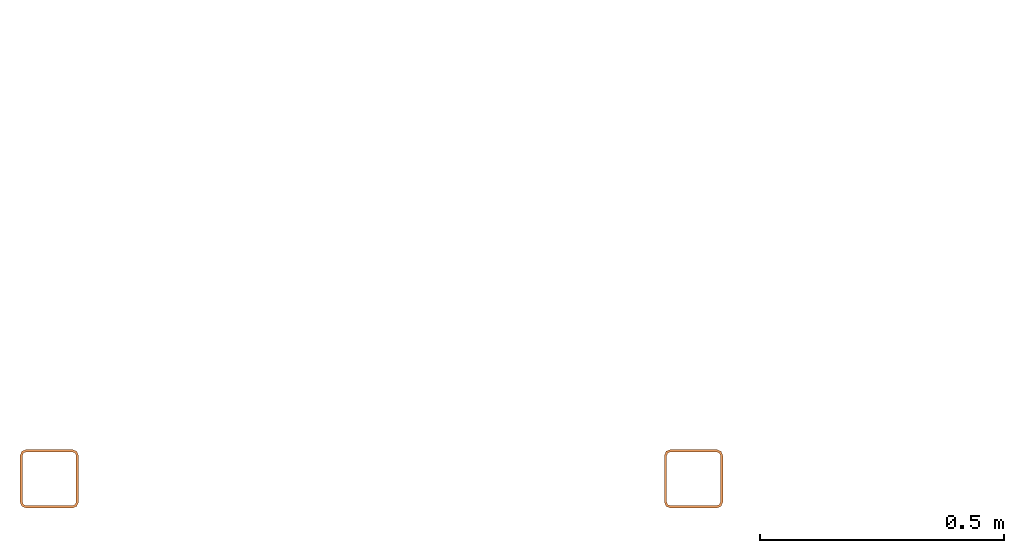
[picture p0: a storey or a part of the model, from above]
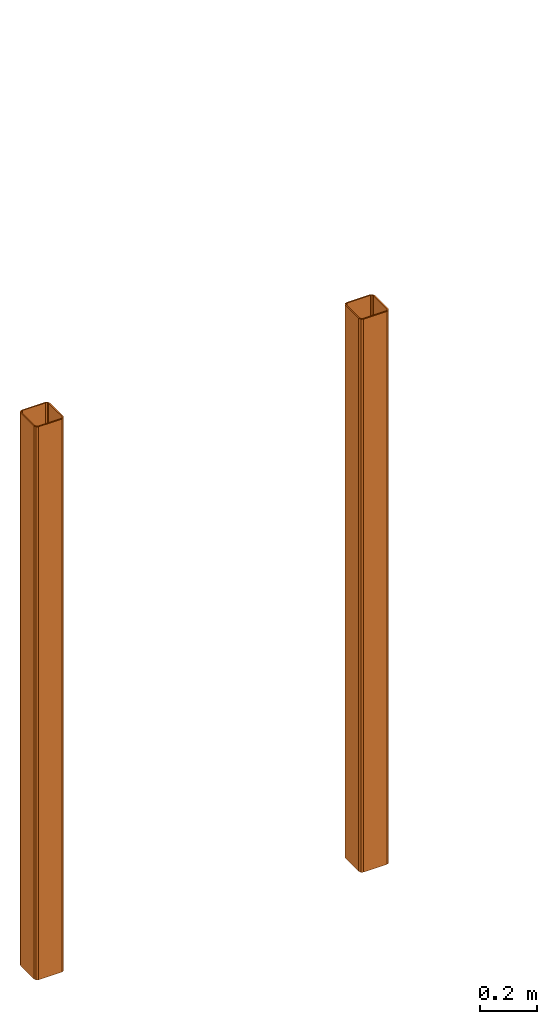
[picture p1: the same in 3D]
Properties of the parts of a building model (IFC2X3), part 1 of 7

# File
Description: ViewDefinition [CoordinationView_V2.0, SurfaceGeometryAddOnView, QuantityTakeOffAddOnView, SpaceBoundary2ndLevelAddOnView], Option [Elements to export: Visible elements (on all stories)], Option [Partial Structure Display: Entire Model], Option [IFC Domain: Custom], Option [Structural Function: All Elements], Option [Convert Grid elements: On], Option [Convert IFC Annotations and Archicad 2D elements: Off], Option [Convert 2D symbols of Doors and Windows: Off], Option [Export geometries that Participates in Collision Detection only: Off], Option [Split complex elements: Off], Option [Material Preservation: Explode all], Option [IFC Model position: Survey Point and Project Origin], Option [Curtain Wall export mode: Container Element], Option [Railing export mode: Single Element], Option [Stair export mode: Single Element], Option [Properties To Export: All properties], Option [Space containment: Off], Option [Geometry to type objects: Off], Option [Element Properties: Off], Option [Building Material Properties: Off], Option [Element Parameters: Off], Option [Component Parameters: Off], Option [IFC Base Quantities: On], Option [Door Window Parameters: Off], Option [IFC Space boundaries: On], Option [Archicad Zone Categories as IFC Space classification data: Off], Option [Element Classifications: On]
File name: C:\Users\Tarmo\Innopolis Insenerid OÜ\IPI-2406_Kuressaare Ametikooli õppekorpus - General\CDE\03. JAGATUD\03.6. Coordination model\Submodels\TUUL_PP_AR_9-01_v02_2025-01-06.ifc
Time: 2025-01-10T17:22:18
Author: Architect
Organization: Building Designer Office
Written by: DDS_IFC v3.0
Made in: IFC file generated by Graphisoft Archicad 27.0.0 INT FULL Windows version (IFC add-on version: 5060 INT FULL).
Authorization: The authorising person

# IfcSite, 43301:001:0844
RefLatitude: 58, 16, 38, 603000; RefLongitude: 22, 32, 58, 47000; RefElevation: 8650 mm
BaseQuantities - GrossPerimeter: 0 mm; GrossArea: 47243 m2
AR_Kinnistu - 015_Ehitatav-pindala: 0 m2; 010_Katastritunnus: 43301:001:0844; 020_Pindala: 47243 m2

# IfcBuilding, Kuressaare Ametikooli tuulikute mehaanikute õppekorpus
BaseQuantities - GrossFloorArea: 4647.95 m2
AR_Hoone - 035_Sprinkler: no; 706_Eripõlemiskoormus: 0; 703_Kasutajate-arv: 0; 055_Neto-ruumala: 0 m3; 050_Neto-pindala: 0 m2; 041_Sügavus: 0 mm; 707_Tuleohutusklass: TP1, TP2, TP3; 001_Nimetus: Kuressaare Ametikooli tuulikute mehaanikute õppekorpus; 030_Hoone-aadress: Kooli tee 7, Upa küla, Saaremaa vald, Saare maakond; 704_Kasutusotstarve: Kutseõppeasutuse õppehoone; 705_Kasutusotstarbe-kood: 12633; 700_EHR-kood: 106001153; 045_Hoonealune-pindala: 4167 m2; 702_ADS-OID: ME01729794; 701_ETAK-id: 188703; 040_Kõrgus: 9000 mm

# IfcBuildingStorey (5)
In: Kuressaare Ametikooli tuulikute mehaanikute õppekorpus
Name | Elevation (mm) | NetHeight (mm) = GrossHeight (mm) = Height (mm) | GrossFloorArea (m2) | 070_Maapealne | 065_Korruse-number | 060_Korruse-nimi | 710_Määrusejärgne-korrus
1.korrus | 0 | 4100 | 3425.05 | yes | 1 | 1.korrus | yes
Merepind | -8650 | 8650 | 0
2.korrus | 4100 | 3700 | 1071.13 | yes | 2 | 2.korrus | yes
Pööningukorrus | 7800 | 3500 | 151.772 | yes | 3 | Katus | no
Katuseplaan | 11300 | 3500 | 0

# IfcSpace: Kab. (6)
In: 2.korrus
InteriorOrExteriorSpace: INTERNAL; Classification: 1.21 IfcSpaceType (ruum) (IPI ÜBN)
AR_Ruum - 115_Kategooria: Kab.; 110_Tüüp: ootel; 125_Turvatsoon: -; 720_Köetav-pind: no; 721_Toatemperatuuriga-pind: no; 722_Eluruumi-number: ootel; 723_Mitteeluruumi-number: ootel
BaseQuantities - FinishFloorHeight: 0 mm
AC_Pset_RenovationAndPhasing - Renovation Status: New
Name | LongName = 100_Nimi | 105_Number | 120_Pindala (m2) = GrossFloorArea (m2) = GrossCeilingArea (m2) | Height (mm) = FinishCeilingHeight (mm) = ClearHeight (mm) | NetFloorArea (m2) = SpaceNetFloorAreaBOMA (m2) = SpaceUsableFloorAreaBOMA (m2) = NetCeilingArea (m2) | GrossWallArea (m2) | NetWallArea (m2) | GrossPerimeter (mm) = NetPerimeter (mm) | GrossVolume (m3) | NetVolume (m3)
214 | Juhtõp. | 214 | 15.5472 | 4832.72 | 15.5472 | 67.4028 | 53.6942 | 15787.1 | 75.1353 | 64.8385
213 | Õpet.töör. | 213 | 65.2246 | 5620.76 | 65.0646 | 126.323 | 91.2781 | 35727.6 | 366.612 | 196.593
212 | Proj.juht | 212 | 18.7481 | 4709.86 | 18.7481 | 55.9863 | 52.1281 | 17414.3 | 88.301 | 78.5045
203 | Rühmajuh.I | 203 | 11.839 | 5316.65 | 11.839 | 61.2238 | 51.4993 | 14292 | 62.9436 | 51.8169
204 | Rühmajuh. II | 204 | 11.839 | 5316.65 | 11.7326 | 59.816 | 51.0555 | 14292 | 62.9436 | 51.8169
205 | Sots.ped. | 205 | 11.839 | 5316.65 | 11.839 | 60.6815 | 50.957 | 14292 | 62.9436 | 51.8169

# IfcSpace: Klassid (12)
InteriorOrExteriorSpace: INTERNAL; Classification: 1.21 IfcSpaceType (ruum) (IPI ÜBN)
AR_Ruum - 115_Kategooria: Klassid; 110_Tüüp: ootel; 125_Turvatsoon: -; 720_Köetav-pind: no; 721_Toatemperatuuriga-pind: no; 722_Eluruumi-number: ootel; 723_Mitteeluruumi-number: ootel
AC_Pset_RenovationAndPhasing - Renovation Status: New
Name | In | LongName = 100_Nimi | 105_Number | 120_Pindala (m2) = GrossFloorArea (m2) = GrossCeilingArea (m2) | Height (mm) = FinishCeilingHeight (mm) = ClearHeight (mm) | FinishFloorHeight (mm) | NetFloorArea (m2) = SpaceNetFloorAreaBOMA (m2) = SpaceUsableFloorAreaBOMA (m2) = NetCeilingArea (m2) | GrossWallArea (m2) | NetWallArea (m2) | GrossPerimeter (mm) = NetPerimeter (mm) | GrossVolume (m3) | NetVolume (m3)
124 | 1.korrus | Ehituse õppet. | 124 | 128.364 | 3530 | 0 | 128.364 | 175.484 | 148.077 | 46438.7 | 453.124 | 453.124
136 | 1.korrus | Materj.õppet. | 136 | 209.933 | 3530 | 0 | 209.933 | 213.037 | 168.591 | 60294.5 | 741.062 | 741.062
133 | 1.korrus | Meh. ja hüdraulika õppet. | 133 | 169.978 | 3530 | 0 | 169.978 | 149.826 | 122.568 | 60117.8 | 600.021 | 600.021
227 | 2.korrus | Elektri õppet. | 227 | 174.42 | 3080 | 0 | 174.068 | 162.623 | 118.572 | 54042.9 | 537.214 | 537.214
221 | 2.korrus | Arvutiklass I | 221 | 48.4192 | 3160 | 100 | 48.4192 | 95.3215 | 74.7578 | 27850.1 | 153.005 | 153.005
219 | 2.korrus | Arvutiklass II | 219 | 48.887 | 5507.49 | 100 | 48.887 | 106.767 | 95.2312 | 27986.1 | 269.245 | 221.758
218 | 2.korrus | Õppeklass I | 218 | 48.9607 | 5607.49 | 0 | 48.9607 | 115.023 | 103.487 | 28006.4 | 274.546 | 226.989
216 | 2.korrus | MF projektiõppeklass | 216 | 69.0252 | 5607.49 | 0 | 69.0252 | 134.472 | 113.37 | 33588.2 | 387.058 | 319.853
217 | 2.korrus | Õppeklass II | 217 | 47.8731 | 5607.49 | 0 | 47.8731 | 113.927 | 104.08 | 27706.4 | 268.448 | 221.947
202 | 2.korrus | Rühmatöö r.1 | 202 | 17.0366 | 5316.65 | 0 | 17.0366 | 45.8756 | 34.177 | 16623.6 | 90.5779 | 74.184
222 | 2.korrus | CNC ruum | 222 | 24.6906 | 3160 | 100 | 24.5306 | 65.9562 | 57.5719 | 20273 | 78.0223 | 78.0223
215 | 2.korrus | Rühmatöö r.2 | 215 | 31.0674 | 3260 | 0 | 31.0672 | 53.4095 | 40.4372 | 23806.7 | 101.28 | 101.28

# IfcSpace: generic (2)
In: 1.korrus
LongName: Ruum?; InteriorOrExteriorSpace: INTERNAL; Classification: 1.21 IfcSpaceType (ruum) (IPI ÜBN)
AR_Ruum - 100_Nimi: Ruum?; 105_Number: XXX; 115_Kategooria: generic; 110_Tüüp: Üüritav pind; 125_Turvatsoon: -; 720_Köetav-pind: yes; 721_Toatemperatuuriga-pind: yes; 722_Eluruumi-number: -; 723_Mitteeluruumi-number: ootel
AC_Pset_RenovationAndPhasing - Renovation Status: Existing
BaseQuantities - FinishFloorHeight: 0 mm
Name | 120_Pindala (m2) = GrossFloorArea (m2) = NetFloorArea (m2) = SpaceNetFloorAreaBOMA (m2) = SpaceUsableFloorAreaBOMA (m2) = GrossCeilingArea (m2) = NetCeilingArea (m2) | Height (mm) = FinishCeilingHeight (mm) = ClearHeight (mm) | GrossWallArea (m2) | NetWallArea (m2) | GrossPerimeter (mm) = NetPerimeter (mm) | GrossVolume (m3) = NetVolume (m3)
XXX | 2.66552 | 2220 | 13.4844 | 11.9864 | 6590.37 | 5.91745
XXX | 1.59067 | 2300 | 13.2955 | 9.93989 | 5143.43 | 3.65853

# IfcSpace: klass, 145
In: 1.korrus
LongName: Õppeklass; InteriorOrExteriorSpace: INTERNAL; Classification: 1.21 IfcSpaceType (ruum) (IPI ÜBN)
AR_Ruum - 100_Nimi: Õppeklass; 105_Number: 145; 115_Kategooria: klass; 110_Tüüp: Üüritav pind; 120_Pindala: 75.8065 m2; 125_Turvatsoon: -; 720_Köetav-pind: yes; 721_Toatemperatuuriga-pind: yes; 722_Eluruumi-number: -; 723_Mitteeluruumi-number: ootel
AC_Pset_RenovationAndPhasing - Renovation Status: Existing
BaseQuantities - Height: 2760 mm; FinishCeilingHeight: 2760 mm; FinishFloorHeight: 0 mm; ClearHeight: 2760 mm; GrossFloorArea: 75.8065 m2; NetFloorArea: 75.8065 m2; SpaceNetFloorAreaBOMA: 75.8065 m2; SpaceUsableFloorAreaBOMA: 75.8065 m2; GrossCeilingArea: 75.8065 m2; NetCeilingArea: 75.8065 m2; GrossWallArea: 101.496 m2; NetWallArea: 79.8456 m2; GrossPerimeter: 39606.3 mm; NetPerimeter: 39606.3 mm; GrossVolume: 209.226 m3; NetVolume: 209.226 m3

# IfcSpace: ladu (5)
In: 1.korrus
InteriorOrExteriorSpace: INTERNAL; Classification: 1.21 IfcSpaceType (ruum) (IPI ÜBN)
AR_Ruum - 115_Kategooria: ladu; 110_Tüüp: Üüritav pind; 125_Turvatsoon: -; 720_Köetav-pind: yes; 721_Toatemperatuuriga-pind: yes; 722_Eluruumi-number: -; 723_Mitteeluruumi-number: ootel
AC_Pset_RenovationAndPhasing - Renovation Status: Existing
BaseQuantities - FinishFloorHeight: 0 mm
Name | LongName = 100_Nimi | 105_Number | 120_Pindala (m2) = GrossFloorArea (m2) = NetFloorArea (m2) = SpaceNetFloorAreaBOMA (m2) = SpaceUsableFloorAreaBOMA (m2) = GrossCeilingArea (m2) = NetCeilingArea (m2) | Height (mm) = FinishCeilingHeight (mm) = ClearHeight (mm) | GrossWallArea (m2) | NetWallArea (m2) | GrossPerimeter (mm) = NetPerimeter (mm) | GrossVolume (m3) | NetVolume (m3)
XXX | Ladu? | XXX | 15.1071 | 4030 | 54.9288 | 47.1488 | 16928.5 | 60.8818 | 44.7367
XXX | Vormide ladu? | XXX | 50.5027 | 4030 | 95.6878 | 82.443 | 28913.5 | 203.526 | 149.241
147 | Ladu | 147 | 41.6107 | 3410 | 84.8329 | 72.6079 | 26062.7 | 141.892 | 141.892
XXX | Kemikaalide ladu? | XXX | 9.49683 | 4030 | 35.4408 | 33.4038 | 12633.1 | 38.2722 | 27.1318
1 163 | Saal | 1 163 | 121.686 | 2580 | 40.6575 | 35.7675 | 51884 | 313.95 | 313.95

# IfcSpace: liftiruum (2)
LongName: Lift; InteriorOrExteriorSpace: INTERNAL; Classification: 1.21 IfcSpaceType (ruum) (IPI ÜBN)
AC_Pset_RenovationAndPhasing - Renovation Status: New
BaseQuantities - FinishFloorHeight: 0 mm
AR_Ruum - 100_Nimi: Lift; 115_Kategooria: liftiruum; 110_Tüüp: ootel; 125_Turvatsoon: -; 720_Köetav-pind: no; 721_Toatemperatuuriga-pind: no; 722_Eluruumi-number: ootel; 723_Mitteeluruumi-number: ootel
Name | In | Height (mm) = FinishCeilingHeight (mm) = ClearHeight (mm) | GrossFloorArea (m2) = NetFloorArea (m2) = SpaceNetFloorAreaBOMA (m2) = SpaceUsableFloorAreaBOMA (m2) = GrossCeilingArea (m2) = NetCeilingArea (m2) = 120_Pindala (m2) | GrossWallArea (m2) | NetWallArea (m2) | GrossPerimeter (mm) = NetPerimeter (mm) | GrossVolume (m3) = NetVolume (m3) | 105_Number
134 | 1.korrus | 3530 | 2.1987 | 5.60755 | 5.60755 | 5946.03 | 7.76142 | 134
229 | 2.korrus | 3260 | 2.1942 | 15.3783 | 9.92735 | 5940 | 7.15309 | 229

# IfcSpace: muud abiruumid (17)
InteriorOrExteriorSpace: INTERNAL; Classification: 1.21 IfcSpaceType (ruum) (IPI ÜBN)
AR_Ruum - 115_Kategooria: muud abiruumid; 110_Tüüp: ootel; 125_Turvatsoon: -; 720_Köetav-pind: no; 721_Toatemperatuuriga-pind: no; 722_Eluruumi-number: ootel; 723_Mitteeluruumi-number: ootel
AC_Pset_RenovationAndPhasing - Renovation Status: New
Name | In | LongName = 100_Nimi | 105_Number | 120_Pindala (m2) = GrossFloorArea (m2) = NetFloorArea (m2) = SpaceNetFloorAreaBOMA (m2) = SpaceUsableFloorAreaBOMA (m2) = GrossCeilingArea (m2) = NetCeilingArea (m2) | Height (mm) = FinishCeilingHeight (mm) = ClearHeight (mm) | FinishFloorHeight (mm) | GrossWallArea (m2) | NetWallArea (m2) | GrossPerimeter (mm) = NetPerimeter (mm) | GrossVolume (m3) | NetVolume (m3)
128 | 1.korrus | Riietusr. | 128 | 12.7353 | 3530 | 0 | 36.8075 | 34.8874 | 14879.5 | 44.9558 | 44.9558
141 | 1.korrus | Riietusr. | 141 | 10.806 | 3410 | 100 | 42.1717 | 38.5425 | 13241.5 | 36.8483 | 36.8483
142 | 1.korrus | Ladu | 142 | 3.26359 | 3530 | 0 | 26.255 | 24.1239 | 7437.67 | 11.5205 | 11.5205
126 | 1.korrus | Dush | 126 | 1.85755 | 3530 | 0 | 25.5378 | 22.1196 | 5457.77 | 6.55714 | 6.55714
132 | 1.korrus | Inva WC-dush | 132 | 5.7189 | 3530 | 0 | 56.8181 | 52.5559 | 9575.12 | 20.1877 | 20.1877
138 | 1.korrus | Riietusr. | 138 | 10.8131 | 3410 | 0 | 52.5033 | 38.1641 | 13281.5 | 36.8728 | 36.8728
131 | 1.korrus | Riietusr. | 131 | 12.7361 | 3530 | 0 | 35.6885 | 30.3502 | 14880.1 | 44.9584 | 44.9584
125 | 1.korrus | Riietusr. | 125 | 12.7359 | 3530 | 0 | 26.7574 | 21.4191 | 14880 | 44.9577 | 44.9577
211 | 2.korrus | Riietusr. | 211 | 22.0602 | 5699.93 | 0 | 77.5498 | 72.0005 | 18925.9 | 125.742 | 97.4836
207 | 2.korrus | Riietusr. | 207 | 11.0927 | 5316.65 | 0 | 55.0914 | 49.5421 | 14025.8 | 58.9758 | 43.5537
206 | 2.korrus | Pesur. | 206 | 4.07837 | 4545.32 | 0 | 50.5629 | 47.1447 | 8235.76 | 18.5375 | 16.4192
225 | 2.korrus | WC | 225 | 1.30192 | 3260 | 0 | 25.7928 | 22.3746 | 4611.35 | 4.24425 | 4.24425
224 | 2.korrus | WC | 224 | 1.1583 | 3260 | 0 | 24.1716 | 20.7534 | 4306 | 3.77606 | 3.77606
223 | 2.korrus | WC | 223 | 1.15382 | 3160 | 100 | 23.598 | 20.1798 | 4330.07 | 3.64608 | 3.64608
210 | 2.korrus | Pesur. | 210 | 4.94948 | 3290 | 0 | 51.9261 | 48.5079 | 9079.96 | 16.2838 | 16.2838
208 | 2.korrus | WC | 208 | 1.42991 | 3290 | 0 | 28.4622 | 25.044 | 4977.57 | 4.7044 | 4.7044
209 | 2.korrus | WC | 209 | 1.96683 | 3290 | 0 | 32.4987 | 29.0805 | 5678.04 | 6.47086 | 6.47086

# IfcSpace: muud üldruumid (13)
In: 1.korrus
InteriorOrExteriorSpace: INTERNAL; Classification: 1.21 IfcSpaceType (ruum) (IPI ÜBN)
AR_Ruum - 115_Kategooria: muud üldruumid; 110_Tüüp: ootel; 125_Turvatsoon: -; 720_Köetav-pind: no; 721_Toatemperatuuriga-pind: no; 722_Eluruumi-number: ootel; 723_Mitteeluruumi-number: ootel
AC_Pset_RenovationAndPhasing - Renovation Status: New
BaseQuantities - FinishFloorHeight: 0 mm
Name | LongName = 100_Nimi | 105_Number | 120_Pindala (m2) = GrossFloorArea (m2) = GrossCeilingArea (m2) | Height (mm) = FinishCeilingHeight (mm) = ClearHeight (mm) | NetFloorArea (m2) = SpaceNetFloorAreaBOMA (m2) = SpaceUsableFloorAreaBOMA (m2) = NetCeilingArea (m2) | GrossWallArea (m2) | NetWallArea (m2) | GrossPerimeter (mm) = NetPerimeter (mm) | GrossVolume (m3) = NetVolume (m3)
120 | WC | 120 | 1.25064 | 3530 | 1.25064 | 26.3842 | 22.9682 | 4579.2 | 4.41476
123 | WC | 123 | 1.1978 | 3530 | 1.1978 | 26.0476 | 22.6294 | 4380 | 4.22824
118 | Riietusr. | 118 | 10.3238 | 3530 | 10.3238 | 21.6171 | 17.7769 | 12899.2 | 36.4431
139 | WC | 139 | 1.37287 | 3410 | 1.37287 | 20.6493 | 18.9402 | 4850.83 | 4.68149
127 | WC | 127 | 1.20236 | 3530 | 1.20236 | 15.8877 | 12.4695 | 4460.28 | 4.24433
119 | Dush | 119 | 1.6929 | 3530 | 1.6929 | 16.9231 | 13.5049 | 5481.91 | 5.97593
121 | WC | 121 | 1.243 | 3530 | 1.24284 | 21.4745 | 18.0563 | 4460 | 4.38779
117 | Kor.v | 117 | 8.43403 | 3530 | 8.43403 | 43.1265 | 40.9954 | 11819.2 | 29.7721
140 | WC | 140 | 1.41962 | 3410 | 1.41962 | 20.1099 | 18.4008 | 5031.79 | 4.84091
135 | WC | 135 | 1.29282 | 3530 | 1.29282 | 8.12124 | 8.12124 | 4780.43 | 4.56366
122 | WC | 122 | 1.1978 | 3530 | 1.1978 | 25.9956 | 22.5774 | 4380 | 4.22823
129 | Dush | 129 | 1.859 | 3530 | 1.859 | 33.5527 | 30.1345 | 5460.01 | 6.56228
130 | WC | 130 | 1.25134 | 3530 | 1.25134 | 27.017 | 23.5988 | 5536.07 | 4.41722

# IfcSpace: pesuruum (2)
In: 1.korrus
LongName: Pesuruum; InteriorOrExteriorSpace: INTERNAL; Classification: 1.21 IfcSpaceType (ruum) (IPI ÜBN)
AR_Ruum - 100_Nimi: Pesuruum; 105_Number: XXX; 115_Kategooria: pesuruum; 110_Tüüp: Üüritav pind; 125_Turvatsoon: -; 720_Köetav-pind: yes; 721_Toatemperatuuriga-pind: yes; 722_Eluruumi-number: -; 723_Mitteeluruumi-number: ootel
BaseQuantities - Height: 4030 mm; FinishCeilingHeight: 4030 mm; FinishFloorHeight: 0 mm; ClearHeight: 4030 mm
AC_Pset_RenovationAndPhasing - Renovation Status: Existing
Name | 120_Pindala (m2) = GrossFloorArea (m2) = NetFloorArea (m2) = SpaceNetFloorAreaBOMA (m2) = SpaceUsableFloorAreaBOMA (m2) = GrossCeilingArea (m2) = NetCeilingArea (m2) | GrossWallArea (m2) | NetWallArea (m2) | GrossPerimeter (mm) = NetPerimeter (mm) | GrossVolume (m3) | NetVolume (m3)
XXX | 5.21012 | 36.7853 | 35.3034 | 9137.94 | 20.9968 | 15.9319
XXX | 4.76055 | 25.8182 | 24.3482 | 8759.84 | 19.185 | 13.5748

# IfcSpace: riietusruum (2)
In: 1.korrus
LongName: Riietusruum; InteriorOrExteriorSpace: INTERNAL; Classification: 1.21 IfcSpaceType (ruum) (IPI ÜBN)
AR_Ruum - 100_Nimi: Riietusruum; 105_Number: XXX; 115_Kategooria: riietusruum; 110_Tüüp: Üüritav pind; 125_Turvatsoon: -; 720_Köetav-pind: yes; 721_Toatemperatuuriga-pind: yes; 722_Eluruumi-number: -; 723_Mitteeluruumi-number: ootel
BaseQuantities - Height: 4030 mm; FinishCeilingHeight: 4030 mm; FinishFloorHeight: 0 mm; ClearHeight: 4030 mm
AC_Pset_RenovationAndPhasing - Renovation Status: Existing
Name | 120_Pindala (m2) = GrossFloorArea (m2) = NetFloorArea (m2) = SpaceNetFloorAreaBOMA (m2) = SpaceUsableFloorAreaBOMA (m2) = GrossCeilingArea (m2) = NetCeilingArea (m2) | GrossWallArea (m2) | NetWallArea (m2) | GrossPerimeter (mm) = NetPerimeter (mm) | GrossVolume (m3) | NetVolume (m3)
XXX | 16.6922 | 62.8548 | 51.759 | 17465.3 | 67.2697 | 49.375
XXX | 15.8652 | 60.781 | 50.8333 | 17185.3 | 63.9366 | 46.9065

# IfcSpace: tehnopind (12)
InteriorOrExteriorSpace: INTERNAL; Classification: 1.21 IfcSpaceType (ruum) (IPI ÜBN)
AR_Ruum - 115_Kategooria: tehnopind; 125_Turvatsoon: -
Name | In | LongName = 100_Nimi | Renovation Status | Height (mm) = FinishCeilingHeight (mm) = ClearHeight (mm) | FinishFloorHeight (mm) | GrossFloorArea (m2) = GrossCeilingArea (m2) = 120_Pindala (m2) | NetFloorArea (m2) = SpaceNetFloorAreaBOMA (m2) = SpaceUsableFloorAreaBOMA (m2) = NetCeilingArea (m2) | GrossWallArea (m2) | NetWallArea (m2) | GrossPerimeter (mm) = NetPerimeter (mm) | GrossVolume (m3) | NetVolume (m3) | 105_Number | 110_Tüüp | 720_Köetav-pind | 721_Toatemperatuuriga-pind | 722_Eluruumi-number | 723_Mitteeluruumi-number
144 | 1.korrus | Kilbir. | New | 3530 | 0 | 0.784378 | 0.784378 | 13.914 | 10.9389 | 3943.49 | 2.76886 | 2.76886 | 144 | ootel | no | no | ootel | ootel
XXX | 1.korrus | Tehnoruum? | Existing | 5090 | 0 | 175.284 | 175.284 | 197.24 | 174.358 | 53375.1 | 892.198 | 891.385 | XXX | Üüritav pind | yes | yes | - | ootel
146 | 1.korrus | Tehnoruum | Existing | 3410 | 0 | 6.83481 | 6.83481 | 34.1427 | 31.8767 | 10457.5 | 23.3067 | 23.3067 | 146 | Tehnopind | yes | no | - | -
XXX | 1.korrus | Peakilbiruum? | Existing | 4715 | 0 | 6.74684 | 6.74684 | 46.4984 | 41.2838 | 11053.2 | 31.8114 | 31.8114 | XXX | Üüritav pind | yes | yes | - | ootel
1 167 | 1.korrus | Müüritöö labor | Existing | 3410 | 0 | 211.744 | 211.744 | 132.951 | 117.054 | 59568 | 722.047 | 722.047 | 1 167 | Tehnopind | yes | no | - | -
1 164 | 1.korrus | Tehnoruum | Existing | 3410 | 0 | 8.68525 | 8.68525 | 39.0038 | 36.573 | 13430.4 | 29.6167 | 29.6167 | 1 164 | Tehnopind | yes | no | - | -
1 165 | 1.korrus | Ladu | Existing | 3410 | 0 | 5.07743 | 5.07743 | 25.1345 | 20.8229 | 9303.1 | 17.3141 | 17.3141 | 1 165 | Tehnopind | yes | no | - | -
1 166 | 1.korrus | Köök | Existing | 3410 | 0 | 38.9431 | 38.9431 | 43.8037 | 41.8993 | 26649.4 | 132.796 | 132.796 | 1 166 | Tehnopind | yes | no | - | -
226 | 2.korrus | Server | New | 3260 | 0 | 4.26585 | 4.26585 | 26.9308 | 24.7997 | 8499.67 | 13.9067 | 13.9067 | 226 | ootel | no | no | ootel | ootel
231 | 2.korrus | Kilbir. | New | 3160 | 100 | 1.24849 | 1.24849 | 14.6831 | 11.7291 | 4602.26 | 3.94523 | 3.94523 | 231 | ootel | no | no | ootel | ootel
230 | 2.korrus | Kilbir. | New | 3160 | 100 | 0.60466 | 0.60466 | 11.0929 | 8.34936 | 3469.26 | 1.91073 | 1.91073 | 230 | ootel | no | no | ootel | ootel
301 | Pööningukorrus | Vent.kamber | New | 4178.69 | 0 | 149.934 | 146.324 | 96.6577 | 93.9685 | 60096.6 | 626.529 | 23.3877 | 301 | ootel | no | no | ootel | ootel

# IfcSpace: töökoda (12)
In: 1.korrus
InteriorOrExteriorSpace: INTERNAL; Classification: 1.21 IfcSpaceType (ruum) (IPI ÜBN)
AR_Ruum - 115_Kategooria: töökoda; 110_Tüüp: Üüritav pind; 125_Turvatsoon: -; 720_Köetav-pind: yes; 721_Toatemperatuuriga-pind: yes; 722_Eluruumi-number: -; 723_Mitteeluruumi-number: ootel
AC_Pset_RenovationAndPhasing - Renovation Status: Existing
BaseQuantities - FinishFloorHeight: 0 mm
Name | LongName = 100_Nimi | 105_Number | 120_Pindala (m2) = GrossFloorArea (m2) = GrossCeilingArea (m2) | Height (mm) = FinishCeilingHeight (mm) = ClearHeight (mm) | NetFloorArea (m2) = SpaceNetFloorAreaBOMA (m2) = SpaceUsableFloorAreaBOMA (m2) = NetCeilingArea (m2) | GrossWallArea (m2) | NetWallArea (m2) | GrossPerimeter (mm) = NetPerimeter (mm) | GrossVolume (m3) | NetVolume (m3)
153 | Väikemasinad | 153 | 239.484 | 5090 | 239.484 | 241.372 | 187.262 | 62514.9 | 1218.97 | 1217.82
137 | Masinasaal 3 | 137 | 170.343 | 6800 | 170.183 | 286.734 | 247.518 | 58894.7 | 1158.34 | 1157.35
XXX | Kütteladu? | XXX | 60.1347 | 4330 | 55.5488 | 99.0741 | 97.6981 | 33939.8 | 260.383 | 137.303
143 | Plastpaadiehitus | 143 | 91.8267 | 4030 | 91.8267 | 157.937 | 124.337 | 46338 | 370.062 | 271.988
XXX | Plaatmaterjalide ladu | XXX | 73.6586 | 3700 | 73.6586 | 69.5313 | 63.5904 | 36753.7 | 272.537 | 192.568
139 | Puitpaadiehitus | 139 | 83.8663 | 3700 | 83.8663 | 75.9015 | 59.7954 | 40210 | 310.305 | 219.541
148 | Masinasaal 1 | 148 | 53.7029 | 3700 | 53.7029 | 59.3089 | 55.1905 | 29996.9 | 198.701 | 140.248
149 | Masinasaal 2 | 149 | 172.612 | 6800 | 172.392 | 229.897 | 197.833 | 55076.3 | 1173.76 | 1172.4
141 | Paadiehhitus | 141 | 85.5175 | 4715 | 85.4573 | 168.101 | 144.414 | 39139.3 | 403.215 | 402.978
XXX | Tööpinkide ruum? | XXX | 60.1021 | 4030 | 60.1021 | 107.219 | 92.2897 | 32164 | 242.211 | 177.881
XXX | Viimistlusruum? | XXX | 69.237 | 4715 | 68.9426 | 153.983 | 130.612 | 33870.4 | 326.453 | 325.345
147 | Autoremont | 147 | 289.231 | 5090 | 289.023 | 316.431 | 255.66 | 74427.2 | 1472.19 | 1471.31

# IfcSpace: tööruum (2)
In: 1.korrus
InteriorOrExteriorSpace: INTERNAL; Classification: 1.21 IfcSpaceType (ruum) (IPI ÜBN)
AR_Ruum - 105_Number: XXX; 115_Kategooria: tööruum; 110_Tüüp: Üüritav pind; 125_Turvatsoon: -; 720_Köetav-pind: yes; 721_Toatemperatuuriga-pind: yes; 722_Eluruumi-number: -; 723_Mitteeluruumi-number: ootel
AC_Pset_RenovationAndPhasing - Renovation Status: Existing
BaseQuantities - FinishFloorHeight: 0 mm
Name | LongName = 100_Nimi | 120_Pindala (m2) = GrossFloorArea (m2) = GrossCeilingArea (m2) | Height (mm) = FinishCeilingHeight (mm) = ClearHeight (mm) | NetFloorArea (m2) = SpaceNetFloorAreaBOMA (m2) = SpaceUsableFloorAreaBOMA (m2) = NetCeilingArea (m2) | GrossWallArea (m2) | NetWallArea (m2) | GrossPerimeter (mm) = NetPerimeter (mm) | GrossVolume (m3) | NetVolume (m3)
XXX | Ruum? | 6.45873 | 2430 | 6.45873 | 24.6269 | 16.3229 | 11384.5 | 15.6947 | 15.6947
XXX | Õpetajaruum? | 10.6211 | 4715 | 10.6121 | 63.6281 | 57.8863 | 13808.7 | 50.0784 | 50.0448

# IfcSpace: wc (2)
In: 1.korrus
LongName: WC; InteriorOrExteriorSpace: INTERNAL; Classification: 1.21 IfcSpaceType (ruum) (IPI ÜBN)
AR_Ruum - 100_Nimi: WC; 105_Number: XXX; 115_Kategooria: wc; 110_Tüüp: Üüritav pind; 125_Turvatsoon: -; 720_Köetav-pind: yes; 721_Toatemperatuuriga-pind: yes; 722_Eluruumi-number: -; 723_Mitteeluruumi-number: ootel
AC_Pset_RenovationAndPhasing - Renovation Status: Existing
BaseQuantities - Height: 4030 mm; FinishCeilingHeight: 4030 mm; FinishFloorHeight: 0 mm; ClearHeight: 4030 mm
Name | 120_Pindala (m2) = GrossFloorArea (m2) = NetFloorArea (m2) = SpaceNetFloorAreaBOMA (m2) = SpaceUsableFloorAreaBOMA (m2) = GrossCeilingArea (m2) = NetCeilingArea (m2) | GrossWallArea (m2) | NetWallArea (m2) | GrossPerimeter (mm) = NetPerimeter (mm) | GrossVolume (m3) | NetVolume (m3)
XXX | 1.58356 | 14.9616 | 13.4286 | 5067.78 | 6.38173 | 4.67513
XXX | 1.56665 | 14.8894 | 13.3564 | 5043.87 | 6.31361 | 4.62473

# IfcSpace: ühendusteed (5)
InteriorOrExteriorSpace: INTERNAL; Classification: 1.21 IfcSpaceType (ruum) (IPI ÜBN)
AR_Ruum - 115_Kategooria: ühendusteed; 110_Tüüp: ootel; 125_Turvatsoon: -; 720_Köetav-pind: no; 721_Toatemperatuuriga-pind: no; 722_Eluruumi-number: ootel; 723_Mitteeluruumi-number: ootel
AC_Pset_RenovationAndPhasing - Renovation Status: New
BaseQuantities - FinishFloorHeight: 0 mm
Name | In | LongName = 100_Nimi | 105_Number | 120_Pindala (m2) = GrossFloorArea (m2) = GrossCeilingArea (m2) | Height (mm) = FinishCeilingHeight (mm) = ClearHeight (mm) | NetFloorArea (m2) = SpaceNetFloorAreaBOMA (m2) = SpaceUsableFloorAreaBOMA (m2) = NetCeilingArea (m2) | GrossWallArea (m2) | NetWallArea (m2) | GrossPerimeter (mm) = NetPerimeter (mm) | GrossVolume (m3) | NetVolume (m3)
137 | 1.korrus | Koridor | 137 | 14.5592 | 3410 | 14.5592 | 69.2574 | 53.2185 | 18559.2 | 49.6469 | 49.6469
116 | 1.korrus | Fuajee | 116 | 231.348 | 3530 | 230.509 | 100.487 | 83.8356 | 89004.3 | 816.657 | 816.657
143 | 1.korrus | Trepik. | 143 | 14.0028 | 3530 | 14.0028 | 0.609591 | 0.609591 | 18689.7 | 49.4299 | 49.4299
228 | 2.korrus | Trepik. | 228 | 27.0725 | 4291.63 | 27.0725 | 27.9893 | 23.1579 | 32967.5 | 116.185 | 107.704
220 | 2.korrus | Fuajee | 220 | 215.913 | 5135.77 | 215.556 | 278.205 | 175.312 | 102105 | 1108.88 | 738.096

# IfcBeam: GENEERILINE - KONSTRUKTRIOON 180 x 460
In: 1.korrus
Classification: 1.01 IfcBeamType (tala) (IPI ÜBN); Material: GENEERILINE - KONSTRUKTRIOON
AR_ÜLD - 001_Nimetus: Olemasolev tala
AC_Pset_RenovationAndPhasing - Renovation Status: Existing
BaseQuantities - NetSurfaceAreaExtrudedSides: 25.7153 m2; Length: 20090.1 mm; Width: 180 mm; Depth: 460 mm; CrossSectionArea: 0.0828 m2; OuterSurfaceArea: 25.7153 m2; TotalSurfaceArea: 25.8809 m2; GrossSurfaceArea: 25.8809 m2; GrossVolume: 1.66346 m3; NetSurfaceArea: 25.8809 m2; NetVolume: 1.66346 m3

# IfcBeam: GENEERILINE - KONSTRUKTRIOON 200 x 500 (18)
In: Pööningukorrus
Classification: 1.01 IfcBeamType (tala) (IPI ÜBN); Material: GENEERILINE - KONSTRUKTRIOON
AR_ÜLD - 001_Nimetus: Liimpuit tala
AC_Pset_RenovationAndPhasing - Renovation Status: New
BaseQuantities - Width: 200 mm; Depth: 500 mm; CrossSectionArea: 0.1 m2
Name | NetSurfaceAreaExtrudedSides (m2) = OuterSurfaceArea (m2) | Length (mm) | TotalSurfaceArea (m2) = GrossSurfaceArea (m2) = NetSurfaceArea (m2) | GrossVolume (m3) = NetVolume (m3)
2 x Katuslae LP tala | 6.37731 | 4689.19 | 6.57731 | 0.455522
3 x Katuslae LP tala | 6.3918 | 4699.54 | 6.5918 | 0.456557
3 x Katuslae LP tala | 6.39181 | 4699.55 | 6.59181 | 0.456558
6 x Katuslae LP tala | 10.6895 | 7769.35 | 10.8895 | 0.763538
3 x Katuslae LP tala | 10.7982 | 7847 | 10.9982 | 0.771302
Katuslae LP tala | 10.5084 | 7639.94 | 10.7084 | 0.750597

# IfcBeam: GENEERILINE - KONSTRUKTRIOON 200 x 550
In: 1.korrus
Classification: 1.01 IfcBeamType (tala) (IPI ÜBN); Material: GENEERILINE - KONSTRUKTRIOON
AC_Pset_RenovationAndPhasing - Renovation Status: Existing
AR_ÜLD - 001_Nimetus: Olemasolev tala
BaseQuantities - NetSurfaceAreaExtrudedSides: 27.088 m2; Length: 18058.7 mm; Width: 200 mm; Depth: 550 mm; CrossSectionArea: 0.11 m2; OuterSurfaceArea: 27.088 m2; TotalSurfaceArea: 27.308 m2; GrossSurfaceArea: 27.308 m2; GrossVolume: 1.98645 m3; NetSurfaceArea: 27.308 m2; NetVolume: 1.98645 m3

# IfcBeam: GENEERILINE - KONSTRUKTRIOON 45 x 120, Katuslae LP tala
In: 1.korrus
Classification: 1.01 IfcBeamType (tala) (IPI ÜBN); Material: GENEERILINE - KONSTRUKTRIOON
AR_ÜLD - 001_Nimetus: ootel
AC_Pset_RenovationAndPhasing - Renovation Status: Existing
BaseQuantities - NetSurfaceAreaExtrudedSides: 0.825503 m2; Length: 2501.52 mm; Width: 45 mm; Depth: 120 mm; CrossSectionArea: 0.0054 m2; OuterSurfaceArea: 0.825503 m2; TotalSurfaceArea: 0.836303 m2; GrossSurfaceArea: 0.836303 m2; GrossVolume: 0.0135082 m3; NetSurfaceArea: 0.836303 m2; NetVolume: 0.0135082 m3

# IfcBeam: GENEERILINE - KONSTRUKTRIOON 500 x 310
In: 1.korrus
Classification: 1.01 IfcBeamType (tala) (IPI ÜBN); Material: GENEERILINE - KONSTRUKTRIOON
AR_ÜLD - 001_Nimetus: Olemasolev tala
AC_Pset_RenovationAndPhasing - Renovation Status: Existing
BaseQuantities - NetSurfaceAreaExtrudedSides: 11.1468 m2; Length: 6880.93 mm; Width: 500 mm; Depth: 310 mm; CrossSectionArea: 0.155 m2; OuterSurfaceArea: 11.1468 m2; TotalSurfaceArea: 11.4568 m2; GrossSurfaceArea: 11.4568 m2; GrossVolume: 1.06654 m3; NetSurfaceArea: 11.4568 m2; NetVolume: 1.0665 m3

# IfcBeam: GENEERILINE - KONSTRUKTRIOON 500 x 650
In: 1.korrus
Classification: 1.01 IfcBeamType (tala) (IPI ÜBN); Material: GENEERILINE - KONSTRUKTRIOON
AR_ÜLD - 001_Nimetus: Olemasolev tala
BaseQuantities - NetSurfaceAreaExtrudedSides: 15.4142 m2; Length: 7057.83 mm; Width: 500 mm; Depth: 650 mm; CrossSectionArea: 0.325 m2; OuterSurfaceArea: 15.4142 m2; TotalSurfaceArea: 16.0642 m2; GrossSurfaceArea: 16.0642 m2; GrossVolume: 2.2938 m3; NetSurfaceArea: 16.0642 m2; NetVolume: 2.21272 m3
AC_Pset_RenovationAndPhasing - Renovation Status: Existing

# IfcBeam: IFC Footing Extruded (16)
Classification: 1.01 IfcBeamType (tala) (IPI ÜBN); Material: STEEL/S355
Tekla Common - Phase: 1; Class: 16
EK_Vundament - 135_Ruumala: 0 m3; 105_Tugevusklass: S355; 001_Nimetus: RAAM
AR_ÜLD - 001_Nimetus: Tala
AC_Pset_RenovationAndPhasing - Renovation Status: New
Name | In | Description = 003_Ristlõige | BaseQuantities, Length (mm) | OuterSurfaceArea (m2) = GrossSurfaceArea (m2) | CrossSectionArea (m2) | NetVolume (m3) | GrossVolume (m3) | NetWeight (kg) | GrossWeight (kg) | BaseQuantities, Width (mm) = Tekla Quantity, Width (mm) | BaseQuantities, Height (mm) = Tekla Quantity, Height (mm) | Bottom elevation = 195_Alumine-kõrgusmärk | Top elevation = 190_Ülemine-kõrgusmärk | Weight (kg) | Volume (m3) | Gross footprint area (m2) | Area per tons (m2) | Net surface area (m2) | Tekla Quantity, Length (mm) | 145_Pindala (m2) | 140_Mass (kg) | 125_Positsioon
2 x RAAM | 1.korrus | RHS150*6 | 1215 | 0.7326 | 0.00335464 | 0.00419904 | 0.00419904 | 32.9625 | 32.9625 | 150 | 150 | +9.666 | +9.816 | 32.96 | 0.004 | 0.182 | 22.225 | 0.733 | 1215 | 0.2 | 33 | TRM-112(?)
RAAM | 1.korrus | RHS150*6 | 3226 | 1.9392 | 0.00335464 | 0.0111491 | 0.0111491 | 87.5201 | 87.5201 | 150 | 150 | +9.666 | +9.816 | 87.52 | 0.011 | 0.484 | 22.157 | 1.939 | 3226 | 0.4 | 87.5 | TRM-111(?)
RAAM | 1.korrus | RHS120*5 | 1215 | 0.569835 | 0.00229 | 0.0027945 | 0.00278235 | 21.9368 | 21.8414 | 120 | 120 | +9.696 | +9.816 | 21.84 | 0.003 | 0.146 | 26.09 | 0.586 | 1215 | 0.1 | 21.9 | TRM-113(?)
RAAM | 1.korrus | RHS150*6 | 3226 | 1.9392 | 0.00335464 | 0.0111491 | 0.0111491 | 87.5201 | 87.5201 | 150 | 150 | +9.666 | +9.816 | 87.52 | 0.011 | 0.484 | 22.157 | 1.939 | 3226 | 0.4 | 87.5 | TRM-110(?)
RAAM | 2.korrus | RHS250*150*6 | 2335 | 1.86129 | 0.00455464 | 0.0108718 | 0.0108718 | 85.3433 | 85.3433 | 150 | 250 | +12.442 | +12.692 | 85.34 | 0.011 | 0.35 | 21.809 | 1.861 | 2335 | 0.4 | 85.3 | TRM-102(?)
RAAM | 2.korrus | RHS200*150*6 | 2335 | 1.63146 | 0.00395464 | 0.00947076 | 0.00947076 | 74.3455 | 74.3455 | 150 | 200 | +12.492 | +12.692 | 74.35 | 0.009 | 0.35 | 21.944 | 1.631 | 2335 | 0.4 | 74.3 | TRM-101(?)
RAAM | 2.korrus | RHS200*150*6 | 2335 | 1.63146 | 0.00395464 | 0.00947076 | 0.00947076 | 74.3455 | 74.3455 | 150 | 200 | +12.492 | +12.692 | 74.35 | 0.009 | 0.35 | 21.944 | 1.631 | 2335 | 0.4 | 74.3 | TRM-102(?)
2 x RAAM | 2.korrus | RHS120*5 | 1615 | 0.757435 | 0.00229 | 0.0037145 | 0.00369835 | 29.1588 | 29.032 | 120 | 120 | +12.572 | +12.692 | 29.03 | 0.004 | 0.194 | 26.09 | 0.778 | 1615 | 0.2 | 29.2 | TRM-108(?)
RAAM | 2.korrus | RHS250*150*6 | 2335 | 1.86129 | 0.00455464 | 0.0108718 | 0.0108718 | 85.3433 | 85.3433 | 150 | 250 | +12.442 | +12.692 | 85.34 | 0.011 | 0.35 | 21.809 | 1.861 | 2335 | 0.4 | 85.3 | TRM-101(?)
RAAM | 2.korrus | RHS150*6 | 5740 | 3.4476 | 0.00335464 | 0.0198374 | 0.0198374 | 155.724 | 155.724 | 150 | 150 | +12.542 | +12.692 | 155.72 | 0.02 | 0.861 | 22.139 | 3.448 | 5740 | 0.9 | 155.7 | TRM-106(?)
RAAM | 2.korrus | RHS200*150*6 | 10040 | 7.00113 | 0.00395464 | 0.0407222 | 0.0407222 | 319.67 | 319.67 | 150 | 200 | +12.492 | +12.692 | 319.67 | 0.041 | 1.506 | 21.901 | 7.001 | 10040 | 1.5 | 319.7 | TRM-107(?)
RAAM | 2.korrus | RHS120*5 | 2104.24 | 0.986889 | 0.00229 | 0.00483975 | 0.00481871 | 37.9921 | 37.8269 | 120 | 120 | +12.572 | +12.692 | 37.83 | 0.005 | 0.253 | 26.09 | 1.012 | 2104.2 | 0.4 | 38 | TRM-105(?)
RAAM | 2.korrus | RHS120*5 | 2119.24 | 0.993924 | 0.00229 | 0.00487425 | 0.00485306 | 38.2629 | 38.0965 | 120 | 120 | +12.572 | +12.692 | 38.1 | 0.005 | 0.254 | 26.09 | 1.02 | 2119.2 | 0.4 | 38.3 | TRM-104(?)
RAAM | 2.korrus | RHS120*5 | 5740 | 2.69206 | 0.00229 | 0.013202 | 0.0131446 | 103.636 | 103.185 | 120 | 120 | +12.572 | +12.692 | 103.19 | 0.013 | 0.689 | 26.09 | 2.758 | 5740 | 0.6 | 103.6 | TRM-109(?)

# IfcBeam: IPI-I-tala-200x225 200 x 225 (2)
In: 1.korrus
Classification: 1.01 IfcBeamType (tala) (IPI ÜBN); Material: GENEERILINE - EHITUSTOODE
BaseQuantities - NetSurfaceAreaExtrudedSides: 14.4262 m2; Length: 11973.9 mm; CrossSectionArea: 0.00561062 m2; OuterSurfaceArea: 14.4262 m2; TotalSurfaceArea: 14.4375 m2; GrossSurfaceArea: 14.4375 m2; GrossVolume: 0.0677302 m3; NetSurfaceArea: 14.4375 m2; NetVolume: 0.0677302 m3
AC_Pset_RenovationAndPhasing - Renovation Status: Existing
AR_ÜLD - 001_Nimetus: Olemasolev tala

# IfcBeam: IPI-I-tala-90x120 90 x 120 (11)
In: 1.korrus
Classification: 1.01 IfcBeamType (tala) (IPI ÜBN); Material: GENEERILINE - KONSTRUKTRIOON
AR_ÜLD - 001_Nimetus: Olemasolev tala
AC_Pset_RenovationAndPhasing - Renovation Status: Existing
BaseQuantities - CrossSectionArea: 0.00207552 m2
Name | NetSurfaceAreaExtrudedSides (m2) = OuterSurfaceArea (m2) | Length (mm) | TotalSurfaceArea (m2) = GrossSurfaceArea (m2) = NetSurfaceArea (m2) | GrossVolume (m3) | NetVolume (m3)
 | 2.62935 | 4778.81 | 2.6335 | 0.0100938 | 0.0100603
 | 2.62885 | 4778.06 | 2.63301 | 0.0100914 | 0.0100584
 | 2.62834 | 4777.04 | 2.63249 | 0.010089 | 0.0100562
 | 2.62724 | 4774.94 | 2.63139 | 0.0100843 | 0.0100516
 | 2.62782 | 4776.03 | 2.63197 | 0.0100866 | 0.010054
 | 2.62662 | 4773.83 | 2.63077 | 0.0100819 | 0.0100492
 | 2.61163 | 4746.8 | 2.61578 | 0.0100246 | 0.0099919
 | 2.60977 | 4743.44 | 2.61392 | 0.0100174 | 0.00998478
 | 2.61039 | 4744.56 | 2.61454 | 0.0100198 | 0.00998716
 | 2.61101 | 4745.68 | 2.61516 | 0.0100222 | 0.00998953
 | 2.62978 | 4779.55 | 2.63393 | 0.0100961 | 0.010062

# IfcBeam: Precast Double Tee 2 1480 x 440 (4)
Classification: 1.01 IfcBeamType (tala) (IPI ÜBN); Material: GENEERILINE - KONSTRUKTRIOON
AR_ÜLD - 001_Nimetus: Olemasolev tala
AC_Pset_RenovationAndPhasing - Renovation Status: Existing
BaseQuantities - CrossSectionArea: 0.303 m2
Name | In | NetSurfaceAreaExtrudedSides (m2) = OuterSurfaceArea (m2) | Length (mm) | TotalSurfaceArea (m2) = GrossSurfaceArea (m2) = NetSurfaceArea (m2) | GrossVolume (m3) | NetVolume (m3)
 | 1.korrus | 25.1043 | 6004.37 | 25.7103 | 1.81985 | 1.80767
 | 1.korrus | 25.3119 | 6006.11 | 25.9179 | 1.82038 | 1.80675
 | 1.korrus | 25.4271 | 6006.11 | 26.0331 | 1.82038 | 1.81167
 | 2.korrus | 24.7263 | 5851.27 | 25.3323 | 1.77345 | 1.75948

# IfcBeam: Precast Double Tee 2 1500 x 440 (19)
Classification: 1.01 IfcBeamType (tala) (IPI ÜBN); Material: GENEERILINE - KONSTRUKTRIOON
AR_ÜLD - 001_Nimetus: Olemasolev tala
AC_Pset_RenovationAndPhasing - Renovation Status: Existing
BaseQuantities - CrossSectionArea: 0.307094 m2
Name | In | NetSurfaceAreaExtrudedSides (m2) = OuterSurfaceArea (m2) | Length (mm) | TotalSurfaceArea (m2) = GrossSurfaceArea (m2) = NetSurfaceArea (m2) | GrossVolume (m3) | NetVolume (m3)
 | 1.korrus | 25.2607 | 6001.5 | 25.8749 | 1.84603 | 1.82671
 | 1.korrus | 25.2516 | 6002.45 | 25.8657 | 1.8455 | 1.8267
 | 1.korrus | 25.27 | 6001.5 | 25.8842 | 1.84603 | 1.82672
 | 1.korrus | 25.2803 | 6000.05 | 25.8945 | 1.84806 | 1.82684
 | 1.korrus | 25.3814 | 6000.19 | 25.9955 | 1.85837 | 1.82804
 | 1.korrus | 25.4702 | 6006.11 | 26.0844 | 1.84826 | 1.82837
 | 1.korrus | 25.4627 | 6006.11 | 26.0769 | 1.84717 | 1.82807
 | 1.korrus | 25.4778 | 6006.11 | 26.0919 | 1.84935 | 1.82868
 | 1.korrus | 25.4853 | 6006.11 | 26.0995 | 1.85107 | 1.82898
 | 1.korrus | 25.6228 | 6016.79 | 26.237 | 1.84826 | 1.83606
 | 1.korrus | 25.6157 | 6013.25 | 26.2299 | 1.84717 | 1.8353
 | 1.korrus | 25.5889 | 6006.11 | 26.2031 | 1.8612 | 1.83166
 | 1.korrus | 25.6298 | 6020.34 | 26.244 | 1.84935 | 1.83682
 | 1.korrus | 25.6463 | 6025.94 | 26.2605 | 1.85107 | 1.83822
 | 1.korrus | 25.833 | 6058.93 | 26.4471 | 1.8612 | 1.84888
 | 2.korrus | 25.0149 | 5855.58 | 25.6291 | 1.79874 | 1.79028
 | 2.korrus | 24.5876 | 5807.3 | 25.2018 | 1.78391 | 1.75602
 | 2.korrus | 24.6039 | 5851.27 | 25.218 | 1.79741 | 1.75785
 | 2.korrus | 24.9494 | 5855.58 | 25.5636 | 1.79874 | 1.78713

# IfcBeam: Precast Double Tee 2 1510 x 440 (9)
In: 1.korrus
Classification: 1.01 IfcBeamType (tala) (IPI ÜBN); Material: GENEERILINE - KONSTRUKTRIOON
AR_ÜLD - 001_Nimetus: Olemasolev tala
AC_Pset_RenovationAndPhasing - Renovation Status: Existing
BaseQuantities - CrossSectionArea: 0.309144 m2
Name | NetSurfaceAreaExtrudedSides (m2) = OuterSurfaceArea (m2) | Length (mm) | TotalSurfaceArea (m2) = GrossSurfaceArea (m2) = NetSurfaceArea (m2) | GrossVolume (m3) | NetVolume (m3)
 | 25.4094 | 6000.08 | 26.0277 | 1.86295 | 1.83927
 | 25.4339 | 6000.15 | 26.0522 | 1.86815 | 1.83979
 | 25.4216 | 6000.12 | 26.0399 | 1.86555 | 1.83953
 | 25.6115 | 6006.11 | 26.2298 | 1.86594 | 1.84147
 | 25.6191 | 6006.11 | 26.2374 | 1.86849 | 1.84178
 | 25.6267 | 6006.11 | 26.245 | 1.87104 | 1.84209
 | 25.7937 | 6034.17 | 26.412 | 1.86594 | 1.85272
 | 25.8225 | 6042.43 | 26.4407 | 1.86849 | 1.85499
 | 25.8512 | 6050.69 | 26.4695 | 1.87104 | 1.85726

# IfcBeam: Precast Double Tee 2 1527 x 440 (4)
Classification: 1.01 IfcBeamType (tala) (IPI ÜBN); Material: GENEERILINE - KONSTRUKTRIOON
AR_ÜLD - 001_Nimetus: Olemasolev tala
AC_Pset_RenovationAndPhasing - Renovation Status: Existing
BaseQuantities - CrossSectionArea: 0.312647 m2
Name | In | NetSurfaceAreaExtrudedSides (m2) = OuterSurfaceArea (m2) | Length (mm) | TotalSurfaceArea (m2) = GrossSurfaceArea (m2) = NetSurfaceArea (m2) | GrossVolume (m3) | NetVolume (m3)
 | 1.korrus | 25.5562 | 6003.41 | 26.1815 | 1.87821 | 1.85961
 | 1.korrus | 25.7733 | 6006.11 | 26.3986 | 1.87933 | 1.8607
 | 1.korrus | 25.927 | 6009.66 | 26.5523 | 1.87933 | 1.86759
 | 2.korrus | 25.2393 | 5851.27 | 25.8646 | 1.82979 | 1.81782

# IfcBeam: Precast Double Tee 3 1500 x 415
In: 2.korrus
Classification: 1.01 IfcBeamType (tala) (IPI ÜBN); Material: GENEERILINE - KONSTRUKTRIOON
AR_ÜLD - 001_Nimetus: Olemasolev tala
AC_Pset_RenovationAndPhasing - Renovation Status: Existing
BaseQuantities - NetSurfaceAreaExtrudedSides: 24.5918 m2; Length: 5811.44 mm; CrossSectionArea: 0.278109 m2; OuterSurfaceArea: 24.5918 m2; TotalSurfaceArea: 25.148 m2; GrossSurfaceArea: 25.148 m2; GrossVolume: 1.61669 m3; NetSurfaceArea: 25.148 m2; NetVolume: 1.61193 m3

# IfcBeam: Precast Double Tee 3 1505 x 415
In: 2.korrus
Classification: 1.01 IfcBeamType (tala) (IPI ÜBN); Material: GENEERILINE - KONSTRUKTRIOON
AR_ÜLD - 001_Nimetus: Olemasolev tala
AC_Pset_RenovationAndPhasing - Renovation Status: Existing
BaseQuantities - NetSurfaceAreaExtrudedSides: 24.6586 m2; Length: 5811.44 mm; CrossSectionArea: 0.279036 m2; OuterSurfaceArea: 24.6586 m2; TotalSurfaceArea: 25.2167 m2; GrossSurfaceArea: 25.2167 m2; GrossVolume: 1.62207 m3; NetSurfaceArea: 25.2167 m2; NetVolume: 1.61729 m3

# IfcBeam: Precast Double Tee 3 1525 x 415 (4)
In: 2.korrus
Classification: 1.01 IfcBeamType (tala) (IPI ÜBN); Material: GENEERILINE - KONSTRUKTRIOON
AR_ÜLD - 001_Nimetus: Olemasolev tala
AC_Pset_RenovationAndPhasing - Renovation Status: Existing
BaseQuantities - CrossSectionArea: 0.282745 m2
Name | NetSurfaceAreaExtrudedSides (m2) = OuterSurfaceArea (m2) | Length (mm) | TotalSurfaceArea (m2) = GrossSurfaceArea (m2) = NetSurfaceArea (m2) | GrossVolume (m3) | NetVolume (m3)
 | 24.8846 | 5811.44 | 25.4501 | 1.64361 | 1.63877
 | 25.0808 | 5851.27 | 25.6463 | 1.65488 | 1.65165
 | 25.0591 | 5851.27 | 25.6246 | 1.65488 | 1.65034
 | 25.0459 | 5851.27 | 25.6113 | 1.65488 | 1.65004

# IfcBeam: Precast Double Tee 4 2960 x 440
In: 2.korrus
Classification: 1.01 IfcBeamType (tala) (IPI ÜBN); Material: GENEERILINE - KONSTRUKTRIOON
AR_ÜLD - 001_Nimetus: Olemasolev tala
AC_Pset_RenovationAndPhasing - Renovation Status: Existing
BaseQuantities - NetSurfaceAreaExtrudedSides: 40.767 m2; Length: 6021.6 mm; CrossSectionArea: 0.556519 m2; OuterSurfaceArea: 40.767 m2; TotalSurfaceArea: 41.88 m2; GrossSurfaceArea: 41.88 m2; GrossVolume: 3.35168 m3; NetSurfaceArea: 41.88 m2; NetVolume: 3.31497 m3

# IfcBeam: Precast Double Tee 4 3000 x 440 (6)
Classification: 1.01 IfcBeamType (tala) (IPI ÜBN); Material: GENEERILINE - KONSTRUKTRIOON
AR_ÜLD - 001_Nimetus: Olemasolev tala
BaseQuantities - CrossSectionArea: 0.563334 m2
AC_Pset_RenovationAndPhasing - Renovation Status: Existing
Name | In | NetSurfaceAreaExtrudedSides (m2) = OuterSurfaceArea (m2) | Length (mm) | TotalSurfaceArea (m2) = GrossSurfaceArea (m2) = NetSurfaceArea (m2) | GrossVolume (m3) | NetVolume (m3)
 | 1.korrus | 41.1721 | 6017.9 | 42.2988 | 3.39063 | 3.36802
 | 1.korrus | 41.1299 | 6017.9 | 42.2565 | 3.39063 | 3.36774
 | 1.korrus | 41.0984 | 6017.9 | 42.225 | 3.39063 | 3.36729
 | 1.korrus | 41.1141 | 6017.9 | 42.2408 | 3.39063 | 3.36751
 | 1.korrus | 41.1946 | 6017.9 | 42.3213 | 3.39063 | 3.37027
 | 2.korrus | 40.6347 | 5851.27 | 41.7613 | 3.29675 | 3.2802

# IfcBeam: Precast Double Tee 4 3012 x 440 (4)
In: 2.korrus
Classification: 1.01 IfcBeamType (tala) (IPI ÜBN); Material: GENEERILINE - KONSTRUKTRIOON
AR_ÜLD - 001_Nimetus: Olemasolev tala
AC_Pset_RenovationAndPhasing - Renovation Status: Existing
BaseQuantities - CrossSectionArea: 0.565316 m2
Name | NetSurfaceAreaExtrudedSides (m2) = OuterSurfaceArea (m2) | Length (mm) | TotalSurfaceArea (m2) = GrossSurfaceArea (m2) = NetSurfaceArea (m2) | GrossVolume (m3) | NetVolume (m3)
 | 39.2151 | 6276.48 | 40.3457 | 3.5487 | 3.40918
 | 41.3897 | 6030.79 | 42.5203 | 3.40985 | 3.37313
 | 40.7816 | 5851.27 | 41.9122 | 3.30834 | 3.29375
 | 41.4807 | 6026.75 | 42.6113 | 3.40757 | 3.37718

# IfcBeam: Precast Double Tee 5 3052 x 440
In: 2.korrus
Classification: 1.01 IfcBeamType (tala) (IPI ÜBN); Material: GENEERILINE - KONSTRUKTRIOON
AR_ÜLD - 001_Nimetus: Olemasolev tala
AC_Pset_RenovationAndPhasing - Renovation Status: Existing
BaseQuantities - NetSurfaceAreaExtrudedSides: 43.8698 m2; Length: 6037.6 mm; CrossSectionArea: 0.589564 m2; OuterSurfaceArea: 43.8698 m2; TotalSurfaceArea: 45.0489 m2; GrossSurfaceArea: 45.0489 m2; GrossVolume: 3.5601 m3; NetSurfaceArea: 45.0489 m2; NetVolume: 3.52048 m3

# IfcBeam: Precast Double Tee 6 1500 x 575 (5)
In: 1.korrus
Classification: 1.01 IfcBeamType (tala) (IPI ÜBN); Material: GENEERILINE - KONSTRUKTRIOON
AR_ÜLD - 001_Nimetus: Olemasolev tala
AC_Pset_RenovationAndPhasing - Renovation Status: Existing
BaseQuantities - NetSurfaceAreaExtrudedSides: 58.4172 m2; Length: 12088.9 mm; CrossSectionArea: 0.347392 m2; OuterSurfaceArea: 58.4172 m2; TotalSurfaceArea: 59.112 m2; GrossSurfaceArea: 59.112 m2; GrossVolume: 4.20105 m3; NetSurfaceArea: 59.112 m2; NetVolume: 4.20105 m3

# IfcBeam: Precast Girder 01 230 x 600 (2)
Classification: 1.01 IfcBeamType (tala) (IPI ÜBN); Material: Betoon - Monteeritav
AR_ÜLD - 001_Nimetus: Olemasolev tala
AC_Pset_RenovationAndPhasing - Renovation Status: Existing
BaseQuantities - CrossSectionArea: 0.0918168 m2
Name | In | NetSurfaceAreaExtrudedSides (m2) = OuterSurfaceArea (m2) | Length (mm) | TotalSurfaceArea (m2) = GrossSurfaceArea (m2) = NetSurfaceArea (m2) | GrossVolume (m3) = NetVolume (m3)
 | 1.korrus | 26.2443 | 14968.8 | 26.4279 | 1.37439
 | 2.korrus | 12.7798 | 7289.17 | 12.9635 | 0.669268

# IfcBeam: Precast Single Tee 2 107 x 102 (36)
Classification: 1.01 IfcBeamType (tala) (IPI ÜBN); Material: GENEERILINE - KONSTRUKTRIOON
AC_Pset_RenovationAndPhasing - Renovation Status: Existing
AR_ÜLD - 001_Nimetus: Olemasolev tala
BaseQuantities - CrossSectionArea: 0.006611 m2
Name | In | NetSurfaceAreaExtrudedSides (m2) = OuterSurfaceArea (m2) | Length (mm) | TotalSurfaceArea (m2) = GrossSurfaceArea (m2) = NetSurfaceArea (m2) | GrossVolume (m3) = NetVolume (m3)
 | 1.korrus | 5.48883 | 14968.8 | 5.50205 | 0.0992031
13 x  | 1.korrus | 5.48882 | 14968.8 | 5.50204 | 0.0992028
5 x  | 2.korrus | 5.48883 | 14968.8 | 5.50205 | 0.0992031
2 x  | 2.korrus | 2.20263 | 6006.89 | 2.21586 | 0.0398096
5 x  | 2.korrus | 2.20438 | 6011.66 | 2.2176 | 0.0398412
3 x  | 2.korrus | 1.08172 | 2950.01 | 1.09495 | 0.0195507
 | 2.korrus | 2.20273 | 6007.14 | 2.21595 | 0.0398112
4 x  | 2.korrus | 1.66109 | 4530.02 | 1.67431 | 0.0300219
2 x  | 2.korrus | 1.18552 | 3233.09 | 1.19875 | 0.0214267

# IfcBeam: Various Structures - 5 Segments - 250 x 700 x 3042 (262+767+2013+0+0)
In: 1.korrus
Classification: 1.01 IfcBeamType (tala) (IPI ÜBN)
BaseQuantities - NetVolume: 0.00472087 m3; GrossVolume: 0.805159 m3; Length: 3041.96 mm
AR_ÜLD - 001_Nimetus: Olemasolev tala
AC_Pset_RenovationAndPhasing - Renovation Status: Existing

# IfcBeam: Various Structures - 5 Segments - 250 x 700 x 7330 (121+758+5410+621+420)
In: 1.korrus
Classification: 1.01 IfcBeamType (tala) (IPI ÜBN)
AC_Pset_RenovationAndPhasing - Renovation Status: Existing
BaseQuantities - NetVolume: 0.149691 m3; GrossVolume: 0.805098 m3; Length: 7330.34 mm
AR_ÜLD - 001_Nimetus: Olemasolev tala

# IfcBeam: Various Structures - 5 Segments - 250 x 700 x 7349 (338+766+5264+640+341)
In: 1.korrus
Classification: 1.01 IfcBeamType (tala) (IPI ÜBN)
BaseQuantities - NetVolume: 0.443029 m3; GrossVolume: 0.806504 m3; Length: 7348.81 mm
AC_Pset_RenovationAndPhasing - Renovation Status: Existing
AR_ÜLD - 001_Nimetus: Olemasolev tala

# IfcBeam: Various Structures - 5 Segments - 250 x 700 x 7406 (338+766+5361+631+310)
In: 1.korrus
Classification: 1.01 IfcBeamType (tala) (IPI ÜBN)
AR_ÜLD - 001_Nimetus: Olemasolev tala
BaseQuantities - NetVolume: 0.783207 m3; GrossVolume: 0.797371 m3; Length: 7405.91 mm
AC_Pset_RenovationAndPhasing - Renovation Status: Existing

# IfcBeam: Various Structures - 5 Segments - 250 x 700 x 7435 (338+766+5341+640+350)
In: 1.korrus
Classification: 1.01 IfcBeamType (tala) (IPI ÜBN)
BaseQuantities - NetVolume: 0.791256 m3; GrossVolume: 0.799649 m3; Length: 7434.78 mm
AC_Pset_RenovationAndPhasing - Renovation Status: Existing
AR_ÜLD - 001_Nimetus: Olemasolev tala

# IfcBeam: Various Structures - 5 Segments - 250 x 700 x 7456 (338+766+5361+631+361)
In: 1.korrus
Classification: 1.01 IfcBeamType (tala) (IPI ÜBN)
BaseQuantities - NetVolume: 0.788906 m3; GrossVolume: 0.797322 m3; Length: 7455.66 mm
AR_ÜLD - 001_Nimetus: Olemasolev tala
AC_Pset_RenovationAndPhasing - Renovation Status: Existing

# IfcBeam: Various Structures - 5 Segments - 250 x 700 x 7459 (337+766+5365+640+352)
In: 1.korrus
Classification: 1.01 IfcBeamType (tala) (IPI ÜBN)
AR_ÜLD - 001_Nimetus: Olemasolev tala
BaseQuantities - NetVolume: 0.667243 m3; GrossVolume: 0.802214 m3; Length: 7459.42 mm
AC_Pset_RenovationAndPhasing - Renovation Status: Existing

# IfcBeam: Various Structures - 5 Segments - 250 x 700 x 7470 (262+767+5400+621+420)
In: 1.korrus
Classification: 1.01 IfcBeamType (tala) (IPI ÜBN)
BaseQuantities - NetVolume: 0.792772 m3; GrossVolume: 0.79923 m3; Length: 7470.09 mm
AC_Pset_RenovationAndPhasing - Renovation Status: Existing
AR_ÜLD - 001_Nimetus: Olemasolev tala

# IfcBeam: Various Structures - 5 Segments - 250 x 700 x 7472 (262+767+5416+621+406) (2)
In: 1.korrus
Classification: 1.01 IfcBeamType (tala) (IPI ÜBN)
BaseQuantities - NetVolume: 0.804309 m3; GrossVolume: 0.805723 m3; Length: 7472.07 mm
AC_Pset_RenovationAndPhasing - Renovation Status: Existing
AR_ÜLD - 001_Nimetus: Olemasolev tala

# IfcBeam: Various Structures - 5 Segments - 250 x 700 x 7473 (262+767+5416+621+406)
In: 1.korrus
Classification: 1.01 IfcBeamType (tala) (IPI ÜBN)
BaseQuantities - NetVolume: 0.735502 m3; GrossVolume: 0.805723 m3; Length: 7472.65 mm
AC_Pset_RenovationAndPhasing - Renovation Status: Existing
AR_ÜLD - 001_Nimetus: Olemasolev tala

# IfcBeam: Various Structures - 5 Segments - 250 x 700 x 7473 (262+767+5416+621+407)
In: 1.korrus
Classification: 1.01 IfcBeamType (tala) (IPI ÜBN)
AR_ÜLD - 001_Nimetus: Olemasolev tala
BaseQuantities - NetVolume: 0.727463 m3; GrossVolume: 0.805724 m3; Length: 7472.89 mm
AC_Pset_RenovationAndPhasing - Renovation Status: Existing

# IfcBeam: Various Structures - 5 Segments - 250 x 700 x 7480 (322+828+5345+505+480)
In: 2.korrus
Classification: 1.01 IfcBeamType (tala) (IPI ÜBN)
AR_ÜLD - 001_Nimetus: Olemasolev tala
BaseQuantities - NetVolume: 0.800749 m3; GrossVolume: 0.806368 m3; Length: 7479.62 mm
AC_Pset_RenovationAndPhasing - Renovation Status: Existing

# IfcBeam: Various Structures - 5 Segments - 250 x 700 x 7488 (338+766+5404+640+341)
In: 1.korrus
Classification: 1.01 IfcBeamType (tala) (IPI ÜBN)
BaseQuantities - NetVolume: 0.0338643 m3; GrossVolume: 0.80651 m3; Length: 7488.15 mm
AC_Pset_RenovationAndPhasing - Renovation Status: Existing
AR_ÜLD - 001_Nimetus: Olemasolev tala

# IfcBeam: Various Structures - 5 Segments - 250 x 700 x 7489 (338+766+5394+640+352)
In: 1.korrus
Classification: 1.01 IfcBeamType (tala) (IPI ÜBN)
AR_ÜLD - 001_Nimetus: Olemasolev tala
AC_Pset_RenovationAndPhasing - Renovation Status: Existing
BaseQuantities - NetVolume: 0.805272 m3; GrossVolume: 0.805428 m3; Length: 7489.13 mm

# IfcBeam: Various Structures - 5 Segments - 250 x 700 x 7496 (338+766+5404+640+349)
In: 1.korrus
Classification: 1.01 IfcBeamType (tala) (IPI ÜBN)
AC_Pset_RenovationAndPhasing - Renovation Status: Existing
AR_ÜLD - 001_Nimetus: Olemasolev tala
BaseQuantities - NetVolume: 0.734393 m3; GrossVolume: 0.80651 m3; Length: 7496.35 mm

# IfcBeam: Various Structures - 5 Segments - 250 x 700 x 7497 (338+766+5404+640+350) (3)
In: 1.korrus
Classification: 1.01 IfcBeamType (tala) (IPI ÜBN)
AR_ÜLD - 001_Nimetus: Olemasolev tala
AC_Pset_RenovationAndPhasing - Renovation Status: Existing
Name | NetVolume (m3) | GrossVolume (m3) | Length (mm)
 | 0.737055 | 0.8065 | 7496.62
 | 0.806199 | 0.8065 | 7497.33
 | 0.806192 | 0.806504 | 7496.84

# IfcBeam: Various Structures - 5 Segments - 250 x 700 x 7499 (338+766+5404+631+361)
In: 1.korrus
Classification: 1.01 IfcBeamType (tala) (IPI ÜBN)
AC_Pset_RenovationAndPhasing - Renovation Status: Existing
AR_ÜLD - 001_Nimetus: Olemasolev tala
BaseQuantities - NetVolume: 0.795178 m3; GrossVolume: 0.802054 m3; Length: 7498.79 mm

# IfcBeam: Various Structures - 5 Segments - 250 x 700 x 7513 (262+767+5443+621+419)
In: 1.korrus
Classification: 1.01 IfcBeamType (tala) (IPI ÜBN)
BaseQuantities - NetVolume: 0.79571 m3; GrossVolume: 0.804007 m3; Length: 7513.18 mm
AC_Pset_RenovationAndPhasing - Renovation Status: Existing
AR_ÜLD - 001_Nimetus: Olemasolev tala

# IfcBeam: Various Structures - 5 Segments - 250 x 700 x 7519 (262+767+5449+621+420)
In: 1.korrus
Classification: 1.01 IfcBeamType (tala) (IPI ÜBN)
BaseQuantities - NetVolume: 0.809006 m3; GrossVolume: 0.809375 m3; Length: 7519.22 mm
AC_Pset_RenovationAndPhasing - Renovation Status: Existing
AR_ÜLD - 001_Nimetus: Olemasolev tala

# IfcBeam: Various Structures - 5 Segments - 250 x 700 x 7535 (262+767+5466+621+419)
In: 1.korrus
Classification: 1.01 IfcBeamType (tala) (IPI ÜBN)
AR_ÜLD - 001_Nimetus: Olemasolev tala
BaseQuantities - NetVolume: 0.802825 m3; GrossVolume: 0.8112 m3; Length: 7535.01 mm
AC_Pset_RenovationAndPhasing - Renovation Status: Existing

# IfcBeam: Various Structures - 5 Segments - 250 x 700 x 7549 (262+767+5479+621+420)
In: 1.korrus
Classification: 1.01 IfcBeamType (tala) (IPI ÜBN)
AC_Pset_RenovationAndPhasing - Renovation Status: Existing
BaseQuantities - NetVolume: 0.707356 m3; GrossVolume: 0.812695 m3; Length: 7549.44 mm
AR_ÜLD - 001_Nimetus: Olemasolev tala

# IfcBeam: Various Structures - 5 Segments - 250 x 700 x 7563 (338+766+5468+631+361)
In: 1.korrus
Classification: 1.01 IfcBeamType (tala) (IPI ÜBN)
AC_Pset_RenovationAndPhasing - Renovation Status: Existing
BaseQuantities - NetVolume: 0.800092 m3; GrossVolume: 0.80916 m3; Length: 7563.46 mm
AR_ÜLD - 001_Nimetus: Olemasolev tala

# IfcBuildingElementPart (1072)
Name | In | Material
6 x Puit - CLT | 1.korrus | Puit - CLT
5 x Soojustus - Mineraalvill pehme | 1.korrus | Soojustus - Mineraalvill pehme
18 x Betoon - C30/37 | 1.korrus | Betoon - C30/37
12 x Soojustus - Vahtpolüstüreen | 1.korrus | Soojustus - Vahtpolüstüreen
2 x Kruus | 1.korrus | Kruus
41 x Air Space - Frame | 1.korrus | Air Space - Frame
31 x Plaster - Gypsum | 1.korrus | Plaster - Gypsum
31 x Plywood | 1.korrus | Plywood
16 x Kipsplaat | 1.korrus | Kipsplaat
7 x Aluminium | 1.korrus | Aluminium
11 x Klaas | 1.korrus | Klaas
30 x Metall - Teras - Roostevaba | 1.korrus | Metall - Teras - Roostevaba
5 x Soojustus - Mineraalvill jäik | 1.korrus | Soojustus - Mineraalvill jäik
5 x Puit - voodrilaud | 1.korrus | Puit - voodrilaud
3 x Betoon - C25/30 | 1.korrus | Betoon - C25/30
51 x GENEERILINE - SISEMINE VIIMISTLUS | 1.korrus | GENEERILINE - SISEMINE VIIMISTLUS
4 x Metall - Teras - Konstruktsioon | 1.korrus | Metall - Teras - Konstruktsioon
25 x Steel | 1.korrus | Steel
6 x Teras - roostevaba | 1.korrus | Teras - roostevaba
2 x Steel - Structural | 1.korrus | Steel - Structural
58 x GENEERILINE - KONSTRUKTRIOON | 1.korrus | GENEERILINE - KONSTRUKTRIOON
118 x Raudbetoon | 1.korrus | Raudbetoon
 | 1.korrus
15 x Klaas | 2.korrus | Klaas
10 x Aluminium | 2.korrus | Aluminium
11 x Metall - Teras - Roostevaba | 2.korrus | Metall - Teras - Roostevaba
212 x Kipsplaat | 2.korrus | Kipsplaat
23 x Steel | 2.korrus | Steel
2 x Metall - Teras - Konstruktsioon | 2.korrus | Metall - Teras - Konstruktsioon
54 x Soojustus - Mineraalvill pehme | 2.korrus | Soojustus - Mineraalvill pehme
12 x Plaster - Gypsum | 2.korrus | Plaster - Gypsum
12 x Plywood | 2.korrus | Plywood
27 x Air Space - Frame | 2.korrus | Air Space - Frame
17 x Soojustus - Mineraalvill jäik | 2.korrus | Soojustus - Mineraalvill jäik
9 x Puit - CLT | 2.korrus | Puit - CLT
6 x Puit - voodrilaud | 2.korrus | Puit - voodrilaud
2 x Air Space | 2.korrus | Air Space
4 x Õhkvahe - Raam | 2.korrus | Õhkvahe - Raam
GENEERILINE - SISEMINE VOODER | 2.korrus | GENEERILINE - SISEMINE VOODER
GENEERILINE - VÄLINE VOODER | 2.korrus | GENEERILINE - VÄLINE VOODER
3 x Steel - Structural | 2.korrus | Steel - Structural
3 x Teras - roostevaba | 2.korrus | Teras - roostevaba
5 x Raudbetoon | 2.korrus | Raudbetoon
3 x GENEERILINE - KONSTRUKTRIOON | 2.korrus | GENEERILINE - KONSTRUKTRIOON
21 x Air Space - Frame | Pööningukorrus | Air Space - Frame
17 x Soojustus - Mineraalvill pehme | Pööningukorrus | Soojustus - Mineraalvill pehme
7 x Soojustus - Mineraalvill jäik | Pööningukorrus | Soojustus - Mineraalvill jäik
3 x Puit - voodrilaud | Pööningukorrus | Puit - voodrilaud
18 x Puit - CLT | Pööningukorrus | Puit - CLT
3 x Soojustus - Mineraalvill jäik2 | Pööningukorrus | Soojustus - Mineraalvill jäik2
3 x Plywood | Pööningukorrus | Plywood
18 x Kipsplaat | Pööningukorrus | Kipsplaat
2 x Soojustus - Puistevill | Pööningukorrus | Soojustus - Puistevill
9 x Teras - roostevaba | Pööningukorrus | Teras - roostevaba
9 x Klaas | Pööningukorrus | Klaas
3 x Steel | Pööningukorrus | Steel
6 x Steel - Structural | Pööningukorrus | Steel - Structural
4 x Kipsplaat | Katuseplaan | Kipsplaat
6 x Soojustus - Mineraalvill pehme | Katuseplaan | Soojustus - Mineraalvill pehme
2 x GENEERILINE - SISEMINE VIIMISTLUS | Katuseplaan | GENEERILINE - SISEMINE VIIMISTLUS
15 x Air Space - Frame | Katuseplaan | Air Space - Frame
6 x Õhkvahe | Katuseplaan | Õhkvahe

# IfcBuildingElementProxy: Air Space 1842, SLA - 001
In: 1.korrus
Material: Air Space
AC_Pset_RenovationAndPhasing - Renovation Status: New

# IfcBuildingElementProxy: Cube 27 (2)
In: 1.korrus
Type - ElementType: REEPER; PredefinedType: USERDEFINED
Classification: 1.02.1 IfcBuildingElementProxyType (reeper) (IPI ÜBN)
AR_Reeper - 01_X-(L-EST): 6460550000 mm; 02_Y-(L-EST): 414900000 mm; 03_Z-(EH2000): 0 mm
AC_Pset_RenovationAndPhasing - Renovation Status: New
Name | 04_Nurk(◦)
Projekti reeper | 49.492
Projekti reeper | 315

# IfcBuildingElementProxy: GENEERILINE - KONSTRUKTRIOON (2)
In: 1.korrus
Material: GENEERILINE - KONSTRUKTRIOON
AC_Pset_RenovationAndPhasing - Renovation Status: Existing

# IfcBuildingElementProxy: GENEERILINE - KONSTRUKTRIOON 10
In: 1.korrus
Classification: 1.02 IfcBuildingElementProxyType (objekt) (IPI ÜBN); Material: GENEERILINE - KONSTRUKTRIOON
AR_ÜLD - 001_Nimetus: Parkimisjooned
AC_Pset_RenovationAndPhasing - Renovation Status: Existing

# IfcBuildingElementProxy: GENEERILINE - KONSTRUKTRIOON 1030
In: 1.korrus
Classification: 1.02 IfcBuildingElementProxyType (objekt) (IPI ÜBN); Material: GENEERILINE - KONSTRUKTRIOON
AR_ÜLD - 001_Nimetus: Olemasolev kiviaed
AC_Pset_RenovationAndPhasing - Renovation Status: Existing

# IfcBuildingElementProxy: GENEERILINE - KONSTRUKTRIOON 160 x 130 (3)
In: 1.korrus
Material: GENEERILINE - KONSTRUKTRIOON
AC_Pset_RenovationAndPhasing - Renovation Status: Existing

# IfcBuildingElementProxy: GENEERILINE - KONSTRUKTRIOON 160 x 600 (2)
In: 1.korrus
Material: GENEERILINE - KONSTRUKTRIOON
AC_Pset_RenovationAndPhasing - Renovation Status: Existing

# IfcBuildingElementProxy: GENEERILINE - KONSTRUKTRIOON 20 (3)
In: 1.korrus
Classification: 1.02 IfcBuildingElementProxyType (objekt) (IPI ÜBN); Material: GENEERILINE - KONSTRUKTRIOON
AR_ÜLD - 001_Nimetus: Parkimist keelavad jooned
Name | Renovation Status
 | New
2 x  | Existing

# IfcBuildingElementProxy: GENEERILINE - KONSTRUKTRIOON 800 (3)
In: 1.korrus
Classification: 1.02 IfcBuildingElementProxyType (objekt) (IPI ÜBN); Material: GENEERILINE - KONSTRUKTRIOON
AR_ÜLD - 001_Nimetus: Olemasolev kiviaed
AC_Pset_RenovationAndPhasing - Renovation Status: Existing

# IfcBuildingElementProxy: GENEERILINE - KONSTRUKTRIOON 850
In: 1.korrus
Classification: 1.02 IfcBuildingElementProxyType (objekt) (IPI ÜBN); Material: GENEERILINE - KONSTRUKTRIOON
AR_ÜLD - 001_Nimetus: Olemasolev kiviaed
AC_Pset_RenovationAndPhasing - Renovation Status: Existing

# IfcBuildingElementProxy: Hedge Model 27 (4)
In: 1.korrus
Classification: 1.02 IfcBuildingElementProxyType (objekt) (IPI ÜBN)
AC_Pset_RenovationAndPhasing - Renovation Status: New
AR_ÜLD - 001_Nimetus: Haljastus

# IfcBuildingElementProxy: IfcBuildingElementProxy (26)
In: 1.korrus
AC_Pset_RenovationAndPhasing - Renovation Status: Existing
Name
23 x 
2 x DUCT - 001
DUCT TRANSITION - 001

# IfcBuildingElementProxy: MasterType, BIM Motala Hissar:MasterType:7834
In: 1.korrus
Type - Constraints - Default Elevation: 0 mm
Type - Dimensions - pitDepth: 60 mm; shaftDepth: 1560 mm; shaftHeight: 8853 mm; shaftWidth: 1250 mm
Type - Identity Data - Type Name: MasterType
Type - Other - Category: Generic Models; Family Name: BIM Motala Hissar
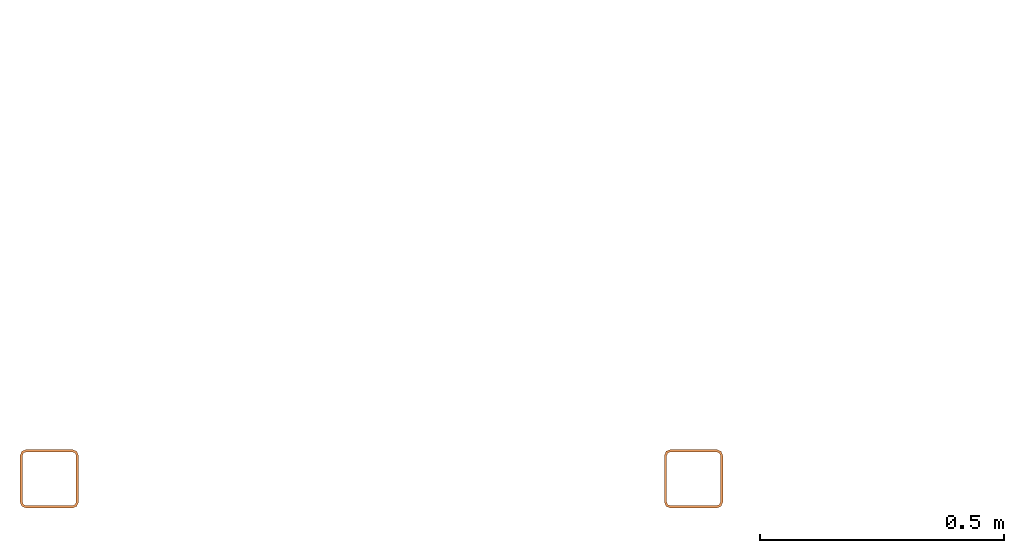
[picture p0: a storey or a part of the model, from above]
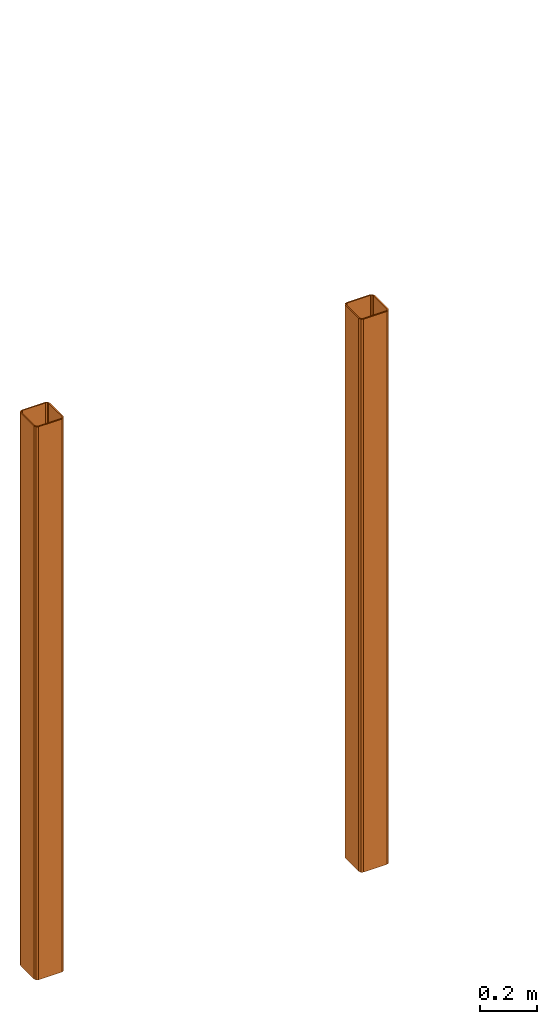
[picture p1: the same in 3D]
Properties of the parts of a building model (IFC2X3), part 2 of 7

# IfcBuildingElementProxy: MasterType, BIM Motala Hissar:MasterType:7834
Type - Text - DoorAutoTypes: 0&34603&34603&0&0&0&0&0&0&0&0&0&0&¤34603&0&0&0&0&0&0&0&0&0&0&0&0&¤0&0&0&0&0&0&0&0&0&0&0&0&0&¤0&0&0&0&0&0&0&0&0&0&0&0&0&¤; doorHeights: 0&2260&2160&0&0&0&0&0&0&0&0&0&0&¤2260&0&2160&0&0&0&0&0&0&0&0&0&0&¤0&0&2160&0&0&0&0&0&0&0&0&0&0&¤0&0&2160&0&0&0&0&0&0&0&0&0&0&¤; doorWidths: 900&900&900&0&0&0&0&0&0&0&0&0&0&¤1000&900&1000&0&0&0&0&0&0&0&0&0&0&¤900&900&900&0&0&0&0&0&0&0&0&0&0&¤900&900&1000&0&0&0&0&0&0&0&0&0&0&¤; driveSide: D; glassLists: False&False&False&False&False&False&False&False&False&False&False&False&False&False&False&False&False&False&False&False&False&False&False&False&False&False&False&False&False&False&False&False&False&False&False&False&False&False&False&False&False&False&False&False&False&False&False&False&False&False&False&¤False&False&False&False&True&True&True&True&True&True&True&True&True&True&True&False&False&False&False&False&False&False&False&False&False&False&False&False&False&False&False&False&False&False&False&False&False&False&False&False&False&False&False&False&False&False&False&False&False&False&False&¤False&False&False&False&False&False&False&False&False&False&False&False&False&False&False&False&False&False&False&False&False&False&False&False&False&False&False&False&False&False&False&False&False&False&False&False&False&False&False&False&False&False&False&False&False&False&False&False&False&False&False&¤False&False&False&False&False&False&False&False&False&False&False&False&False&False&False&False&False&False&False&False&False&False&False&False&False&False&False&False&False&False&False&False&False&False&False&False&False&False&False&False&False&False&False&False&False&False&False&False&False&False&False&¤; glazingOffsets: 0&0&0&0&0&0&0&0&0&0&0&0&0&0&0&0&0&0&0&0&0&0&0&0&0&0&0&0&0&0&0&0&0&0&0&0&0&0&0&0&0&0&0&0&0&0&0&0&0&0&; intHeights: 2000&2000&2000&0&0&0&0&0&0&0&0&0&0&¤2000&2000&2000&0&0&0&0&0&0&0&0&0&0&¤2000&2000&2000&0&0&0&0&0&0&0&0&0&0&¤2000&2000&2000&0&0&0&0&0&0&0&0&0&0&¤; Justerings: 0&0&0&0&0&0&0&0&0&0&0&0&0&¤34401&0&0&0&0&0&0&0&0&0&0&0&0&¤0&0&0&0&0&0&0&0&0&0&0&0&0&¤0&0&0&0&0&0&0&0&0&0&0&0&0&¤; LeftHangTypes: 0&34101&34101&0&0&0&0&0&0&0&0&0&0&¤34101&0&0&0&0&0&0&0&0&0&0&0&0&¤0&0&0&0&0&0&0&0&0&0&0&0&0&¤0&0&0&0&0&0&0&0&0&0&0&0&0&¤; noOfStops: 3; types: 0&34004&34006&0&0&0&0&0&0&0&0&0&0&¤34006&0&0&0&0&0&0&0&0&0&0&0&0&¤0&0&0&0&0&0&0&0&0&0&0&0&0&¤0&0&0&0&0&0&0&0&0&0&0&0&0&¤; zStartPositions: 0&3268&6587&0&0&0&0&0&0&0&0&0&0&
Type - Pset_BuildingElementProxyCommon - Reference: MasterType
Type - Pset_ProductRequirements - Category: Generic Models
Type - Pset_QuantityTakeOff - Reference: MasterType
Material: IFC Building Material
Phasing - Phase Created: New Construction
Other - Family: BIM Motala Hissar: MasterType; Family and Type: BIM Motala Hissar: MasterType; Type: BIM Motala Hissar: MasterType; Type Id: BIM Motala Hissar: MasterType
Dimensions - Area: 47.2873 m2; Volume: 1.2995 m3
Constraints - Elevation from Level: 0 mm; Moves With Nearby Elements: no; Offset from Host: 0 mm
Pset_QuantityTakeOff - sets with these values: 2
AC_Pset_RenovationAndPhasing - Renovation Status: New

# IfcBuildingElementProxy: Pine Tree Model 27 (9)
In: 1.korrus
Classification: 1.02 IfcBuildingElementProxyType (objekt) (IPI ÜBN)
AC_Pset_RenovationAndPhasing - Renovation Status: New
AR_ÜLD - 001_Nimetus: Haljastus

# IfcBuildingElementProxy: Pressurized Extinguisher 27 (15)
Description: Kandilinekanal; Classification: 1.02 IfcBuildingElementProxyType (objekt) (IPI ÜBN)
AC_Pset_RenovationAndPhasing - Renovation Status: New
AR_ÜLD - 001_Nimetus: Pulbertulekustuti
KVJ_Õhukanal - 100_Rõhukadu(Pa): 0; 105_Rõhk(Pa): 0; 110_Vooluhulk(l/s): 1600; 115_Voolukiirus(m/s): 1.111; 150_Kanali_suurus: 1200 mm; 185_Materjal: Kuumtsingitud lehtteras
Name | In
7 x Kandilinekanal Lindab | 1.korrus
6 x Kandilinekanal Lindab | 2.korrus
2 x Kandilinekanal Lindab | Pööningukorrus

# IfcBuildingElementProxy: RHS100*6 100 x 100 (2)
In: Merepind
Description: RHS100*6; Material: STEEL/S355
AC_Pset_RenovationAndPhasing - Renovation Status: New
EK_Tala-Post - 135_Ruumala: 0 m3; 105_Tugevusklass: S355; 002_Tüüp: RHS100*6
Tekla Common - Phase: 1
Tekla Quantity - Height: 100 mm; Width: 100 mm
Name | 145_Pindala (m2) | 195_Alumine_kõrgusmärk = Bottom elevation | 190_Ülemine_kõrgusmärk = Top elevation | 140_Mass (kg) | 130_Pikkus (mm) = Tekla Quantity, Length (mm) = BaseQuantities, Length (mm) | 125_Positsioon | 001_Nimetus | Class | Weight (kg) | Volume (m3) | Gross footprint area (m2) | Area per tons (m2) | Net surface area (m2) | Reference | OuterSurfaceArea (m2) | NetVolume (m3) | NetWeight (kg)
TERASTALA | 0.2 | +10.373 | +10.473 | 36 | 2030 | TT-0(?) | TERASTALA | 23 | 35.95 | 0.005 | 0.203 | 22.653 | 0.814 | TTd-0(?) | 0.8144 | 0.00457968 | 35.9505
TERAS_POST | 0 | +8.650 | +10.450 | 31.9 | 1800 | TEP-0(?) | TERAS_POST | 1 | 31.88 | 0.004 | 0.002 | 22.662 | 0.722 | TEPd-0(?) | 0.7224 | 0.0040608 | 31.8773

# IfcBuildingElementProxy: RHS120*5 120 x 120 (16)
Description: RHS120*5; Material: STEEL/S355
AC_Pset_RenovationAndPhasing - Renovation Status: New
EK_Tala-Post - 135_Ruumala: 0 m3; 105_Tugevusklass: S355; 003_Ristlõige: RHS120*5
Tekla Common - Phase: 1
Tekla Quantity - Area per tons: 26.09 m2; Height: 120 mm; Width: 120 mm
Name | In | 146_Täispindala (m2) | 145_Pindala (m2) | 195_Alumine-kõrgusmärk = Bottom elevation | 190_Ülemine-kõrgusmärk = Top elevation | 140_Mass (kg) | 130_Pikkus (mm) = Tekla Quantity, Length (mm) | 125_Positsioon | 001_Nimetus | Class | Weight (kg) | Volume (m3) | Gross footprint area (m2) | Net surface area (m2) | Pset_ColumnCommon, Reference | BaseQuantities, Length (mm) | OuterSurfaceArea (m2) | NetVolume (m3) | NetWeight (kg)
2 x TERAS_POST | Merepind | 1.1 | 0 | +16.710 | +19.126 | 43.6 | 2415.8 | TEP-301(?) | TERAS_POST | 1 | 43.43 | 0.006 | 0.002 | 1.162 | TEPd-1(?) | 2415.8 | 1.13301 | 0.00555634 | 43.6173
2 x TERAS_POST | 2.korrus | 2 | 0 | +12.692 | +17.028 | 78.3 | 4335.4 | TEP-202(?) | TERAS_POST | 1 | 77.93 | 0.009 | 0.002 | 2.083 | TEPd-1008(?) | 4335.36 | 2.03328 | 0.00997133 | 78.2749
4 x TERAS_POST | 2.korrus | 1.8 | 0 | +12.692 | +16.590 | 70.4 | 3897.6 | TEP-201(?) | TERAS_POST | 1 | 70.06 | 0.009 | 0.002 | 1.873 | TEPd-1006(?) | 3897.58 | 1.82797 | 0.00896443 | 70.3708
2 x TERAS_POST | 2.korrus | 1.8 | 0 | +12.692 | +16.508 | 68.9 | 3815.4 | TEP-203(?) | TERAS_POST | 1 | 68.59 | 0.009 | 0.002 | 1.834 | TEPd-1009(?) | 3815.36 | 1.7894 | 0.00877533 | 68.8863
RAAM | Pööningukorrus | 0.8 | 0.23 | +16.590 | +16.710 | 34.3 | 1900 | TRM-201(?) | RAAM | 16 | 34.16 | 0.004 | 0.228 | 0.914 |  | 1900 | 0.891099 | 0.00436999 | 34.3045 | Pset_BeamCommon - Reference: TRMd-4(?)
2 x TERAS_POST | Pööningukorrus | 0.8 | 0 | +16.710 | +18.564 | 33.5 | 1854.3 | TEP-302(?) | TERAS_POST | 1 | 33.33 | 0.004 | 0.002 | 0.892 | TEPd-2(?) | 1854.32 | 0.869676 | 0.00426494 | 33.4797
2 x RAAM | Pööningukorrus | 1 | 0.25 | +16.590 | +16.710 | 38.3 | 2119.2 | TRM-203(?) | RAAM | 16 | 38.1 | 0.005 | 0.254 | 1.02 |  | 2119.24 | 0.993924 | 0.00487425 | 38.2629 | Pset_BeamCommon - Reference: TRMd-11(?)
RAAM | Pööningukorrus | 0.8 | 0.23 | +16.590 | +16.710 | 34.3 | 1900 | TRM-202(?) | RAAM | 16 | 34.16 | 0.004 | 0.228 | 0.914 |  | 1900 | 0.891099 | 0.00436999 | 34.3045 | Pset_BeamCommon - Reference: TRMd-4(?)

# IfcBuildingElementProxy: Tehnoloogiamajakas-logo
In: 1.korrus
Classification: 1.02 IfcBuildingElementProxyType (objekt) (IPI ÜBN)
AR_ÜLD - 001_Nimetus: Tehnoloogiamajaks logo
AC_Pset_RenovationAndPhasing - Renovation Status: Existing

# IfcColumn: GENEERILINE - KONSTRUKTRIOON 1030 x 500 (2)
In: 1.korrus
Classification: 1.03 IfcColumnType (post) (IPI ÜBN); Material: GENEERILINE - KONSTRUKTRIOON
AR_ÜLD - 001_Nimetus: Post
AC_Pset_RenovationAndPhasing - Renovation Status: Existing
BaseQuantities - Width: 1030 mm; Depth: 500 mm; CrossSectionArea: 0.515 m2
Name | Length (mm) | OuterSurfaceArea (m2) | TotalSurfaceArea (m2) = GrossSurfaceArea (m2) | GrossVolume (m3) = NetVolume (m3)
 | 4500 | 13.77 | 14.8 | 2.3175
 | 4410 | 13.4946 | 14.5246 | 2.27115

# IfcColumn: GENEERILINE - KONSTRUKTRIOON 150 x 150
In: 1.korrus
Classification: 1.03 IfcColumnType (post) (IPI ÜBN); Material: GENEERILINE - KONSTRUKTRIOON
BaseQuantities - Length: 5800 mm; Width: 150 mm; Depth: 150 mm; CrossSectionArea: 0.0225 m2; OuterSurfaceArea: 3.48 m2; TotalSurfaceArea: 3.525 m2; GrossSurfaceArea: 3.525 m2; GrossVolume: 0.1305 m3; NetVolume: 0.1305 m3
AC_Pset_RenovationAndPhasing - Renovation Status: Existing
AR_ÜLD - 001_Nimetus: Olemasolev post

# IfcColumn: GENEERILINE - KONSTRUKTRIOON 155 x 155 (6)
In: 1.korrus
Classification: 1.03 IfcColumnType (post) (IPI ÜBN); Material: GENEERILINE - KONSTRUKTRIOON
AR_ÜLD - 001_Nimetus: Post
AC_Pset_RenovationAndPhasing - Renovation Status: Existing
BaseQuantities - Width: 155 mm; Depth: 155 mm; CrossSectionArea: 0.024025 m2
Name | Length (mm) | OuterSurfaceArea (m2) | TotalSurfaceArea (m2) = GrossSurfaceArea (m2) | GrossVolume (m3) = NetVolume (m3)
 | 2910 | 1.8042 | 1.85225 | 0.0699128
 | 3700 | 2.294 | 2.34205 | 0.0888925
 | 4009.68 | 2.486 | 2.53405 | 0.0963326
3 x  | 2460 | 1.5252 | 1.57325 | 0.0591015

# IfcColumn: GENEERILINE - KONSTRUKTRIOON 175 x 450
In: 1.korrus
Classification: 1.03 IfcColumnType (post) (IPI ÜBN); Material: GENEERILINE - KONSTRUKTRIOON
AC_Pset_RenovationAndPhasing - Renovation Status: Existing
BaseQuantities - Length: 5090 mm; Width: 175 mm; Depth: 450 mm; CrossSectionArea: 0.07875 m2; OuterSurfaceArea: 6.3625 m2; TotalSurfaceArea: 6.52 m2; GrossSurfaceArea: 6.52 m2; GrossVolume: 0.400838 m3; NetVolume: 0.400838 m3
AR_ÜLD - 001_Nimetus: Post

# IfcColumn: GENEERILINE - KONSTRUKTRIOON 200 x 75 (107)
In: 1.korrus
Classification: 1.03 IfcColumnType (post) (IPI ÜBN); Material: GENEERILINE - KONSTRUKTRIOON
BaseQuantities - Width: 200 mm; Depth: 75 mm; CrossSectionArea: 0.015 m2
AC_Pset_RenovationAndPhasing - Renovation Status: New
Name | Length (mm) | OuterSurfaceArea (m2) | TotalSurfaceArea (m2) = GrossSurfaceArea (m2) | GrossVolume (m3) = NetVolume (m3)
51 x Varjestus_viltu | 7670.75 | 4.21711 | 4.24716 | 0.115012
Varjestus_viltu | 8376.79 | 4.60543 | 4.63549 | 0.125603
10 x Varjestus_viltu | 8370.61 | 4.60203 | 4.63209 | 0.12551
Varjestus_viltu | 7887.66 | 4.33641 | 4.36647 | 0.118266
8 x Varjestus_viltu | 7810.35 | 4.28096 | 4.29596 | 0.116753
3 x Varjestus_viltu | 8373.62 | 4.59996 | 4.61496 | 0.125454
4 x Varjestus_viltu | 8373.61 | 4.59996 | 4.61496 | 0.125453
Varjestus_viltu | 8373.6 | 4.59996 | 4.61496 | 0.125453
4 x Varjestus_viltu | 8373.6 | 4.59995 | 4.61495 | 0.125453
Varjestus_viltu | 7909.14 | 4.3357 | 4.3507 | 0.118246
5 x Varjestus_viltu | 8434.23 | 4.6333 | 4.66383 | 0.126363
Varjestus_viltu | 8434.22 | 4.6333 | 4.66383 | 0.126363
Varjestus_viltu | 8434.22 | 4.6333 | 4.66382 | 0.126363
Varjestus_viltu | 8434.22 | 4.63329 | 4.66382 | 0.126363
Varjestus_viltu | 8432.97 | 4.63261 | 4.66314 | 0.126344
2 x Varjestus_viltu | 8434.21 | 4.63329 | 4.66382 | 0.126362
3 x Varjestus_viltu | 8373.65 | 4.59998 | 4.61498 | 0.125454
Varjestus_viltu | 8389.57 | 4.60874 | 4.62374 | 0.125693
Varjestus_viltu | 8273.17 | 4.54472 | 4.55972 | 0.123947
Varjestus_viltu | 8353.56 | 4.58893 | 4.60393 | 0.125153
Varjestus_viltu | 8112.41 | 4.4563 | 4.4713 | 0.121535
Varjestus_viltu | 8192.79 | 4.50051 | 4.51551 | 0.122741
Varjestus_viltu | 7951.64 | 4.36787 | 4.38287 | 0.119124
Varjestus_viltu | 8032.02 | 4.41208 | 4.42708 | 0.12033
Varjestus_viltu | 8463.61 | 4.65318 | 4.68324 | 0.126905
Varjestus_viltu | 7815.36 | 4.29664 | 4.3267 | 0.117181

# IfcColumn: GENEERILINE - KONSTRUKTRIOON 220 x 450 (3)
In: 1.korrus
Classification: 1.03 IfcColumnType (post) (IPI ÜBN); Material: GENEERILINE - KONSTRUKTRIOON
AC_Pset_RenovationAndPhasing - Renovation Status: Existing
AR_ÜLD - 001_Nimetus: Post
BaseQuantities - Length: 5090 mm; Width: 220 mm; Depth: 450 mm; CrossSectionArea: 0.099 m2; OuterSurfaceArea: 6.8206 m2; TotalSurfaceArea: 7.0186 m2; GrossSurfaceArea: 7.0186 m2; GrossVolume: 0.50391 m3; NetVolume: 0.50391 m3

# IfcColumn: GENEERILINE - KONSTRUKTRIOON 225 x 75 (53)
In: 1.korrus
Classification: 1.03 IfcColumnType (post) (IPI ÜBN); Material: GENEERILINE - KONSTRUKTRIOON
AC_Pset_RenovationAndPhasing - Renovation Status: New
BaseQuantities - Length: 600 mm; Width: 225 mm; Depth: 75 mm; CrossSectionArea: 0.016875 m2; OuterSurfaceArea: 0.358032 m2; TotalSurfaceArea: 0.391846 m2; GrossSurfaceArea: 0.391846 m2; GrossVolume: 0.0100696 m3; NetVolume: 0.0100696 m3

# IfcColumn: GENEERILINE - KONSTRUKTRIOON 250 x 275
In: 1.korrus
Classification: 1.03 IfcColumnType (post) (IPI ÜBN); Material: GENEERILINE - KONSTRUKTRIOON
AC_Pset_RenovationAndPhasing - Renovation Status: Existing
AR_ÜLD - 001_Nimetus: Post
BaseQuantities - Length: 4858.9 mm; Width: 250 mm; Depth: 275 mm; CrossSectionArea: 0.0687501 m2; OuterSurfaceArea: 5.06968 m2; TotalSurfaceArea: 5.13844 m2; GrossSurfaceArea: 5.13844 m2; GrossVolume: 0.331944 m3; NetVolume: 0.331944 m3

# IfcColumn: GENEERILINE - KONSTRUKTRIOON 270 x 275
In: 1.korrus
Classification: 1.03 IfcColumnType (post) (IPI ÜBN); Material: GENEERILINE - KONSTRUKTRIOON
BaseQuantities - Length: 4872.1 mm; Width: 270.002 mm; Depth: 275 mm; CrossSectionArea: 0.0742507 m2; OuterSurfaceArea: 5.27478 m2; TotalSurfaceArea: 5.34903 m2; GrossSurfaceArea: 5.34903 m2; GrossVolume: 0.359316 m3; NetVolume: 0.359316 m3
AR_ÜLD - 001_Nimetus: Post
AC_Pset_RenovationAndPhasing - Renovation Status: Existing

# IfcColumn: GENEERILINE - KONSTRUKTRIOON 275 x 270
In: 1.korrus
Classification: 1.03 IfcColumnType (post) (IPI ÜBN); Material: GENEERILINE - KONSTRUKTRIOON
AC_Pset_RenovationAndPhasing - Renovation Status: Existing
AR_ÜLD - 001_Nimetus: Post
BaseQuantities - Length: 5710.39 mm; Width: 275.004 mm; Depth: 270 mm; CrossSectionArea: 0.0742511 m2; OuterSurfaceArea: 6.18756 m2; TotalSurfaceArea: 6.26182 m2; GrossSurfaceArea: 6.26182 m2; GrossVolume: 0.421496 m3; NetVolume: 0.421496 m3

# IfcColumn: GENEERILINE - KONSTRUKTRIOON 275 x 275
In: 1.korrus
Classification: 1.03 IfcColumnType (post) (IPI ÜBN); Material: GENEERILINE - KONSTRUKTRIOON
AC_Pset_RenovationAndPhasing - Renovation Status: Existing
BaseQuantities - Length: 5816.07 mm; Width: 275.004 mm; Depth: 275 mm; CrossSectionArea: 0.0756263 m2; OuterSurfaceArea: 6.36083 m2; TotalSurfaceArea: 6.43645 m2; GrossSurfaceArea: 6.43645 m2; GrossVolume: 0.43731 m3; NetVolume: 0.43731 m3
AR_ÜLD - 001_Nimetus: Post

# IfcColumn: GENEERILINE - KONSTRUKTRIOON 300 x 100 (40)
Classification: 1.03 IfcColumnType (post) (IPI ÜBN); Material: GENEERILINE - KONSTRUKTRIOON
BaseQuantities - Width: 300 mm; Depth: 100 mm; CrossSectionArea: 0.03 m2
AC_Pset_RenovationAndPhasing - Renovation Status: New
Name | In | Length (mm) | OuterSurfaceArea (m2) | TotalSurfaceArea (m2) = GrossSurfaceArea (m2) | GrossVolume (m3) = NetVolume (m3) | 001_Nimetus
Varjestus_viltu | 1.korrus | 7706.83 | 6.16546 | 6.22546 | 0.231205
7 x Esif_varjestus_vertik | 1.korrus | 7706.83 | 6.16546 | 6.22546 | 0.231205 | Puiribi
32 x Esif_varjestus_vertik | 2.korrus | 4221.83 | 3.37746 | 3.43746 | 0.126655 | Puiribi

# IfcColumn: GENEERILINE - KONSTRUKTRIOON 350 x 390
In: 1.korrus
Classification: 1.03 IfcColumnType (post) (IPI ÜBN); Material: GENEERILINE - KONSTRUKTRIOON
AR_ÜLD - 001_Nimetus: Post
AC_Pset_RenovationAndPhasing - Renovation Status: Existing
BaseQuantities - Length: 5900 mm; Width: 350 mm; Depth: 390 mm; CrossSectionArea: 0.1365 m2; OuterSurfaceArea: 8.732 m2; TotalSurfaceArea: 9.005 m2; GrossSurfaceArea: 9.005 m2; GrossVolume: 0.80535 m3; NetVolume: 0.80535 m3

# IfcColumn: GENEERILINE - KONSTRUKTRIOON 360 x 400
In: 1.korrus
Classification: 1.03 IfcColumnType (post) (IPI ÜBN); Material: GENEERILINE - KONSTRUKTRIOON
AC_Pset_RenovationAndPhasing - Renovation Status: Existing
AR_ÜLD - 001_Nimetus: Post
BaseQuantities - Length: 5950 mm; Width: 360.001 mm; Depth: 400 mm; CrossSectionArea: 0.144001 m2; OuterSurfaceArea: 9.04402 m2; TotalSurfaceArea: 9.33202 m2; GrossSurfaceArea: 9.33202 m2; GrossVolume: 0.856803 m3; NetVolume: 0.856803 m3

# IfcColumn: GENEERILINE - KONSTRUKTRIOON 390 x 400
In: 2.korrus
Classification: 1.03 IfcColumnType (post) (IPI ÜBN); Material: GENEERILINE - KONSTRUKTRIOON
AR_ÜLD - 001_Nimetus: Post
AC_Pset_RenovationAndPhasing - Renovation Status: Existing
BaseQuantities - Length: 2480 mm; Width: 390 mm; Depth: 400 mm; CrossSectionArea: 0.156 m2; OuterSurfaceArea: 3.9184 m2; TotalSurfaceArea: 4.2304 m2; GrossSurfaceArea: 4.2304 m2; GrossVolume: 0.38688 m3; NetVolume: 0.38688 m3

# IfcColumn: GENEERILINE - KONSTRUKTRIOON 390 x 675
In: 1.korrus
Classification: 1.03 IfcColumnType (post) (IPI ÜBN); Material: GENEERILINE - KONSTRUKTRIOON
AR_ÜLD - 001_Nimetus: Post
AC_Pset_RenovationAndPhasing - Renovation Status: Existing
BaseQuantities - Length: 4000 mm; Width: 390 mm; Depth: 675 mm; CrossSectionArea: 0.26325 m2; OuterSurfaceArea: 8.52 m2; TotalSurfaceArea: 9.0465 m2; GrossSurfaceArea: 9.0465 m2; GrossVolume: 1.053 m3; NetVolume: 1.053 m3

# IfcColumn: GENEERILINE - KONSTRUKTRIOON 391 x 250 (3)
In: 1.korrus
Classification: 1.03 IfcColumnType (post) (IPI ÜBN); Material: GENEERILINE - KONSTRUKTRIOON
AR_ÜLD - 001_Nimetus: Post
AC_Pset_RenovationAndPhasing - Renovation Status: Existing
BaseQuantities - Length: 2350 mm; Width: 390.662 mm; Depth: 250.002 mm; CrossSectionArea: 0.097666 m2; OuterSurfaceArea: 3.01112 m2; TotalSurfaceArea: 3.20645 m2; GrossSurfaceArea: 3.20645 m2; GrossVolume: 0.229515 m3; NetVolume: 0.229515 m3

# IfcColumn: GENEERILINE - KONSTRUKTRIOON 400 x 175 (2)
In: 1.korrus
Classification: 1.03 IfcColumnType (post) (IPI ÜBN); Material: GENEERILINE - KONSTRUKTRIOON
AR_ÜLD - 001_Nimetus: Post
AC_Pset_RenovationAndPhasing - Renovation Status: Existing
BaseQuantities - Length: 5450 mm; Width: 400.001 mm; Depth: 175 mm; CrossSectionArea: 0.0700002 m2; OuterSurfaceArea: 6.26751 m2; TotalSurfaceArea: 6.40751 m2; GrossSurfaceArea: 6.40751 m2; GrossVolume: 0.381501 m3; NetVolume: 0.381501 m3

# IfcColumn: GENEERILINE - KONSTRUKTRIOON 400 x 286 (3)
In: 1.korrus
Classification: 1.03 IfcColumnType (post) (IPI ÜBN); Material: GENEERILINE - KONSTRUKTRIOON
AR_ÜLD - 001_Nimetus: Post
BaseQuantities - Length: 6470 mm; Width: 400 mm; Depth: 285.609 mm; CrossSectionArea: 0.114244 m2; OuterSurfaceArea: 8.87178 m2; TotalSurfaceArea: 9.10027 m2; GrossSurfaceArea: 9.10027 m2; GrossVolume: 0.739156 m3; NetVolume: 0.739156 m3
AC_Pset_RenovationAndPhasing - Renovation Status: Existing

# IfcColumn: GENEERILINE - KONSTRUKTRIOON 400 x 400 (25)
In: 1.korrus
Classification: 1.03 IfcColumnType (post) (IPI ÜBN); Material: GENEERILINE - KONSTRUKTRIOON
AR_ÜLD - 001_Nimetus: Post
AC_Pset_RenovationAndPhasing - Renovation Status: Existing
BaseQuantities - Width: 400 mm; Depth: 400 mm; CrossSectionArea: 0.16 m2
Name | Length (mm) | OuterSurfaceArea (m2) | TotalSurfaceArea (m2) = GrossSurfaceArea (m2) | GrossVolume (m3) = NetVolume (m3)
3 x  | 5450 | 8.72 | 9.04 | 0.872
5 x  | 4240 | 6.784 | 7.104 | 0.6784
12 x  | 4450 | 7.12 | 7.44 | 0.712
5 x  | 4270 | 6.832 | 7.152 | 0.6832

# IfcColumn: GENEERILINE - KONSTRUKTRIOON 400 x 640 (2)
In: 1.korrus
Classification: 1.03 IfcColumnType (post) (IPI ÜBN); Material: GENEERILINE - KONSTRUKTRIOON
AR_ÜLD - 001_Nimetus: Post
AC_Pset_RenovationAndPhasing - Renovation Status: Existing
BaseQuantities - Length: 4150 mm; Width: 400 mm; Depth: 640 mm; CrossSectionArea: 0.256 m2; OuterSurfaceArea: 8.632 m2; TotalSurfaceArea: 9.144 m2; GrossSurfaceArea: 9.144 m2; GrossVolume: 1.0624 m3; NetVolume: 1.0624 m3

# IfcColumn: GENEERILINE - KONSTRUKTRIOON 400 x 660
In: 1.korrus
Classification: 1.03 IfcColumnType (post) (IPI ÜBN); Material: GENEERILINE - KONSTRUKTRIOON
AR_ÜLD - 001_Nimetus: Post
BaseQuantities - Length: 4000 mm; Width: 400 mm; Depth: 660 mm; CrossSectionArea: 0.264 m2; OuterSurfaceArea: 8.48 m2; TotalSurfaceArea: 9.008 m2; GrossSurfaceArea: 9.008 m2; GrossVolume: 1.056 m3; NetVolume: 1.056 m3
AC_Pset_RenovationAndPhasing - Renovation Status: Existing

# IfcColumn: GENEERILINE - KONSTRUKTRIOON 420 x 130
In: 1.korrus
Classification: 1.03 IfcColumnType (post) (IPI ÜBN); Material: GENEERILINE - KONSTRUKTRIOON
AC_Pset_RenovationAndPhasing - Renovation Status: Existing
AR_ÜLD - 001_Nimetus: Post
BaseQuantities - Length: 4300 mm; Width: 420 mm; Depth: 130.001 mm; CrossSectionArea: 0.0546006 m2; OuterSurfaceArea: 4.73001 m2; TotalSurfaceArea: 4.83921 m2; GrossSurfaceArea: 4.83921 m2; GrossVolume: 0.234783 m3; NetVolume: 0.234783 m3

# IfcColumn: GENEERILINE - KONSTRUKTRIOON 420 x 140 (2)
In: 1.korrus
Classification: 1.03 IfcColumnType (post) (IPI ÜBN); Material: GENEERILINE - KONSTRUKTRIOON
AR_ÜLD - 001_Nimetus: Post
AC_Pset_RenovationAndPhasing - Renovation Status: Existing
BaseQuantities - Length: 4300 mm; Width: 420 mm; Depth: 140 mm; CrossSectionArea: 0.0588001 m2; OuterSurfaceArea: 4.816 m2; TotalSurfaceArea: 4.9336 m2; GrossSurfaceArea: 4.9336 m2; GrossVolume: 0.25284 m3; NetVolume: 0.25284 m3

# IfcColumn: GENEERILINE - KONSTRUKTRIOON 420 x 410
In: 1.korrus
Classification: 1.03 IfcColumnType (post) (IPI ÜBN); Material: GENEERILINE - KONSTRUKTRIOON
AR_ÜLD - 001_Nimetus: Post
AC_Pset_RenovationAndPhasing - Renovation Status: Existing
BaseQuantities - Length: 5950 mm; Width: 420 mm; Depth: 410 mm; CrossSectionArea: 0.1722 m2; OuterSurfaceArea: 9.877 m2; TotalSurfaceArea: 10.2214 m2; GrossSurfaceArea: 10.2214 m2; GrossVolume: 1.02459 m3; NetVolume: 1.02459 m3

# IfcColumn: GENEERILINE - KONSTRUKTRIOON 420 x 420
In: 1.korrus
Classification: 1.03 IfcColumnType (post) (IPI ÜBN); Material: GENEERILINE - KONSTRUKTRIOON
AR_ÜLD - 001_Nimetus: Post
AC_Pset_RenovationAndPhasing - Renovation Status: Existing
BaseQuantities - Length: 4250 mm; Width: 420 mm; Depth: 420 mm; CrossSectionArea: 0.1764 m2; OuterSurfaceArea: 7.14 m2; TotalSurfaceArea: 7.4928 m2; GrossSurfaceArea: 7.4928 m2; GrossVolume: 0.7497 m3; NetVolume: 0.7497 m3

# IfcColumn: GENEERILINE - KONSTRUKTRIOON 420 x 430 (2)
In: 1.korrus
Classification: 1.03 IfcColumnType (post) (IPI ÜBN); Material: GENEERILINE - KONSTRUKTRIOON
AR_ÜLD - 001_Nimetus: Post
AC_Pset_RenovationAndPhasing - Renovation Status: Existing
BaseQuantities - Length: 4250 mm; Width: 420 mm; Depth: 430 mm; CrossSectionArea: 0.1806 m2; OuterSurfaceArea: 7.225 m2; TotalSurfaceArea: 7.5862 m2; GrossSurfaceArea: 7.5862 m2; GrossVolume: 0.76755 m3; NetVolume: 0.76755 m3

# IfcColumn: GENEERILINE - KONSTRUKTRIOON 420 x 475
In: 1.korrus
Classification: 1.03 IfcColumnType (post) (IPI ÜBN); Material: GENEERILINE - KONSTRUKTRIOON
AR_ÜLD - 001_Nimetus: Post
BaseQuantities - Length: 5950 mm; Width: 420 mm; Depth: 475 mm; CrossSectionArea: 0.1995 m2; OuterSurfaceArea: 10.6505 m2; TotalSurfaceArea: 11.0495 m2; GrossSurfaceArea: 11.0495 m2; GrossVolume: 1.18703 m3; NetVolume: 1.18703 m3
AC_Pset_RenovationAndPhasing - Renovation Status: Existing

# IfcColumn: GENEERILINE - KONSTRUKTRIOON 420 x 500 (2)
In: 1.korrus
Classification: 1.03 IfcColumnType (post) (IPI ÜBN); Material: GENEERILINE - KONSTRUKTRIOON
BaseQuantities - Width: 420 mm; Depth: 500 mm; CrossSectionArea: 0.21 m2
AC_Pset_RenovationAndPhasing - Renovation Status: Existing
AR_ÜLD - 001_Nimetus: Post
Name | Length (mm) | OuterSurfaceArea (m2) | TotalSurfaceArea (m2) = GrossSurfaceArea (m2) | GrossVolume (m3) = NetVolume (m3)
 | 5900 | 10.856 | 11.276 | 1.239
 | 4000 | 7.36 | 7.78 | 0.84

# IfcColumn: GENEERILINE - KONSTRUKTRIOON 420 x 670
In: 1.korrus
Classification: 1.03 IfcColumnType (post) (IPI ÜBN); Material: GENEERILINE - KONSTRUKTRIOON
AC_Pset_RenovationAndPhasing - Renovation Status: Existing
BaseQuantities - Length: 3660 mm; Width: 420 mm; Depth: 670 mm; CrossSectionArea: 0.2814 m2; OuterSurfaceArea: 7.9788 m2; TotalSurfaceArea: 8.5416 m2; GrossSurfaceArea: 8.5416 m2; GrossVolume: 1.02992 m3; NetVolume: 1.02992 m3
AR_ÜLD - 001_Nimetus: Post

# IfcColumn: GENEERILINE - KONSTRUKTRIOON 420 x 809
In: 1.korrus
Classification: 1.03 IfcColumnType (post) (IPI ÜBN); Material: GENEERILINE - KONSTRUKTRIOON
AR_ÜLD - 001_Nimetus: Post
AC_Pset_RenovationAndPhasing - Renovation Status: Existing
BaseQuantities - Length: 3660 mm; Width: 420 mm; Depth: 808.606 mm; CrossSectionArea: 0.339614 m2; OuterSurfaceArea: 8.99339 m2; TotalSurfaceArea: 9.67262 m2; GrossSurfaceArea: 9.67262 m2; GrossVolume: 1.24299 m3; NetVolume: 1.24299 m3

# IfcColumn: GENEERILINE - KONSTRUKTRIOON 450 x 210
In: 1.korrus
Classification: 1.03 IfcColumnType (post) (IPI ÜBN); Material: GENEERILINE - KONSTRUKTRIOON
AR_ÜLD - 001_Nimetus: Post
AC_Pset_RenovationAndPhasing - Renovation Status: Existing
BaseQuantities - Length: 5450 mm; Width: 450 mm; Depth: 210 mm; CrossSectionArea: 0.0945001 m2; OuterSurfaceArea: 7.194 m2; TotalSurfaceArea: 7.383 m2; GrossSurfaceArea: 7.383 m2; GrossVolume: 0.515025 m3; NetVolume: 0.515025 m3

# IfcColumn: GENEERILINE - KONSTRUKTRIOON 450 x 400 (3)
In: 1.korrus
Classification: 1.03 IfcColumnType (post) (IPI ÜBN); Material: GENEERILINE - KONSTRUKTRIOON
AR_ÜLD - 001_Nimetus: Post
AC_Pset_RenovationAndPhasing - Renovation Status: Existing
BaseQuantities - Length: 4650 mm; Width: 450 mm; Depth: 400 mm; CrossSectionArea: 0.18 m2; OuterSurfaceArea: 7.905 m2; TotalSurfaceArea: 8.265 m2; GrossSurfaceArea: 8.265 m2; GrossVolume: 0.837 m3; NetVolume: 0.837 m3

# IfcColumn: GENEERILINE - KONSTRUKTRIOON 450 x 675
In: 1.korrus
Classification: 1.03 IfcColumnType (post) (IPI ÜBN); Material: GENEERILINE - KONSTRUKTRIOON
AR_ÜLD - 001_Nimetus: Post
BaseQuantities - Length: 4000 mm; Width: 450 mm; Depth: 675 mm; CrossSectionArea: 0.30375 m2; OuterSurfaceArea: 9 m2; TotalSurfaceArea: 9.6075 m2; GrossSurfaceArea: 9.6075 m2; GrossVolume: 1.215 m3; NetVolume: 1.215 m3
AC_Pset_RenovationAndPhasing - Renovation Status: Existing

# IfcColumn: GENEERILINE - KONSTRUKTRIOON 460 x 390 (5)
In: 1.korrus
Classification: 1.03 IfcColumnType (post) (IPI ÜBN); Material: GENEERILINE - KONSTRUKTRIOON
AC_Pset_RenovationAndPhasing - Renovation Status: Existing
BaseQuantities - Width: 460 mm; Depth: 390 mm; CrossSectionArea: 0.1794 m2
AR_ÜLD - 001_Nimetus: Post
Name | Length (mm) | OuterSurfaceArea (m2) | TotalSurfaceArea (m2) = GrossSurfaceArea (m2) | GrossVolume (m3) = NetVolume (m3)
2 x  | 4000 | 6.8 | 7.1588 | 0.7176
2 x  | 4630 | 7.871 | 8.2298 | 0.830622
 | 3988.13 | 6.77982 | 7.13862 | 0.715471

# IfcColumn: GENEERILINE - KONSTRUKTRIOON 460 x 460
In: 1.korrus
Classification: 1.03 IfcColumnType (post) (IPI ÜBN); Material: GENEERILINE - KONSTRUKTRIOON
AR_ÜLD - 001_Nimetus: Post
AC_Pset_RenovationAndPhasing - Renovation Status: Existing
BaseQuantities - Length: 5090 mm; Width: 460 mm; Depth: 460 mm; CrossSectionArea: 0.2116 m2; OuterSurfaceArea: 9.3656 m2; TotalSurfaceArea: 9.7888 m2; GrossSurfaceArea: 9.7888 m2; GrossVolume: 1.07704 m3; NetVolume: 1.07704 m3

# IfcColumn: GENEERILINE - KONSTRUKTRIOON 480 x 400
In: 2.korrus
Classification: 1.03 IfcColumnType (post) (IPI ÜBN); Material: GENEERILINE - KONSTRUKTRIOON
AR_ÜLD - 001_Nimetus: Post
AC_Pset_RenovationAndPhasing - Renovation Status: Existing
BaseQuantities - Length: 2460 mm; Width: 480 mm; Depth: 400 mm; CrossSectionArea: 0.192 m2; OuterSurfaceArea: 4.3296 m2; TotalSurfaceArea: 4.7136 m2; GrossSurfaceArea: 4.7136 m2; GrossVolume: 0.47232 m3; NetVolume: 0.47232 m3

# IfcColumn: GENEERILINE - KONSTRUKTRIOON 500 x 400
In: 1.korrus
Classification: 1.03 IfcColumnType (post) (IPI ÜBN); Material: GENEERILINE - KONSTRUKTRIOON
AR_ÜLD - 001_Nimetus: Post
BaseQuantities - Length: 5950 mm; Width: 500 mm; Depth: 400 mm; CrossSectionArea: 0.2 m2; OuterSurfaceArea: 10.71 m2; TotalSurfaceArea: 11.11 m2; GrossSurfaceArea: 11.11 m2; GrossVolume: 1.19 m3; NetVolume: 1.19 m3
AC_Pset_RenovationAndPhasing - Renovation Status: Existing

# IfcColumn: GENEERILINE - KONSTRUKTRIOON 530 x 270 (2)
In: 1.korrus
Classification: 1.03 IfcColumnType (post) (IPI ÜBN); Material: GENEERILINE - KONSTRUKTRIOON
AR_ÜLD - 001_Nimetus: Post
AC_Pset_RenovationAndPhasing - Renovation Status: Existing
BaseQuantities - Width: 530 mm
Name | Length (mm) | Depth (mm) | CrossSectionArea (m2) | OuterSurfaceArea (m2) | TotalSurfaceArea (m2) = GrossSurfaceArea (m2) | GrossVolume (m3) = NetVolume (m3)
 | 6145.32 | 270.002 | 0.143101 | 9.71779 | 9.8609 | 0.869139
 | 6686.55 | 270 | 0.1431 | 10.5837 | 10.7268 | 0.946585

# IfcColumn: GENEERILINE - KONSTRUKTRIOON 539 x 240
In: 1.korrus
Classification: 1.03 IfcColumnType (post) (IPI ÜBN); Material: GENEERILINE - KONSTRUKTRIOON
AR_ÜLD - 001_Nimetus: Post
AC_Pset_RenovationAndPhasing - Renovation Status: Existing
BaseQuantities - Length: 4866.51 mm; Width: 538.758 mm; Depth: 240.003 mm; CrossSectionArea: 0.129303 m2; OuterSurfaceArea: 7.47686 m2; TotalSurfaceArea: 7.60616 m2; GrossSurfaceArea: 7.60616 m2; GrossVolume: 0.620718 m3; NetVolume: 0.620718 m3

# IfcColumn: GENEERILINE - KONSTRUKTRIOON 539 x 271
In: 1.korrus
Classification: 1.03 IfcColumnType (post) (IPI ÜBN); Material: GENEERILINE - KONSTRUKTRIOON
AR_ÜLD - 001_Nimetus: Post
AC_Pset_RenovationAndPhasing - Renovation Status: Existing
BaseQuantities - Length: 5673.5 mm; Width: 539.432 mm; Depth: 271.235 mm; CrossSectionArea: 0.146313 m2; OuterSurfaceArea: 9.0803 m2; TotalSurfaceArea: 9.22661 m2; GrossSurfaceArea: 9.22661 m2; GrossVolume: 0.819427 m3; NetVolume: 0.819427 m3

# IfcColumn: GENEERILINE - KONSTRUKTRIOON 540 x 240
In: 1.korrus
Classification: 1.03 IfcColumnType (post) (IPI ÜBN); Material: GENEERILINE - KONSTRUKTRIOON
AR_ÜLD - 001_Nimetus: Post
AC_Pset_RenovationAndPhasing - Renovation Status: Existing
BaseQuantities - Length: 5296.78 mm; Width: 540 mm; Depth: 240.003 mm; CrossSectionArea: 0.129601 m2; OuterSurfaceArea: 8.15977 m2; TotalSurfaceArea: 8.28937 m2; GrossSurfaceArea: 8.28937 m2; GrossVolume: 0.677893 m3; NetVolume: 0.677893 m3

# IfcColumn: GENEERILINE - KONSTRUKTRIOON 540 x 250
In: 1.korrus
Classification: 1.03 IfcColumnType (post) (IPI ÜBN); Material: GENEERILINE - KONSTRUKTRIOON
AR_ÜLD - 001_Nimetus: Post
BaseQuantities - Length: 5786.97 mm; Width: 540 mm; Depth: 250 mm; CrossSectionArea: 0.135 m2; OuterSurfaceArea: 9.03885 m2; TotalSurfaceArea: 9.17385 m2; GrossSurfaceArea: 9.17385 m2; GrossVolume: 0.772307 m3; NetVolume: 0.772307 m3
AC_Pset_RenovationAndPhasing - Renovation Status: Existing

# IfcColumn: GENEERILINE - KONSTRUKTRIOON 540 x 260
In: 1.korrus
Classification: 1.03 IfcColumnType (post) (IPI ÜBN); Material: GENEERILINE - KONSTRUKTRIOON
AR_ÜLD - 001_Nimetus: Post
AC_Pset_RenovationAndPhasing - Renovation Status: Existing
BaseQuantities - Length: 6206.11 mm; Width: 540 mm; Depth: 260 mm; CrossSectionArea: 0.1404 m2; OuterSurfaceArea: 9.85986 m2; TotalSurfaceArea: 10.0003 m2; GrossSurfaceArea: 10.0003 m2; GrossVolume: 0.866708 m3; NetVolume: 0.866708 m3

# IfcColumn: GENEERILINE - KONSTRUKTRIOON 540 x 270 (3)
In: 1.korrus
Classification: 1.03 IfcColumnType (post) (IPI ÜBN); Material: GENEERILINE - KONSTRUKTRIOON
AR_ÜLD - 001_Nimetus: Post
AC_Pset_RenovationAndPhasing - Renovation Status: Existing
BaseQuantities - Width: 540 mm; Depth: 270 mm; CrossSectionArea: 0.1458 m2
Name | Length (mm) | OuterSurfaceArea (m2) | TotalSurfaceArea (m2) = GrossSurfaceArea (m2) | GrossVolume (m3) = NetVolume (m3)
 | 7155.15 | 11.5126 | 11.6584 | 1.0379
 | 6150.09 | 9.84555 | 9.99135 | 0.886099
 | 6690.48 | 10.721 | 10.8668 | 0.964889

# IfcColumn: GENEERILINE - KONSTRUKTRIOON 550 x 260
In: 1.korrus
Classification: 1.03 IfcColumnType (post) (IPI ÜBN); Material: GENEERILINE - KONSTRUKTRIOON
AR_ÜLD - 001_Nimetus: Post
AC_Pset_RenovationAndPhasing - Renovation Status: Existing
BaseQuantities - Length: 5784.9 mm; Width: 550 mm; Depth: 260 mm; CrossSectionArea: 0.143 m2; OuterSurfaceArea: 9.26307 m2; TotalSurfaceArea: 9.40607 m2; GrossSurfaceArea: 9.40607 m2; GrossVolume: 0.817666 m3; NetVolume: 0.817666 m3

# IfcColumn: GENEERILINE - KONSTRUKTRIOON 550 x 265
In: 1.korrus
Classification: 1.03 IfcColumnType (post) (IPI ÜBN); Material: GENEERILINE - KONSTRUKTRIOON
AC_Pset_RenovationAndPhasing - Renovation Status: Existing
AR_ÜLD - 001_Nimetus: Post
BaseQuantities - Length: 5297.92 mm; Width: 550 mm; Depth: 265 mm; CrossSectionArea: 0.14575 m2; OuterSurfaceArea: 8.52646 m2; TotalSurfaceArea: 8.67221 m2; GrossSurfaceArea: 8.67221 m2; GrossVolume: 0.762412 m3; NetVolume: 0.762412 m3

# IfcColumn: GENEERILINE - KONSTRUKTRIOON 550 x 270
In: 1.korrus
Classification: 1.03 IfcColumnType (post) (IPI ÜBN); Material: GENEERILINE - KONSTRUKTRIOON
AR_ÜLD - 001_Nimetus: Post
BaseQuantities - Length: 5679.65 mm; Width: 550 mm; Depth: 270.179 mm; CrossSectionArea: 0.148598 m2; OuterSurfaceArea: 9.19538 m2; TotalSurfaceArea: 9.34398 m2; GrossSurfaceArea: 9.34398 m2; GrossVolume: 0.833001 m3; NetVolume: 0.833001 m3
AC_Pset_RenovationAndPhasing - Renovation Status: Existing

# IfcColumn: GENEERILINE - KONSTRUKTRIOON 550 x 275 (3)
In: 1.korrus
Classification: 1.03 IfcColumnType (post) (IPI ÜBN); Material: GENEERILINE - KONSTRUKTRIOON
AR_ÜLD - 001_Nimetus: Post
AC_Pset_RenovationAndPhasing - Renovation Status: Existing
BaseQuantities - Width: 550.001 mm; Depth: 275 mm; CrossSectionArea: 0.151251 m2
Name | Length (mm) | OuterSurfaceArea (m2) | TotalSurfaceArea (m2) = GrossSurfaceArea (m2) | GrossVolume (m3) = NetVolume (m3)
 | 6206.11 | 10.1661 | 10.3174 | 0.933585
 | 5786.7 | 9.43759 | 9.58884 | 0.865114
 | 5297.25 | 8.63 | 8.78125 | 0.791085

# IfcColumn: GENEERILINE - KONSTRUKTRIOON 570 x 250
In: 1.korrus
Classification: 1.03 IfcColumnType (post) (IPI ÜBN); Material: GENEERILINE - KONSTRUKTRIOON
AR_ÜLD - 001_Nimetus: Post
AC_Pset_RenovationAndPhasing - Renovation Status: Existing
BaseQuantities - Length: 4872.1 mm; Width: 570 mm; Depth: 250 mm; CrossSectionArea: 0.1425 m2; OuterSurfaceArea: 7.87644 m2; TotalSurfaceArea: 8.01894 m2; GrossSurfaceArea: 8.01894 m2; GrossVolume: 0.684386 m3; NetVolume: 0.684386 m3

# IfcColumn: GENEERILINE - KONSTRUKTRIOON 600 x 275 (2)
In: 1.korrus
Classification: 1.03 IfcColumnType (post) (IPI ÜBN); Material: GENEERILINE - KONSTRUKTRIOON
AR_ÜLD - 001_Nimetus: Post
AC_Pset_RenovationAndPhasing - Renovation Status: Existing
BaseQuantities - Width: 600 mm; Depth: 275 mm; CrossSectionArea: 0.165 m2
Name | Length (mm) | OuterSurfaceArea (m2) | TotalSurfaceArea (m2) = GrossSurfaceArea (m2) | GrossVolume (m3) = NetVolume (m3)
 | 5780.26 | 9.98678 | 10.1518 | 0.941612
 | 5302.32 | 9.1504 | 9.3154 | 0.862753

# IfcColumn: GENEERILINE - KONSTRUKTRIOON 620 x 497
In: 1.korrus
Classification: 1.03 IfcColumnType (post) (IPI ÜBN); Material: GENEERILINE - KONSTRUKTRIOON
AR_ÜLD - 001_Nimetus: Post
AC_Pset_RenovationAndPhasing - Renovation Status: Existing
BaseQuantities - Length: 2760 mm; Width: 620 mm; Depth: 497.407 mm; CrossSectionArea: 0.308393 m2; OuterSurfaceArea: 6.16809 m2; TotalSurfaceArea: 6.78487 m2; GrossSurfaceArea: 6.78487 m2; GrossVolume: 0.851163 m3; NetVolume: 0.851163 m3

# IfcColumn: GENEERILINE - KONSTRUKTRIOON 700 x 380
In: 1.korrus
Classification: 1.03 IfcColumnType (post) (IPI ÜBN); Material: GENEERILINE - KONSTRUKTRIOON
AR_ÜLD - 001_Nimetus: Post
AC_Pset_RenovationAndPhasing - Renovation Status: Existing
BaseQuantities - Length: 4000 mm; Width: 700 mm; Depth: 380 mm; CrossSectionArea: 0.266 m2; OuterSurfaceArea: 8.64 m2; TotalSurfaceArea: 9.172 m2; GrossSurfaceArea: 9.172 m2; GrossVolume: 1.064 m3; NetVolume: 1.064 m3

# IfcColumn: GENEERILINE - KONSTRUKTRIOON 95 x 430
In: 1.korrus
Classification: 1.03 IfcColumnType (post) (IPI ÜBN); Material: GENEERILINE - KONSTRUKTRIOON
AR_ÜLD - 001_Nimetus: Post
AC_Pset_RenovationAndPhasing - Renovation Status: Existing
BaseQuantities - Length: 4200 mm; Width: 95 mm; Depth: 430 mm; CrossSectionArea: 0.04085 m2; OuterSurfaceArea: 4.41 m2; TotalSurfaceArea: 4.4917 m2; GrossSurfaceArea: 4.4917 m2; GrossVolume: 0.17157 m3; NetVolume: 0.17157 m3

# IfcColumn: IFC Footing Extruded (14)
In: 1.korrus
Description: RHS120*5; Classification: 1.03 IfcColumnType (post) (IPI ÜBN); Material: STEEL/S355
BaseQuantities - CrossSectionArea: 0.00229 m2; Width: 120 mm; Height: 120 mm
Tekla Quantity - Area per tons: 26.09 m2; Height: 120 mm; Width: 120 mm
Tekla Common - Phase: 1; Class: 1
EK_Vundament - 003_Ristlõige: RHS120*5; 135_Ruumala: 0 m3; 105_Tugevusklass: S355; 001_Nimetus: TERAS_POST
AR_ÜLD - 001_Nimetus: Post
AC_Pset_RenovationAndPhasing - Renovation Status: New
Name | BaseQuantities, Length (mm) | OuterSurfaceArea (m2) = GrossSurfaceArea (m2) | NetVolume (m3) | GrossVolume (m3) | NetWeight (kg) | GrossWeight (kg) | Weight (kg) | Volume (m3) | Gross footprint area (m2) | Net surface area (m2) | Tekla Quantity, Length (mm) | Bottom elevation = 195_Alumine-kõrgusmärk | Top elevation = 190_Ülemine-kõrgusmärk | 145_Pindala (m2) | 140_Mass (kg) | 125_Positsioon
TERAS_POST | 2628.82 | 1.23292 | 0.00604629 | 0.00602 | 47.4633 | 47.257 | 47.26 | 0.006 | 0.002 | 1.264 | 2628.8 | +9.814 | +12.442 | 0 | 47.5 | TEP-103(?)
6 x TERAS_POST | 1146.02 | 0.537483 | 0.00263585 | 0.00262439 | 20.6914 | 20.6014 | 20.6 | 0.003 | 0.002 | 0.552 | 1146 | +8.520 | +9.666 | 0 | 20.7 | TEP-104(?)
2 x TERAS_POST | 3922.42 | 1.83962 | 0.00902157 | 0.00898234 | 70.8193 | 70.5114 | 70.51 | 0.009 | 0.002 | 1.885 | 3922.4 | +8.520 | +12.442 | 0 | 70.8 | TEP-103(?)
3 x TERAS_POST | 3972.42 | 1.86307 | 0.00913657 | 0.00909684 | 71.722 | 71.4102 | 71.41 | 0.009 | 0.002 | 1.909 | 3972.4 | +8.520 | +12.492 | 0 | 71.7 | TEP-103(?)
TERAS_POST | 4505.15 | 2.11292 | 0.0103618 | 0.0103168 | 81.3405 | 80.9869 | 80.99 | 0.009 | 0 | 2.165 | 4505.2 | +8.597 | +12.553 | 0.4 | 81.3 | TEP-105(?)
TERAS_POST | 2626.4 | 1.23178 | 0.00604072 | 0.00601446 | 47.4197 | 47.2135 | 47.21 | 0.006 | 0.002 | 1.264 | 2626.4 | +9.816 | +12.442 | 0 | 47.5 | TEP-103(?)

# IfcColumn: Metall - Teras - Konstruktsioon D100 (3)
In: Katuseplaan
Classification: 1.03 IfcColumnType (post) (IPI ÜBN); Material: Metall - Teras - Konstruktsioon
AR_ÜLD - 001_Nimetus: Post
AC_Pset_RenovationAndPhasing - Renovation Status: Existing
BaseQuantities - Length: 400 mm; Width: 100 mm; Depth: 100 mm; CrossSectionArea: 0.00785398 m2; OuterSurfaceArea: 0.124858 m2; TotalSurfaceArea: 0.140165 m2; GrossSurfaceArea: 0.140165 m2; GrossVolume: 0.00306147 m3; NetVolume: 0.00306147 m3

# IfcColumn: Metall - Teras 200 x 200 (4)
In: 1.korrus
Classification: 1.03 IfcColumnType (post) (IPI ÜBN); Material: Metall - Teras
BaseQuantities - Length: 2580 mm; Width: 200 mm; Depth: 200 mm; CrossSectionArea: 0.04 m2; OuterSurfaceArea: 2.064 m2; TotalSurfaceArea: 2.144 m2; GrossSurfaceArea: 2.144 m2; GrossVolume: 0.1032 m3; NetVolume: 0.1032 m3
AR_ÜLD - 001_Nimetus: Post
AC_Pset_RenovationAndPhasing - Renovation Status: New

# IfcColumn: Puit - Liimpuit 400 x 400 (22)
Classification: 1.03 IfcColumnType (post) (IPI ÜBN); Material: Puit - Liimpuit
BaseQuantities - Width: 400 mm; Depth: 400 mm; CrossSectionArea: 0.16 m2
AC_Pset_RenovationAndPhasing - Renovation Status: New
AR_ÜLD - 001_Nimetus: Post
Name | In | Length (mm) | OuterSurfaceArea (m2) | TotalSurfaceArea (m2) = GrossSurfaceArea (m2) | GrossVolume (m3) = NetVolume (m3)
10 x  | 1.korrus | 4100 | 6.56 | 6.88 | 0.656
2 x  | 1.korrus | 2800 | 4.48 | 4.8 | 0.448
10 x  | 2.korrus | 3280 | 5.248 | 5.568 | 0.5248

# IfcColumn: RHS150*8 150 x 150 (7)
In: 1.korrus
Description: RHS150*8; Classification: 1.03 IfcColumnType (post) (IPI ÜBN); Material: STEEL/S355
BaseQuantities - CrossSectionArea: 0.00432425 m2
AC_Pset_RenovationAndPhasing - Renovation Status: New
AR_ÜLD - 001_Nimetus: Post
EK_Tala-Post - 145_Pindala: 0 m2; 195_Alumine-kõrgusmärk: +8.650; 135_Ruumala: 0 m3; 125_Positsioon: TP-0(?); 105_Tugevusklass: S355; 003_Ristlõige: RHS150*8; 001_Nimetus: POST
Tekla Common - Bottom elevation: +8.650; Phase: 1; Class: 503
Tekla Quantity - Gross footprint area: 0.005 m2; Area per tons: 16.467 m2; Height: 150 mm; Width: 150 mm
Pset_ColumnCommon - Reference: TD-0(?)
Name | BaseQuantities, Length (mm) = 130_Pikkus (mm) = Tekla Quantity, Length (mm) | OuterSurfaceArea (m2) | TotalSurfaceArea (m2) = GrossSurfaceArea (m2) | GrossVolume (m3) | NetVolume (m3) | 146_Täispindala (m2) | 190_Ülemine-kõrgusmärk = Top elevation | 140_Mass (kg) | Weight (kg) | Volume (m3) | Net surface area (m2) | NetWeight (kg)
3 x POST | 7450 | 8.02893 | 8.03755 | 0.0321297 | 0.0321297 | 4.3 | +16.100 | 265.7 | 263.76 | 0.034 | 4.475 | 265.744
POST | 7450 | 8.02662 | 8.03477 | 0.0321204 | 0.0321204 | 4.3 | +16.100 | 265.7 | 263.76 | 0.034 | 4.475 | 265.744
POST | 7830 | 4.56489 | 8.12377 | 0.0324747 | 0.0355795 | 4.7 | +16.480 | 279.3 | 277.21 | 0.035 | 4.703 | 279.299
2 x POST | 7450 | 4.34335 | 8.03755 | 0.0321297 | 0.0338528 | 4.3 | +16.100 | 265.7 | 263.76 | 0.034 | 4.475 | 265.744

# IfcColumn: Various Structures - 3 Segments - 600 x 350 x 3660 (3088+106+466)
In: 1.korrus
Classification: 1.03 IfcColumnType (post) (IPI ÜBN)
BaseQuantities - NetVolume: 0.658672 m3; GrossVolume: 0.658672 m3; Length: 3660 mm
AC_Pset_RenovationAndPhasing - Renovation Status: Existing
AR_ÜLD - 001_Nimetus: Olemasolev post

# IfcColumn: Various Structures - 3 Segments - 600 x 400 x 2500 (1983+102+415)
In: 2.korrus
Classification: 1.03 IfcColumnType (post) (IPI ÜBN)
AC_Pset_RenovationAndPhasing - Renovation Status: Existing
BaseQuantities - NetVolume: 0.436941 m3; GrossVolume: 0.436941 m3; Length: 2500 mm
AR_ÜLD - 001_Nimetus: Olemasolev post

# IfcColumn: Various Structures - 3 Segments - 600 x 400 x 3710 (3193+102+415)
In: 1.korrus
Classification: 1.03 IfcColumnType (post) (IPI ÜBN)
BaseQuantities - NetVolume: 0.754642 m3; GrossVolume: 0.754642 m3; Length: 3710.02 mm
AC_Pset_RenovationAndPhasing - Renovation Status: Existing
AR_ÜLD - 001_Nimetus: Olemasolev post

# IfcColumn: Various Structures - 3 Segments - 600 x 400 x 3982 (3527+63+391)
In: 1.korrus
Classification: 1.03 IfcColumnType (post) (IPI ÜBN)
BaseQuantities - NetVolume: 0.81328 m3; GrossVolume: 0.81328 m3; Length: 3981.83 mm
AC_Pset_RenovationAndPhasing - Renovation Status: Existing
AR_ÜLD - 001_Nimetus: Olemasolev post

# IfcColumn: Various Structures - 3 Segments - 600 x 400 x 4000 (3483+102+415)
In: 1.korrus
Classification: 1.03 IfcColumnType (post) (IPI ÜBN)
AC_Pset_RenovationAndPhasing - Renovation Status: Existing
BaseQuantities - NetVolume: 0.81864 m3; GrossVolume: 0.81864 m3; Length: 4000 mm
AR_ÜLD - 001_Nimetus: Olemasolev post

# IfcColumn: Various Structures - 3 Segments - 600 x 400 x 4050 (3533+102+415) (4)
In: 1.korrus
Classification: 1.03 IfcColumnType (post) (IPI ÜBN)
BaseQuantities - NetVolume: 0.82864 m3; GrossVolume: 0.82864 m3; Length: 4050 mm
AC_Pset_RenovationAndPhasing - Renovation Status: Existing
AR_ÜLD - 001_Nimetus: Olemasolev post

# IfcColumn: Various Structures - 3 Segments - 600 x 400 x 5950 (5433+102+415) (4)
In: 1.korrus
Classification: 1.03 IfcColumnType (post) (IPI ÜBN)
BaseQuantities - NetVolume: 0.989281 m3; GrossVolume: 0.989281 m3; Length: 5950 mm
AC_Pset_RenovationAndPhasing - Renovation Status: Existing
AR_ÜLD - 001_Nimetus: Olemasolev post

# IfcCovering: Air Space 50 (7)
Type - PredefinedType: CEILING
Classification: 1.04 IfcCoveringType.CEILING (ripplagi) (IPI ÜBN); Material: Air Space
AC_Pset_RenovationAndPhasing - Renovation Status: New
AR_ÜLD - 001_Nimetus: Ripplae otsapind
AR_Viimistlus - 001_Nimetus: Ripplae otsapind; 200_Materjal: Air Space; 210_Paksus: 50 mm; 215_Tuletundlikkus: ootel; 220_Viimistlus: ootel; 230_Niiskuskindel: no; 235_Karkass: ootel; 900_Tootja: ootel; 905_Mudel: ootel; 910_Tooteinfo: -; 915_Kasutus-ja-hooldusjuhend: -; 240_Märghõõrdekindlus: ootel; 245_Aluspind: ootel
Name | In | GrossArea (m2) | NetArea (m2) | 225_Pindala (m2)
RL2 | 1.korrus | 0.176047 | 0.176047 | 2.38016
RL1 | 1.korrus | 0.217412 | 0.217412 | 0.826164
RL1 | 1.korrus | 0.377924 | 0.379174 | 1.44086
RL1 | 1.korrus | 0.216151 | 0.214901 | 0.826125
RL1 | 1.korrus | 0.1213 | 0.12255 | 2.05884
RL1 | 1.korrus | 0.731832 | 0.730582 | 12.3158
RL4 | 2.korrus | 0.729053 | 0.729053 | 13.1169

# IfcCovering: GENEERILINE - EHITUSTOODE (31)
Classification: 1.07 IfcCoveringType (pinnadetailid) (IPI ÜBN); Material: GENEERILINE - EHITUSTOODE
AC_Pset_RenovationAndPhasing - Renovation Status: New
Name | In | AR_Viimistlus, 001_Nimetus | AR_Viimistlus, sets with these values
4 x aknakopsik | 1.korrus | AR_ÜLD - 001_Nimetus: Päiksevarjestus; sets with these values: 2
6 x aknakopsik | 1.korrus | Päiksevarjestus | 2
17 x aknakopsik | 2.korrus | Päiksevarjestus | 2
4 x aknakopsik | 2.korrus | AR_ÜLD - 001_Nimetus: Päiksevarjestus; sets with these values: 2

# IfcCovering: GENEERILINE - KONSTRUKTRIOON 10 (34)
Type - PredefinedType: FLOORING
Classification: 1.06 IfcCoveringType.FLOORING (põrandakatted) (IPI ÜBN); Material: GENEERILINE - KONSTRUKTRIOON
AR_Viimistlus - 001_Nimetus: Põrandaplaadistus; 200_Materjal: GENEERILINE - KONSTRUKTRIOON; 210_Paksus: 10 mm; 215_Tuletundlikkus: ootel; 220_Viimistlus: ootel; 230_Niiskuskindel: no; 900_Tootja: ootel; 905_Mudel: ootel; 910_Tooteinfo: -; 915_Kasutus-ja-hooldusjuhend: -; 240_Märghõõrdekindlus: ootel; 245_Aluspind: ootel
AR_ÜLD - 001_Nimetus: Põrandaplaadistus
Name | In | 225_Pindala (m2) = GrossArea (m2) = NetArea (m2) | Renovation Status
P3b | 1.korrus | 0.868767 | New
P3b | 1.korrus | 0.879033 | New
P3a | 1.korrus | 1.2814 | New
P3b | 1.korrus | 0.8673 | New
P3b | 1.korrus | 0.952501 | New
P3a | 1.korrus | 1.278 | New
2 x P3a | 1.korrus | 1.2744 | New
P3a | 1.korrus | 1.31835 | New
P3a | 1.korrus | 1.32525 | New
P3b | 1.korrus | 0.859162 | New
P3a | 1.korrus | 4.95678 | New
P3b | 1.korrus | 0.728804 | New
P3a | 1.korrus | 0.816765 | New
P3a | 1.korrus | 1.43922 | New
P3a | 1.korrus | 1.49199 | New
P3a | 1.korrus | 1.48735 | New
P3a | 1.korrus | 11.0853 | New
P3a | 1.korrus | 11.0997 | New
P3a | 1.korrus | 13.0364 | Existing
P3a | 1.korrus | 12.8633 | Existing
P3a | 1.korrus | 9.74215 | Existing
P3a | 1.korrus | 12.7299 | Existing
P3b | 2.korrus | 1.4656 | New
P3b | 2.korrus | 2.70483 | New
P3b | 2.korrus | 1.23875 | New
P3a | 2.korrus | 2.03604 | New
P3b | 2.korrus | 3.18086 | New
P3a | 2.korrus | 1.2381 | New
P3a | 2.korrus | 1.38024 | New
P3a | 2.korrus | 1.23967 | New
P3a | 2.korrus | 1.5077 | New
P3a | 2.korrus | 22.0602 | New
P3a | 2.korrus | 11.0927 | New

# IfcCovering: GENEERILINE - KONSTRUKTRIOON 100 (31)
Classification: 1.07 IfcCoveringType (pinnadetailid) (IPI ÜBN); Material: GENEERILINE - KONSTRUKTRIOON
BaseQuantities - GrossArea: 0.272237 m2; NetArea: 0.272237 m2
AC_Pset_RenovationAndPhasing - Renovation Status: New
Name | In | AR_Viimistlus, 001_Nimetus | AR_Viimistlus, sets with these values
2 x Akna varjestus | 1.korrus | AR_ÜLD - 001_Nimetus: Akna varjestus; sets with these values: 2
8 x Akna varjestus | 1.korrus | Akna varjestus | 2
19 x Akna varjestus | 2.korrus | Akna varjestus | 2
2 x Akna varjestus | 2.korrus | AR_ÜLD - 001_Nimetus: Akna varjestus; sets with these values: 2

# IfcCovering: GENEERILINE - KONSTRUKTRIOON 15, P2
In: 2.korrus
Type - PredefinedType: FLOORING
Classification: 1.06 IfcCoveringType.FLOORING (põrandakatted) (IPI ÜBN); Material: GENEERILINE - KONSTRUKTRIOON
AR_Viimistlus - 001_Nimetus: Põrandaplaadistus; 200_Materjal: GENEERILINE - KONSTRUKTRIOON; 210_Paksus: 15 mm; 215_Tuletundlikkus: ootel; 220_Viimistlus: ootel; 230_Niiskuskindel: no; 900_Tootja: ootel; 905_Mudel: ootel; 910_Tooteinfo: -; 915_Kasutus-ja-hooldusjuhend: -; 240_Märghõõrdekindlus: ootel; 245_Aluspind: ootel; 225_Pindala: 24.6906 m2
AR_ÜLD - 001_Nimetus: Põrandaplaadistus
AC_Pset_RenovationAndPhasing - Renovation Status: Existing
BaseQuantities - GrossArea: 24.6906 m2; NetArea: 24.6906 m2

# IfcCovering: GENEERILINE - KONSTRUKTRIOON 3 (25)
Type - PredefinedType: FLOORING
Classification: 1.06 IfcCoveringType.FLOORING (põrandakatted) (IPI ÜBN); Material: GENEERILINE - KONSTRUKTRIOON
AR_Viimistlus - 001_Nimetus: Põrandaplaadistus; 200_Materjal: GENEERILINE - KONSTRUKTRIOON; 210_Paksus: 3 mm; 215_Tuletundlikkus: ootel; 220_Viimistlus: ootel; 230_Niiskuskindel: no; 900_Tootja: ootel; 905_Mudel: ootel; 910_Tooteinfo: -; 915_Kasutus-ja-hooldusjuhend: -; 240_Märghõõrdekindlus: ootel; 245_Aluspind: ootel
AR_ÜLD - 001_Nimetus: Põrandaplaadistus
Name | In | 225_Pindala (m2) = GrossArea (m2) | Renovation Status | NetArea (m2)
P9 | 1.korrus | 3.26346 | Existing | 3.26346
P9 | 1.korrus | 237.235 | New | 237.235
P8 | 1.korrus | 1.054 | Existing | 1.054
P9 | 1.korrus | 21.3225 | New | 21.3225
P9 | 2.korrus | 222.967 | New | 222.61
P4 | 2.korrus | 47.8731 | New | 47.8731
P4 | 2.korrus | 48.9607 | New | 48.9607
P8 | 2.korrus | 48.887 | New | 48.887
P4 | 2.korrus | 69.0252 | New | 69.0252
P5 | 2.korrus | 11.9538 | New | 11.8298
2 x P5 | 2.korrus | 11.9538 | New | 11.9538
P4 | 2.korrus | 17.2611 | New | 17.1558
P8 | 2.korrus | 48.4192 | New | 48.4192
P4 | 2.korrus | 175.815 | New | 175.815
P5 | 2.korrus | 21.1005 | New | 21.1005
P5 | 2.korrus | 18.7871 | New | 18.7871
P5 | 2.korrus | 15.5472 | New | 15.5472
P4 | 2.korrus | 31.5445 | New | 31.4925
P4 | 2.korrus | 44.0083 | New | 43.8483
2 x P9 | 2.korrus | 0.556107 | New | 0.556107
P9 | 2.korrus | 2.69914 | New | 2.69914
P8 | 2.korrus | 1.45539 | Existing | 1.45539
P8 | 2.korrus | 0.667542 | Existing | 0.667542

# IfcCovering: GENEERILINE - KONSTRUKTRIOON 40 (274)
Type - PredefinedType: CEILING
Classification: 1.04 IfcCoveringType.CEILING (ripplagi) (IPI ÜBN); Material: GENEERILINE - KONSTRUKTRIOON
BaseQuantities - GrossArea: 0.72 m2; NetArea: 0.72 m2
AC_Pset_RenovationAndPhasing - Renovation Status: New
AR_ÜLD - 001_Nimetus: Mineraalvillast akustiline ripplagi
AR_Viimistlus - 001_Nimetus: Mineraalvillast akustiline ripplagi; 200_Materjal: GENEERILINE - KONSTRUKTRIOON; 210_Paksus: 40 mm; 215_Tuletundlikkus: ootel; 220_Viimistlus: ootel; 230_Niiskuskindel: no; 235_Karkass: ootel; 900_Tootja: ootel; 905_Mudel: ootel; 910_Tooteinfo: -; 915_Kasutus-ja-hooldusjuhend: -; 240_Märghõõrdekindlus: ootel; 245_Aluspind: ootel; 225_Pindala: 0.72 m2
Name | In
242 x RL3 | 1.korrus
32 x RL3 | 2.korrus

# IfcCovering: GENEERILINE - KONSTRUKTRIOON 50 (47)
Type - PredefinedType: CEILING
Classification: 1.04 IfcCoveringType.CEILING (ripplagi) (IPI ÜBN); Material: GENEERILINE - KONSTRUKTRIOON
AC_Pset_RenovationAndPhasing - Renovation Status: New
AR_Viimistlus - 200_Materjal: GENEERILINE - KONSTRUKTRIOON; 210_Paksus: 50 mm; 215_Tuletundlikkus: ootel; 230_Niiskuskindel: no; 235_Karkass: ootel; 900_Tootja: ootel; 905_Mudel: ootel; 910_Tooteinfo: -; 915_Kasutus-ja-hooldusjuhend: -; 240_Märghõõrdekindlus: ootel; 245_Aluspind: ootel
Name | In | GrossArea (m2) = 225_Pindala (m2) | NetArea (m2) | AR_ÜLD, 001_Nimetus = AR_Viimistlus, 001_Nimetus | 220_Viimistlus
RL1 | 1.korrus | 151.222 | 150.798 | Terasvõrk ripplagi | ootel
RL2 | 1.korrus | 9.48732 | 9.48732 | Lauskips ripplagi | värvitud
2 x RL2 | 1.korrus | 1.2022 | 1.2022 | Lauskips ripplagi | värvitud
2 x RL2 | 1.korrus | 1.859 | 1.859 | Lauskips ripplagi | värvitud
RL2 | 1.korrus | 12.7361 | 12.7361 | Lauskips ripplagi | värvitud
RL2 | 1.korrus | 12.6024 | 12.6024 | Lauskips ripplagi | värvitud
RL2 | 1.korrus | 9.76278 | 9.76278 | Lauskips ripplagi | värvitud
RL2 | 1.korrus | 1.62 | 1.62 | Lauskips ripplagi | värvitud
RL2 | 1.korrus | 1.25064 | 1.25064 | Lauskips ripplagi | värvitud
2 x RL2 | 1.korrus | 1.1978 | 1.1978 | Lauskips ripplagi | värvitud
RL2 | 1.korrus | 12.7353 | 12.7353 | Lauskips ripplagi | värvitud
RL2 | 1.korrus | 1.243 | 1.24284 | Lauskips ripplagi | värvitud
RL2 | 1.korrus | 5.7189 | 5.7189 | Lauskips ripplagi | värvitud
RL2 | 1.korrus | 1.42037 | 1.42037 | Lauskips ripplagi | värvitud
RL2 | 1.korrus | 10.958 | 10.958 | Lauskips ripplagi | värvitud
RL2 | 1.korrus | 1.28803 | 1.28803 | Lauskips ripplagi | värvitud
RL2 | 1.korrus | 1.41787 | 1.41787 | Lauskips ripplagi | värvitud
RL1 | 1.korrus | 8.29642 | 8.29642 | Terasvõrk ripplagi | ootel
RL2 | 1.korrus | 3.58321 | 3.58321 | Lauskips ripplagi | värvitud
RL2 | 1.korrus | 8.89992 | 8.89992 | Lauskips ripplagi | värvitud
RL2 | 1.korrus | 5.37594 | 5.37594 | Lauskips ripplagi | värvitud
RL1 | 1.korrus | 14.5592 | 14.5592 | Terasvõrk ripplagi | ootel
RL1 | 1.korrus | 0.000514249 | 0.000514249 | Terasvõrk ripplagi | ootel
RL1 | 1.korrus | 5.04759 | 5.04759 | Terasvõrk ripplagi | ootel
RL1 | 1.korrus | 32.9755 | 32.7355 | Terasvõrk ripplagi | ootel
RL2 | 2.korrus | 1.1583 | 1.1583 | Lauskips ripplagi | värvitud
RL2 | 2.korrus | 1.30192 | 1.30192 | Lauskips ripplagi | värvitud
RL1 | 2.korrus | 14.623 | 14.623 | Terasvõrk ripplagi | ootel
RL1 | 2.korrus | 10.2339 | 10.2339 | Terasvõrk ripplagi | ootel
RL1 | 2.korrus | 10.4672 | 10.4672 | Terasvõrk ripplagi | ootel
RL1 | 2.korrus | 10.4514 | 10.4514 | Terasvõrk ripplagi | ootel
RL4 | 2.korrus | 85.2402 | 85.2402 | Mineraalvillast moodulripplagi | ootel
RL4 | 2.korrus | 85.9775 | 85.9775 | Mineraalvillast moodulripplagi | ootel
RL2 | 2.korrus | 1.15382 | 1.15382 | Lauskips ripplagi | värvitud
RL2 | 2.korrus | 1.96683 | 1.96683 | Lauskips ripplagi | värvitud
RL2 | 2.korrus | 1.42991 | 1.42991 | Lauskips ripplagi | värvitud
RL2 | 2.korrus | 4.07837 | 4.07837 | Lauskips ripplagi | värvitud
RL2 | 2.korrus | 11.0927 | 11.0927 | Lauskips ripplagi | värvitud
RL1 | 2.korrus | 180.393 | 180.036 | Terasvõrk ripplagi | ootel
RL4 | 2.korrus | 31.0595 | 31.0595 | Mineraalvillast moodulripplagi | ootel
RL4 | 2.korrus | 25.4909 | 25.331 | Mineraalvillast moodulripplagi | ootel
RL2 | 2.korrus | 22.0602 | 22.0602 | Lauskips ripplagi | värvitud
RL2 | 2.korrus | 4.94948 | 4.94948 | Lauskips ripplagi | värvitud
RL4 | 2.korrus | 24.6906 | 24.5306 | Mineraalvillast moodulripplagi | ootel

# IfcCovering: GENEERILINE - SISEMINE VOODER 40 (4)
In: 2.korrus
Type - PredefinedType: CEILING
Classification: 1.04 IfcCoveringType.CEILING (ripplagi) (IPI ÜBN); Material: GENEERILINE - SISEMINE VOODER
AR_ÜLD - 001_Nimetus: Ripplae otsapind
AR_Viimistlus - 001_Nimetus: Ripplae otsapind; 200_Materjal: GENEERILINE - SISEMINE VOODER; 210_Paksus: 40 mm; 215_Tuletundlikkus: ootel; 220_Viimistlus: ootel; 230_Niiskuskindel: no; 235_Karkass: ootel; 900_Tootja: ootel; 905_Mudel: ootel; 910_Tooteinfo: -; 915_Kasutus-ja-hooldusjuhend: -; 240_Märghõõrdekindlus: ootel; 245_Aluspind: ootel
AC_Pset_RenovationAndPhasing - Renovation Status: New
Name | 225_Pindala (m2) | GrossArea (m2) | NetArea (m2)
RL1 | 19.7286 | 0.381755 | 0.381755
RL1 | 13.0194 | 0.26412 | 0.26412
RL1 | 13.7477 | 0.27012 | 0.269714
RL1 | 14.0469 | 0.27012 | 0.27012

# IfcCovering: GENEERILINE - SISEMINE VOODER 50, RL4
In: 2.korrus
Type - PredefinedType: CEILING
Classification: 1.04 IfcCoveringType.CEILING (ripplagi) (IPI ÜBN); Material: GENEERILINE - SISEMINE VOODER
AR_Viimistlus - 001_Nimetus: Ripplae otsapind; 200_Materjal: GENEERILINE - SISEMINE VOODER; 210_Paksus: 50 mm; 215_Tuletundlikkus: ootel; 220_Viimistlus: ootel; 230_Niiskuskindel: no; 235_Karkass: ootel; 900_Tootja: ootel; 905_Mudel: ootel; 910_Tooteinfo: -; 915_Kasutus-ja-hooldusjuhend: -; 240_Märghõõrdekindlus: ootel; 245_Aluspind: ootel; 225_Pindala: 3.06943 m2
AR_ÜLD - 001_Nimetus: Ripplae otsapind
AC_Pset_RenovationAndPhasing - Renovation Status: New
BaseQuantities - GrossArea: 0.293153 m2; NetArea: 0.273153 m2

# IfcCovering: P-2 365 (3)
In: Pööningukorrus
Type - PredefinedType: FLOORING
Classification: 1.06 IfcCoveringType.FLOORING (põrandakatted) (IPI ÜBN)
AC_Pset_RenovationAndPhasing - Renovation Status: New
AR_Viimistlus - 001_Nimetus: Õhuvõtukambri põrand; 200_Materjal: SA_seinad_F499; 210_Paksus: 365 mm; 215_Tuletundlikkus: ootel; 220_Viimistlus: ootel; 230_Niiskuskindel: no; 900_Tootja: ootel; 905_Mudel: ootel; 910_Tooteinfo: -; 915_Kasutus-ja-hooldusjuhend: -; 240_Märghõõrdekindlus: ootel; 245_Aluspind: ootel
AR_ÜLD - 001_Nimetus: Õhuvõtukambri põrand
Name | GrossArea (m2) = 225_Pindala (m2) | NetArea (m2)
P-2 | 3.89424 | 3.64006
P-2 | 1.61869 | 1.61869
P-2 | 2.88413 | 2.88005

# IfcCovering: SA_viimistluskiht 10 (89)
Type - PredefinedType: CLADDING
Classification: 1.05 IfcCoveringType.CLADDING (viimistlus) (IPI ÜBN); Material: SA_viimistluskiht
AC_Pset_RenovationAndPhasing - Renovation Status: New
AR_Viimistlus - 200_Materjal: SA_viimistluskiht; 210_Paksus: 10 mm; 230_Niiskuskindel: no; 900_Tootja: ootel; 905_Mudel: ootel; 910_Tooteinfo: -; 915_Kasutus-ja-hooldusjuhend: -; 240_Märghõõrdekindlus: ootel; 245_Aluspind: ootel
Name | In | AR_ÜLD, 001_Nimetus = AR_Viimistlus, 001_Nimetus | 215_Tuletundlikkus | 220_Viimistlus | 225_Pindala (m2) | GrossArea (m2) | NetArea (m2)
S3 | 1.korrus | Keraamiline plaat 100x200 | A | beezh | 4.082 | 0.01425 | 0.0141022
S3 | 1.korrus | Keraamiline plaat 100x200 | A | beezh | 4.108 | 0.013 | 0.0129009
S3 | 1.korrus | Keraamiline plaat 100x200 | A | beezh | 4.10801 | 0.013 | 0.0129001
S3 | 1.korrus | Keraamiline plaat 100x200 | A | beezh | 3.224 | 0.011 | 0.00279993
2 x S3 | 1.korrus | Keraamiline plaat 100x200 | A | beezh | 4.082 | 0.01425 | 0.00620001
S3 | 1.korrus | Keraamiline plaat 100x200 | A | beezh | 2.5792 | 0.00759999 | 0.00739999
S3 | 1.korrus | Keraamiline plaat 100x200 | A | beezh | 3.2292 | 0.01056 | 0.0101
S3 | 1.korrus | Keraamiline plaat 100x200 | A | beezh | 3.5412 | 0.0112 | 0.0113
S3 | 1.korrus | Keraamiline plaat 100x200 | A | beezh | 4.082 | 0.01425 | 0.0140977
S3 | 1.korrus | Keraamiline plaat 100x200 | A | beezh | 4.108 | 0.013 | 0.0129013
S3 | 1.korrus | Keraamiline plaat 100x200 | A | beezh | 4.10799 | 0.013 | 0.0129
S3 | 1.korrus | Keraamiline plaat 100x200 | A | beezh | 3.224 | 0.0117 | 0.00289998
S3 | 1.korrus | Keraamiline plaat 100x200 | A | beezh | 3.5412 | 0.0112 | 0.0112999
S3 | 1.korrus | Keraamiline plaat 100x200 | A | beezh | 2.5792 | 0.00759998 | 0.00739998
S3 | 1.korrus | Keraamiline plaat 100x200 | A | beezh | 3.2292 | 0.01051 | 0.00999987
S3 | 1.korrus | Keraamiline plaat 100x200 | A | beezh | 5.94765 | 0.0228756 | 0.0127755
S3 | 1.korrus | Keraamiline plaat 100x200 | A | beezh | 7.1032 | 0.025 | 0.0249002
S3 | 1.korrus | Keraamiline plaat 100x200 | A | beezh | 7.1032 | 0.025 | 0.0249
S3 | 1.korrus | Keraamiline plaat 100x200 | A | beezh | 5.94765 | 0.0228756 | 0.0226756
S3 | 1.korrus | Keraamiline plaat 100x200 | A | beezh | 2.44468 | 0.00843262 | 0.00848262
S3 | 1.korrus | Keraamiline plaat 100x200 | A | beezh | 4.48778 | 0.0154207 | 0.0152205
S3 | 1.korrus | Keraamiline plaat 100x200 | A | beezh | 4.05336 | 0.0146199 | 0.00646997
S3 | 1.korrus | Keraamiline plaat 100x200 | A | beezh | 1.92228 | 0.00647338 | 0.00647338
S3 | 1.korrus | Keraamiline plaat 100x200 | A | beezh | 0.547968 | 0.00200756 | 0.00200756
S3 | 1.korrus | Keraamiline plaat 100x200 | A | beezh | 0.460385 | 0.000700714 | 0.000650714
S3 | 1.korrus | Keraamiline plaat 100x200 | A | beezh | 2.69923 | 0.00893164 | 0.00888164
S3 | 1.korrus | Keraamiline plaat 100x200 | A | beezh | 4.20527 | 0.0152541 | 0.00695513
S3 | 1.korrus | Keraamiline plaat 100x200 | A | beezh | 4.20527 | 0.0152041 | 0.0151541
S3 | 1.korrus | Keraamiline plaat 100x200 | A | beezh | 4.4396 | 0.0161053 | 0.00795532
S3 | 1.korrus | Keraamiline plaat 100x200 | A | beezh | 4.0769 | 0.0147104 | 0.0147604
S3 | 1.korrus | Keraamiline plaat 100x200 | A | beezh | 2.33474 | 0.00897978 | 0.00897978
S3 | 1.korrus | Keraamiline plaat 100x200 | A | beezh | 1.93372 | 0.00646752 | 0.00651745
S3 | 1.korrus | Keraamiline plaat 100x200 | A | beezh | 2.33525 | 0.00888169 | 0.00878169
S3 | 1.korrus | Keraamiline plaat 100x200 | A | beezh | 3.25 | 0.01055 | 0.0104001
S3 | 1.korrus | Keraamiline plaat 100x200 | A | beezh | 3.5412 | 0.0113 | 0.0113009
4 x S3 | 1.korrus | Keraamiline plaat 100x200 | A | beezh | 3.5412 | 0.0113 | 0.0113
S3 | 1.korrus | Keraamiline plaat 100x200 | A | beezh | 3.12 | 0.0106 | 0.00239996
S3 | 1.korrus | Keraamiline plaat 100x200 | A | beezh | 3.12 | 0.01055 | 0.0103999
S3 | 1.korrus | Keraamiline plaat 100x200 | A | beezh | 3.224 | 0.01095 | 0.00284199
S3 | 1.korrus | Keraamiline plaat 100x200 | A | beezh | 3.224 | 0.011 | 0.0108964
S3 | 1.korrus | Keraamiline plaat 100x200 | A | beezh | 3.1772 | 0.01115 | 0.0109396
S3 | 1.korrus | Keraamiline plaat 100x200 | A | beezh | 3.85216 | 0.013896 | 0.00569599
S3 | 1.korrus | Keraamiline plaat 100x200 | A | beezh | 3.85216 | 0.013846 | 0.013796
S3 | 1.korrus | Keraamiline plaat 100x200 | A | beezh | 5.408 | 0.0187 | 0.0097999
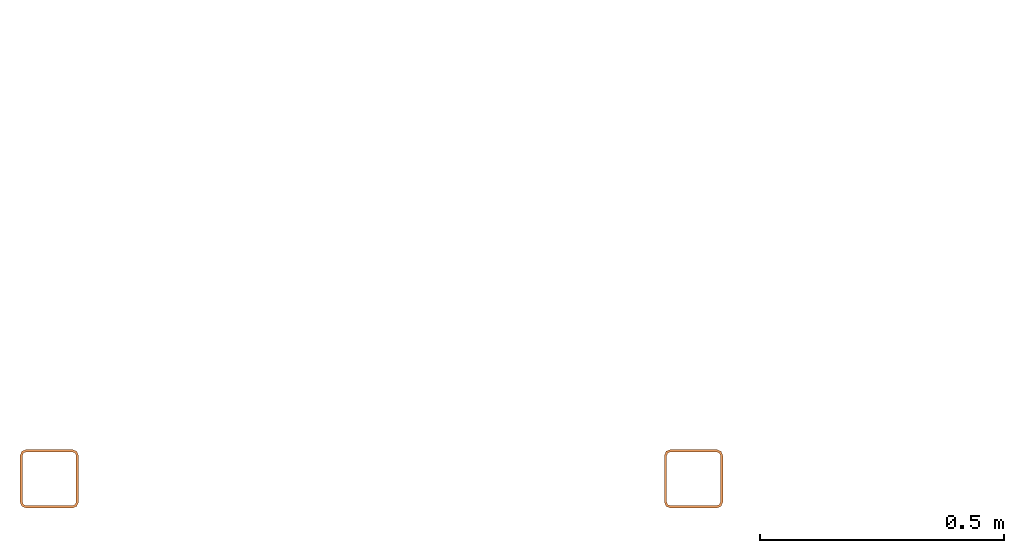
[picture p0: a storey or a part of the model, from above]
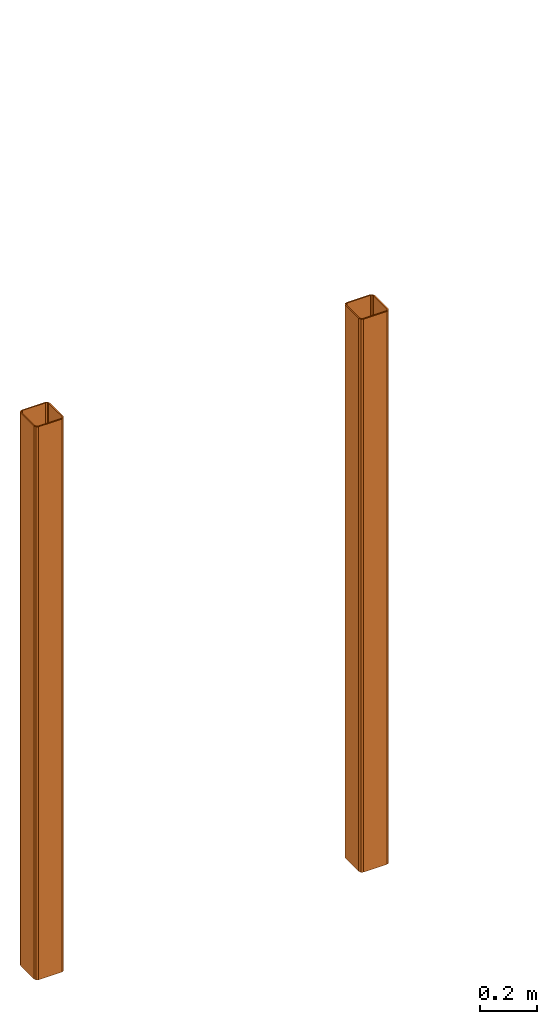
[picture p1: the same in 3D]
Properties of the parts of a building model (IFC2X3), part 3 of 7

# IfcCovering: SA_viimistluskiht 10 (89)
Name | In | AR_ÜLD, 001_Nimetus = AR_Viimistlus, 001_Nimetus | 215_Tuletundlikkus | 220_Viimistlus | 225_Pindala (m2) | GrossArea (m2) | NetArea (m2)
S3 | 1.korrus | Keraamiline plaat 100x200 | A | beezh | 2.704 | 0.00895 | 0.0089
S3 | 1.korrus | Keraamiline plaat 100x200 | A | beezh | 5.408 | 0.018 | 0.0178
S3 | 1.korrus | Keraamiline plaat 100x200 | A | beezh | 2.704 | 0.009 | 0.009
2 x S3 | 1.korrus | Keraamiline plaat 100x200 | A | beezh | 2.704 | 0.00895 | 0.009
Plaat | 1.korrus | Sisesein | ootel | ootel | 0.889541 | 0.0148257 | 0.0148257
S3 | 1.korrus | Keraamiline plaat 100x200 | A | beezh | 3.25 | 0.01055 | 0.00239997
S3 | 1.korrus | Keraamiline plaat 100x200 | A | beezh | 0.910003 | 0.00330001 | 0.00330001
S3 | 1.korrus | Keraamiline plaat 100x200 | A | beezh | 0.811203 | 0.00110001 | 0.00220001
S3 | 1.korrus | Keraamiline plaat 100x200 | A | beezh | 0.910005 | 0.00330002 | 0.00329998
S3 | 1.korrus | Keraamiline plaat 100x200 | A | beezh | 0.8112 | 0.00115 | 0.00220001
S3 | 2.korrus | Keraamiline plaat 100x200 | A | beezh | 3.12 | 0.012 | 0.0119
S3 | 2.korrus | Keraamiline plaat 100x200 | A | beezh | 4.49159 | 0.0162553 | 0.0162569
S3 | 2.korrus | Keraamiline plaat 100x200 | A | beezh | 3.12 | 0.012 | 0.012
S3 | 2.korrus | Keraamiline plaat 100x200 | A | beezh | 4.63514 | 0.0163574 | 0.0163574
S3 | 2.korrus | Keraamiline plaat 100x200 | A | beezh | 2.7222 | 0.009 | 0.009
S3 | 2.korrus | Keraamiline plaat 100x200 | A | beezh | 4.35578 | 0.015833 | 0.0158329
S3 | 2.korrus | Keraamiline plaat 100x200 | A | beezh | 4.11346 | 0.015821 | 0.015821
S3 | 2.korrus | Keraamiline plaat 100x200 | A | beezh | 3.2422 | 0.01095 | 0.0109001
2 x S3 | 2.korrus | Keraamiline plaat 100x200 | A | beezh | 2.977 | 0.01048 | 0.01043
S3 | 2.korrus | Keraamiline plaat 100x200 | A | beezh | 2.32502 | 0.00894237 | 0.00894237
S3 | 2.korrus | Keraamiline plaat 100x200 | A | beezh | 3.2422 | 0.01095 | 0.0108
2 x S3 | 2.korrus | Keraamiline plaat 100x200 | A | beezh | 2.977 | 0.01053 | 0.01053
2 x S3 | 2.korrus | Keraamiline plaat 100x200 | A | beezh | 3.06909 | 0.0108042 | 0.0107526
S3 | 2.korrus | Keraamiline plaat 100x200 | A | beezh | 2.89455 | 0.00959882 | 0.00944707
S3 | 2.korrus | Keraamiline plaat 100x200 | A | beezh | 3.56773 | 0.012213 | 0.0121646
S3 | 2.korrus | Keraamiline plaat 100x200 | A | beezh | 2.87802 | 0.0109552 | 0.0110568
S3 | 2.korrus | Keraamiline plaat 100x200 | A | beezh | 3.5512 | 0.0136835 | 0.0134686
S3 | 2.korrus | Keraamiline plaat 100x200 | A | beezh | 6.26568 | 0.0233388 | 0.0233388
S3 | 2.korrus | Keraamiline plaat 100x200 | A | beezh | 0.772689 | 0.00292188 | 0.00297188
S3 | 2.korrus | Keraamiline plaat 100x200 | A | beezh | 5.30106 | 0.0203887 | 0.0203887
S3 | 2.korrus | Keraamiline plaat 100x200 | A | beezh | 4.82424 | 0.0177948 | 0.0177948
S3 | 2.korrus | Keraamiline plaat 100x200 | A | beezh | 3.86851 | 0.0148289 | 0.0147789
S3 | 2.korrus | Keraamiline plaat 100x200 | A | beezh | 0.7852 | 0.00292 | 0.00292
S3 | 2.korrus | Keraamiline plaat 100x200 | A | beezh | 7.31368 | 0.0272095 | 0.0270095
S3 | 2.korrus | Keraamiline plaat 100x200 | A | beezh | 5.11166 | 0.0181402 | 0.0180921
S3 | 2.korrus | Keraamiline plaat 100x200 | A | beezh | 7.04481 | 0.0270454 | 0.0270954
S3 | 2.korrus | Keraamiline plaat 100x200 | A | beezh | 5.11166 | 0.0181902 | 0.0181902

# IfcCurtainWall: Curtain Wall Type (20)
Classification: 1.08 IfcCurtainWallType (rippfassaad) (IPI ÜBN)
AR_Rippfassaad - 900_Tootja: ootel; 905_Mudel: ootel; 910_Tooteinfo: -; 915_Kasutus-ja-hooldusjuhend: -
Name | In | Width (mm) | Length (mm) | Height (mm) | GrossSideArea (m2) = NetSideArea (m2) | Renovation Status | 001_Nimetus
SKF-1.2,EI60 | 1.korrus | 22 | 3905.46 | 1900 | 7.42037 | New | Klaasfassaad
KF-2 | 1.korrus | 22 | 3004.39 | 2610 | 7.84146 | New | Klaasfassaad
KF-1.2 | 1.korrus | 22 | 3659.12 | 2610 | 9.5503 | New | Klaasfassaad
SKF-1.1,EI60 | 1.korrus | 22 | 7415.85 | 3460 | 25.6588 | New | Klaasfassaad
KF-1.1 | 1.korrus | 22 | 14474.4 | 7360 | 106.532 | New | Klaasfassaad
KF-XX | 1.korrus | 300 | 8029.13 | 2550 | 20.4743 | Existing | Olemasolev klaasfassaad
 | 1.korrus | 300 | 2619.95 | 4050 | 10.6108 | Existing | Olemasolev klaasfassaad
KF-XX | 1.korrus | 300 | 7530.12 | 4050 | 27.0016 | Existing | Olemasolev klaasfassaad
PKF-3 | 2.korrus | 0 | 3774.1 | 2600 | 9.81265 | New | Klaasfassaad
PKF-4 | 2.korrus | 0 | 3900.21 | 2600 | 10.1405 | New | Klaasfassaad
SKF-2.1,EI60 | 2.korrus | 22 | 7390.85 | 3260 | 24.0942 | New | Klaasfassaad
SKF-2.2,EI60 | 2.korrus | 22 | 6893.33 | 3260 | 22.4722 | New | Klaasfassaad
PKF-2.1 | 2.korrus | 0 | 3106.87 | 2400 | 7.45649 | New | Klaasfassaad
PKF-2.2 | 2.korrus | 0 | 4550.6 | 2400 | 10.9215 | New | Klaasfassaad
PKF-2.3 | 2.korrus | 0 | 1986.23 | 2400 | 4.76694 | New | Klaasfassaad
PKF-1.1 | 2.korrus | 0 | 3429.12 | 2400 | 8.22989 | New | Klaasfassaad
PKF-1.2 | 2.korrus | 0 | 2610 | 2400 | 6.264 | New | Klaasfassaad
PKF-1.3 | 2.korrus | 0 | 617 | 2400 | 1.4808 | New | Klaasfassaad
PKF-1.4 | 2.korrus | 0 | 1593 | 2400 | 3.8232 | New | Klaasfassaad
PKF1.5 | 2.korrus | 0 | 2610 | 2400 | 6.264 | New | Klaasfassaad

# IfcDiscreteAccessory: Cube 27 (41)
Classification: 1.09 IfcDiscreteAccessoryType (tarvik) (IPI ÜBN)
AC_Pset_RenovationAndPhasing - Renovation Status: New
Name | In | 001_Nimetus | 002_Tähis
13 x EK | 1.korrus | El.kätekuivataja | EK
10 x SD | 1.korrus | Seebidosaator | SD
4 x SR | 1.korrus | Seehoidja | SR
LK | 2.korrus | Laptop laadimiskäru | LK
3 x EK | 2.korrus | El.kätekuivataja | EK
KK1 | 2.korrus | Külmik, integreeritud, õp.toa köögis KM-1 | KK1
5 x SD | 2.korrus | Seebidosaator | SD
3 x SR | 2.korrus | Seehoidja | SR
PV kaabelduse läbiviik katusest | Katuseplaan |  | PV kaabelduse läbiviik katusest

# IfcDiscreteAccessory: Cylinder 27 (28)
Classification: 1.09 IfcDiscreteAccessoryType (tarvik) (IPI ÜBN)
AC_Pset_RenovationAndPhasing - Renovation Status: New
Name | In | 001_Nimetus | 002_Tähis
P2 | 1.korrus | Peegel | P2
9 x WCP | 1.korrus | WC paberi hoidja | WCP | KVJ_Õhukanal - 100_Rõhukadu(Pa): 0; 105_Rõhk(Pa): 0; 110_Vooluhulk(l/s): 1600; 115_Voolukiirus(m/s): 1.111; 150_Kanali_suurus: 1200 mm
10 x PR3 | 1.korrus | Prügikast pedaaliga | PR3
5 x WCP | 2.korrus | WC paberi hoidja | WCP | KVJ_Õhukanal - 100_Rõhukadu(Pa): 0; 105_Rõhk(Pa): 0; 110_Vooluhulk(l/s): 1600; 115_Voolukiirus(m/s): 1.111; 150_Kanali_suurus: 1200 mm
3 x PR3 | 2.korrus | Prügikast pedaaliga | PR3

# IfcDiscreteAccessory: Downspout Complex 27 (10)
In: 2.korrus
Classification: 1.09 IfcDiscreteAccessoryType (tarvik) (IPI ÜBN)
AR_ÜLD - 001_Nimetus: Sadeveetoru; 002_Tähis: SV püstik
AC_Pset_RenovationAndPhasing - Renovation Status: New

# IfcDiscreteAccessory: Flat Panel TV 27, Info-TV
In: 1.korrus
Classification: 1.09 IfcDiscreteAccessoryType (tarvik) (IPI ÜBN)
AR_ÜLD - 001_Nimetus: Info-TV; 002_Tähis: Info-TV
AC_Pset_RenovationAndPhasing - Renovation Status: New

# IfcDiscreteAccessory: GENEERILINE - EHITUSTOODE, Majajuht
In: 1.korrus
Classification: 1.09 IfcDiscreteAccessoryType (tarvik) (IPI ÜBN); Material: GENEERILINE - EHITUSTOODE
AC_Pset_RenovationAndPhasing - Renovation Status: Existing
AR_ÜLD - 001_Nimetus: ootel; 002_Tähis: Majajuht

# IfcDiscreteAccessory: GENEERILINE - EHITUSTOODE 20 (2)
In: 1.korrus
Classification: 1.09 IfcDiscreteAccessoryType (tarvik) (IPI ÜBN); Material: GENEERILINE - EHITUSTOODE
AC_Pset_RenovationAndPhasing - Renovation Status: New
Name | 001_Nimetus | 002_Tähis
P1 | Porimatt | P1
Jalapuhastusrest | Kuumtsingutud jalapuhastusrest | Jalapuhastusrest

# IfcDiscreteAccessory: GENEERILINE - KONSTRUKTRIOON 330 (2)
In: 2.korrus
Classification: 1.09 IfcDiscreteAccessoryType (tarvik) (IPI ÜBN); Material: GENEERILINE - KONSTRUKTRIOON
AR_ÜLD - 001_Nimetus: Paberidosaator; 002_Tähis: PD
AC_Pset_RenovationAndPhasing - Renovation Status: New

# IfcDiscreteAccessory: GENEERILINE - KONSTRUKTRIOON 400 (15)
Classification: 1.09 IfcDiscreteAccessoryType (tarvik) (IPI ÜBN); Material: GENEERILINE - KONSTRUKTRIOON
AC_Pset_RenovationAndPhasing - Renovation Status: New
AR_ÜLD - 001_Nimetus: WC hari, seinapealne; 002_Tähis: WCH
Name | In
10 x WCH | 1.korrus
5 x WCH | 2.korrus

# IfcDiscreteAccessory: GENEERILINE - KONSTRUKTRIOON 460 (3)
Classification: 1.09 IfcDiscreteAccessoryType (tarvik) (IPI ÜBN); Material: GENEERILINE - KONSTRUKTRIOON
AR_ÜLD - 001_Nimetus: Prügikast seinal; 002_Tähis: PR1
AC_Pset_RenovationAndPhasing - Renovation Status: New
Name | In
PR1 | 1.korrus
2 x PR1 | 2.korrus

# IfcDiscreteAccessory: GENEERILINE - KONSTRUKTRIOON 50 (49)
Classification: 1.09 IfcDiscreteAccessoryType (tarvik) (IPI ÜBN); Material: GENEERILINE - KONSTRUKTRIOON
AC_Pset_RenovationAndPhasing - Renovation Status: New
Name | In | 001_Nimetus | 002_Tähis
8 x N1 | 1.korrus | Topeltnagi | N1
8 x N1 | 2.korrus | Topeltnagi | N1
28 x RK | 2.korrus | Rulookardin | RK
2 x RK1 | 2.korrus | Rulookardin | RK1
3 x RK2 | 2.korrus | Rulookardin | RK2

# IfcDiscreteAccessory: GENEERILINE - KONSTRUKTRIOON 750 (13)
Classification: 1.09 IfcDiscreteAccessoryType (tarvik) (IPI ÜBN); Material: GENEERILINE - KONSTRUKTRIOON
AR_ÜLD - 001_Nimetus: Prügimoodul; 002_Tähis: PR2
AC_Pset_RenovationAndPhasing - Renovation Status: New
Name | In
5 x PR2 | 1.korrus
8 x PR2 | 2.korrus

# IfcDiscreteAccessory: GENEERILINE - SISEMINE VOODER 10 (22)
Classification: 1.09 IfcDiscreteAccessoryType (tarvik) (IPI ÜBN); Material: GENEERILINE - SISEMINE VOODER
AR_ÜLD - 001_Nimetus: Peegel
AC_Pset_RenovationAndPhasing - Renovation Status: New
Name | In | 002_Tähis
5 x P3 | 1.korrus | P3
10 x P1 | 1.korrus | P1
5 x P1 | 2.korrus | P1
2 x P3 | 2.korrus | P3

# IfcDiscreteAccessory: Prism 27 (6)
In: 2.korrus
Classification: 1.09 IfcDiscreteAccessoryType (tarvik) (IPI ÜBN)
AR_ÜLD - 001_Nimetus: Teadetetahvel; 002_Tähis: Teadetetahvel
AC_Pset_RenovationAndPhasing - Renovation Status: New

# IfcDiscreteAccessory: Sanitary_Accessories_HEWI_shower-tube-rail-A1-1100_801-35-310, KT2
In: 1.korrus
Classification: 1.09 IfcDiscreteAccessoryType (tarvik) (IPI ÜBN)
AR_ÜLD - 001_Nimetus: Käetugi; 002_Tähis: KT2
AC_Pset_RenovationAndPhasing - Renovation Status: New

# IfcDiscreteAccessory: Text 3D 27, Hoone nimesilt
In: Katuseplaan
Classification: 1.09 IfcDiscreteAccessoryType (tarvik) (IPI ÜBN)
AR_ÜLD - 001_Nimetus: Hoone nimesilt; 002_Tähis: Hoone nimesilt
AC_Pset_RenovationAndPhasing - Renovation Status: New

# IfcDiscreteAccessory: Vertical Ladder 27, SV püstik
In: 1.korrus
Classification: 1.09 IfcDiscreteAccessoryType (tarvik) (IPI ÜBN)
AC_Pset_RenovationAndPhasing - Renovation Status: New
AR_ÜLD - 001_Nimetus: Sadeveetoru; 002_Tähis: SV püstik

# IfcDistributionPort (52)
FlowDirection: SOURCEANDSINK
MEPPortDuct - ProfileShape: Round
Name | PortNumber | ConnectionType | NominalWidth (mm) = NominalHeight (mm)
12 x Main 2 | 2 | Simple Body | 800
11 x Main 1 | 1 | Simple Body | 800
Main 1 | 1 | Flanged | 800 | MEPPortDuct - Length: 1 mm
Main 2 | 2 | Flanged | 800 | MEPPortDuct - Length: 1 mm
3 x Main 1 | 1 | Simple Body | 650
3 x Main 2 | 2 | Simple Body | 650
7 x Main 1 | 1 | Simple Body | 600
7 x Main 2 | 2 | Simple Body | 600
Main 1 | 1 | Flanged | 600 | MEPPortDuct - Length: 1 mm
Main 2 | 2 | Flanged | 600 | MEPPortDuct - Length: 1 mm
Main 1 | 1 | Simple Body | 650 | MEPPortDuct - Length: 1 mm
Main 2 | 2 | Simple Body | 600 | MEPPortDuct - Length: 1 mm
2 x Main 1 | 1 | Simple Body | 500
Main 2 | 2 | Simple Body | 500

# IfcDoor: 1064 x 2070 x 40, AVU10
In: 1.korrus
Type - OperationType: SINGLE_SWING_RIGHT; ParameterTakesPrecedence: no; Sizeable: no
OverallHeight: 2050 mm; OverallWidth: 1024.3 mm; Classification: 1.10 IfcDoorStyle (uks) (IPI ÜBN); Door (ARCHICAD Classification+TK)
AC_Pset_RenovationAndPhasing - Renovation Status: Undefined
BaseQuantities - NetVolume: 0.0839928 m3
Pset_ManufacturerOccurrence - SerialNumber: Off
AR_Uks - 001_Nimetus: Välisuks; 300_Tähis: CW Door 27: 1 024x2 050; 310_Materjal: ootel; 320_Klaas: ootel; 340_Soojusläbivus: 0; 350_Klaaspakett: ootel; 355_Pindala: 2.09982 m2; 360_Ratastooliga: no; 365_Isesulguv: no; 370_Evakuatsiooniväljapääs: no; 375_Viimistlus-seest: RAL9017 must; 376_Viimistlus-väljast: RAL9017 must; 380_Lukustus: ootel; 900_Tootja: ootel; 905_Mudel: ootel; 910_Tooteinfo: -; 915_Kasutus-ja-hooldusjuhend: -; 306_Ava-laius: 1000 mm; 307_Ava-kõrgus: 2000 mm; 345_Päikesekiirgus-tegur: 0; 377_Leng: ootel; 378_Lävepakk: ootel; 379_Käepide: ootel; 381_Lukuraam: ootel; 382_Südamik: ootel; 383_Vasturaud: ootel; 384_Sulgur: meh.sulgur; 336_Sissepääs-hoonesse: no

# IfcDoor: 1115 x 2090 x -120, AVU10x23,EI30
In: 1.korrus
Type - OperationType: SINGLE_SWING_LEFT; ParameterTakesPrecedence: no; Sizeable: no
OverallHeight: 2050 mm; OverallWidth: 1075 mm; Classification: 1.10 IfcDoorStyle (uks) (IPI ÜBN); Door (ARCHICAD Classification+TK)
AC_Pset_RenovationAndPhasing - Renovation Status: Undefined
BaseQuantities - NetVolume: -0.26445 m3
Pset_ManufacturerOccurrence - SerialNumber: Off
AR_Uks - 001_Nimetus: Välisuks; 300_Tähis: CW Door 27: 1 075x2 050; 310_Materjal: ootel; 320_Klaas: ootel; 340_Soojusläbivus: 0; 350_Klaaspakett: ootel; 355_Pindala: 2.20375 m2; 360_Ratastooliga: no; 365_Isesulguv: no; 370_Evakuatsiooniväljapääs: no; 375_Viimistlus-seest: RAL9017 must; 376_Viimistlus-väljast: RAL9017 must; 380_Lukustus: ootel; 900_Tootja: ootel; 905_Mudel: ootel; 910_Tooteinfo: -; 915_Kasutus-ja-hooldusjuhend: -; 306_Ava-laius: 1000 mm; 307_Ava-kõrgus: 2000 mm; 345_Päikesekiirgus-tegur: 0; 377_Leng: ootel; 378_Lävepakk: ootel; 379_Käepide: ootel; 381_Lukuraam: ootel; 382_Südamik: ootel; 383_Vasturaud: ootel; 384_Sulgur: ootel; 336_Sissepääs-hoonesse: no

# IfcDoor: 1120 x 2090 x 20, AVU10+10x23
In: 1.korrus
Type - OperationType: DOUBLE_DOOR_SINGLE_SWING; ParameterTakesPrecedence: no; Sizeable: no
OverallHeight: 2050 mm; OverallWidth: 2200 mm; Classification: 1.10 IfcDoorStyle (uks) (IPI ÜBN); Door (ARCHICAD Classification+TK)
Pset_ManufacturerOccurrence - SerialNumber: Off
AR_Uks - 001_Nimetus: välisuks; 300_Tähis: CW Double Door 27: 2 200x2 050; 310_Materjal: ootel; 320_Klaas: ootel; 340_Soojusläbivus: 0; 350_Klaaspakett: ootel; 355_Pindala: 4.51 m2; 360_Ratastooliga: no; 365_Isesulguv: no; 370_Evakuatsiooniväljapääs: no; 375_Viimistlus-seest: RAL9017 must; 376_Viimistlus-väljast: RAL9017 must; 380_Lukustus: ootel; 900_Tootja: ootel; 905_Mudel: ootel; 910_Tooteinfo: -; 915_Kasutus-ja-hooldusjuhend: -; 306_Ava-laius: 2000 mm; 307_Ava-kõrgus: 2000 mm; 345_Päikesekiirgus-tegur: 0; 377_Leng: ootel; 378_Lävepakk: ootel; 379_Käepide: ootel; 381_Lukuraam: ootel; 382_Südamik: ootel; 383_Vasturaud: ootel; 384_Sulgur: ootel; 336_Sissepääs-hoonesse: no
AC_Pset_RenovationAndPhasing - Renovation Status: Undefined
BaseQuantities - NetVolume: 0.0902 m3

# IfcDoor: 133 x 2095 x 30 (2)
In: 2.korrus
Type - OperationType: SINGLE_SWING_LEFT; ParameterTakesPrecedence: no; Sizeable: no
OverallHeight: 2070 mm; OverallWidth: 960 mm; Classification: 1.10 IfcDoorStyle (uks) (IPI ÜBN); Door (ARCHICAD Classification+TK)
BaseQuantities - NetVolume: 0.059616 m3
AR_Uks - 001_Nimetus: Klaasitud puitsiseuks; 300_Tähis: CW Door 27: 960x2 070; 310_Materjal: ootel; 320_Klaas: ootel; 340_Soojusläbivus: 0; 350_Klaaspakett: ootel; 355_Pindala: 1.9872 m2; 360_Ratastooliga: no; 365_Isesulguv: no; 370_Evakuatsiooniväljapääs: no; 375_Viimistlus-seest: sinine RAL5003; 376_Viimistlus-väljast: sinine RAL5003; 380_Lukustus: ootel; 900_Tootja: ootel; 905_Mudel: ootel; 910_Tooteinfo: -; 915_Kasutus-ja-hooldusjuhend: -; 306_Ava-laius: 960000 mm; 307_Ava-kõrgus: 2000 mm; 345_Päikesekiirgus-tegur: 0; 377_Leng: ootel; 378_Lävepakk: ootel; 379_Käepide: ootel; 381_Lukuraam: ootel; 382_Südamik: ootel; 383_Vasturaud: ootel; 384_Sulgur: ootel; 336_Sissepääs-hoonesse: no
AC_Pset_RenovationAndPhasing - Renovation Status: Undefined
Pset_ManufacturerOccurrence - SerialNumber: Off

# IfcDoor: 20 x 5 x 40, AKU10+4,EI30
In: 2.korrus
Type - OperationType: DOUBLE_DOOR_SINGLE_SWING; ParameterTakesPrecedence: no; Sizeable: no
OverallHeight: 2275 mm; OverallWidth: 1410 mm; Classification: 1.10 IfcDoorStyle (uks) (IPI ÜBN); Door (ARCHICAD Classification+TK)
BaseQuantities - NetVolume: 0.128307 m3
AC_Pset_RenovationAndPhasing - Renovation Status: Undefined
Pset_ManufacturerOccurrence - SerialNumber: Off
AR_Uks - 001_Nimetus: Siseuks; 300_Tähis: CW Double Door Asymmetric 27: 1 410x2 275; 310_Materjal: ootel; 320_Klaas: ootel; 340_Soojusläbivus: 0; 350_Klaaspakett: ootel; 355_Pindala: 3.20768 m2; 360_Ratastooliga: no; 365_Isesulguv: no; 370_Evakuatsiooniväljapääs: no; 375_Viimistlus-seest: RAL9017 must; 376_Viimistlus-väljast: RAL9017 must; 380_Lukustus: ootel; 900_Tootja: ootel; 905_Mudel: ootel; 910_Tooteinfo: -; 915_Kasutus-ja-hooldusjuhend: -; 306_Ava-laius: 1000 mm; 307_Ava-kõrgus: 2000 mm; 345_Päikesekiirgus-tegur: 0; 377_Leng: ootel; 378_Lävepakk: ootel; 379_Käepide: ootel; 381_Lukuraam: ootel; 382_Südamik: ootel; 383_Vasturaud: ootel; 384_Sulgur: ootel; 336_Sissepääs-hoonesse: no

# IfcDoor: 330 x 2095 x 40, AU10+3,EI30
In: 1.korrus
Type - OperationType: DOUBLE_DOOR_SINGLE_SWING; ParameterTakesPrecedence: no; Sizeable: no
OverallHeight: 2075.38 mm; OverallWidth: 1410 mm; Classification: 1.10 IfcDoorStyle (uks) (IPI ÜBN); Door (ARCHICAD Classification+TK)
BaseQuantities - NetVolume: 0.117051 m3
AC_Pset_RenovationAndPhasing - Renovation Status: Undefined
Pset_ManufacturerOccurrence - SerialNumber: Off
AR_Uks - 001_Nimetus: siseuks; 300_Tähis: CW Double Door Asymmetric 27: 1 410x2 075; 310_Materjal: ootel; 320_Klaas: ootel; 340_Soojusläbivus: 0; 350_Klaaspakett: ootel; 355_Pindala: 2.92628 m2; 360_Ratastooliga: no; 365_Isesulguv: no; 370_Evakuatsiooniväljapääs: no; 375_Viimistlus-seest: RAL9017 must; 376_Viimistlus-väljast: RAL9017 must; 380_Lukustus: ootel; 900_Tootja: ootel; 905_Mudel: ootel; 910_Tooteinfo: -; 915_Kasutus-ja-hooldusjuhend: -; 306_Ava-laius: 1000 mm; 307_Ava-kõrgus: 2000 mm; 345_Päikesekiirgus-tegur: 0; 377_Leng: ootel; 378_Lävepakk: ootel; 379_Käepide: ootel; 381_Lukuraam: ootel; 382_Südamik: ootel; 383_Vasturaud: ootel; 384_Sulgur: ootel; 336_Sissepääs-hoonesse: no

# IfcDoor: 438 x 2070 x 30, PKU10,dB
In: 2.korrus
Type - OperationType: SINGLE_SWING_LEFT; ParameterTakesPrecedence: no; Sizeable: no
OverallHeight: 2070 mm; OverallWidth: 959.698 mm; Classification: 1.10 IfcDoorStyle (uks) (IPI ÜBN); Door (ARCHICAD Classification+TK)
AC_Pset_RenovationAndPhasing - Renovation Status: Undefined
Pset_ManufacturerOccurrence - SerialNumber: Off
BaseQuantities - NetVolume: 0.0595864 m3
AR_Uks - 001_Nimetus: Klaasitud puitsiseuks; 300_Tähis: CW Door 27: 960x2 070; 310_Materjal: ootel; 320_Klaas: ootel; 340_Soojusläbivus: 0; 350_Klaaspakett: ootel; 355_Pindala: 1.98621 m2; 360_Ratastooliga: no; 365_Isesulguv: no; 370_Evakuatsiooniväljapääs: no; 375_Viimistlus-seest: sinine RAL5003; 376_Viimistlus-väljast: sinine RAL5003; 380_Lukustus: ootel; 900_Tootja: ootel; 905_Mudel: ootel; 910_Tooteinfo: -; 915_Kasutus-ja-hooldusjuhend: -; 306_Ava-laius: 960000 mm; 307_Ava-kõrgus: 2000 mm; 345_Päikesekiirgus-tegur: 0; 377_Leng: ootel; 378_Lävepakk: ootel; 379_Käepide: ootel; 381_Lukuraam: ootel; 382_Südamik: ootel; 383_Vasturaud: ootel; 384_Sulgur: ootel; 336_Sissepääs-hoonesse: no

# IfcDoor: 613 x 2075 x 40, PKU10,dB
In: 2.korrus
Type - OperationType: SINGLE_SWING_LEFT; ParameterTakesPrecedence: no; Sizeable: no
OverallHeight: 2050 mm; OverallWidth: 940 mm; Classification: 1.10 IfcDoorStyle (uks) (IPI ÜBN); Door (ARCHICAD Classification+TK)
BaseQuantities - NetVolume: 0.07708 m3
AC_Pset_RenovationAndPhasing - Renovation Status: Undefined
Pset_ManufacturerOccurrence - SerialNumber: Off
AR_Uks - 001_Nimetus: Klaasitud puitsiseuks; 300_Tähis: CW Door 27: 940x2 050; 310_Materjal: ootel; 320_Klaas: ootel; 340_Soojusläbivus: 0; 350_Klaaspakett: ootel; 355_Pindala: 1.927 m2; 360_Ratastooliga: no; 365_Isesulguv: no; 370_Evakuatsiooniväljapääs: no; 375_Viimistlus-seest: sinine RAL5003; 376_Viimistlus-väljast: sinine RAL5003; 380_Lukustus: ootel; 900_Tootja: ootel; 905_Mudel: ootel; 910_Tooteinfo: -; 915_Kasutus-ja-hooldusjuhend: -; 306_Ava-laius: 940000 mm; 307_Ava-kõrgus: 2000 mm; 345_Päikesekiirgus-tegur: 0; 377_Leng: ootel; 378_Lävepakk: ootel; 379_Käepide: ootel; 381_Lukuraam: ootel; 382_Südamik: ootel; 383_Vasturaud: ootel; 384_Sulgur: ootel; 336_Sissepääs-hoonesse: no

# IfcDoor: 613 x 2095 x 30, PKU10,dB
In: 2.korrus
Type - OperationType: SINGLE_SWING_LEFT; ParameterTakesPrecedence: no; Sizeable: no
OverallHeight: 2070 mm; OverallWidth: 940 mm; Classification: 1.10 IfcDoorStyle (uks) (IPI ÜBN); Door (ARCHICAD Classification+TK)
BaseQuantities - NetVolume: 0.058374 m3
AC_Pset_RenovationAndPhasing - Renovation Status: Undefined
Pset_ManufacturerOccurrence - SerialNumber: Off
AR_Uks - 001_Nimetus: Klaasitud puitsiseuks; 300_Tähis: CW Door 27: 940x2 070; 310_Materjal: ootel; 320_Klaas: ootel; 340_Soojusläbivus: 0; 350_Klaaspakett: ootel; 355_Pindala: 1.9458 m2; 360_Ratastooliga: no; 365_Isesulguv: no; 370_Evakuatsiooniväljapääs: no; 375_Viimistlus-seest: sinine RAL5003; 376_Viimistlus-väljast: sinine RAL5003; 380_Lukustus: ootel; 900_Tootja: ootel; 905_Mudel: ootel; 910_Tooteinfo: -; 915_Kasutus-ja-hooldusjuhend: -; 306_Ava-laius: 940000 mm; 307_Ava-kõrgus: 2000 mm; 345_Päikesekiirgus-tegur: 0; 377_Leng: ootel; 378_Lävepakk: ootel; 379_Käepide: ootel; 381_Lukuraam: ootel; 382_Südamik: ootel; 383_Vasturaud: ootel; 384_Sulgur: ootel; 336_Sissepääs-hoonesse: no

# IfcDoor: 728 x 2095 x 30, PKU10,dB
In: 2.korrus
Type - OperationType: SINGLE_SWING_LEFT; ParameterTakesPrecedence: no; Sizeable: no
OverallHeight: 2070 mm; OverallWidth: 940 mm; Classification: 1.10 IfcDoorStyle (uks) (IPI ÜBN); Door (ARCHICAD Classification+TK)
BaseQuantities - NetVolume: 0.058374 m3
AC_Pset_RenovationAndPhasing - Renovation Status: Undefined
Pset_ManufacturerOccurrence - SerialNumber: Off
AR_Uks - 001_Nimetus: Klaasitud puitsiseuks; 300_Tähis: CW Door 27: 940x2 070; 310_Materjal: ootel; 320_Klaas: ootel; 340_Soojusläbivus: 0; 350_Klaaspakett: ootel; 355_Pindala: 1.9458 m2; 360_Ratastooliga: no; 365_Isesulguv: no; 370_Evakuatsiooniväljapääs: no; 375_Viimistlus-seest: sinine RAL5003; 376_Viimistlus-väljast: sinine RAL5003; 380_Lukustus: ootel; 900_Tootja: ootel; 905_Mudel: ootel; 910_Tooteinfo: -; 915_Kasutus-ja-hooldusjuhend: -; 306_Ava-laius: 940000 mm; 307_Ava-kõrgus: 2000 mm; 345_Päikesekiirgus-tegur: 0; 377_Leng: ootel; 378_Lävepakk: ootel; 379_Käepide: ootel; 381_Lukuraam: ootel; 382_Südamik: ootel; 383_Vasturaud: ootel; 384_Sulgur: ootel; 336_Sissepääs-hoonesse: no

# IfcDoor: 831 x 2290 x 40, AKU10+4,EI30
In: 2.korrus
Type - OperationType: DOUBLE_DOOR_SINGLE_SWING; ParameterTakesPrecedence: no; Sizeable: no
OverallHeight: 2250 mm; OverallWidth: 1410 mm; Classification: 1.10 IfcDoorStyle (uks) (IPI ÜBN); Door (ARCHICAD Classification+TK)
AR_Uks - 001_Nimetus: Siseuks; 300_Tähis: CW Double Door Asymmetric 27: 1 410x2 250; 310_Materjal: ootel; 320_Klaas: ootel; 340_Soojusläbivus: 0; 350_Klaaspakett: ootel; 355_Pindala: 3.1725 m2; 360_Ratastooliga: no; 365_Isesulguv: no; 370_Evakuatsiooniväljapääs: no; 375_Viimistlus-seest: RAL9017 must; 376_Viimistlus-väljast: RAL9017 must; 380_Lukustus: ootel; 900_Tootja: ootel; 905_Mudel: ootel; 910_Tooteinfo: -; 915_Kasutus-ja-hooldusjuhend: -; 306_Ava-laius: 1000 mm; 307_Ava-kõrgus: 2000 mm; 345_Päikesekiirgus-tegur: 0; 377_Leng: ootel; 378_Lävepakk: ootel; 379_Käepide: ootel; 381_Lukuraam: ootel; 382_Südamik: ootel; 383_Vasturaud: ootel; 384_Sulgur: ootel; 336_Sissepääs-hoonesse: no
Pset_ManufacturerOccurrence - SerialNumber: Off
BaseQuantities - NetVolume: 0.1269 m3
AC_Pset_RenovationAndPhasing - Renovation Status: Undefined

# IfcDoor: 990 x 2095 x 30, PKU10,dB
In: 2.korrus
Type - OperationType: SINGLE_SWING_RIGHT; ParameterTakesPrecedence: no; Sizeable: no
OverallHeight: 2080 mm; OverallWidth: 960.002 mm; Classification: 1.10 IfcDoorStyle (uks) (IPI ÜBN); Door (ARCHICAD Classification+TK)
BaseQuantities - NetVolume: 0.0599041 m3
Pset_ManufacturerOccurrence - SerialNumber: Off
AC_Pset_RenovationAndPhasing - Renovation Status: Undefined
AR_Uks - 001_Nimetus: Klaasitud puitsiseuks; 300_Tähis: CW Door 27: 960x2 080; 310_Materjal: ootel; 320_Klaas: ootel; 340_Soojusläbivus: 0; 350_Klaaspakett: ootel; 355_Pindala: 1.9968 m2; 360_Ratastooliga: no; 365_Isesulguv: no; 370_Evakuatsiooniväljapääs: no; 375_Viimistlus-seest: sinine RAL5003; 376_Viimistlus-väljast: sinine RAL5003; 380_Lukustus: ootel; 900_Tootja: ootel; 905_Mudel: ootel; 910_Tooteinfo: -; 915_Kasutus-ja-hooldusjuhend: -; 306_Ava-laius: 960000 mm; 307_Ava-kõrgus: 2000 mm; 345_Päikesekiirgus-tegur: 0; 377_Leng: ootel; 378_Lävepakk: ootel; 379_Käepide: ootel; 381_Lukuraam: ootel; 382_Südamik: ootel; 383_Vasturaud: ootel; 384_Sulgur: ootel; 336_Sissepääs-hoonesse: no

# IfcDoor: 992 x 2070 x 30, PKU10,dB
In: 2.korrus
Type - OperationType: SINGLE_SWING_LEFT; ParameterTakesPrecedence: no; Sizeable: no
OverallHeight: 2070 mm; OverallWidth: 961.811 mm; Classification: 1.10 IfcDoorStyle (uks) (IPI ÜBN); Door (ARCHICAD Classification+TK)
BaseQuantities - NetVolume: 0.0588638 m3
AC_Pset_RenovationAndPhasing - Renovation Status: Undefined
Pset_ManufacturerOccurrence - SerialNumber: Off
AR_Uks - 001_Nimetus: Klaasitud puitsiseuks; 300_Tähis: CW Door 27: 962x2 070; 310_Materjal: ootel; 320_Klaas: ootel; 340_Soojusläbivus: 0; 350_Klaaspakett: ootel; 355_Pindala: 1.96213 m2; 360_Ratastooliga: no; 365_Isesulguv: no; 370_Evakuatsiooniväljapääs: no; 375_Viimistlus-seest: sinine RAL5003; 376_Viimistlus-väljast: sinine RAL5003; 380_Lukustus: ootel; 900_Tootja: ootel; 905_Mudel: ootel; 910_Tooteinfo: -; 915_Kasutus-ja-hooldusjuhend: -; 306_Ava-laius: 962000 mm; 307_Ava-kõrgus: 2000 mm; 345_Päikesekiirgus-tegur: 0; 377_Leng: ootel; 378_Lävepakk: ootel; 379_Käepide: ootel; 381_Lukuraam: ootel; 382_Südamik: ootel; 383_Vasturaud: ootel; 384_Sulgur: ootel; 336_Sissepääs-hoonesse: no

# IfcDoor: APU F67 Thermo - Industrial Sectional Door (3)
In: 1.korrus
Type - ParameterTakesPrecedence: no; Sizeable: no
OverallHeight: 2600 mm; OverallWidth: 2500 mm; Classification: 1.10 IfcDoorStyle (uks) (IPI ÜBN); Door (ARCHICAD Classification+TK)
BaseQuantities - Height: 2600 mm; Width: 2500 mm; Perimeter: 10200 mm; Area: 6.5 m2; Volume: 0.312401 m3; Depth: 437 mm; NetVolume: 0.312401 m3
AC_Pset_RenovationAndPhasing - Renovation Status: New
AR_Uks - 001_Nimetus: Niiskuskindel siseuks; 300_Tähis: TÕU25x26; 310_Materjal: puit; 315_Avanemine: Vasak; 320_Klaas: -; 325_Helipidavus: -; 335_Välispiire: no; 340_Soojusläbivus: 0; 350_Klaaspakett: -; 355_Pindala: 6.5 m2; 360_Ratastooliga: no; 365_Isesulguv: no; 370_Evakuatsiooniväljapääs: no; 376_Viimistlus-väljast: Metal - Zinc; 380_Lukustus: ootel; 900_Tootja: ootel; 905_Mudel: ootel; 910_Tooteinfo: -; 915_Kasutus-ja-hooldusjuhend: -; 306_Ava-laius: 2000 mm; 307_Ava-kõrgus: 2000 mm; 345_Päikesekiirgus-tegur: 0; 377_Leng: ootel; 378_Lävepakk: r/v terasest; 379_Käepide: ootel; 381_Lukuraam: ootel; 382_Südamik: ootel; 383_Vasturaud: ootel; 384_Sulgur: -; 336_Sissepääs-hoonesse: no
Pset_ManufacturerTypeInformation - Manufacturer: HÖRMANN

# IfcDoor: Door 27 (34)
Type - OperationType: SINGLE_SWING_LEFT; ParameterTakesPrecedence: no; Sizeable: no
AR_Uks - 315_Avanemine: Parem; 340_Soojusläbivus: 0; 360_Ratastooliga: no; 365_Isesulguv: no; 370_Evakuatsiooniväljapääs: no; 910_Tooteinfo: -; 915_Kasutus-ja-hooldusjuhend: -; 345_Päikesekiirgus-tegur: 0; 377_Leng: ootel; 379_Käepide: ootel; 381_Lukuraam: ootel; 382_Südamik: ootel; 383_Vasturaud: ootel; 336_Sissepääs-hoonesse: no
Name | In | OverallHeight (mm) = Height (mm) | OverallWidth (mm) | Classification | FireResistanceRating | 001_Nimetus | 300_Tähis | 310_Materjal | 320_Klaas = 350_Klaaspakett = 384_Sulgur | 325_Helipidavus | 335_Välispiire | 355_Pindala (m2) | 375_Viimistlus-seest = 376_Viimistlus-väljast | 380_Lukustus | 900_Tootja = 905_Mudel | 306_Ava-laius (mm) | 307_Ava-kõrgus (mm) | 378_Lävepakk | Width (mm) | Perimeter (mm) | Area (m2) | Volume (m3) = NetVolume (m3) | Depth (mm) | Renovation Status
TU8,5,EI30 | 1.korrus | 2110 | 870 | 1.10 IfcDoorStyle (uks) (IPI ÜBN); Door (ARCHICAD Classification+TK) | EI30 | Niiskuskindel siseuks | TU8,5,EI30 | puit | - | - | no | 1.8357 | sinine RAL5003 | ootel | ootel | 870000 | 2000 | r/v terasest | 870 | 5960 | 1.8357 | 0.126826 | 190 | New
3 x PU10 | 1.korrus | 2110 | 1010 | 1.10 IfcDoorStyle (uks) (IPI ÜBN); Door (ARCHICAD Classification+TK) | - | Niiskuskindel siseuks | PU10 | puit | - | - | no | 2.1311 | sinine RAL5003 | ootel | ootel | 1000 | 2000 | - | 1010 | 6240 | 2.1311 | 0.146237 | 140 | New
2 x TU9,EI30,dB | 1.korrus | 2110 | 910 | 1.10 IfcDoorStyle (uks) (IPI ÜBN); Door (ARCHICAD Classification+TK) | EI30 | Niiskuskindel siseuks | TU9,EI30,dB | puit | - | - | no | 1.9201 | sinine RAL5003 | ootel | ootel | 910000 | 2000 | allalaskuv | 910 | 6040 | 1.9201 | 0.132372 | 190 | New
2 x NU8 | 1.korrus | 2110 | 810 | 1.10 IfcDoorStyle (uks) (IPI ÜBN); Door (ARCHICAD Classification+TK) | - | Niiskuskindel siseuks | NU8 | puit | - | - | no | 1.7091 | sinine RAL5003 | ootel | ootel | 810000 | 2000 | - | 810 | 5840 | 1.7091 | 0.118714 | 140 | New
PU8 | 1.korrus | 2110 | 810 | 1.10 IfcDoorStyle (uks) (IPI ÜBN); Door (ARCHICAD Classification+TK) | - | Niiskuskindel siseuks | PU8 | puit | - | - | no | 1.7091 | sinine RAL5003 | ootel | ootel | 810000 | 2000 | - | 810 | 5840 | 1.7091 | 0.118507 | 140 | New
PU8 | 1.korrus | 2110 | 810 | 1.10 IfcDoorStyle (uks) (IPI ÜBN); Door (ARCHICAD Classification+TK) | - | Niiskuskindel siseuks | PU8 | puit | - | - | no | 1.7091 | sinine RAL5003 | ootel | ootel | 810000 | 2000 | - | 808.973 | 5837.95 | 1.70693 | 0.118507 | 140 | New
 | 1.korrus | 2100 | 1200 | 1.10 IfcDoorStyle (uks) (IPI ÜBN) |  | Olemasolev siseuks ühepoolne |  | ootel | ootel |  | no | 2.52 | RAL 7022 | ootel | - | 1000 | 2000 | ootel | 1200 | 6600 | 2.52 | 0.130691 | 660 | Existing
SU-XX | 1.korrus | 2100 | 900 | 1.10 IfcDoorStyle (uks) (IPI ÜBN) |  | Olemasolev siseuks ühepoolne | SU-XX | ootel | ootel |  | no | 1.89 | RAL 9010 | ootel | ootel | 900000 | 2000 | ootel | 900 | 6000 | 1.89 | 0.112549 | 360 | Existing
 | 1.korrus | 2050 | 850 | 1.10 IfcDoorStyle (uks) (IPI ÜBN) |  | Olemasolev välisuks ühepoolne |  | ootel | ootel |  | yes | 1.7425 | RAL 9007 | ootel | ootel | 850000 | 2000 | ootel | 850 | 5800 | 1.7425 | 0.0814539 | 100 | Existing
SU-XX | 1.korrus | 2100 | 730 | 1.10 IfcDoorStyle (uks) (IPI ÜBN) |  | Olemasolev siseuks ühepoolne | SU-XX | ootel | ootel |  | no | 1.533 | RAL 9010 | ootel | ootel | 730000 | 2000 | ootel | 730 | 5660 | 1.533 | 0.087033 | 150 | Existing
SU-XX | 1.korrus | 2100 | 700 | 1.10 IfcDoorStyle (uks) (IPI ÜBN) |  | Olemasolev siseuks ühepoolne | SU-XX | ootel | ootel |  | no | 1.47 | RAL 9010 | ootel | ootel | 700000 | 2000 | ootel | 700 | 5600 | 1.47 | 0.0838191 | 150 | Existing
SU-XX | 1.korrus | 2030 | 910 | 1.10 IfcDoorStyle (uks) (IPI ÜBN) |  | Olemasolev siseuks ühepoolne | SU-XX | ootel | ootel |  | no | 1.8473 | RAL 9010 | ootel | ootel | 910000 | 2000 | ootel | 910 | 5880 | 1.8473 | 0.118209 | 270 | Existing
SU-XX | 1.korrus | 2100 | 1000 | 1.10 IfcDoorStyle (uks) (IPI ÜBN) |  | Olemasolev siseuks ühepoolne | SU-XX | ootel | ootel |  | no | 2.1 | RAL 5014 | ootel | ootel | 1000 | 2000 | ootel | 1000 | 6200 | 2.1 | 0.137428 | 360 | Existing
SU-XX | 1.korrus | 2100 | 950 | 1.10 IfcDoorStyle (uks) (IPI ÜBN) |  | Siseuks ühepoolne | SU-XX | ootel | ootel |  | no | 1.995 | RAL 9010 | ootel | ootel | 950000 | 2000 | ootel | 950 | 6100 | 1.995 | 0.089631 | 100 | Existing
SU-XX | 1.korrus | 1755.26 | 835 | 1.10 IfcDoorStyle (uks) (IPI ÜBN) |  | Olemasolev siseuks ühepoolne | SU-XX | ootel | ootel |  | no | 1.46564 | RAL 9010 | ootel | ootel | 835000 | 1000 | ootel | 835 | 5180.51 | 1.46564 | 0.0943725 | 120 | Existing
SU-XX | 1.korrus | 2030 | 810.119 | 1.10 IfcDoorStyle (uks) (IPI ÜBN) |  | Olemasolev siseuks ühepoolne | SU-XX | ootel | ootel |  | no | 1.64454 | RAL 9010 | ootel | ootel | 810000 | 2000 | ootel | 810.119 | 5680.24 | 1.64454 | 0.105894 | 140 | Existing
SU-XX | 1.korrus | 2100 | 970 | 1.10 IfcDoorStyle (uks) (IPI ÜBN) |  | Olemasolev siseuks ühepoolne | SU-XX | ootel | ootel |  | no | 2.037 | RAL 9010 | ootel | ootel | 970000 | 2000 | ootel | 970 | 6140 | 2.037 | 0.13539 | 100 | Existing
SU-XX | 1.korrus | 2140 | 810 | 1.10 IfcDoorStyle (uks) (IPI ÜBN) |  | Olemasolev siseuks ühepoolne | SU-XX | ootel | ootel |  | no | 1.7334 | RAL 9010 | ootel | ootel | 810000 | 2000 | ootel | 810 | 5900 | 1.7334 | 0.111144 | 100 | Existing
4 x PU8 | 2.korrus | 2110 | 810 | 1.10 IfcDoorStyle (uks) (IPI ÜBN); Door (ARCHICAD Classification+TK) | - | Niiskuskindel siseuks | PU8 | puit | - | - | no | 1.7091 | sinine RAL5003 | ootel | ootel | 810000 | 2000 | - | 810 | 5840 | 1.7091 | 0.118507 | 147 | New
PU10,EI30 | 2.korrus | 2110 | 1010 | 1.10 IfcDoorStyle (uks) (IPI ÜBN); Door (ARCHICAD Classification+TK) | EI30 | Tulekindel siseuks | PU10,EI30 | puit | - | - | no | 2.1311 | sinine RAL5003 | solenoid | ootel | 1000 | 2000 | - | 1010 | 6240 | 2.1311 | 0.146504 | 147 | New
PU10,EI30,dB | 2.korrus | 2110 | 1010 | 1.10 IfcDoorStyle (uks) (IPI ÜBN); Door (ARCHICAD Classification+TK) | EI30 | Niiskuskindel siseuks | PU10,EI30,dB | puit | - | - | no | 2.1311 | sinine RAL5003 | ootel | ootel | 1000 | 2000 | allalaskuv | 1010 | 6240 | 2.1311 | 0.146237 | 147 | New
PU10,dB | 2.korrus | 2110 | 1010 | 1.10 IfcDoorStyle (uks) (IPI ÜBN); Door (ARCHICAD Classification+TK) | - | Niiskuskindel siseuks | PU10,dB | puit | - | - | no | 2.1311 | sinine RAL5003 | ootel | ootel | 1000 | 2000 | - | 1010 | 6240 | 2.1311 | 0.146237 | 147 | New
NU8 | 2.korrus | 2110 | 810 | 1.10 IfcDoorStyle (uks) (IPI ÜBN); Door (ARCHICAD Classification+TK) | - | Niiskuskindel siseuks | NU8 | puit | - | - | no | 1.7091 | sinine RAL5003 | ootel | ootel | 810000 | 2000 | - | 810 | 5840 | 1.7091 | 0.118714 | 147 | New
PU10,dB | 2.korrus | 2110 | 1010 | 1.10 IfcDoorStyle (uks) (IPI ÜBN); Door (ARCHICAD Classification+TK) | - | Niiskuskindel siseuks | PU10,dB | puit | - | - | no | 2.1311 | sinine RAL5003 | ootel | ootel | 1000 | 2000 | allalaskuv | 1010 | 6240 | 2.1311 | 0.146237 | 147 | New
TVU7x7,EI30 | Pööningukorrus | 710 | 710 | 1.10 IfcDoorStyle (uks) (IPI ÜBN); Door (ARCHICAD Classification+TK) | EI30 | Tulekindel luuk | TVU7x7,EI30 | teras | - | - | yes | 0.5041 | valge | ootel | ootel | 710000 | 710000 | r/v terasest | 710 | 2840 | 0.5041 | 0.0381935 | 236 | New
TVU8 | Pööningukorrus | 2110 | 810 | 1.10 IfcDoorStyle (uks) (IPI ÜBN); Door (ARCHICAD Classification+TK); Elements (Archicad Classification) | EI30 | Tuletõkkeuks | TVU8 | teras | - | - | yes | 1.7091 | valge | ootel | ootel | 810000 | 2000 | r/v terasest | 810 | 5840 | 1.7091 | 0.124399 | 200 | New
TVU7x7,EI30 | Pööningukorrus | 710 | 710 | 1.10 IfcDoorStyle (uks) (IPI ÜBN); Door (ARCHICAD Classification+TK) | EI30 | Niiskuskindel siseuks | TVU7x7,EI30 | puit | - | - | yes | 0.5041 | valge | ootel | ootel | 710000 | 710000 | r/v terasest | 710 | 2840 | 0.5041 | 0.0381935 | 200 | New

# IfcDoor: Door 27 (39)
Type - OperationType: SINGLE_SWING_RIGHT; ParameterTakesPrecedence: no; Sizeable: no
AR_Uks - 315_Avanemine: Vasak; 340_Soojusläbivus: 0; 360_Ratastooliga: no; 910_Tooteinfo: -; 915_Kasutus-ja-hooldusjuhend: -; 345_Päikesekiirgus-tegur: 0; 377_Leng: ootel; 379_Käepide: ootel; 381_Lukuraam: ootel; 382_Südamik: ootel; 383_Vasturaud: ootel; 336_Sissepääs-hoonesse: no
Name | In | OverallHeight (mm) | OverallWidth (mm) = Width (mm) | Classification | Height (mm) | Perimeter (mm) | Area (m2) | Volume (m3) = NetVolume (m3) | Depth (mm) | Renovation Status | FireResistanceRating | 001_Nimetus | 300_Tähis | 310_Materjal | 320_Klaas = 350_Klaaspakett | 325_Helipidavus | 335_Välispiire | 355_Pindala (m2) | 365_Isesulguv = 370_Evakuatsiooniväljapääs | 375_Viimistlus-seest = 376_Viimistlus-väljast | 380_Lukustus | 900_Tootja = 905_Mudel | 306_Ava-laius (mm) | 307_Ava-kõrgus (mm) | 378_Lävepakk | 384_Sulgur
TU10,EI30 | 1.korrus | 2110 | 1010 | 1.10 IfcDoorStyle (uks) (IPI ÜBN); Door (ARCHICAD Classification+TK) | 2110 | 6240 | 2.1311 | 0.146237 | 190 | New | EI30 | Niiskuskindel siseuks | TU10,EI30 | puit | - | - | no | 2.1311 | no | sinine RAL5003 | ootel | ootel | 1000 | 2000 | r/v terasest | -
4 x PU9,dB | 1.korrus | 2110 | 910 | 1.10 IfcDoorStyle (uks) (IPI ÜBN); Door (ARCHICAD Classification+TK) | 2110 | 6040 | 1.9201 | 0.132372 | 140 | New | - | Niiskuskindel siseuks | PU9,dB | puit | - | - | no | 1.9201 | no | sinine RAL5003 | ootel | ootel | 910000 | 2000 | allalaskuv | -
NU8 | 1.korrus | 2110 | 810 | 1.10 IfcDoorStyle (uks) (IPI ÜBN); Door (ARCHICAD Classification+TK) | 2110 | 5840 | 1.7091 | 0.118507 | 140 | New | - | Niiskuskindel siseuks | NU8 | puit | - | - | no | 1.7091 | no | sinine RAL5003 | ootel | ootel | 810000 | 2000 | - | -
5 x PU8 | 1.korrus | 2110 | 810 | 1.10 IfcDoorStyle (uks) (IPI ÜBN); Door (ARCHICAD Classification+TK) | 2110 | 5840 | 1.7091 | 0.118507 | 140 | New | - | Niiskuskindel siseuks | PU8 | puit | - | - | no | 1.7091 | no | sinine RAL5003 | ootel | ootel | 810000 | 2000 | - | -
2 x TU9,EI60 | 1.korrus | 2110 | 910 | 1.10 IfcDoorStyle (uks) (IPI ÜBN); Door (ARCHICAD Classification+TK) | 2110 | 6040 | 1.9201 | 0.132372 | 190 | New | EI60 | Niiskuskindel siseuks | TU9,EI60 | puit | - | - | no | 1.9201 | no | sinine RAL5003 | ootel | ootel | 910000 | 2000 | - | meh.sulgur
TU8 | 1.korrus | 2110 | 810 | 1.10 IfcDoorStyle (uks) (IPI ÜBN); Door (ARCHICAD Classification+TK) | 2110 | 5840 | 1.7091 | 0.118507 | 190 | New | - | Niiskuskindel siseuks | TU8 | puit | - | - | no | 1.7091 | no | sinine RAL5003 | ootel | ootel | 810000 | 2000 | r/v terasest | -
NU8 | 1.korrus | 2110 | 810 | 1.10 IfcDoorStyle (uks) (IPI ÜBN); Door (ARCHICAD Classification+TK) | 2110 | 5840 | 1.7091 | 0.118714 | 140 | New | - | Niiskuskindel siseuks | NU8 | puit | - | - | no | 1.7091 | no | sinine RAL5003 | ootel | ootel | 810000 | 2000 | - | -
SU-XX | 1.korrus | 2070 | 900 | 1.10 IfcDoorStyle (uks) (IPI ÜBN) | 2070 | 5940 | 1.863 | 0.129399 | 360 | Existing |  | Olemasolev siseuks ühepoolne | SU-XX | ootel | ootel |  | no | 1.863 | no | RAL 9010 | ootel | ootel | 900000 | 2000 | ootel | ootel
SU-XX | 1.korrus | 2060 | 880 | 1.10 IfcDoorStyle (uks) (IPI ÜBN) | 2060 | 5880 | 1.8128 | 0.121496 | 360 | Existing |  | Olemasolev siseuks ühepoolne | SU-XX | ootel | ootel |  | no | 1.8128 | no | RAL 9010 | ootel | ootel | 880000 | 2000 | ootel | ootel
SU-XX | 1.korrus | 2060 | 1100 | 1.10 IfcDoorStyle (uks) (IPI ÜBN) | 2060 | 6320 | 2.266 | 0.10308 | 300 | Existing |  | Siseuks ühepoolne | SU-XX | ootel | ootel |  | no | 2.266 | no | RAL 7022 | ootel | ootel | 1000 | 2000 | ootel | ootel
SU-XX | 1.korrus | 2100 | 925 | 1.10 IfcDoorStyle (uks) (IPI ÜBN) | 2100 | 6050 | 1.9425 | 0.123789 | 200 | Existing |  | Olemasolev siseuks ühepoolne | SU-XX | ootel | ootel |  | no | 1.9425 | no | RAL 5014 | ootel | ootel | 925000 | 2000 | ootel | ootel
2 x  | 1.korrus | 2050 | 850 | 1.10 IfcDoorStyle (uks) (IPI ÜBN) | 2050 | 5800 | 1.7425 | 0.0814539 | 100 | Existing |  | Olemasolev välisuks ühepoolne |  | ootel | ootel |  | yes | 1.7425 | no | RAL 9007 | ootel | ootel | 850000 | 2000 | ootel | ootel
SU-XX | 1.korrus | 2100 | 730 | 1.10 IfcDoorStyle (uks) (IPI ÜBN) | 2100 | 5660 | 1.533 | 0.087033 | 150 | Existing |  | Olemasolev siseuks ühepoolne | SU-XX | ootel | ootel |  | no | 1.533 | no | RAL 9010 | ootel | ootel | 730000 | 2000 | ootel | ootel
SU-XX | 1.korrus | 2100 | 700 | 1.10 IfcDoorStyle (uks) (IPI ÜBN) | 2100 | 5600 | 1.47 | 0.0838191 | 150 | Existing |  | Olemasolev siseuks ühepoolne | SU-XX | ootel | ootel |  | no | 1.47 | no | RAL 9010 | ootel | ootel | 700000 | 2000 | ootel | ootel
 | 1.korrus | 2070 | 920 | 1.10 IfcDoorStyle (uks) (IPI ÜBN) | 2070 | 5980 | 1.9044 | 0.0994039 | 150 | Existing |  | Olemasolev siseuks ühepoolne |  | ootel | ootel |  | no | 1.9044 | no | RAL 7004 | ootel | - | 920000 | 2000 | ootel | ootel
 | 1.korrus | 2070 | 900 | 1.10 IfcDoorStyle (uks) (IPI ÜBN) | 2070 | 5940 | 1.863 | 0.0809125 | 150 | Existing |  | Olemasolev siseuks ühepoolne |  | ootel | ootel |  | no | 1.863 | no | RAL 7004 | ootel | - | 900000 | 2000 | ootel | ootel
SU-XX | 1.korrus | 2050 | 615.223 | 1.10 IfcDoorStyle (uks) (IPI ÜBN) | 2050 | 5330.45 | 1.26121 | 0.0491116 | 25 | Existing |  | Siseuks ühepoolne | SU-XX | ootel | ootel |  | no | 1.26121 | no | RAL 7022 | ootel | ootel | 615000 | 2000 | ootel | ootel
SU-XX | 1.korrus | 2100 | 900 | 1.10 IfcDoorStyle (uks) (IPI ÜBN) | 2100 | 6000 | 1.89 | 0.120966 | 120 | Existing |  | Olemasolev siseuks ühepoolne | SU-XX | ootel | ootel |  | no | 1.89 | no | RAL 9010 | ootel | ootel | 900000 | 2000 | ootel | ootel
SU-XX | 1.korrus | 2140 | 700 | 1.10 IfcDoorStyle (uks) (IPI ÜBN) | 2140 | 5680 | 1.498 | 0.0968219 | 100 | Existing |  | Olemasolev siseuks ühepoolne | SU-XX | ootel | ootel |  | no | 1.498 | no | RAL 9010 | ootel | ootel | 700000 | 2000 | ootel | ootel
SU-XX | 1.korrus | 2140 | 850 | 1.10 IfcDoorStyle (uks) (IPI ÜBN) | 2140 | 5980 | 1.819 | 0.116352 | 100 | Existing |  | Olemasolev siseuks ühepoolne | SU-XX | ootel | ootel |  | no | 1.819 | no | RAL 9010 | ootel | ootel | 850000 | 2000 | ootel | ootel
 | 1.korrus | 1720 | 800 | 1.10 IfcDoorStyle (uks) (IPI ÜBN) | 1720 | 5040 | 1.376 | 0.0584339 | 60 | Existing |  | Olemasolev välisuks ühepoolne |  | ootel | ootel |  | yes | 1.376 | no | RAL 7045 | ootel | ootel | 800000 | 1000 | ootel | ootel
NU8 | 2.korrus | 2110 | 810 | 1.10 IfcDoorStyle (uks) (IPI ÜBN); Door (ARCHICAD Classification+TK) | 2110 | 5840 | 1.7091 | 0.118714 | 147 | New | - | Niiskuskindel siseuks | NU8 | puit | - | - | no | 1.7091 | no | sinine RAL5003 | ootel | ootel | 810000 | 2000 | - | -
PKU10,dB | 2.korrus | 2110 | 1010 | 1.10 IfcDoorStyle (uks) (IPI ÜBN); Door (ARCHICAD Classification+TK) | 2110 | 6240 | 2.1311 | 0.0644624 | 236 | New | - | Niiskuskindel siseuks | PKU10,dB | puit | - | - | no | 2.1311 | no | sinine RAL5003 | ootel | ootel | 1000 | 2000 | allalaskuv | -
PU9x13v,EI30 | 2.korrus | 1310 | 910 | 1.10 IfcDoorStyle (uks) (IPI ÜBN); Door (ARCHICAD Classification+TK) | 1310 | 4440 | 1.1921 | 0.0828385 | 147 | New | EI30 | Niiskuskindel siseuks | PU9x13v,EI30 | puit | - | - | no | 1.1921 | no | valge | ootel | ootel | 910000 | 1000 | allalaskuv | -
PU10,dB | 2.korrus | 2110 | 1010 | 1.10 IfcDoorStyle (uks) (IPI ÜBN); Door (ARCHICAD Classification+TK) | 2110 | 6240 | 2.1311 | 0.146237 | 147 | New | - | Niiskuskindel siseuks | PU10,dB | puit | - | - | no | 2.1311 | no | sinine RAL5003 | ootel | ootel | 1000 | 2000 | - | -
TU9,dB, EI30 | 2.korrus | 2110 | 910 | 1.10 IfcDoorStyle (uks) (IPI ÜBN); Door (ARCHICAD Classification+TK) | 2100 | 6020 | 1.911 | 0.0956665 | 190 | New | EI30 | Tulekindel terasuks | TU9,dB, EI30 | teras | - | 35dB | no | 1.9201 | yes | sinine RAL5003 | solenoid | ootel | 910000 | 2000 | r/v terasest | meh.sulgur | AR_Uks - 330_Tulepüsivus: EI30
PU9v,EI30 | 2.korrus | 2110 | 910 | 1.10 IfcDoorStyle (uks) (IPI ÜBN); Door (ARCHICAD Classification+TK) | 2110 | 6040 | 1.9201 | 0.132558 | 147 | New | EI30 | Niiskuskindel siseuks | PU9v,EI30 | puit | - | - | no | 1.9201 | no | valge | ootel | ootel | 910000 | 2000 | allalaskuv | -
PU8 | 2.korrus | 2110 | 810 | 1.10 IfcDoorStyle (uks) (IPI ÜBN); Door (ARCHICAD Classification+TK) | 2110 | 5840 | 1.7091 | 0.118507 | 147 | New | - | Niiskuskindel siseuks | PU8 | puit | - | - | no | 1.7091 | no | sinine RAL5003 | ootel | ootel | 810000 | 2000 | - | -
TVU8x12,EI30 | Pööningukorrus | 1210 | 810 | 1.10 IfcDoorStyle (uks) (IPI ÜBN); Door (ARCHICAD Classification+TK); Elements (Archicad Classification) | 1210 | 4040 | 0.9801 | 0.0721035 | 345 | New | EI30 | Niiskuskindel siseuks | TVU8x12,EI30 | puit | - | - | yes | 0.9801 | no | valge | ootel | ootel | 810000 | 1000 | r/v terasest | -
PU7x7 | Pööningukorrus | 710 | 710 | 1.10 IfcDoorStyle (uks) (IPI ÜBN); Door (ARCHICAD Classification+TK) | 710 | 2840 | 0.5041 | 0.0381935 | 163 | New | - | Niiskuskindel siseuks | PU7x7 | puit | - | - | yes | 0.5041 | no | valge | ootel | ootel | 710000 | 710000 | r/v terasest | -

# IfcDoor: Double Door 27 (27)
Type - OperationType: DOUBLE_DOOR_SINGLE_SWING; ParameterTakesPrecedence: no; Sizeable: no
AR_Uks - 340_Soojusläbivus: 0; 360_Ratastooliga: no; 900_Tootja: ootel; 905_Mudel: ootel; 910_Tooteinfo: -; 915_Kasutus-ja-hooldusjuhend: -; 307_Ava-kõrgus: 2000 mm; 345_Päikesekiirgus-tegur: 0; 377_Leng: ootel; 379_Käepide: ootel; 381_Lukuraam: ootel; 382_Südamik: ootel; 383_Vasturaud: ootel; 336_Sissepääs-hoonesse: no
Name | In | OverallHeight (mm) = Height (mm) | OverallWidth (mm) = Width (mm) | Classification | Perimeter (mm) | Area (m2) = 355_Pindala (m2) | Volume (m3) = NetVolume (m3) | Depth (mm) | Renovation Status | FireResistanceRating | 001_Nimetus | 300_Tähis | 310_Materjal | 315_Avanemine | 320_Klaas = 350_Klaaspakett | 325_Helipidavus | 335_Välispiire | 365_Isesulguv = 370_Evakuatsiooniväljapääs | 375_Viimistlus-seest = 376_Viimistlus-väljast | 380_Lukustus | 306_Ava-laius (mm) | 378_Lävepakk | 384_Sulgur
TKU9+9,EI30,dB | 1.korrus | 2110 | 1810 | 1.10 IfcDoorStyle (uks) (IPI ÜBN); Door (ARCHICAD Classification+TK) | 7840 | 3.8191 | 0.0730854 | 140 | New | EI30 | Niiskuskindel siseuks | TKU9+9,EI30,dB | puit | Vasak | - | - | no | no | sinine RAL5003 | ootel | 1000 | allalaskuv | -
TKU9+9,EI30,dB | 1.korrus | 2110 | 1810 | 1.10 IfcDoorStyle (uks) (IPI ÜBN); Door (ARCHICAD Classification+TK) | 7840 | 3.8191 | 0.0730854 | 190 | New | EI30 | Niiskuskindel siseuks | TKU9+9,EI30,dB | puit | Parem | - | - | no | no | sinine RAL5003 | ootel | 1000 | allalaskuv | -
TU7+7,EI30 | 1.korrus | 2110 | 1410 | 1.10 IfcDoorStyle (uks) (IPI ÜBN); Door (ARCHICAD Classification+TK) | 7040 | 2.9751 | 0.132879 | 190 | New | EI30 | Tulekindel terasuks | TU7+7,EI30 | puit | Vasak | - | - | no | no | sinine RAL5003 | ootel | 1000 | r/v terasest | -
SU-XX | 1.korrus | 2060 | 1980 | 1.10 IfcDoorStyle (uks) (IPI ÜBN) | 8080 | 4.0788 | 0.266137 | 360 | Existing |  | Olemasolev siseuks kahepoolne | SU-XX | ootel | Vasak | ootel |  | no | no | RAL 9010 | ootel | 1000 | ootel | ootel
 | 1.korrus | 2100 | 1790 | 1.10 IfcDoorStyle (uks) (IPI ÜBN) | 7780 | 3.759 | 0.111635 | 360 | Existing |  | Olemasolev välisuks kahepoolne |  | ootel | Parem | ootel |  | yes | no | RAL 7022 | ootel | 1000 | ootel | ootel
TU10+5,EI60 | 1.korrus | 2070 | 1490 | 1.10 IfcDoorStyle (uks) (IPI ÜBN); Door (ARCHICAD Classification+TK) | 7120 | 3.0843 | 0.15226 | 400 | New |  | Tulekindel siseuks | TU10+5,EI60 | teras | Vasak | ootel | - | no | yes | sinine RAL5003 | solenoid | 1000 | r/v terasest | meh.sulgur | AR_Uks - 330_Tulepüsivus: EI60
TU10+5,EI120 | 1.korrus | 2070 | 1490 | 1.10 IfcDoorStyle (uks) (IPI ÜBN); Door (ARCHICAD Classification+TK) | 7120 | 3.0843 | 0.15226 | 420 | New | EI120 | Tulekindel siseuks | TU10+5,EI120 | teras | Parem | ootel | - | no | yes | sinine RAL5003 | solenoid | 1000 | r/v terasest | ootel | AR_Uks - 330_Tulepüsivus: EI120
TU10+5,EI120,dB | 1.korrus | 2070 | 1500 | 1.10 IfcDoorStyle (uks) (IPI ÜBN); Door (ARCHICAD Classification+TK) | 7140 | 3.105 | 0.153141 | 400 | New | EI120 | Tulekindel siseuks | TU10+5,EI120,dB | teras | Parem | ootel | 35dB | no | yes | sinine RAL5003 | solenoid | 1000 | r/v terasest | ootel | AR_Uks - 330_Tulepüsivus: EI120
 | 1.korrus | 2080 | 1980 | 1.10 IfcDoorStyle (uks) (IPI ÜBN) | 8120 | 4.1184 | 0.196302 | 360 | Existing |  | Olemasolev siseuks kahepoolne |  | ootel | Parem | ootel |  | no | no | RAL 7022 | ootel | 1000 | ootel | ootel
SU-XX | 1.korrus | 2090 | 1980 | 1.10 IfcDoorStyle (uks) (IPI ÜBN) | 8140 | 4.1382 | 0.286687 | 360 | Existing |  | Olemasolev siseuks kahepoolne | SU-XX | ootel | Parem | ootel |  | no | no | RAL 9010 | ootel | 1000 | ootel | ootel
 | 1.korrus | 2480 | 1500 | 1.10 IfcDoorStyle (uks) (IPI ÜBN) | 7960 | 3.72 | 0.169469 | 250 | Existing |  | Olemasolev siseuks kahepoolne |  | ootel | Parem | ootel |  | no | no | RAL 9010 | ootel | 1000 | ootel | ootel
SU-XX | 1.korrus | 2070 | 2870 | 1.10 IfcDoorStyle (uks) (IPI ÜBN) | 9880 | 5.9409 | 0.401876 | 90 | Existing |  | Olemasolev siseuks kahepoolne | SU-XX | ootel | Vasak | ootel |  | no | no | RAL 9010 | ootel | 2000 | ootel | ootel
SU-XX | 1.korrus | 2100 | 2870 | 1.10 IfcDoorStyle (uks) (IPI ÜBN) | 9940 | 6.027 | 0.407609 | 110 | Existing |  | Olemasolev siseuks kahepoolne | SU-XX | ootel | Vasak | ootel |  | no | no | RAL 9010 | ootel | 2000 | ootel | ootel
SU-XX | 1.korrus | 2100 | 2870 | 1.10 IfcDoorStyle (uks) (IPI ÜBN) | 9940 | 6.027 | 0.407609 | 110 | Existing |  | Olemasolev siseuks kahepoolne | SU-XX | ootel | Parem | ootel |  | no | no | RAL 9010 | ootel | 2000 | ootel | ootel
 | 1.korrus | 2130 | 1510 | 1.10 IfcDoorStyle (uks) (IPI ÜBN) | 7280 | 3.2163 | 0.221277 | 540 | Existing |  | Olemasolev siseuks kahepoolne |  | ootel | Parem | ootel |  | no | no | RAL 9010 | ootel | 1000 | ootel | ootel
 | 1.korrus | 2090 | 1500 | 1.10 IfcDoorStyle (uks) (IPI ÜBN) | 7180 | 3.135 | 0.154551 | 380 | Existing |  | Olemasolev siseuks kahepoolne |  | ootel | Parem | ootel |  | no | no | RAL 9010 | ootel | 1000 | ootel | ootel
SU-XX | 1.korrus | 2300 | 2420 | 1.10 IfcDoorStyle (uks) (IPI ÜBN) | 9440 | 5.566 | 0.367884 | 380 | Existing |  | Olemasolev siseuks kahepoolne | SU-XX | ootel | Vasak | ootel |  | no | no | RAL 9010 | ootel | 2000 | ootel | ootel
PU10+4 | 2.korrus | 2110 | 1410 | 1.10 IfcDoorStyle (uks) (IPI ÜBN); Door (ARCHICAD Classification+TK) | 7040 | 2.9751 | 0.153015 | 147 | New | EI60 | Tulekindel siseuks | PU10+4 | teras | Vasak | - | - | no | yes | sinine RAL5003 | ootel | 1000 | - | ootel
PU6,5+6,5 | 2.korrus | 2110 | 1310 | 1.10 IfcDoorStyle (uks) (IPI ÜBN); Door (ARCHICAD Classification+TK) | 6840 | 2.7641 | 0.124915 | 147 | New | - | Niiskuskindel siseuks | PU6,5+6,5 | puit | Parem | - | - | no | no | sinine RAL5003 | ootel | 1000 | - | -
PU10+5,EI30 | 2.korrus | 2110 | 1510 | 1.10 IfcDoorStyle (uks) (IPI ÜBN); Door (ARCHICAD Classification+TK) | 7240 | 3.1861 | 0.141569 | 147 | New | EI30 | Niiskuskindel siseuks | PU10+5,EI30 | puit | Parem | - | - | no | no | sinine RAL5003 | ootel | 1000 | allalaskuv | -
PKU9+9,dB | 2.korrus | 2110 | 1810 | 1.10 IfcDoorStyle (uks) (IPI ÜBN); Door (ARCHICAD Classification+TK) | 7840 | 3.8191 | 0.0730854 | 147 | New | - | Niiskuskindel siseuks | PKU9+9,dB | puit | Parem | - | - | no | no | sinine RAL5003 | ootel | 1000 | allalaskuv | -
5 x PKU9+9,dB | 2.korrus | 2110 | 1810 | 1.10 IfcDoorStyle (uks) (IPI ÜBN); Door (ARCHICAD Classification+TK) | 7840 | 3.8191 | 0.0730854 | 236 | New | - | Niiskuskindel siseuks | PKU9+9,dB | puit | Vasak | - | - | no | no | sinine RAL5003 | ootel | 1000 | allalaskuv | -
TU10+5,EI30,dB | 2.korrus | 2110 | 1490 | 1.10 IfcDoorStyle (uks) (IPI ÜBN); Door (ARCHICAD Classification+TK) | 7200 | 3.1439 | 0.155064 | 420 | New | EI30 | Tulekindel siseuks | TU10+5,EI30,dB | teras | Vasak | - | 35dB | no | yes | sinine RAL5003 | solenoid | 1000 | allalaskuv | meh.sulgur | AR_Uks - 330_Tulepüsivus: EI30

# IfcDoor: Double Door Asymmetric 27 (6)
Type - OperationType: DOUBLE_DOOR_SINGLE_SWING; ParameterTakesPrecedence: no; Sizeable: no
AR_Uks - 340_Soojusläbivus: 0; 360_Ratastooliga: no; 370_Evakuatsiooniväljapääs: no; 900_Tootja: ootel; 905_Mudel: ootel; 910_Tooteinfo: -; 915_Kasutus-ja-hooldusjuhend: -; 306_Ava-laius: 1000 mm; 345_Päikesekiirgus-tegur: 0; 377_Leng: ootel; 379_Käepide: ootel; 381_Lukuraam: ootel; 382_Südamik: ootel; 383_Vasturaud: ootel; 336_Sissepääs-hoonesse: no
Name | In | OverallHeight (mm) = Height (mm) | OverallWidth (mm) = Width (mm) | Classification | FireResistanceRating | Perimeter (mm) | Area (m2) = 355_Pindala (m2) | Volume (m3) = NetVolume (m3) | Depth (mm) | Renovation Status | 001_Nimetus | 300_Tähis | 310_Materjal | 315_Avanemine | 320_Klaas | 325_Helipidavus | 335_Välispiire | 350_Klaaspakett | 365_Isesulguv | 375_Viimistlus-seest = 376_Viimistlus-väljast | 380_Lukustus | 307_Ava-kõrgus (mm) | 378_Lävepakk | 384_Sulgur
TKU10+5,EI30,dB | 1.korrus | 2110 | 1510 | 1.10 IfcDoorStyle (uks) (IPI ÜBN); Door (ARCHICAD Classification+TK) | EI30 | 7240 | 3.1861 | 0.0682794 | 140 | New | Niiskuskindel siseuks | TKU10+5,EI30,dB | puit | Parem | - | - | no | - | no | sinine RAL5003 | ootel | 2000 | allalaskuv | -
 | 1.korrus | 2300 | 1505 | 1.10 IfcDoorStyle (uks) (IPI ÜBN) |  | 7610 | 3.4615 | 0.24413 | 410 | Existing | Olemasolev välisuks kahepoolne |  | ootel | Parem | ootel |  | yes | ootel | no | RAL 9007 | ootel | 2000 | ootel | ootel
 | 1.korrus | 2040 | 1180 | 1.10 IfcDoorStyle (uks) (IPI ÜBN) |  | 6440 | 2.4072 | 0.172905 | 310 | Existing | Olemasolev välisuks kahepoolne |  | ootel | Vasak | ootel |  | yes | ootel | no | RAL 9007 | ootel | 2000 | ootel | ootel
TU9+3,EI30,dB | 1.korrus | 2060 | 1180 | 1.10 IfcDoorStyle (uks) (IPI ÜBN); Door (ARCHICAD Classification+TK) | EI30 | 6480 | 2.4308 | 0.174567 | 380 | New | Tulekindel siseuks | TU9+3,EI30,dB | teras | Vasak | - | 35dB | no | ootel | yes | sinine RAL5003 | solenoid | 2000 | r/v terasest | meh.sulgur | AR_Uks - 330_Tulepüsivus: EI30
TVU10+6x19,EI30 | Pööningukorrus | 1910 | 1610 | 1.10 IfcDoorStyle (uks) (IPI ÜBN); Door (ARCHICAD Classification+TK); Elements (Archicad Classification) | EI30 | 7040 | 3.0751 | 0.136379 | 345 | New | Niiskuskindel siseuks | TVU10+6x19,EI30 | puit | Vasak | - | - | yes | - | no | RAL9017 must | ootel | 1000 | r/v terasest | -
TVU10+6x18,EI30 | Pööningukorrus | 1810 | 1610 | 1.10 IfcDoorStyle (uks) (IPI ÜBN); Door (ARCHICAD Classification+TK) | EI30 | 6840 | 2.9141 | 0.129439 | 437 | New | Niiskuskindel siseuks | TVU10+6x18,EI30 | puit | Parem | - | - | yes | - | no | RAL9017 must | ootel | 1000 | r/v terasest | -

# IfcDoor: Double Door with Sidelight 27, AVU5+10+5,EI30
In: 2.korrus
Type - OperationType: USERDEFINED; ParameterTakesPrecedence: no; Sizeable: no
OverallHeight: 2310 mm; OverallWidth: 2140 mm; Classification: 1.10 IfcDoorStyle (uks) (IPI ÜBN); Door (ARCHICAD Classification+TK)
BaseQuantities - Height: 2310 mm; Width: 2140 mm; Perimeter: 8900 mm; Area: 4.9434 m2; Volume: 0.0870825 m3; Depth: 437 mm; NetVolume: 0.0870825 m3
AC_Pset_RenovationAndPhasing - Renovation Status: New
Pset_FireRatingProperties - FireResistanceRating: EI30
AR_Uks - 001_Nimetus: Al.profiil välisuks; 300_Tähis: AVU5+10+5,EI30; 310_Materjal: al.profiil; 315_Avanemine: Parem; 320_Klaas: -; 325_Helipidavus: -; 335_Välispiire: yes; 340_Soojusläbivus: 0; 350_Klaaspakett: -; 355_Pindala: 4.876 m2; 360_Ratastooliga: no; 365_Isesulguv: no; 370_Evakuatsiooniväljapääs: no; 375_Viimistlus-seest: RAL9017 must; 376_Viimistlus-väljast: RAL9017 must; 380_Lukustus: ootel; 900_Tootja: ootel; 905_Mudel: ootel; 910_Tooteinfo: -; 915_Kasutus-ja-hooldusjuhend: -; 306_Ava-laius: 2000 mm; 307_Ava-kõrgus: 2000 mm; 345_Päikesekiirgus-tegur: 0; 377_Leng: ootel; 378_Lävepakk: r/v terasest; 379_Käepide: ootel; 381_Lukuraam: ootel; 382_Südamik: ootel; 383_Vasturaud: ootel; 384_Sulgur: -; 336_Sissepääs-hoonesse: no

# IfcDoor: Double Door with Transom 27
In: 1.korrus
Type - OperationType: DOUBLE_DOOR_SINGLE_SWING; ParameterTakesPrecedence: no; Sizeable: no
OverallHeight: 2560 mm; OverallWidth: 2520 mm; Classification: 1.10 IfcDoorStyle (uks) (IPI ÜBN)
AR_Uks - 001_Nimetus: Olemasolev välisuks kahepoolne; 310_Materjal: ootel; 315_Avanemine: Parem; 320_Klaas: ootel; 335_Välispiire: yes; 340_Soojusläbivus: 0; 350_Klaaspakett: ootel; 355_Pindala: 6.4512 m2; 360_Ratastooliga: no; 365_Isesulguv: no; 370_Evakuatsiooniväljapääs: no; 375_Viimistlus-seest: RAL 9007; 376_Viimistlus-väljast: RAL 9007; 380_Lukustus: ootel; 900_Tootja: ootel; 905_Mudel: ootel; 910_Tooteinfo: -; 915_Kasutus-ja-hooldusjuhend: -; 306_Ava-laius: 2000 mm; 307_Ava-kõrgus: 2000 mm; 345_Päikesekiirgus-tegur: 0; 377_Leng: ootel; 378_Lävepakk: ootel; 379_Käepide: ootel; 381_Lukuraam: ootel; 382_Südamik: ootel; 383_Vasturaud: ootel; 384_Sulgur: ootel; 336_Sissepääs-hoonesse: no
AC_Pset_RenovationAndPhasing - Renovation Status: Existing
BaseQuantities - Height: 2560 mm; Width: 2520 mm; Perimeter: 10160 mm; Area: 6.4512 m2; Volume: 0.245546 m3; Depth: 100 mm; NetVolume: 0.245546 m3

# IfcDoor: Exterior Sliding Door 27, SU-XX
In: 1.korrus
Type - OperationType: SLIDING_TO_LEFT; ParameterTakesPrecedence: no; Sizeable: no
OverallHeight: 2390 mm; OverallWidth: 2400 mm; Classification: 1.10 IfcDoorStyle (uks) (IPI ÜBN)
AR_Uks - 001_Nimetus: Siseuks ühepoolne; 300_Tähis: SU-XX; 310_Materjal: ootel; 315_Avanemine: Parem; 320_Klaas: ootel; 335_Välispiire: no; 340_Soojusläbivus: 0; 350_Klaaspakett: ootel; 355_Pindala: 5.736 m2; 360_Ratastooliga: no; 365_Isesulguv: no; 370_Evakuatsiooniväljapääs: no; 375_Viimistlus-seest: RAL 9010; 376_Viimistlus-väljast: RAL 9010; 380_Lukustus: ootel; 900_Tootja: ootel; 905_Mudel: ootel; 910_Tooteinfo: -; 915_Kasutus-ja-hooldusjuhend: -; 306_Ava-laius: 2000 mm; 307_Ava-kõrgus: 2000 mm; 345_Päikesekiirgus-tegur: 0; 377_Leng: ootel; 378_Lävepakk: ootel; 379_Käepide: ootel; 381_Lukuraam: ootel; 382_Südamik: ootel; 383_Vasturaud: ootel; 384_Sulgur: ootel; 336_Sissepääs-hoonesse: no
AC_Pset_RenovationAndPhasing - Renovation Status: Existing
BaseQuantities - Height: 2390 mm; Width: 2400 mm; Perimeter: 9580 mm; Area: 5.736 m2; Volume: 0.213715 m3; Depth: 190 mm; NetVolume: 0.213715 m3

# IfcDoor: GENEERILINE - EHITUSTOODE 50 (17)
Type - ParameterTakesPrecedence: no; Sizeable: no
Classification: 1.10 IfcDoorStyle (uks) (IPI ÜBN); Material: GENEERILINE - EHITUSTOODE
BaseQuantities - Height: 50 mm
AC_Pset_RenovationAndPhasing - Renovation Status: New
AR_Uks - 001_Nimetus: Kipsiluuk; 310_Materjal: ootel; 320_Klaas: ootel; 335_Välispiire: no; 340_Soojusläbivus: 0; 350_Klaaspakett: ootel; 360_Ratastooliga: no; 365_Isesulguv: no; 370_Evakuatsiooniväljapääs: no; 380_Lukustus: ootel; 900_Tootja: ootel; 905_Mudel: ootel; 910_Tooteinfo: -; 915_Kasutus-ja-hooldusjuhend: -; 307_Ava-kõrgus: 50000 mm; 345_Päikesekiirgus-tegur: 0; 377_Leng: ootel; 378_Lävepakk: ootel; 379_Käepide: ootel; 381_Lukuraam: ootel; 382_Südamik: ootel; 383_Vasturaud: ootel; 384_Sulgur: ootel; 336_Sissepääs-hoonesse: no
Name | In | Perimeter (mm) | Area (m2) | NetVolume (m3) | 300_Tähis
10 x PL1 | 1.korrus | 1200 | 0.09 | 0.0045 | PL1
4 x PL2 | 1.korrus | 2400 | 0.36 | 0.018 | PL2
2 x PL1 | 2.korrus | 1200 | 0.09 | 0.0045 | PL1
PL1 | 2.korrus | 1200.8 | 0.09012 | 0.004506 | PL1

# IfcDoor: Overhead Garage Door 27 (13)
In: 1.korrus
Type - OperationType: ROLLINGUP; ParameterTakesPrecedence: no; Sizeable: no
Classification: 1.10 IfcDoorStyle (uks) (IPI ÜBN)
AR_Uks - 001_Nimetus: Olemasolev tõstuks; 310_Materjal: ootel; 320_Klaas: ootel; 335_Välispiire: yes; 340_Soojusläbivus: 0; 350_Klaaspakett: ootel; 360_Ratastooliga: no; 365_Isesulguv: no; 370_Evakuatsiooniväljapääs: no; 380_Lukustus: ootel; 900_Tootja: ootel; 905_Mudel: ootel; 910_Tooteinfo: -; 915_Kasutus-ja-hooldusjuhend: -; 345_Päikesekiirgus-tegur: 0; 377_Leng: ootel; 378_Lävepakk: ootel; 379_Käepide: ootel; 381_Lukuraam: ootel; 382_Südamik: ootel; 383_Vasturaud: ootel; 384_Sulgur: ootel; 336_Sissepääs-hoonesse: no
AC_Pset_RenovationAndPhasing - Renovation Status: Existing
Name | OverallHeight (mm) | OverallWidth (mm) = Width (mm) | 355_Pindala (m2) | 375_Viimistlus-seest = 376_Viimistlus-väljast | 306_Ava-laius (mm) | 307_Ava-kõrgus (mm) | Height (mm) | Perimeter (mm) | Area (m2) | Volume (m3) = NetVolume (m3) | Depth (mm)
 | 2400 | 2300 | 5.52 | Plastic - Laminate | 2000 | 2000 | 2400 | 9400 | 5.52 | 0.227225 | 420
2 x  | 2210 | 2960 | 6.5416 | RAL 7037 | 2000 | 2000 | 2080 | 10080 | 6.1568 | 0.272317 | 100
 | 4340 | 3810 | 16.5354 | RAL 7037 | 3000 | 4000 | 4080 | 15780 | 15.5448 | 0.670858 | 80
 | 4280 | 4600 | 19.688 | RAL 7037 | 4000 | 4000 | 4010 | 17220 | 18.446 | 0.793715 | 80
 | 3520 | 3480 | 12.2496 | RAL 7037 | 3000 | 3000 | 3520 | 14000 | 12.2496 | 0.476914 | 420
 | 3520 | 3500 | 12.32 | RAL 7037 | 3000 | 3000 | 3520 | 14040 | 12.32 | 0.47963 | 420
 | 3580 | 3480 | 12.4584 | RAL 7037 | 3000 | 3000 | 3580 | 14120 | 12.4584 | 0.478677 | 420
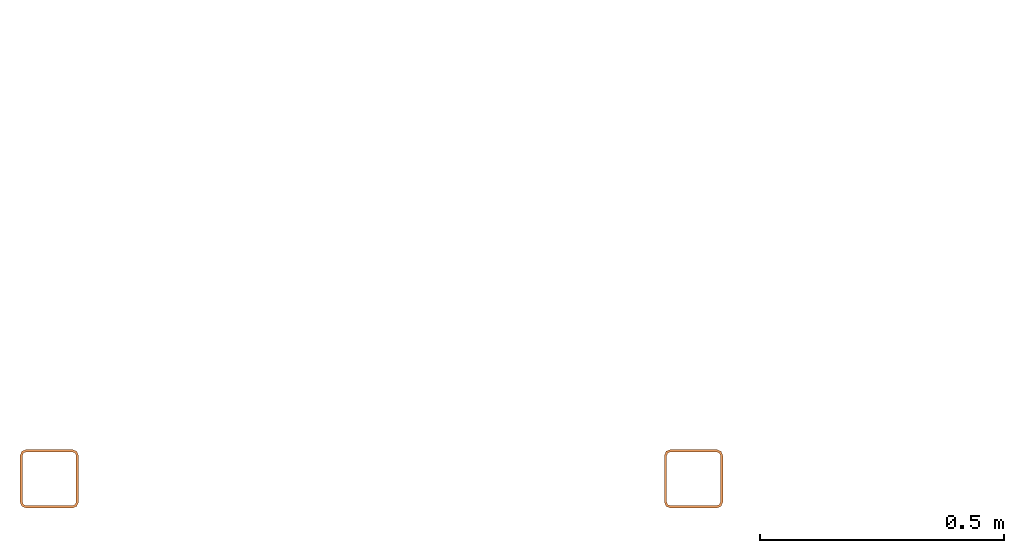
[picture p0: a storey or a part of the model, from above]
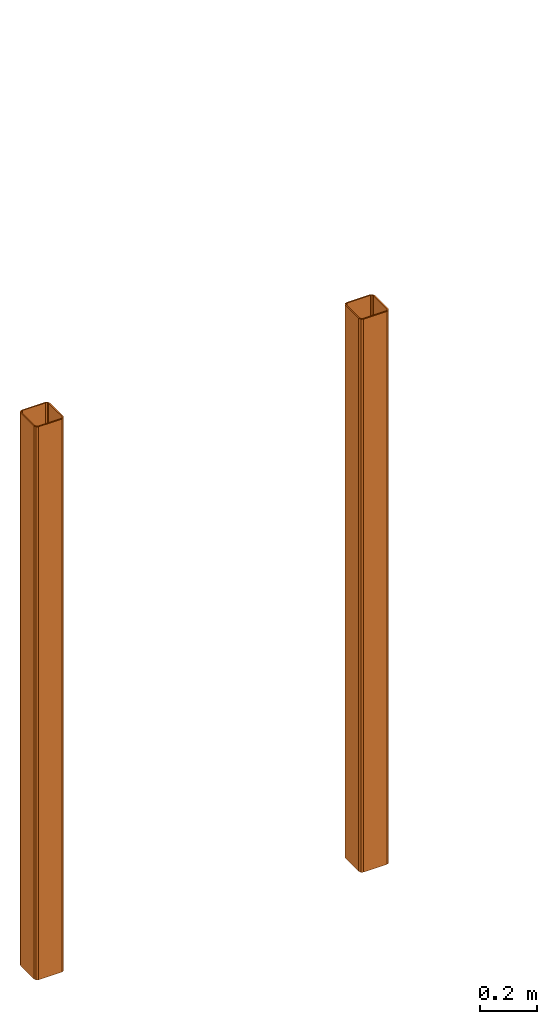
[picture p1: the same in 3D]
Properties of the parts of a building model (IFC2X3), part 4 of 7

# IfcDoor: Overhead Garage Door 27 (13)
Name | OverallHeight (mm) | OverallWidth (mm) = Width (mm) | 355_Pindala (m2) | 375_Viimistlus-seest = 376_Viimistlus-väljast | 306_Ava-laius (mm) | 307_Ava-kõrgus (mm) | Height (mm) | Perimeter (mm) | Area (m2) | Volume (m3) = NetVolume (m3) | Depth (mm)
 | 3580 | 3560 | 12.7448 | RAL 7037 | 3000 | 3000 | 3580 | 14280 | 12.7448 | 0.489685 | 420
 | 4000 | 3600 | 14.4 | Plastic - Laminate | 3000 | 4000 | 4000 | 15200 | 14.4 | 0.558948 | 420
 | 3100 | 3560 | 11.036 | RAL 7037 | 3000 | 3000 | 3490 | 14100 | 12.4244 | 0.422667 | 420
 | 3100 | 3625 | 11.2375 | RAL 7037 | 3000 | 3000 | 3490 | 14230 | 12.6513 | 0.430523 | 420
 | 3100 | 3610 | 11.191 | RAL 7037 | 3000 | 3000 | 3490 | 14200 | 12.5989 | 0.42871 | 420

# IfcDoor: Vertical Sliding Garage Door 27
In: 1.korrus
Type - OperationType: ROLLINGUP; ParameterTakesPrecedence: no; Sizeable: no
OverallHeight: 2480 mm; OverallWidth: 2500 mm; Classification: 1.10 IfcDoorStyle (uks) (IPI ÜBN)
AR_Uks - 001_Nimetus: Olemasolev tõstuks; 310_Materjal: ootel; 320_Klaas: ootel; 335_Välispiire: yes; 340_Soojusläbivus: 0; 350_Klaaspakett: ootel; 355_Pindala: 6.2 m2; 360_Ratastooliga: no; 365_Isesulguv: no; 370_Evakuatsiooniväljapääs: no; 375_Viimistlus-seest: RAL 7000; 376_Viimistlus-väljast: RAL 7000; 380_Lukustus: ootel; 900_Tootja: ootel; 905_Mudel: ootel; 910_Tooteinfo: -; 915_Kasutus-ja-hooldusjuhend: -; 306_Ava-laius: 2000 mm; 307_Ava-kõrgus: 2000 mm; 345_Päikesekiirgus-tegur: 0; 377_Leng: ootel; 378_Lävepakk: ootel; 379_Käepide: ootel; 381_Lukuraam: ootel; 382_Südamik: ootel; 383_Vasturaud: ootel; 384_Sulgur: ootel; 336_Sissepääs-hoonesse: no
AC_Pset_RenovationAndPhasing - Renovation Status: Existing
BaseQuantities - Height: 2480 mm; Width: 2500 mm; Perimeter: 9960 mm; Area: 6.2 m2; Volume: 0.3192 m3; Depth: 550 mm; NetVolume: 0.3192 m3

# IfcFlowTerminal: Basin 27 (14)
Type - AR_Santehnika - 001_Nimetus: Valamu; 002_Tähis: V2; 455_Eriomadused: ootel; 900_Tootja: ootel; 905_Mudel: ootel; 910_Tooteinfo: -; 915_Kasutus-ja_hooldusjuhend: -
Classification: 1.18 IfcSanitaryTerminalType (santehnika) (IPI ÜBN)
AC_Pset_RenovationAndPhasing - Renovation Status: New
Pset_DistributionFlowElementCommon - Reference: V2
AR_Santehnika - 915_Kasutus-ja-hooldusjuhend: -
KVJ_Õhukanal - 100_Rõhukadu(Pa): 0; 105_Rõhk(Pa): 0; 110_Vooluhulk(l/s): 1600; 115_Voolukiirus(m/s): 1.111; 150_Kanali_suurus: 1200 mm
Name | In
9 x V2 | 1.korrus
5 x V2 | 2.korrus

# IfcFlowTerminal: Basin 27, V1
In: 1.korrus
Type - AR_Santehnika - 001_Nimetus: Valamu, inva; 002_Tähis: V1; 455_Eriomadused: ootel; 900_Tootja: Idealstandard; 905_Mudel: Connect Freedom E5482; 910_Tooteinfo: 555x600mm, valge portselan; 915_Kasutus-ja_hooldusjuhend: -
Classification: 1.18 IfcSanitaryTerminalType (santehnika) (IPI ÜBN)
AC_Pset_RenovationAndPhasing - Renovation Status: New
AR_Santehnika - 915_Kasutus-ja-hooldusjuhend: -
KVJ_Õhukanal - 100_Rõhukadu(Pa): 0; 105_Rõhk(Pa): 0; 110_Vooluhulk(l/s): 1600; 115_Voolukiirus(m/s): 1.111; 150_Kanali_suurus: 1200 mm
Pset_DistributionFlowElementCommon - Reference: V1

# IfcFlowTerminal: Mop Sink 27, V3
In: Pööningukorrus
Type - AR_Santehnika - 001_Nimetus: Rv valamu; 002_Tähis: V3; 455_Eriomadused: ootel; 900_Tootja: ootel; 905_Mudel: ootel; 910_Tooteinfo: -; 915_Kasutus-ja_hooldusjuhend: -
Classification: 1.18 IfcSanitaryTerminalType (santehnika) (IPI ÜBN)
KVJ_Õhukanal - 100_Rõhukadu(Pa): 0; 105_Rõhk(Pa): 0; 110_Vooluhulk(l/s): 1600; 115_Voolukiirus(m/s): 1.111; 150_Kanali_suurus: 1200 mm
AR_Santehnika - 915_Kasutus-ja-hooldusjuhend: -
Pset_DistributionFlowElementCommon - Reference: V3
AC_Pset_RenovationAndPhasing - Renovation Status: New

# IfcFlowTerminal: Shower Kit 27 (9)
Type - AR_Santehnika - 001_Nimetus: Dush; 002_Tähis: D1; 455_Eriomadused: ootel; 900_Tootja: ootel; 905_Mudel: ootel; 910_Tooteinfo: -; 915_Kasutus-ja_hooldusjuhend: -
Classification: 1.18 IfcSanitaryTerminalType (santehnika) (IPI ÜBN)
AC_Pset_RenovationAndPhasing - Renovation Status: New
Pset_DistributionFlowElementCommon - Reference: D1
AR_Santehnika - 915_Kasutus-ja-hooldusjuhend: -
KVJ_Õhukanal - 100_Rõhukadu(Pa): 0; 105_Rõhk(Pa): 0; 110_Vooluhulk(l/s): 1600; 115_Voolukiirus(m/s): 1.111; 150_Kanali_suurus: 1200 mm
Name | In
4 x D1 | 1.korrus
5 x D1 | 2.korrus

# IfcFlowTerminal: Sink General 27 (7)
Type - AR_Santehnika - 001_Nimetus: RV valamu; 002_Tähis: V3; 455_Eriomadused: ootel; 900_Tootja: Franke; 905_Mudel: Kalla; 910_Tooteinfo: Rvt, 460x600mm; 915_Kasutus-ja_hooldusjuhend: -
Classification: 1.18 IfcSanitaryTerminalType (santehnika) (IPI ÜBN)
AC_Pset_RenovationAndPhasing - Renovation Status: New
Pset_DistributionFlowElementCommon - Reference: V3
AR_Santehnika - 915_Kasutus-ja-hooldusjuhend: -
KVJ_Õhukanal - 100_Rõhukadu(Pa): 0; 105_Rõhk(Pa): 0; 110_Vooluhulk(l/s): 1600; 115_Voolukiirus(m/s): 1.111; 150_Kanali_suurus: 1200 mm
Name | In
6 x V3 | 1.korrus
V3 | 2.korrus

# IfcFlowTerminal: Sink General 27, V4
In: 1.korrus
Type - AR_Santehnika - 001_Nimetus: Valamu; 002_Tähis: V4; 455_Eriomadused: ootel; 900_Tootja: ootel; 905_Mudel: ootel; 910_Tooteinfo: -; 915_Kasutus-ja_hooldusjuhend: -
Classification: 1.18 IfcSanitaryTerminalType (santehnika) (IPI ÜBN)
Pset_DistributionFlowElementCommon - Reference: V4
KVJ_Õhukanal - 100_Rõhukadu(Pa): 0; 105_Rõhk(Pa): 0; 110_Vooluhulk(l/s): 1600; 115_Voolukiirus(m/s): 1.111; 150_Kanali_suurus: 1200 mm
AC_Pset_RenovationAndPhasing - Renovation Status: New
AR_Santehnika - 915_Kasutus-ja-hooldusjuhend: -

# IfcFlowTerminal: Sink General 27 (2)
In: 1.korrus
Type - AR_Santehnika - 001_Nimetus: ol.olev valamu; 002_Tähis: rv valamu; 455_Eriomadused: ootel; 900_Tootja: ootel; 905_Mudel: ootel; 910_Tooteinfo: -; 915_Kasutus-ja_hooldusjuhend: -
Classification: 1.18 IfcSanitaryTerminalType (santehnika) (IPI ÜBN)
KVJ_Õhukanal - 100_Rõhukadu(Pa): 0; 105_Rõhk(Pa): 0; 110_Vooluhulk(l/s): 1600; 115_Voolukiirus(m/s): 1.111; 150_Kanali_suurus: 1200 mm
AR_Santehnika - 915_Kasutus-ja-hooldusjuhend: -
Pset_DistributionFlowElementCommon - Reference: rv valamu
AC_Pset_RenovationAndPhasing - Renovation Status: Existing

# IfcFlowTerminal: WC 27 (14)
Type - AR_Santehnika - 001_Nimetus: WC pott, seinakinnitus; 002_Tähis: WC1; 455_Eriomadused: ootel; 900_Tootja: ootel; 905_Mudel: ootel; 910_Tooteinfo: -; 915_Kasutus-ja_hooldusjuhend: -
Classification: 1.18 IfcSanitaryTerminalType (santehnika) (IPI ÜBN)
AC_Pset_RenovationAndPhasing - Renovation Status: New
Pset_DistributionFlowElementCommon - Reference: WC1
KVJ_Õhukanal - 100_Rõhukadu(Pa): 0; 105_Rõhk(Pa): 0; 110_Vooluhulk(l/s): 1600; 115_Voolukiirus(m/s): 1.111; 150_Kanali_suurus: 1200 mm
AR_Santehnika - 915_Kasutus-ja-hooldusjuhend: -
Name | In
9 x WC1 | 1.korrus
5 x WC1 | 2.korrus

# IfcFlowTerminal: WC 27, WC2
In: 1.korrus
Type - AR_Santehnika - 001_Nimetus: inva WC pott, seinakinnitus; 002_Tähis: WC2; 455_Eriomadused: ootel; 900_Tootja: ootel; 905_Mudel: ootel; 910_Tooteinfo: -; 915_Kasutus-ja_hooldusjuhend: -
Classification: 1.18 IfcSanitaryTerminalType (santehnika) (IPI ÜBN)
KVJ_Õhukanal - 100_Rõhukadu(Pa): 0; 105_Rõhk(Pa): 0; 110_Vooluhulk(l/s): 1600; 115_Voolukiirus(m/s): 1.111; 150_Kanali_suurus: 1200 mm
AR_Santehnika - 915_Kasutus-ja-hooldusjuhend: -
Pset_DistributionFlowElementCommon - Reference: WC2
AC_Pset_RenovationAndPhasing - Renovation Status: New

# IfcFlowTerminal: Wall Mounted Tap 27, Kastmiskraan
In: 1.korrus
Type - AR_Santehnika - 001_Nimetus: Kastmiskraan; 002_Tähis: Kastmiskraan; 455_Eriomadused: ootel; 900_Tootja: ootel; 905_Mudel: ootel; 910_Tooteinfo: -; 915_Kasutus-ja_hooldusjuhend: -
Classification: 1.18 IfcSanitaryTerminalType (santehnika) (IPI ÜBN)
KVJ_Õhukanal - 100_Rõhukadu(Pa): 0; 105_Rõhk(Pa): 0; 110_Vooluhulk(l/s): 1600; 115_Voolukiirus(m/s): 1.111; 150_Kanali_suurus: 1200 mm
AR_Santehnika - 915_Kasutus-ja-hooldusjuhend: -
Pset_DistributionFlowElementCommon - Reference: Kastmiskraan
AC_Pset_RenovationAndPhasing - Renovation Status: New

# IfcFlowTerminal: Wall Mounted Tap 27 (7)
In: 1.korrus
Type - AR_Santehnika - 001_Nimetus: Segisti, seinapealne; 002_Tähis: V; 455_Eriomadused: ootel; 900_Tootja: Franke; 905_Mudel: Kalla; 910_Tooteinfo: Rvt, 460x600mm; 915_Kasutus-ja_hooldusjuhend: -
Classification: 1.18 IfcSanitaryTerminalType (santehnika) (IPI ÜBN)
KVJ_Õhukanal - 100_Rõhukadu(Pa): 0; 105_Rõhk(Pa): 0; 110_Vooluhulk(l/s): 1600; 115_Voolukiirus(m/s): 1.111; 150_Kanali_suurus: 1200 mm
AR_Santehnika - 915_Kasutus-ja-hooldusjuhend: -
Pset_DistributionFlowElementCommon - Reference: V
AC_Pset_RenovationAndPhasing - Renovation Status: New

# IfcFurnishingElement: Air Space 2100 (3)
In: 1.korrus
Classification: 1.11 IfcFurnitureType (mööbel) (IPI ÜBN); Material: Air Space
AR_Mööbel - 001_Nimetus: Hoiukapid; 900_Tootja: eritellimus
AC_Pset_RenovationAndPhasing - Renovation Status: New
Name | Reference = 002_Tähis
LO3 | LO3
LO2 | LO2
LO1 | LO1

# IfcFurnishingElement: Bar Stool 27 (10)
In: 2.korrus
Classification: 1.11 IfcFurnitureType (mööbel) (IPI ÜBN)
AR_Mööbel - 001_Nimetus: Tool, õp.toa söögilaua ümber; 002_Tähis: T7; 900_Tootja: Intera; 905_Mudel: Hale
AC_Pset_RenovationAndPhasing - Renovation Status: New
Pset_QuantityTakeOff - Reference: T7

# IfcFurnishingElement: Base Cabinet Block 27 (10)
Classification: 1.11 IfcFurnitureType (mööbel) (IPI ÜBN)
AC_Pset_RenovationAndPhasing - Renovation Status: New
AR_Mööbel - 900_Tootja: eritellimus
Name | In | Reference = 002_Tähis | 001_Nimetus | 905_Mudel
KM-2 | 1.korrus | KM-2 | Köögimööbel, fuajees
3 x KM-2 | 1.korrus | KM-2 | Köögimööbel | ootel
6 x KM-1 | 2.korrus | KM-1 | Köögimööbel | ootel

# IfcFurnishingElement: Bench 27 (34)
Classification: 1.11 IfcFurnitureType (mööbel) (IPI ÜBN)
AC_Pset_RenovationAndPhasing - Renovation Status: New
Name | In | 001_Nimetus | 002_Tähis = Reference | 900_Tootja | 905_Mudel
22 x PI1 | 1.korrus | Pink nagidega | PI1 | DUOsport | Ühepoolne pink nagidega
2 x PI1.1 | 1.korrus | Pink nagidega | PI1.1 | DUOsport | Ühepoolne pink nagidega
GK3 | 1.korrus | Pink | GK3 | ootel | ootel
9 x GK3 | 2.korrus | Pink | GK3 | ootel | ootel

# IfcFurnishingElement: Bookshelf 01 27 (12)
In: 2.korrus
Classification: 1.11 IfcFurnitureType (mööbel) (IPI ÜBN)
AR_Mööbel - 001_Nimetus: Bürookapp; 002_Tähis: K1; 900_Tootja: Standard; 905_Mudel: Serie SE2532
Pset_QuantityTakeOff - Reference: K1
AC_Pset_RenovationAndPhasing - Renovation Status: New

# IfcFurnishingElement: Bookshelf 02 27 (10)
Classification: 1.11 IfcFurnitureType (mööbel) (IPI ÜBN)
KVJ_Õhukanal - 100_Rõhukadu(Pa): 0; 105_Rõhk(Pa): 0; 110_Vooluhulk(l/s): 1600; 115_Voolukiirus(m/s): 1.111; 150_Kanali_suurus: 1200 mm
AR_Mööbel - 001_Nimetus: Moodulriiul; 002_Tähis: R49; 900_Tootja: Storeit; 905_Mudel: Super 1-2-3
Pset_QuantityTakeOff - Reference: R49
AC_Pset_RenovationAndPhasing - Renovation Status: New
Name | In
5 x R49 | 1.korrus
5 x R49 | 2.korrus

# IfcFurnishingElement: Chest of Drawers 27 (2)
In: 1.korrus
Classification: 1.11 IfcFurnitureType (mööbel) (IPI ÜBN)
AR_Mööbel - 001_Nimetus: Hüdraulika stend; 002_Tähis: SEH; 900_Tootja: FESTO; 905_Mudel: Hüdraulika stend TP 511
AC_Pset_RenovationAndPhasing - Renovation Status: New
Pset_QuantityTakeOff - Reference: SEH

# IfcFurnishingElement: Coffee Table 04 27, DL1
In: 2.korrus
Classification: 1.11 IfcFurnitureType (mööbel) (IPI ÜBN)
AR_Mööbel - 001_Nimetus: Diivanilaud; 002_Tähis: DL1; 900_Tootja: Pedrali; 905_Mudel: Buddy
Pset_QuantityTakeOff - Reference: DL1
AC_Pset_RenovationAndPhasing - Renovation Status: New

# IfcFurnishingElement: Composite Chair 02 27 (10)
In: 2.korrus
Classification: 1.11 IfcFurnitureType (mööbel) (IPI ÜBN)
AR_Mööbel - 001_Nimetus: Tool, kabinettide klienditool; 002_Tähis: T8; 900_Tootja: Profim; 905_Mudel: Fan 10R
Pset_QuantityTakeOff - Reference: T8
AC_Pset_RenovationAndPhasing - Renovation Status: New

# IfcFurnishingElement: Copier 27, printer
In: 2.korrus
Classification: 1.11 IfcFurnitureType (mööbel) (IPI ÜBN)
AR_Mööbel - 001_Nimetus: printer; 002_Tähis: printer; 900_Tootja: ootel; 905_Mudel: ootel
Pset_QuantityTakeOff - Reference: printer
AC_Pset_RenovationAndPhasing - Renovation Status: New

# IfcFurnishingElement: Cube 27 (37)
Classification: 1.11 IfcFurnitureType (mööbel) (IPI ÜBN)
AC_Pset_RenovationAndPhasing - Renovation Status: New
Name | In | 001_Nimetus | 002_Tähis = Reference | 900_Tootja | 905_Mudel
6 x x | 1.korrus | abikeha | x | ootel | ootel
14 x TP1 | 1.korrus | tisleripink | TP1 | ?? | ??
2 x STL | 2.korrus | Tuulikulabade stend | STL | Festo | Hüdrauliline stend 46124-1
15 x x | 2.korrus | abikeha | x | ootel | ootel

# IfcFurnishingElement: Cupboard 27, KK
In: 1.korrus
Classification: 1.11 IfcFurnitureType (mööbel) (IPI ÜBN)
AR_Mööbel - 001_Nimetus: Kemikaalikapp; 002_Tähis: KK; 900_Tootja: AJ Tooted; 905_Mudel: Formula, art.nr. 755203
Pset_QuantityTakeOff - Reference: KK
AC_Pset_RenovationAndPhasing - Renovation Status: New

# IfcFurnishingElement: GENEERILINE - EHITUSTOODE (6)
In: 1.korrus
Classification: 1.11 IfcFurnitureType (mööbel) (IPI ÜBN); Material: GENEERILINE - EHITUSTOODE
AR_Mööbel - 001_Nimetus: Plastiktool; 002_Tähis: T6; 900_Tootja: Keha3; 905_Mudel: Peatakana
Pset_QuantityTakeOff - Reference: T6
AC_Pset_RenovationAndPhasing - Renovation Status: New

# IfcFurnishingElement: GENEERILINE - KONSTRUKTRIOON (6)
In: 2.korrus
Classification: 1.11 IfcFurnitureType (mööbel) (IPI ÜBN); Material: GENEERILINE - KONSTRUKTRIOON
AR_Mööbel - 001_Nimetus: Istemoodul; 002_Tähis: IM1; 900_Tootja: eritellimus; 905_Mudel: -
Pset_QuantityTakeOff - Reference: IM1
AC_Pset_RenovationAndPhasing - Renovation Status: New

# IfcFurnishingElement: GENEERILINE - KONSTRUKTRIOON 30 (26)
In: 2.korrus
Classification: 1.11 IfcFurnitureType (mööbel) (IPI ÜBN); Material: GENEERILINE - KONSTRUKTRIOON
AC_Pset_RenovationAndPhasing - Renovation Status: New
Name | 001_Nimetus | 002_Tähis = Reference | 900_Tootja | 905_Mudel
3 x TL3 | Trapetslaud | TL3 | KE Mööbel | 2-kohaline Mila trapetslaud B9008-05-08-SH31-Z-SR-PO
20 x TL4 | Moodullaud | TL4 | A&T Trading | Octa 1-kohaline
L2 | Õp.toa söögilaud | L2 | eritellimusmööbel
KM-1 köögiriiul | Köögiriiul | KM-1 köögiriiul | eritellimus | -
KM-3 | Töötasapind | KM-3 | ootel | ootel

# IfcFurnishingElement: GENEERILINE - KONSTRUKTRIOON 50, tasapind
In: 1.korrus
Classification: 1.11 IfcFurnitureType (mööbel) (IPI ÜBN); Material: GENEERILINE - KONSTRUKTRIOON
AR_Mööbel - 001_Nimetus: tasapind; 002_Tähis: tasapind; 900_Tootja: ootel; 905_Mudel: ootel
Pset_QuantityTakeOff - Reference: tasapind
AC_Pset_RenovationAndPhasing - Renovation Status: New

# IfcFurnishingElement: GENEERILINE - SISEMINE VOODER 30 (2)
In: 1.korrus
Classification: 1.11 IfcFurnitureType (mööbel) (IPI ÜBN); Material: GENEERILINE - SISEMINE VOODER
AR_Mööbel - 001_Nimetus: Inva-WC poti käetoed; 002_Tähis: KT1; 900_Tootja: Normbau; 905_Mudel: 7447030091
Pset_QuantityTakeOff - Reference: KT1
AC_Pset_RenovationAndPhasing - Renovation Status: New

# IfcFurnishingElement: Lockers 27 (10)
Classification: 1.11 IfcFurnitureType (mööbel) (IPI ÜBN)
AR_Mööbel - 001_Nimetus: Garderoobikapp, 3 moodulit, pingiga; 900_Tootja: Laoekspert; 905_Mudel: 50-GKPP3/400
AC_Pset_RenovationAndPhasing - Renovation Status: New
Name | In | 002_Tähis = Reference
GK1 | 1.korrus | GK1
9 x GK3 | 2.korrus | GK3

# IfcFurnishingElement: Office Cabinet 27 (9)
In: 2.korrus
Classification: 1.11 IfcFurnitureType (mööbel) (IPI ÜBN)
AC_Pset_RenovationAndPhasing - Renovation Status: New
Name | 001_Nimetus | 002_Tähis = Reference | 900_Tootja = 905_Mudel
6 x alumine kapp | Köögimööbel | alumine kapp | ootel
3 x KM-3 | Õp.toa kantseleimööbel | KM-3

# IfcFurnishingElement: Office Chair 01 27 (16)
In: 2.korrus
Classification: 1.11 IfcFurnitureType (mööbel) (IPI ÜBN)
AR_Mööbel - 001_Nimetus: Õpetaja tool, kabinettides; 002_Tähis: T2; 900_Tootja: Elke Mööbel; 905_Mudel: Actiu Stay
Pset_QuantityTakeOff - Reference: T2
AC_Pset_RenovationAndPhasing - Renovation Status: New

# IfcFurnishingElement: Office Desk Rect 27 (12)
In: 2.korrus
Classification: 1.11 IfcFurnitureType (mööbel) (IPI ÜBN)
AR_Mööbel - 001_Nimetus: Õpetaja lauakomplekt; 002_Tähis: TL2; 900_Tootja: Standard; 905_Mudel: - lauajalg PAPLK1608; - laupalaat PALK1608; sahtliboks PASBR33+PALSPLK; - el.karbik laual CONI LSE2B
Pset_QuantityTakeOff - Reference: TL2
AC_Pset_RenovationAndPhasing - Renovation Status: New

# IfcFurnishingElement: Office Table 27 (124)
Classification: 1.11 IfcFurnitureType (mööbel) (IPI ÜBN)
AC_Pset_RenovationAndPhasing - Renovation Status: New
Name | In | Reference = 002_Tähis | 001_Nimetus | 900_Tootja | 905_Mudel
2 x SET | 1.korrus | SET | Tuuliku simulaator | Festo | Nacelle_ Wind Turbine Learning System 610874
4 x SME | 1.korrus | SME | Mehaanika õppesimulaator | FESTO | 46100
100 x TL1 | 2.korrus | TL1 | Õpilase laud | Pixner | koolilaud 73, 1-kohaline
8 x SE | 2.korrus | SE | Elektritöö laud | Teklab | ConceptTower
4 x SEM | 2.korrus | SEM | Elektrimootorite stend | ?? | ??
3 x SEK | 2.korrus | SEK | Elektrikilpide stend | ?? | ??
2 x SET | 2.korrus | SET | Tuuliku simulaator | Festo | Nacelle_ Wind Turbine Learning System 610874
TL5 | 2.korrus | TL5 | Kirjutuslaud | AJ tooted | Flexus, art.nr. 153203

# IfcFurnishingElement: Piano Stool 27 (27)
Classification: 1.11 IfcFurnitureType (mööbel) (IPI ÜBN)
AR_Mööbel - 001_Nimetus: Taburet ratastel, töökodades; 002_Tähis: T4; 900_Tootja: Storit; 905_Mudel: Sigma 400RS
AC_Pset_RenovationAndPhasing - Renovation Status: New
Pset_QuantityTakeOff - Reference: T4
Name | In
10 x T4 | 1.korrus
17 x T4 | 2.korrus

# IfcFurnishingElement: Radiator Horizontal Bars 27, EKK
In: 1.korrus
Classification: 1.11 IfcFurnitureType (mööbel) (IPI ÜBN)
KVJ_Õhukanal - 100_Rõhukadu(Pa): 0; 105_Rõhk(Pa): 0; 110_Vooluhulk(l/s): 1600; 115_Voolukiirus(m/s): 1.111; 150_Kanali_suurus: 1200 mm
AR_Mööbel - 001_Nimetus: Käterätikuivati; 002_Tähis: EKK; 900_Tootja: Laris; 905_Mudel: Alfa P6
AC_Pset_RenovationAndPhasing - Renovation Status: New
Pset_QuantityTakeOff - Reference: EKK

# IfcFurnishingElement: Round Table 01 27 (5)
In: 2.korrus
Classification: 1.11 IfcFurnitureType (mööbel) (IPI ÜBN)
AR_Mööbel - 001_Nimetus: Diivanilaud; 002_Tähis: DL2; 900_Tootja: Pedrali; 905_Mudel: Icon
Pset_QuantityTakeOff - Reference: DL2
AC_Pset_RenovationAndPhasing - Renovation Status: New

# IfcFurnishingElement: Round Table 02 27 (6)
In: 1.korrus
Classification: 1.11 IfcFurnitureType (mööbel) (IPI ÜBN)
AR_Mööbel - 001_Nimetus: Söögilaud; 002_Tähis: L1; 900_Tootja: Pedrali; 905_Mudel: Lauajalg 4430, värvitud RAL.
Pset_QuantityTakeOff - Reference: L1
AC_Pset_RenovationAndPhasing - Renovation Status: New

# IfcFurnishingElement: School Chair 27 (164)
Classification: 1.11 IfcFurnitureType (mööbel) (IPI ÜBN)
AC_Pset_RenovationAndPhasing - Renovation Status: New
Name | In | 001_Nimetus | 002_Tähis = Reference | 900_Tootja | 905_Mudel
36 x T3 | 1.korrus | Üldtool, rühmaruum, klienditool | T3 | Enea | Ema Sledge Open Back Chair
66 x T1 | 2.korrus | Õpilase tool | T1 | Isku | Tutor 1035
36 x T5 | 2.korrus | Arvutitool | T5 | Arco Metal | Arvutitool POP
26 x T3 | 2.korrus | Üldtool, rühmaruum, klienditool | T3 | Enea | Ema Sledge Open Back Chair

# IfcFurnishingElement: Sofa 27 (2)
In: 2.korrus
Classification: 1.11 IfcFurnitureType (mööbel) (IPI ÜBN)
AR_Mööbel - 001_Nimetus: Diivan; 002_Tähis: D1; 900_Tootja: Oot-Oot; 905_Mudel: Floyd-260
Pset_QuantityTakeOff - Reference: D1
AC_Pset_RenovationAndPhasing - Renovation Status: New

# IfcFurnishingElement: Sofa Chair 02 27, TT1
In: 2.korrus
Classification: 1.11 IfcFurnitureType (mööbel) (IPI ÜBN)
AR_Mööbel - 001_Nimetus: Tugitool; 002_Tähis: TT1; 900_Tootja: Oot-Oot; 905_Mudel: Floyd
AC_Pset_RenovationAndPhasing - Renovation Status: New
Pset_QuantityTakeOff - Reference: TT1

# IfcFurnishingElement: Standing Cabinet Block 27, KM-1
In: 2.korrus
Classification: 1.11 IfcFurnitureType (mööbel) (IPI ÜBN)
AR_Mööbel - 001_Nimetus: Köögimööbel; 002_Tähis: KM-1; 900_Tootja: eritellimus
AC_Pset_RenovationAndPhasing - Renovation Status: New
Pset_QuantityTakeOff - Reference: KM-1

# IfcFurnishingElement: Wall Cabinet Block 27 (5)
In: 2.korrus
Classification: 1.11 IfcFurnitureType (mööbel) (IPI ÜBN)
AR_Mööbel - 001_Nimetus: Köögimööbel; 002_Tähis: KM-1; 900_Tootja: eritellimus; 905_Mudel: ootel
AC_Pset_RenovationAndPhasing - Renovation Status: New
Pset_QuantityTakeOff - Reference: KM-1

# IfcFurnishingElement: Washer 27, PM
In: 1.korrus
Classification: 1.11 IfcFurnitureType (mööbel) (IPI ÜBN)
AC_Pset_RenovationAndPhasing - Renovation Status: New
Pset_QuantityTakeOff - Reference: PM
KVJ_Õhukanal - 100_Rõhukadu(Pa): 0; 105_Rõhk(Pa): 0; 110_Vooluhulk(l/s): 1600; 115_Voolukiirus(m/s): 1.111; 150_Kanali_suurus: 1200 mm
AR_Mööbel - 001_Nimetus: Professionaalne pesumasin; 002_Tähis: PM; 900_Tootja: Miele; 905_Mudel: PWM508 DVLW 8kg Mopstar 80 + paigaldusalus APCL085

# IfcMember: 10 x 90 (14)
In: 2.korrus
Classification: 1.13 IfcMemberType (kandev element) (IPI ÜBN); Material: Aluminium
AC_Pset_RenovationAndPhasing - Renovation Status: Undefined
BaseQuantities - CrossSectionArea: 0.0009 m2
Name | Length (mm) | OuterSurfaceArea (m2) | TotalSurfaceArea (m2) = GrossSurfaceArea (m2) | GrossVolume (m3) = NetVolume (m3)
 | 1.05231 | 0.000210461 | 0.00201046 | 9.47076e-07
 | 548.579 | 0.109716 | 0.111516 | 0.000493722
 | 411.118 | 0.0822237 | 0.0840237 | 0.000370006
2 x  | 633.043 | 0.126609 | 0.128409 | 0.000569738
 | 361.957 | 0.0723914 | 0.0741914 | 0.000325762
 | 114.561 | 0.0229122 | 0.0247122 | 0.000103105
 | 747.604 | 0.149521 | 0.151321 | 0.000672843
 | 132.835 | 0.0265671 | 0.0283671 | 0.000119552
2 x  | 138.043 | 0.0276086 | 0.0294086 | 0.000124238
2 x  | 861.957 | 0.172391 | 0.174191 | 0.000775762
 | 361.957 | 0.0723915 | 0.0741915 | 0.000325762

# IfcMember: 50 x 110 (11)
In: 1.korrus
Classification: 1.13 IfcMemberType (kandev element) (IPI ÜBN); Material: Aluminium
AC_Pset_RenovationAndPhasing - Renovation Status: Undefined
BaseQuantities - CrossSectionArea: 0.0055 m2
Name | Length (mm) | OuterSurfaceArea (m2) | TotalSurfaceArea (m2) = GrossSurfaceArea (m2) | GrossVolume (m3) = NetVolume (m3)
 | 285 | 0.0912 | 0.1022 | 0.0015675
 | 1760.86 | 0.563474 | 0.574474 | 0.00968471
 | 1278.49 | 0.409117 | 0.420117 | 0.0070317
 | 570 | 0.1824 | 0.1934 | 0.003135
 | 297.733 | 0.0952747 | 0.106275 | 0.00163753
 | 175 | 0.056 | 0.067 | 0.0009625
 | 190.22 | 0.0608703 | 0.0718703 | 0.00104621
 | 421.781 | 0.13497 | 0.14597 | 0.0023198
 | 24.2537 | 0.00776118 | 0.0187612 | 0.000133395
 | 2035.96 | 0.651506 | 0.662506 | 0.0111978
 | 1715 | 0.5488 | 0.5598 | 0.0094325

# IfcMember: Boundary Frame 40 x 90 (134)
In: 2.korrus
Classification: 1.13 IfcMemberType (kandev element) (IPI ÜBN); Material: Aluminium
BaseQuantities - CrossSectionArea: 0.0036 m2
AC_Pset_RenovationAndPhasing - Renovation Status: Undefined
Name | Length (mm) | OuterSurfaceArea (m2) | TotalSurfaceArea (m2) = GrossSurfaceArea (m2) | GrossVolume (m3) = NetVolume (m3)
 | 340.898 | 0.0886335 | 0.0958335 | 0.00122723
4 x  | 287.049 | 0.0746326 | 0.0818326 | 0.00103338
 | 111.42 | 0.0289693 | 0.0361693 | 0.000401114
4 x  | 180 | 0.0468 | 0.054 | 0.000648
2 x  | 82.5779 | 0.0214702 | 0.0286702 | 0.00029728
4 x  | 2380 | 0.6188 | 0.626 | 0.008568
 | 131.42 | 0.0341693 | 0.0413693 | 0.000473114
2 x  | 82.5778 | 0.0214702 | 0.0286702 | 0.00029728
 | 1000 | 0.26 | 0.2672 | 0.00360001
 | 488.578 | 0.12703 | 0.13423 | 0.00175888
 | 468.578 | 0.12183 | 0.12903 | 0.00168688
 | 340.898 | 0.0886334 | 0.0958334 | 0.00122723
2 x  | 1136.52 | 0.295496 | 0.302696 | 0.00409149
4 x  | 350.104 | 0.0910271 | 0.0982271 | 0.00126037
 | 1020 | 0.2652 | 0.2724 | 0.003672
2 x  | 173.479 | 0.0451046 | 0.0523046 | 0.000624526
2 x  | 351.304 | 0.0913391 | 0.0985391 | 0.0012647
 | 101.871 | 0.0264864 | 0.0336864 | 0.000366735
 | 898.888 | 0.233711 | 0.240911 | 0.003236
 | 1001.81 | 0.260471 | 0.267671 | 0.00360652
 | 424.71 | 0.110425 | 0.117625 | 0.00152895
 | 424.71 | 0.110424 | 0.117624 | 0.00152895
2 x  | 1126.12 | 0.292791 | 0.299991 | 0.00405402
2 x  | 98.6887 | 0.0256591 | 0.0328591 | 0.000355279
2 x  | 78.6886 | 0.020459 | 0.027659 | 0.000283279
12 x  | 2360 | 0.6136 | 0.6208 | 0.008496
2 x  | 1434.75 | 0.373034 | 0.380234 | 0.00516509
2 x  | 1454.75 | 0.378234 | 0.385434 | 0.00523709
2 x  | 232.184 | 0.0603678 | 0.0675678 | 0.000835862
 | 556.579 | 0.144711 | 0.151911 | 0.00200369
 | 19.9988 | 0.00519969 | 0.0123997 | 0.0000719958
 | 576.579 | 0.149911 | 0.157111 | 0.00207569
2 x  | 1043.42 | 0.271289 | 0.278489 | 0.00375631
 | 8 | 0.00208 | 0.00928 | 0.0000288
 | 2080 | 0.5408 | 0.548 | 0.007488
2 x  | 37.5778 | 0.00977024 | 0.0169702 | 0.00013528
 | 280 | 0.0728 | 0.08 | 0.001008
2 x  | 675.302 | 0.175579 | 0.182779 | 0.00243109
2 x  | 1522.42 | 0.39583 | 0.40303 | 0.00548072
2 x  | 443.118 | 0.115211 | 0.122411 | 0.00159523
 | 32 | 0.00832 | 0.01552 | 0.0001152
2 x  | 966.225 | 0.251219 | 0.258419 | 0.00347841
 | 1640.1 | 0.426426 | 0.433626 | 0.00590436
2 x  | 618.043 | 0.160691 | 0.167891 | 0.00222495
 | 241.205 | 0.0627134 | 0.0699134 | 0.000868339
2 x  | 478.773 | 0.124481 | 0.131681 | 0.00172358
2 x  | 361.957 | 0.0941089 | 0.101309 | 0.00130305
2 x  | 381.957 | 0.0993089 | 0.106509 | 0.00137505
 | 732.604 | 0.190477 | 0.197677 | 0.00263737
2 x  | 252.604 | 0.0656769 | 0.0728769 | 0.000909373
2 x  | 827.396 | 0.215123 | 0.222323 | 0.00297863
4 x  | 114.561 | 0.0297858 | 0.0369858 | 0.000412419
2 x  | 1656.1 | 0.430585 | 0.437785 | 0.00596195
2 x  | 1214.56 | 0.315786 | 0.322986 | 0.00437242
 | 132.835 | 0.0345372 | 0.0417372 | 0.000478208
2 x  | 225.291 | 0.0585757 | 0.0657757 | 0.000811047
 | 570.367 | 0.148295 | 0.155495 | 0.00205332
 | 152.835 | 0.0397372 | 0.0469372 | 0.000550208
4 x  | 738.043 | 0.191891 | 0.199091 | 0.00265695
4 x  | 351.957 | 0.0915089 | 0.0987089 | 0.00126705
2 x  | 138.043 | 0.0358911 | 0.0430911 | 0.000496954
4 x  | 480 | 0.1248 | 0.132 | 0.001728
2 x  | 861.957 | 0.224109 | 0.231309 | 0.00310305
2 x  | 158.043 | 0.0410911 | 0.0482911 | 0.000568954
2 x  | 881.957 | 0.229309 | 0.236509 | 0.00317505
2 x  | 577 | 0.15002 | 0.15722 | 0.0020772
2 x  | 573 | 0.14898 | 0.15618 | 0.0020628

# IfcMember: Boundary Frame 50 x 150 (26)
In: 1.korrus
Classification: 1.13 IfcMemberType (kandev element) (IPI ÜBN); Material: Metall - Alumiinium
AC_Pset_RenovationAndPhasing - Renovation Status: Undefined
BaseQuantities - CrossSectionArea: 0.0075 m2
Name | Length (mm) | OuterSurfaceArea (m2) | TotalSurfaceArea (m2) = GrossSurfaceArea (m2) | GrossVolume (m3) = NetVolume (m3)
 | 150.676 | 0.0602702 | 0.0752702 | 0.00113007
 | 1252.55 | 0.501018 | 0.516018 | 0.0093941
 | 412.404 | 0.164961 | 0.179961 | 0.00309303
 | 409.305 | 0.163722 | 0.178722 | 0.00306978
 | 662.081 | 0.264833 | 0.279833 | 0.00496561
 | 911.416 | 0.364566 | 0.379566 | 0.00683562
 | 1168.04 | 0.467215 | 0.482215 | 0.00876028
 | 1240.07 | 0.49603 | 0.51103 | 0.00930056
2 x  | 2075 | 0.83 | 0.845 | 0.0155625
 | 88.1008 | 0.0352403 | 0.0502403 | 0.000660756
 | 334.476 | 0.13379 | 0.14879 | 0.00250857
 | 1176.88 | 0.470753 | 0.485753 | 0.00882661
 | 593.041 | 0.237216 | 0.252216 | 0.0044478
 | 667.094 | 0.266838 | 0.281838 | 0.00500321
 | 844.263 | 0.337705 | 0.352705 | 0.00633197
 | 999.509 | 0.399804 | 0.414804 | 0.00749632
 | 918.317 | 0.367327 | 0.382327 | 0.00688737
 | 152.602 | 0.0610409 | 0.0760409 | 0.00114452
 | 1098.95 | 0.439581 | 0.454581 | 0.00824215
 | 1090.7 | 0.436278 | 0.451278 | 0.00818022
 | 837.919 | 0.335167 | 0.350167 | 0.00628439
 | 588.584 | 0.235434 | 0.250434 | 0.00441438
 | 1921.73 | 0.768691 | 0.783691 | 0.014413
 | 87.4387 | 0.0349755 | 0.0499755 | 0.00065579
 | 331.962 | 0.132785 | 0.147785 | 0.00248972

# IfcMember: Boundary Frame 50 x 200 (136)
Classification: 1.13 IfcMemberType (kandev element) (IPI ÜBN)
BaseQuantities - CrossSectionArea: 0.01 m2
AC_Pset_RenovationAndPhasing - Renovation Status: Undefined
Name | In | Material | Length (mm) | OuterSurfaceArea (m2) | TotalSurfaceArea (m2) = GrossSurfaceArea (m2) | GrossVolume (m3) = NetVolume (m3)
 | 1.korrus | Aluminium | 815 | 0.4075 | 0.4275 | 0.00815
 | 1.korrus | Aluminium | 3210 | 1.605 | 1.625 | 0.0321
 | 1.korrus | Aluminium | 188.617 | 0.0943084 | 0.114308 | 0.00188617
4 x  | 1.korrus | Aluminium | 1150 | 0.575 | 0.595 | 0.0115
3 x  | 1.korrus | Aluminium | 1125 | 0.5625 | 0.5825 | 0.01125
 | 1.korrus | Aluminium | 590.847 | 0.295423 | 0.315423 | 0.00590847
3 x  | 1.korrus | Aluminium | 1280.57 | 0.640283 | 0.660283 | 0.0128057
 | 1.korrus | Aluminium | 1279.78 | 0.639888 | 0.659888 | 0.0127978
 | 1.korrus | Aluminium | 1065.87 | 0.532933 | 0.552933 | 0.0106587
 | 1.korrus | Aluminium | 2.94189 | 0.00147094 | 0.0214709 | 0.0000294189
 | 1.korrus | Aluminium | 559.489 | 0.279745 | 0.299745 | 0.00559489
 | 1.korrus | Aluminium | 363.849 | 0.181924 | 0.201924 | 0.00363849
 | 1.korrus | Aluminium | 33.9004 | 0.0169502 | 0.0369502 | 0.000339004
 | 1.korrus | Aluminium | 5 | 0.0025 | 0.0225 | 0.00005
 | 1.korrus | Aluminium | 518.046 | 0.259023 | 0.279023 | 0.00518046
 | 1.korrus | Aluminium | 360 | 0.18 | 0.2 | 0.0036
 | 1.korrus | Aluminium | 75 | 0.0375 | 0.0575 | 0.00075
 | 1.korrus | Aluminium | 1346.45 | 0.673226 | 0.693226 | 0.0134645
 | 1.korrus | Aluminium | 335 | 0.1675 | 0.1875 | 0.00335
 | 1.korrus | Aluminium | 790 | 0.395 | 0.415 | 0.0079
 | 1.korrus | Aluminium | 75.0001 | 0.0375001 | 0.0575001 | 0.000750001
 | 1.korrus | Aluminium | 1294.32 | 0.647162 | 0.667162 | 0.0129432
2 x  | 1.korrus | Aluminium | 1990 | 0.995 | 1.015 | 0.0199
3 x  | 1.korrus | Aluminium | 2610 | 1.305 | 1.325 | 0.0261
2 x  | 1.korrus | Aluminium | 1669.12 | 0.83456 | 0.85456 | 0.0166912
2 x  | 1.korrus | Aluminium | 1365.27 | 0.682637 | 0.702637 | 0.0136527
 | 1.korrus | Aluminium | 419.91 | 0.209955 | 0.229955 | 0.0041991
 | 1.korrus | Aluminium | 589.817 | 0.294908 | 0.314908 | 0.00589817
 | 1.korrus | Aluminium | 1074.3 | 0.537151 | 0.557151 | 0.010743
 | 1.korrus | Aluminium | 564.817 | 0.282408 | 0.302408 | 0.00564817
 | 1.korrus | Aluminium | 860.373 | 0.430186 | 0.450186 | 0.00860373
 | 1.korrus | Aluminium | 1650.52 | 0.825258 | 0.845258 | 0.0165052
4 x  | 1.korrus | Aluminium | 289.153 | 0.144577 | 0.164577 | 0.00289153
 | 1.korrus | Aluminium | 1068.78 | 0.534389 | 0.554389 | 0.0106878
 | 1.korrus | Aluminium | 107.794 | 0.0538969 | 0.0738969 | 0.00107794
3 x  | 1.korrus | Aluminium | 835.847 | 0.417923 | 0.437923 | 0.00835847
 | 1.korrus | Aluminium | 27.7101 | 0.013855 | 0.033855 | 0.000277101
 | 1.korrus | Aluminium | 13.6474 | 0.00682372 | 0.0268237 | 0.000136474
 | 1.korrus | Aluminium | 244.82 | 0.12241 | 0.14241 | 0.0024482
 | 1.korrus | Aluminium | 293.402 | 0.146701 | 0.166701 | 0.00293402
 | 1.korrus | Metall - Alumiinium | 1652.65 | 0.826324 | 0.846324 | 0.0165265
 | 1.korrus | Metall - Alumiinium | 12.4509 | 0.00622545 | 0.0262254 | 0.000124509
 | 1.korrus | Metall - Alumiinium | 1676.51 | 0.838257 | 0.858257 | 0.0167651
 | 1.korrus | Metall - Alumiinium | 1662.66 | 0.831329 | 0.851329 | 0.0166266
 | 1.korrus | Metall - Alumiinium | 24.9553 | 0.0124776 | 0.0324776 | 0.000249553
 | 1.korrus | Metall - Alumiinium | 2024.42 | 1.01221 | 1.03221 | 0.0202442
 | 1.korrus | Metall - Alumiinium | 1666.51 | 0.833257 | 0.853257 | 0.0166651
 | 1.korrus | Metall - Alumiinium | 337.343 | 0.168671 | 0.188671 | 0.00337343
 | 1.korrus | Metall - Alumiinium | 333.486 | 0.166743 | 0.186743 | 0.00333486
 | 1.korrus | Metall - Alumiinium | 44.9999 | 0.0224999 | 0.0424999 | 0.000449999
 | 1.korrus | Metall - Alumiinium | 323.486 | 0.161743 | 0.181743 | 0.00323486
 | 1.korrus | Metall - Alumiinium | 314.073 | 0.157037 | 0.177037 | 0.00314073
2 x  | 1.korrus | Metall - Alumiinium | 1272.5 | 0.63625 | 0.65625 | 0.012725
2 x  | 1.korrus | Metall - Alumiinium | 1895 | 0.9475 | 0.9675 | 0.01895
2 x  | 1.korrus | Metall - Alumiinium | 2000 | 1 | 1.02 | 0.02
3 x  | 1.korrus | Metall - Alumiinium | 105 | 0.0525 | 0.0725 | 0.00105
2 x  | 1.korrus | Metall - Alumiinium | 1272.45 | 0.636225 | 0.656225 | 0.0127245
 | 1.korrus | Metall - Alumiinium | 1580.51 | 0.790253 | 0.810253 | 0.0158051
 | 1.korrus | Metall - Alumiinium | 1516.56 | 0.75828 | 0.77828 | 0.0151656
 | 2.korrus | Aluminium | 34.2161 | 0.017108 | 0.037108 | 0.000342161
 | 2.korrus | Aluminium | 1100 | 0.55 | 0.57 | 0.011
 | 2.korrus | Aluminium | 40.3473 | 0.0201737 | 0.0401737 | 0.000403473
 | 2.korrus | Aluminium | 27.7916 | 0.0138958 | 0.0338958 | 0.000277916
2 x  | 2.korrus | Aluminium | 344.216 | 0.172108 | 0.192108 | 0.00344216
 | 2.korrus | Aluminium | 3226.67 | 1.61333 | 1.63333 | 0.0322667
 | 2.korrus | Aluminium | 790 | 0.395 | 0.415 | 0.0079
 | 2.korrus | Aluminium | 335 | 0.1675 | 0.1875 | 0.00335
2 x  | 2.korrus | Aluminium | 565.847 | 0.282923 | 0.302923 | 0.00565847
6 x  | 2.korrus | Aluminium | 1125 | 0.5625 | 0.5825 | 0.01125
 | 2.korrus | Aluminium | 1150 | 0.575 | 0.595 | 0.0115
 | 2.korrus | Aluminium | 886.242 | 0.443121 | 0.463121 | 0.00886242
 | 2.korrus | Aluminium | 100 | 0.05 | 0.07 | 0.001
 | 2.korrus | Aluminium | 41.5681 | 0.020784 | 0.040784 | 0.000415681
 | 2.korrus | Aluminium | 886.186 | 0.443093 | 0.463093 | 0.00886186
 | 2.korrus | Aluminium | 100 | 0.0500001 | 0.0700001 | 0.001
2 x  | 2.korrus | Aluminium | 780.784 | 0.390392 | 0.410392 | 0.00780784
3 x  | 2.korrus | Aluminium | 3260 | 1.63 | 1.65 | 0.0326
6 x  | 2.korrus | Aluminium | 835.847 | 0.417923 | 0.437923 | 0.00835847
6 x  | 2.korrus | Aluminium | 289.153 | 0.144577 | 0.164577 | 0.00289153
2 x  | 2.korrus | Aluminium | 890.909 | 0.445455 | 0.465455 | 0.00890909
2 x  | 2.korrus | Aluminium | 234.091 | 0.117045 | 0.137045 | 0.00234091
2 x  | 2.korrus | Aluminium | 624.153 | 0.312077 | 0.332077 | 0.00624153
2 x  | 2.korrus | Aluminium | 500.847 | 0.250423 | 0.270423 | 0.00500847
 | 2.korrus | Aluminium | 805.784 | 0.402892 | 0.422892 | 0.00805784
2 x  | 2.korrus | Aluminium | 143.326 | 0.0716632 | 0.0916632 | 0.00143326
 | 2.korrus | Aluminium | 319.216 | 0.159608 | 0.179608 | 0.00319216
 | 2.korrus | Aluminium | 649.153 | 0.324577 | 0.344577 | 0.00649153
 | 2.korrus | Aluminium | 860.847 | 0.430423 | 0.450423 | 0.00860847

# IfcMember: Boundary Frame 50 x 260 (68)
In: 1.korrus
Classification: 1.13 IfcMemberType (kandev element) (IPI ÜBN); Material: Aluminium
BaseQuantities - CrossSectionArea: 0.013 m2
AC_Pset_RenovationAndPhasing - Renovation Status: Undefined
Name | Length (mm) | OuterSurfaceArea (m2) | TotalSurfaceArea (m2) = GrossSurfaceArea (m2) | GrossVolume (m3) = NetVolume (m3)
3 x  | 1150 | 0.713 | 0.739 | 0.01495
2 x  | 1175 | 0.7285 | 0.7545 | 0.015275
43 x  | 1125 | 0.6975 | 0.7235 | 0.014625
 | 1688.33 | 1.04677 | 1.07277 | 0.0219483
3 x  | 771.355 | 0.47824 | 0.50424 | 0.0100276
2 x  | 603.333 | 0.374067 | 0.400067 | 0.00784333
 | 478.385 | 0.296599 | 0.322599 | 0.006219
 | 757.826 | 0.469852 | 0.495852 | 0.00985173
2 x  | 974.419 | 0.60414 | 0.63014 | 0.0126674
2 x  | 881.535 | 0.546552 | 0.572552 | 0.01146
 | 367.174 | 0.227648 | 0.253648 | 0.00477327
 | 646.615 | 0.400901 | 0.426901 | 0.008406
 | 2776.51 | 1.72143 | 1.74743 | 0.0360946
 | 861.827 | 0.534333 | 0.560333 | 0.0112038
 | 263.173 | 0.163167 | 0.189167 | 0.00342125
2 x  | 2606.52 | 1.61604 | 1.64204 | 0.0338847
 | 1403 | 0.86986 | 0.89586 | 0.018239

# IfcMember: Mullion Frame 40 x 90 (36)
In: 2.korrus
Classification: 1.13 IfcMemberType (kandev element) (IPI ÜBN); Material: Aluminium
AC_Pset_RenovationAndPhasing - Renovation Status: Undefined
BaseQuantities - CrossSectionArea: 0.0036 m2
Name | Length (mm) | OuterSurfaceArea (m2) | TotalSurfaceArea (m2) = GrossSurfaceArea (m2) | GrossVolume (m3) = NetVolume (m3)
6 x  | 160 | 0.0416 | 0.0488 | 0.000576
2 x  | 2060 | 0.5356 | 0.5428 | 0.007416
3 x  | 300 | 0.078 | 0.0852 | 0.00108
 | 2100 | 0.546 | 0.5532 | 0.00756
2 x  | 2360 | 0.6136 | 0.6208 | 0.008496
3 x  | 2040 | 0.5304 | 0.5376 | 0.007344
 | 280 | 0.0728 | 0.08 | 0.001008
2 x  | 2320 | 0.6032 | 0.6104 | 0.008352
8 x  | 240 | 0.0624 | 0.0696 | 0.000864
 | 260 | 0.0676 | 0.0748 | 0.000936
 | 2050 | 0.533 | 0.5402 | 0.00738
6 x  | 2070 | 0.5382 | 0.5454 | 0.007452

# IfcMember: Mullion Frame 50 x 150 (10)
In: 1.korrus
Classification: 1.13 IfcMemberType (kandev element) (IPI ÜBN); Material: Metall - Alumiinium
AC_Pset_RenovationAndPhasing - Renovation Status: Undefined
BaseQuantities - CrossSectionArea: 0.0075 m2
Name | Length (mm) | OuterSurfaceArea (m2) | TotalSurfaceArea (m2) = GrossSurfaceArea (m2) | GrossVolume (m3) = NetVolume (m3)
5 x  | 2050 | 0.82 | 0.835 | 0.015375
 | 1589.48 | 0.635794 | 0.650794 | 0.0119211
 | 1435.29 | 0.574116 | 0.589116 | 0.0107647
 | 1743.25 | 0.697301 | 0.712301 | 0.0130744
 | 1127.21 | 0.450883 | 0.465883 | 0.00845406
 | 1282 | 0.512798 | 0.527798 | 0.00961496

# IfcMember: Mullion Frame 50 x 200 (54)
Classification: 1.13 IfcMemberType (kandev element) (IPI ÜBN)
BaseQuantities - CrossSectionArea: 0.01 m2
AC_Pset_RenovationAndPhasing - Renovation Status: Undefined
Name | In | Material | Length (mm) | OuterSurfaceArea (m2) | TotalSurfaceArea (m2) = GrossSurfaceArea (m2) | GrossVolume (m3) = NetVolume (m3)
 | 1.korrus | Aluminium | 2103.77 | 1.05189 | 1.07189 | 0.0210377
 | 1.korrus | Aluminium | 200 | 0.1 | 0.12 | 0.002
 | 1.korrus | Aluminium | 154.756 | 0.0773779 | 0.0973779 | 0.00154756
 | 1.korrus | Aluminium | 316.958 | 0.158479 | 0.178479 | 0.00316958
 | 1.korrus | Aluminium | 2534.9 | 1.26745 | 1.28745 | 0.025349
 | 1.korrus | Aluminium | 1321.45 | 0.660724 | 0.680724 | 0.0132145
 | 1.korrus | Aluminium | 1296.45 | 0.648226 | 0.668226 | 0.0129645
2 x  | 1.korrus | Aluminium | 305.552 | 0.152776 | 0.172776 | 0.00305552
2 x  | 1.korrus | Aluminium | 1059.62 | 0.52981 | 0.54981 | 0.0105962
 | 1.korrus | Aluminium | 17.0512 | 0.00852559 | 0.0285256 | 0.000170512
 | 1.korrus | Aluminium | 601.718 | 0.300859 | 0.320859 | 0.00601718
2 x  | 1.korrus | Aluminium | 2050.38 | 1.02519 | 1.04519 | 0.0205038
 | 1.korrus | Aluminium | 2560 | 1.28 | 1.3 | 0.0256
 | 1.korrus | Aluminium | 480 | 0.24 | 0.26 | 0.0048
 | 1.korrus | Aluminium | 2025 | 1.0125 | 1.0325 | 0.02025
 | 1.korrus | Aluminium | 565.796 | 0.282898 | 0.302898 | 0.00565796
 | 1.korrus | Aluminium | 324.525 | 0.162263 | 0.182263 | 0.00324525
 | 1.korrus | Aluminium | 270.377 | 0.135188 | 0.155188 | 0.00270377
 | 1.korrus | Aluminium | 243.847 | 0.121924 | 0.141924 | 0.00243847
2 x  | 1.korrus | Aluminium | 756.321 | 0.37816 | 0.39816 | 0.00756321
 | 1.korrus | Aluminium | 255.337 | 0.127668 | 0.147668 | 0.00255337
 | 1.korrus | Aluminium | 951.516 | 0.475758 | 0.495758 | 0.00951516
 | 1.korrus | Aluminium | 63.1299 | 0.0315649 | 0.0515649 | 0.000631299
 | 1.korrus | Aluminium | 329.05 | 0.164525 | 0.184525 | 0.0032905
 | 1.korrus | Aluminium | 260.455 | 0.130227 | 0.150227 | 0.00260455
 | 1.korrus | Aluminium | 762.258 | 0.381129 | 0.401129 | 0.00762258
 | 1.korrus | Aluminium | 852.018 | 0.426009 | 0.446009 | 0.00852018
 | 1.korrus | Aluminium | 260.646 | 0.130323 | 0.150323 | 0.00260646
 | 1.korrus | Aluminium | 1297.54 | 0.648768 | 0.668768 | 0.0129754
 | 1.korrus | Aluminium | 100.149 | 0.0500744 | 0.0700744 | 0.00100149
4 x  | 1.korrus | Metall - Alumiinium | 2505 | 1.2525 | 1.2725 | 0.02505
 | 2.korrus | Aluminium | 955 | 0.4775 | 0.4975 | 0.00955
 | 2.korrus | Aluminium | 2275 | 1.1375 | 1.1575 | 0.02275
 | 2.korrus | Aluminium | 3230 | 1.615 | 1.635 | 0.0323
3 x  | 2.korrus | Aluminium | 910 | 0.455 | 0.475 | 0.0091
3 x  | 2.korrus | Aluminium | 2250 | 1.125 | 1.145 | 0.0225
7 x  | 2.korrus | Aluminium | 3210 | 1.605 | 1.625 | 0.0321

# IfcMember: Mullion Frame 50 x 260 (69)
In: 1.korrus
Classification: 1.13 IfcMemberType (kandev element) (IPI ÜBN); Material: Aluminium
AC_Pset_RenovationAndPhasing - Renovation Status: Undefined
BaseQuantities - CrossSectionArea: 0.013 m2
Name | Length (mm) | OuterSurfaceArea (m2) | TotalSurfaceArea (m2) = GrossSurfaceArea (m2) | GrossVolume (m3) = NetVolume (m3)
3 x  | 2050 | 1.271 | 1.297 | 0.02665
 | 1145 | 0.7099 | 0.7359 | 0.014885
 | 198.988 | 0.123373 | 0.149373 | 0.00258685
 | 1050.59 | 0.651366 | 0.677366 | 0.0136577
 | 1655 | 1.0261 | 1.0521 | 0.021515
4 x  | 1242.54 | 0.770374 | 0.796374 | 0.016153
 | 155.56 | 0.0964475 | 0.122447 | 0.00202229
 | 73.5592 | 0.0456067 | 0.0716067 | 0.000956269
 | 572.391 | 0.354882 | 0.380882 | 0.00744108
 | 1206.39 | 0.747964 | 0.773964 | 0.0156831
 | 55.0218 | 0.0341135 | 0.0601135 | 0.000715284
 | 12.6225 | 0.00782595 | 0.033826 | 0.000164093
 | 9.42253 | 0.00584197 | 0.031842 | 0.000122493
 | 1272.55 | 0.788978 | 0.814978 | 0.0165431
11 x  | 570 | 0.3534 | 0.3794 | 0.00741
 | 1091.67 | 0.676833 | 0.702833 | 0.0141917
 | 430.555 | 0.266944 | 0.292944 | 0.00559721
 | 856.633 | 0.531113 | 0.557113 | 0.0111362
 | 363.425 | 0.225323 | 0.251323 | 0.00472452
 | 53.1154 | 0.0329316 | 0.0589316 | 0.0006905
 | 427.673 | 0.265157 | 0.291157 | 0.00555975
5 x  | 1242.58 | 0.770402 | 0.796402 | 0.0161536
 | 421.781 | 0.261504 | 0.287504 | 0.00548316
 | 179.255 | 0.111138 | 0.137138 | 0.00233032
 | 627.595 | 0.389109 | 0.415109 | 0.00815873
 | 783.912 | 0.486025 | 0.512025 | 0.0101909
 | 374.606 | 0.232256 | 0.258256 | 0.00486987
10 x  | 3220 | 1.9964 | 2.0224 | 0.04186
2 x  | 1320 | 0.8184 | 0.8444 | 0.01716
 | 2525.7 | 1.56593 | 1.59193 | 0.032834
 | 1547.39 | 0.959382 | 0.985382 | 0.0201161
2 x  | 1056.44 | 0.654994 | 0.680994 | 0.0137337
 | 563.337 | 0.349269 | 0.375269 | 0.00732338
 | 88.5599 | 0.0549072 | 0.0809072 | 0.00115128
2 x  | 1450 | 0.899 | 0.925 | 0.01885
2 x  | 1720 | 1.0664 | 1.0924 | 0.02236
 | 1715 | 1.0633 | 1.0893 | 0.022295

# IfcMember: Transom Frame 40 x 90
In: 2.korrus
Classification: 1.13 IfcMemberType (kandev element) (IPI ÜBN); Material: Aluminium
AC_Pset_RenovationAndPhasing - Renovation Status: Undefined
BaseQuantities - Length: 960.002 mm; CrossSectionArea: 0.0036 m2; OuterSurfaceArea: 0.2496 m2; TotalSurfaceArea: 0.2568 m2; GrossSurfaceArea: 0.2568 m2; GrossVolume: 0.00345601 m3; NetVolume: 0.00345601 m3

# IfcMember: Transom Frame 50 x 150 (12)
Classification: 1.13 IfcMemberType (kandev element) (IPI ÜBN)
AC_Pset_RenovationAndPhasing - Renovation Status: Undefined
BaseQuantities - CrossSectionArea: 0.0075 m2
Name | In | Material | Length (mm) | OuterSurfaceArea (m2) | TotalSurfaceArea (m2) = GrossSurfaceArea (m2) | GrossVolume (m3) = NetVolume (m3)
 | 1.korrus | Metall - Alumiinium | 812.919 | 0.325167 | 0.340167 | 0.00609689
 | 1.korrus | Metall - Alumiinium | 384.305 | 0.153722 | 0.168722 | 0.00288228
 | 1.korrus | Metall - Alumiinium | 637.081 | 0.254833 | 0.269833 | 0.00477811
 | 1.korrus | Metall - Alumiinium | 886.416 | 0.354566 | 0.369566 | 0.00664812
 | 1.korrus | Metall - Alumiinium | 62.4387 | 0.0249755 | 0.0399755 | 0.00046829
 | 1.korrus | Metall - Alumiinium | 127.602 | 0.0510409 | 0.0660409 | 0.000957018
 | 1.korrus | Metall - Alumiinium | 1190.07 | 0.47603 | 0.49103 | 0.00892556
 | 1.korrus | Metall - Alumiinium | 563.584 | 0.225434 | 0.240434 | 0.00422688
 | 1.korrus | Metall - Alumiinium | 1143.04 | 0.457215 | 0.472215 | 0.00857278
 | 1.korrus | Metall - Alumiinium | 1065.7 | 0.426278 | 0.441278 | 0.00799272
 | 1.korrus | Metall - Alumiinium | 306.962 | 0.122785 | 0.137785 | 0.00230222
 | 2.korrus | Aluminium | 1075 | 0.43 | 0.445 | 0.0080625

# IfcMember: Transom Frame 50 x 200 (10)
In: 1.korrus
Classification: 1.13 IfcMemberType (kandev element) (IPI ÜBN); Material: Metall - Alumiinium
AC_Pset_RenovationAndPhasing - Renovation Status: Undefined
BaseQuantities - CrossSectionArea: 0.01 m2
Name | Length (mm) | OuterSurfaceArea (m2) | TotalSurfaceArea (m2) = GrossSurfaceArea (m2) | GrossVolume (m3) = NetVolume (m3)
 | 1651.51 | 0.825757 | 0.845757 | 0.0165151
 | 312.343 | 0.156171 | 0.176171 | 0.00312343
 | 301.573 | 0.150787 | 0.170787 | 0.00301573
 | 1641.51 | 0.820757 | 0.840757 | 0.0164151
 | 1627.65 | 0.813824 | 0.833824 | 0.0162765
 | 1637.66 | 0.818829 | 0.838829 | 0.0163766
 | 308.486 | 0.154243 | 0.174243 | 0.00308486
 | 298.486 | 0.149243 | 0.169243 | 0.00298486
 | 1235 | 0.6175 | 0.6375 | 0.01235
 | 1234.95 | 0.617475 | 0.637475 | 0.0123495

# IfcOpeningElement (390)
Name | In | Depth (mm) | Height (mm) | Width (mm) | Area (m2) | Volume (m3)
11 x ava | 1.korrus | 10 | 2110 | 810 | 1.7091 | 0
ava | 1.korrus | 10 | 2110 | 1010 | 2.1311 | 0
TU10,EI30 | 1.korrus | 190 | 2110 | 1010 | 2.1311 | 0.146237
TU8,5,EI30 | 1.korrus | 190 | 2110 | 870 | 1.8357 | 0.126826
4 x PU9,dB | 1.korrus | 140 | 2110 | 910 | 1.9201 | 0.132372
3 x PU10 | 1.korrus | 140 | 2110 | 1010 | 2.1311 | 0.146237
2 x TU9,EI30,dB | 1.korrus | 190 | 2110 | 910 | 1.9201 | 0.132372
ava | 1.korrus | 190 | 2110 | 1809.99 | 3.81909 | 0
TKU9+9,EI30,dB | 1.korrus | 140 | 2110 | 1810 | 3.8191 | 0.0730854
3 x NU8 | 1.korrus | 140 | 2110 | 810 | 1.7091 | 0.118714
TKU10+5,EI30,dB | 1.korrus | 140 | 2110 | 1510 | 3.1861 | 0.0682794
ava | 1.korrus | 140 | 2200 | 1150 | 2.53 | 0
ava | 1.korrus | 140 | 2300 | 1270 | 2.921 | 0
ava | 1.korrus | 140 | 2300 | 1380 | 3.174 | 0
3 x ava | 1.korrus | 440 | 0 | 0 | 0 | 0
3 x ava | 1.korrus | 440 | 300 | 2500 | 0.75 | 0
6 x PU8 | 1.korrus | 140 | 2110 | 810 | 1.7091 | 0.118507
NU8 | 1.korrus | 140 | 2110 | 810 | 1.7091 | 0.118507
9 x A-1g,SE | 1.korrus | 437 | 1910 | 1010 | 1.9291 | 0.053156
4 x AL-1,EI30 | 1.korrus | 437 | 1910 | 1010 | 1.9291 | 0.053156
7 x A-1g | 1.korrus | 437 | 1910 | 1010 | 1.9291 | 0.053156
3 x Ava seinas | 1.korrus | 437 | 2600 | 2500 | 6.5 | 0
3 x TÕU25x26 | 1.korrus | 437 | 2600 | 2500 | 6.5 | 0.312401
TKU9+9,EI30,dB | 1.korrus | 190 | 2110 | 1810 | 3.8191 | 0.0730854
2 x TU9,EI60 | 1.korrus | 190 | 2110 | 910 | 1.9201 | 0.132372
TU8 | 1.korrus | 190 | 2110 | 810 | 1.7091 | 0.118507
PU8 | 1.korrus | 140 | 2110 | 808.973 | 1.70693 | 0.118507
ava | 1.korrus | 10 | 2110 | 800.401 | 1.68885 | 0
2 x ava | 1.korrus | 92 | 2110 | 910 | 1.9201 | 0
ava | 1.korrus | 92 | 2110 | 5255.75 | 11.0896 | 0
ava | 1.korrus | 92 | 2110 | 3866 | 8.15726 | 0
ava | 1.korrus | 92 | 0 | 0 | 0 | 0
ava | 1.korrus | 92 | 2110 | 5206 | 10.9847 | 0
TU7+7,EI30 | 1.korrus | 190 | 2110 | 1410 | 2.9751 | 0.132879
ava | 1.korrus | 420 | 2380 | 1500 | 3.57 | 0
VA-XX | 1.korrus | 420 | 2380 | 1500 | 3.57 | 0.045656
AL-3,EI120 | 1.korrus | 420 | 2380 | 1500 | 3.57 | 0.045656
VA-XX | 1.korrus | 420 | 2380 | 1500 | 3.57 | 0
 | 1.korrus | 420 | 2400 | 2300 | 5.52 | 0.227225
ava | 1.korrus | 360 | 2040 | 1419.68 | 2.89614 | 1.04261 | Classification: 1.14 IfcOpeningElement (avaelement) (IPI ÜBN); AC_Pset_RenovationAndPhasing - Renovation Status: Existing
2 x VA-XX | 1.korrus | 100 | 1150 | 2480 | 2.852 | 0.031218
VA-XX | 1.korrus | 100 | 1150 | 2450 | 2.8175 | 0.0310117
2 x  | 1.korrus | 100 | 2080 | 2960 | 6.1568 | 0.272317
ava | 1.korrus | 250 |  |  | 7.34659 | 1.83665 | Classification: 1.14 IfcOpeningElement (avaelement) (IPI ÜBN); AC_Pset_RenovationAndPhasing - Renovation Status: Existing
8 x VA-XX | 1.korrus | 360 | 1100.26 | 2985 | 3.28427 | 0.0274282
SU-XX | 1.korrus | 360 | 2060 | 1980 | 4.0788 | 0.266137
SA-XX | 1.korrus | 360 | 1140 | 1670 | 1.9038 | 0.022596
SU-XX | 1.korrus | 360 | 2070 | 900 | 1.863 | 0.129399
SU-XX | 1.korrus | 360 | 2060 | 880 | 1.8128 | 0.121496
SU-XX | 1.korrus | 360 | 2100 | 900 | 1.89 | 0.112549
 | 1.korrus | 410 | 2300 | 1505 | 3.4615 | 0.24413
 | 1.korrus | 660 | 2100 | 1200 | 2.52 | 0.130691
 | 1.korrus | 80 | 4080 | 3810 | 15.5448 | 0.670858
 | 1.korrus | 80 | 4010 | 4600 | 18.446 | 0.793715
6 x VA-XX | 1.korrus | 420 | 2260 | 1480 | 3.3448 | 0.037076
 | 1.korrus | 420 | 3520 | 3480 | 12.2496 | 0.476914
 | 1.korrus | 420 | 3520 | 3500 | 12.32 | 0.47963
2 x VA-XX | 1.korrus | 290 | 1120 | 2420 | 2.7104 | 0.03791
VA-XX | 1.korrus | 290 | 1100 | 2420 | 2.662 | 0.0489284
VA-XX | 1.korrus | 290 | 1100 | 2420 | 2.662 | 0.0617884
VA-XX | 1.korrus | 560 | 1120 | 2920 | 3.2704 | 0.04216
VA-XX | 1.korrus | 560 | 1120 | 2920 | 3.2704 | 0.0569842
VA-XX | 1.korrus | 520 | 1120 | 2920 | 3.2704 | 0.0569842
VA-XX | 1.korrus | 520 | 1120 | 2920 | 3.2704 | 0.04216
 | 1.korrus | 420 | 3580 | 3480 | 12.4584 | 0.478677
 | 1.korrus | 420 | 3580 | 3560 | 12.7448 | 0.489685
ava | 1.korrus | 200 | 1000 | 4600 | 4.6 | 0.2484 | Classification: 1.14 IfcOpeningElement (avaelement) (IPI ÜBN); AC_Pset_RenovationAndPhasing - Renovation Status: Existing
ava | 1.korrus | 200 | 1000 | 3810 | 3.81 | 0.19812 | Classification: 1.14 IfcOpeningElement (avaelement) (IPI ÜBN); AC_Pset_RenovationAndPhasing - Renovation Status: Existing
 | 1.korrus | 190 | 2090 | 5800 | 12.122 | 2.3031 | Classification: 1.14 IfcOpeningElement (avaelement) (IPI ÜBN); AC_Pset_RenovationAndPhasing - Renovation Status: Existing
 | 1.korrus | 360 | 2100 | 1790 | 3.759 | 0.111635
TU10+5,EI60 | 1.korrus | 400 | 2070 | 1490 | 3.0843 | 0.15226
ava | 1.korrus | 400 | 2070 | 1490 | 3.0843 | 0
SU-XX | 1.korrus | 300 | 2060 | 1100 | 2.266 | 0.10308
5 x VA-XX | 1.korrus | 420 | 2380 | 1530 | 3.6414 | 0.0322465
VA-XX | 1.korrus | 420 | 2380 | 1530 | 3.6414 | 0.0552115
VA-XX | 1.korrus | 420 | 2380 | 1530 | 3.6414 | 0.046124
4 x VA-XX | 1.korrus | 420 | 2380 | 1500 | 3.57 | 0.0483437
VA-XX | 1.korrus | 420 | 2380 | 1500 | 3.57 | 0.0566219
11 x VA-XX | 1.korrus | 420 | 2350 | 1500 | 3.525 | 0.0480122
3 x VA-XX | 1.korrus | 420 | 2401.43 | 1520 | 3.65018 | 0.0739524
VA-XX | 1.korrus | 420 | 2350 | 1500 | 3.525 | 0.083325
 | 1.korrus | 420 | 3490 | 3610 | 12.5989 | 0.42871
 | 1.korrus | 420 | 3490 | 3625 | 12.6513 | 0.430523
 | 1.korrus | 420 | 3490 | 3560 | 12.4244 | 0.422667
 | 1.korrus | 420 | 4000 | 3600 | 14.4 | 0.558948
VA-XX | 1.korrus | 420 | 2380 | 3600 | 8.568 | 0.230701
ava | 1.korrus | 260 | 2070 | 1500 | 3.105 | 0.8073 | Classification: 1.14 IfcOpeningElement (avaelement) (IPI ÜBN); AC_Pset_RenovationAndPhasing - Renovation Status: Existing
TU10+5,EI120 | 1.korrus | 420 | 2070 | 1490 | 3.0843 | 0.15226
SU-XX | 1.korrus | 200 | 2100 | 925 | 1.9425 | 0.123789
ava | 1.korrus | 400 | 2070 | 1500 | 3.105 | 0
TU10+5,EI120,dB | 1.korrus | 400 | 2070 | 1500 | 3.105 | 0.153141
2 x ava | 1.korrus | 230 | 130 | 2960 | 0.3848 | 0.088504 | Classification: 1.14 IfcOpeningElement (avaelement) (IPI ÜBN); AC_Pset_RenovationAndPhasing - Renovation Status: Existing
ava | 1.korrus | 400 | 2060 | 1430 | 2.9458 | 0
VA-XX | 1.korrus | 100 | 1150 | 4960 | 5.704 | 0.0732203
2 x VA-XX | 1.korrus | 100 | 1150 | 1200 | 1.38 | 0.0241312
VA-XX | 1.korrus | 100 | 1150 | 2350 | 2.7025 | 0.0303242
VA-XX | 1.korrus | 100 | 1150 | 3650 | 4.1975 | 0.0370625
 | 1.korrus | 100 | 2560 | 2520 | 6.4512 | 0.245546
3 x  | 1.korrus | 100 | 2050 | 850 | 1.7425 | 0.0814539
 | 1.korrus | 360 | 2080 | 1980 | 4.1184 | 0.196302
SU-XX | 1.korrus | 360 | 2090 | 1980 | 4.1382 | 0.286687
 | 1.korrus | 250 | 2480 | 1500 | 3.72 | 0.169469
ava | 1.korrus | 250 |  |  | 4.90845 | 1.19645 | Classification: 1.14 IfcOpeningElement (avaelement) (IPI ÜBN); AC_Pset_RenovationAndPhasing - Renovation Status: Existing
ava | 1.korrus | 250 |  |  | 7.30213 | 0.365834 | Classification: 1.14 IfcOpeningElement (avaelement) (IPI ÜBN); AC_Pset_RenovationAndPhasing - Renovation Status: Existing
SU-XX | 1.korrus | 90 | 2070 | 2870 | 5.9409 | 0.401876
2 x SU-XX | 1.korrus | 110 | 2100 | 2870 | 6.027 | 0.407609
2 x SU-XX | 1.korrus | 150 | 2100 | 700 | 1.47 | 0.0838191
2 x SU-XX | 1.korrus | 150 | 2100 | 730 | 1.533 | 0.087033
2 x SA-XX | 1.korrus | 400 | 1155 | 1180 | 1.3629 | 0.0213037
 | 1.korrus | 540 | 2130 | 1510 | 3.2163 | 0.221277
 | 1.korrus | 380 | 2090 | 1500 | 3.135 | 0.154551
 | 1.korrus | 310 | 2040 | 1180 | 2.4072 | 0.172905
 | 1.korrus | 150 | 2070 | 920 | 1.9044 | 0.0994039
 | 1.korrus | 150 | 2070 | 900 | 1.863 | 0.0809125
 | 1.korrus | 380 | 2100 | 1950 | 4.095 | 0
 | 1.korrus | 380 | 580 | 1950 | 1.131 | 0.0246392
ava | 1.korrus | 380 | 2100 | 1950 | 4.095 | 0
TU9+3,EI30,dB | 1.korrus | 380 | 2060 | 1180 | 2.4308 | 0.174567
 | 1.korrus | 380 | 2060 | 1180 | 2.4308 | 0
2 x SA-XX | 1.korrus | 270 | 1250 | 900 | 1.125 | 0.016686
SU-XX | 1.korrus | 270 | 2030 | 910 | 1.8473 | 0.118209
SU-XX | 1.korrus | 360 | 2100 | 1000 | 2.1 | 0.137428
SU-XX | 1.korrus | 380 | 2300 | 2420 | 5.566 | 0.367884
ava | 1.korrus | 250 | 2305 | 1650 | 3.80325 | 0.950813 | Classification: 1.14 IfcOpeningElement (avaelement) (IPI ÜBN); AC_Pset_RenovationAndPhasing - Renovation Status: Existing
SU-XX | 1.korrus | 25 | 2050 | 615.223 | 1.26121 | 0.0491116
SU-XX | 1.korrus | 100 | 2100 | 950 | 1.995 | 0.089631
SA-XX | 1.korrus | 100 | 1340.05 | 2510 | 3.36352 | 0.0652064
SA-XX | 1.korrus | 100 | 1300 | 1615.92 | 2.1007 | 0.0382837
ava | 1.korrus | 390 |  |  | 5.03168 | 1.96235 | Classification: 1.14 IfcOpeningElement (avaelement) (IPI ÜBN); AC_Pset_RenovationAndPhasing - Renovation Status: Existing
SU-XX | 1.korrus | 190 | 2390 | 2400 | 5.736 | 0.213715
SU-XX | 1.korrus | 120 | 2100 | 900 | 1.89 | 0.120966
SU-XX | 1.korrus | 140 | 2030 | 810.119 | 1.64454 | 0.105894
SU-XX | 1.korrus | 120 | 1755.26 | 835 | 1.46564 | 0.0943725
SU-XX | 1.korrus | 100 | 2100 | 970 | 2.037 | 0.13539
SU-XX | 1.korrus | 100 | 2140 | 700 | 1.498 | 0.0968219
2 x SA-XX | 1.korrus | 100 | 1150 | 865.915 | 0.995803 | 0.0181927
SU-XX | 1.korrus | 100 | 2140 | 850 | 1.819 | 0.116352
2 x SA-XX | 1.korrus | 100 | 1150 | 1200 | 1.38 | 0.02145
SU-XX | 1.korrus | 100 | 2140 | 810 | 1.7334 | 0.111144
2 x VA-XX | 1.korrus | 110 | 920 | 1050 | 0.966 | 0.0153832
ava | 1.korrus | 120 | 2100 | 900 | 1.89 | 0.2268 | Classification: 1.14 IfcOpeningElement (avaelement) (IPI ÜBN); AC_Pset_RenovationAndPhasing - Renovation Status: Existing
ava | 1.korrus | 120 | 2070 | 900 | 1.863 | 0.22356 | Classification: 1.14 IfcOpeningElement (avaelement) (IPI ÜBN); AC_Pset_RenovationAndPhasing - Renovation Status: Existing
 | 1.korrus | 60 | 1720 | 800 | 1.376 | 0.0584339
4 x VA-XX | 1.korrus | 550 | 1160 | 1300 | 1.508 | 0.022848
11 x VA-XX | 1.korrus | 550 | 1160 | 1320 | 1.5312 | 0.02304
 | 1.korrus | 550 | 2480 | 2500 | 6.2 | 0.3192
7 x VA-XX | 1.korrus | 500 | 1150 | 1260 | 1.449 | 0.012116
7 x VA-XX | 1.korrus | 500 | 1090 | 1260 | 1.3734 | 0.011804
2 x VA-XX | 1.korrus | 500 | 1090 | 1260 | 1.3734 | 0.009652
VA-XX | 1.korrus | 500 | 1150 | 1260 | 1.449 | 0.009907
ava | 1.korrus | 500 | 2400 | 1350 | 3.24 | 1.62 | Classification: 1.14 IfcOpeningElement (avaelement) (IPI ÜBN); AC_Pset_RenovationAndPhasing - Renovation Status: Existing
ava | 1.korrus | 320 | 2100 | 850 | 1.785 | 0
ava | 1.korrus | 320 | 2110 | 1010 | 2.1311 | 0
ava | 2.korrus | 147 | 2410 | 3429.12 | 8.26418 | 0
2 x ava | 2.korrus | 147 | 2410 | 2610 | 6.2901 | 0
ava | 2.korrus | 147 | 2410 | 617 | 1.48697 | 0
ava | 2.korrus | 147 | 2410 | 1593 | 3.83913 | 0
2 x NU8 | 2.korrus | 147 | 2110 | 810 | 1.7091 | 0.118714
5 x PU8 | 2.korrus | 147 | 2110 | 810 | 1.7091 | 0.118507
ava | 2.korrus | 147 | 2410 | 6659.5 | 16.0494 | 0
4 x A-2 | 2.korrus | 437 | 2160 | 1590 | 3.4344 | 0.136223
PU10+4 | 2.korrus | 147 | 2110 | 1410 | 2.9751 | 0.153015
27 x A-1g | 2.korrus | 437 | 1910 | 1010 | 1.9291 | 0.053156
AVU5+10+5,EI30 | 2.korrus | 437 | 2310 | 2140 | 4.9434 | 0.0870825
AL-1g,EI30 | 2.korrus | 437 | 1910 | 1010 | 1.9291 | 0.053156
PU10+5,EI30 | 2.korrus | 147 | 2110 | 1510 | 3.1861 | 0.141569
PU6,5+6,5 | 2.korrus | 147 | 2110 | 1310 | 2.7641 | 0.124915
PKU9+9,dB | 2.korrus | 147 | 2110 | 1810 | 3.8191 | 0.0730854
PU10,EI30 | 2.korrus | 147 | 2110 | 1010 | 2.1311 | 0.146504
5 x PKU9+9,dB | 2.korrus | 236 | 2110 | 1810 | 3.8191 | 0.0730854
PKU10,dB | 2.korrus | 236 | 2110 | 1010 | 2.1311 | 0.0644624
SA-06,EI30 | 2.korrus | 147 | 1250 | 1500 | 1.875 | 0.02145
PU10,EI30,dB | 2.korrus | 147 | 2110 | 1010 | 2.1311 | 0.146237
3 x PU10,dB | 2.korrus | 147 | 2110 | 1010 | 2.1311 | 0.146237
PU9x13v,EI30 | 2.korrus | 147 | 1310 | 910 | 1.1921 | 0.0828385
ava | 2.korrus | 147 | 2610 | 3774.1 | 9.85039 | 0
ava | 2.korrus | 147 | 2610 | 3900.21 | 10.1795 | 0
TU9,dB, EI30 | 2.korrus | 190 | 2100 | 910 | 1.911 | 0.0956665
5 x ava | 2.korrus | 10 | 2110 | 810 | 1.7091 | 0
2 x ava | 2.korrus | 10 | 2110 | 800 | 1.688 | 0
ava | 2.korrus | 147 | 2410 | 3062.61 | 7.3809 | 0
PU9v,EI30 | 2.korrus | 147 | 2110 | 910 | 1.9201 | 0.132558
ava | 2.korrus | 400 | 2640 | 1175 | 3.102 | 0
ava | 2.korrus | 400 | 2300 | 1140 | 2.622 | 0
4 x VA-XX | 2.korrus | 300 | 1180 | 2900 | 3.422 | 0.0253
2 x ava | 2.korrus | 300 | 1230 | 2900 | 3.567 | 0
2 x AL-4 | 2.korrus | 300 | 1230 | 2900 | 3.567 | 0.067755
2 x SA-XX | 2.korrus | 400 | 1170 | 1200 | 1.404 | 0
SA-XX | 2.korrus | 400 | 1160 | 1220 | 1.4152 | 0
SA-05,EI60 | 2.korrus | 400 | 1170 | 1200 | 1.4002 | 0.018315
3 x SA-05,EI60 | 2.korrus | 400 | 1170 | 1200 | 1.404 | 0.018315
SA-XX | 2.korrus | 400 | 1170 | 1220 | 1.4274 | 0
ava | 2.korrus | 400 | 2100 | 900 | 1.89 | 0
ava | 2.korrus | 135 |  |  | 0.591894 | 0.0799056 | Classification: 1.14 IfcOpeningElement (avaelement) (IPI ÜBN); AC_Pset_RenovationAndPhasing - Renovation Status: Existing
ava | 2.korrus | 400 |  |  | 10.7103 | 0.511908 | Classification: 1.14 IfcOpeningElement (avaelement) (IPI ÜBN); AC_Pset_RenovationAndPhasing - Renovation Status: Existing
ava | 2.korrus | 110 | 1170 | 505.892 | 0.591894 | 0.0651083 | Classification: 1.14 IfcOpeningElement (avaelement) (IPI ÜBN); AC_Pset_RenovationAndPhasing - Renovation Status: Existing
ava | 2.korrus | 155 |  |  | 0.635964 | 0.0985744 | Classification: 1.14 IfcOpeningElement (avaelement) (IPI ÜBN); AC_Pset_RenovationAndPhasing - Renovation Status: Existing
ava | 2.korrus | 90 |  |  | 0.636145 | 0.057253 | Classification: 1.14 IfcOpeningElement (avaelement) (IPI ÜBN); AC_Pset_RenovationAndPhasing - Renovation Status: Existing
TU10+5,EI30,dB | 2.korrus | 420 | 2110 | 1490 | 3.1439 | 0.155064
2 x AL-2 | 2.korrus | 420 | 1710 | 1510 | 2.5821 | 0.0462305
AL-2,EI60 | 2.korrus | 420 | 1710 | 1510 | 2.5821 | 0.0462305
ava | Pööningukorrus | 200 | 610 | 610 | 0.3721 | 0
VR1 | Pööningukorrus | 437 | 1050 | 1450 | 1.5225 | 0.0228585
TVU8x12,EI30 | Pööningukorrus | 345 | 1210 | 810 | 0.9801 | 0.0721035
TVU10+6x19,EI30 | Pööningukorrus | 345 | 1910 | 1610 | 3.0751 | 0.136379
TVU10+6x18,EI30 | Pööningukorrus | 437 | 1810 | 1610 | 2.9141 | 0.129439
VR2 | Pööningukorrus | 437 | 450 | 1370 | 0.6165 | 0.0130125
TVU7x7,EI30 | Pööningukorrus | 236 | 710 | 710 | 0.5041 | 0.0381935
TVU8 | Pööningukorrus | 200 | 2110 | 810 | 1.7091 | 0.124399
PU7x7 | Pööningukorrus | 163 | 710 | 710 | 0.5041 | 0.0381935
TVU7x7,EI30 | Pööningukorrus | 200 | 710 | 710 | 0.5041 | 0.0381935
ava | Pööningukorrus | 236 | 800 | 2050 | 1.64 | 0
VR3 | Pööningukorrus | 249 | 800 | 2050 | 1.64 | 0.025451

# IfcPlate: 1097 x 458 x 20
In: 1.korrus
Classification: 1.15 IfcPlateType (plaat) (IPI ÜBN); Material: Aluminium
AC_Pset_RenovationAndPhasing - Renovation Status: Undefined
BaseQuantities - Width: 1075 mm; Perimeter: 3006.44 mm; GrossArea: 0.521973 m2; NetArea: 0.460337 m2; GrossVolume: 0.0104395 m3; NetVolume: 0.00920675 m3

# IfcPlate: 1115 x 610 x 20 (12)
In: 1.korrus
Classification: 1.15 IfcPlateType (plaat) (IPI ÜBN); Material: Aluminium
AC_Pset_RenovationAndPhasing - Renovation Status: Undefined
BaseQuantities - Width: 1075 mm; Perimeter: 3290 mm; GrossArea: 0.68015 m2; NetArea: 0.61275 m2; GrossVolume: 0.013603 m3; NetVolume: 0.012255 m3

# IfcPlate: 18 x 11 x 40
In: 1.korrus
Classification: 1.15 IfcPlateType (plaat) (IPI ÜBN); Material: Klaas
BaseQuantities - Width: 0 mm; Perimeter: 0 mm; GrossArea: 0.0000934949 m2; NetArea: 0 m2; GrossVolume: 0.00000373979 m3; NetVolume: 0 m3
AC_Pset_RenovationAndPhasing - Renovation Status: Undefined

# IfcPlate: 20 (4)
In: 1.korrus
Classification: 1.15 IfcPlateType (plaat) (IPI ÜBN); Material: Aluminium
AC_Pset_RenovationAndPhasing - Renovation Status: Undefined
BaseQuantities - Width: 1075 mm
Name | Perimeter (mm) | GrossArea (m2) | NetArea (m2) | GrossVolume (m3) | NetVolume (m3)
2 x  | 3270.31 | 0.509681 | 0.442454 | 0.0101936 | 0.00884907
2 x  | 3252.85 | 0.4999 | 0.433021 | 0.00999799 | 0.00866043

# IfcPlate: 23 x 332 x 150
In: 1.korrus
Classification: 1.15 IfcPlateType (plaat) (IPI ÜBN); Material: Aluminium
BaseQuantities - Width: 1075 mm; Perimeter: 3051.59 mm; GrossArea: 0.391127 m2; NetArea: 0.328445 m2; GrossVolume: 0.058669 m3; NetVolume: 0.0492667 m3
AC_Pset_RenovationAndPhasing - Renovation Status: Undefined
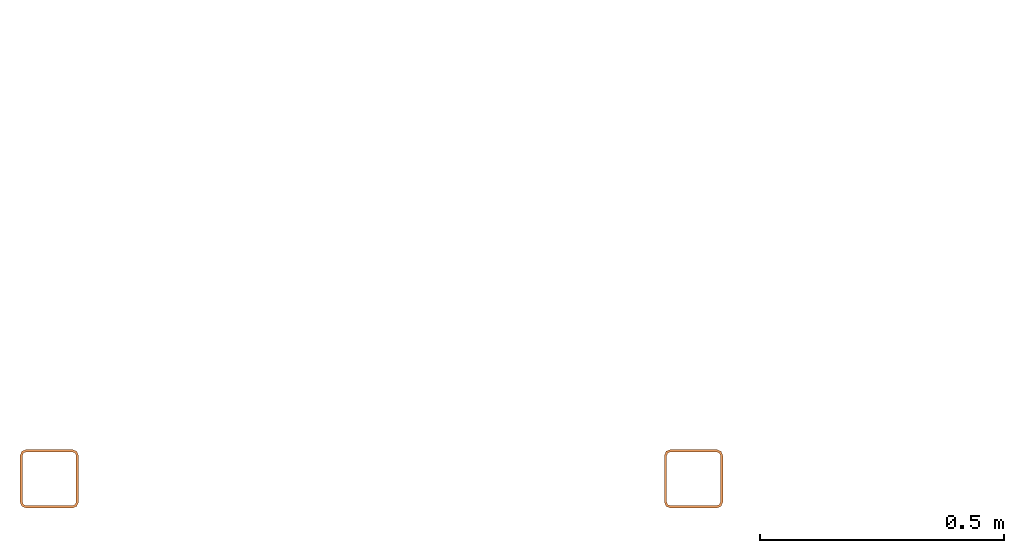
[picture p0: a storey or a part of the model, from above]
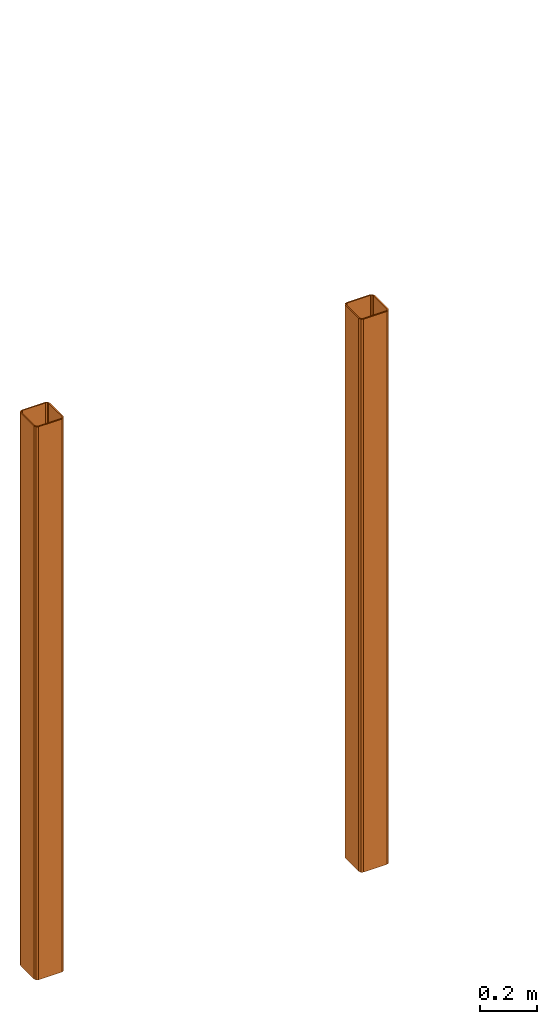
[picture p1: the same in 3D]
Properties of the parts of a building model (IFC2X3), part 5 of 7

# IfcPlate: 279 x 353 x 150
In: 1.korrus
Classification: 1.15 IfcPlateType (plaat) (IPI ÜBN); Material: Aluminium
BaseQuantities - Width: 239.153 mm; Perimeter: 1104.53 mm; GrossArea: 0.0985728 m2; NetArea: 0.0748821 m2; GrossVolume: 0.0147859 m3; NetVolume: 0.0112323 m3
AC_Pset_RenovationAndPhasing - Renovation Status: Undefined

# IfcPlate: 361 x 252 x 20
In: 1.korrus
Classification: 1.15 IfcPlateType (plaat) (IPI ÜBN); Material: Aluminium
BaseQuantities - Width: 1075 mm; Perimeter: 3023.84 mm; GrossArea: 0.464491 m2; NetArea: 0.402364 m2; GrossVolume: 0.00928983 m3; NetVolume: 0.00804729 m3
AC_Pset_RenovationAndPhasing - Renovation Status: Undefined

# IfcPlate: 454 x 247 x 20
In: 1.korrus
Classification: 1.15 IfcPlateType (plaat) (IPI ÜBN); Material: Aluminium
BaseQuantities - Width: 355.064 mm; Perimeter: 952.259 mm; GrossArea: 0.0559628 m2; NetArea: 0.0342717 m2; GrossVolume: 0.00111926 m3; NetVolume: 0.000685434 m3
AC_Pset_RenovationAndPhasing - Renovation Status: Undefined

# IfcPlate: 5 x 347 x 150
In: 1.korrus
Classification: 1.15 IfcPlateType (plaat) (IPI ÜBN); Material: Aluminium
BaseQuantities - Width: 1075 mm; Perimeter: 3058.41 mm; GrossArea: 0.394582 m2; NetArea: 0.328469 m2; GrossVolume: 0.0591873 m3; NetVolume: 0.0492703 m3
AC_Pset_RenovationAndPhasing - Renovation Status: Undefined

# IfcPlate: 841 x 457 x 20
In: 1.korrus
Classification: 1.15 IfcPlateType (plaat) (IPI ÜBN); Material: Aluminium
AC_Pset_RenovationAndPhasing - Renovation Status: Undefined
BaseQuantities - Width: 1001.67 mm; Perimeter: 2587.15 mm; GrossArea: 0.310786 m2; NetArea: 0.256457 m2; GrossVolume: 0.00621572 m3; NetVolume: 0.00512915 m3

# IfcPlate: 964 x 610 x 20
In: 1.korrus
Classification: 1.15 IfcPlateType (plaat) (IPI ÜBN); Material: Aluminium
AC_Pset_RenovationAndPhasing - Renovation Status: Undefined
BaseQuantities - Width: 924.419 mm; Perimeter: 2988.84 mm; GrossArea: 0.588295 m2; NetArea: 0.526919 m2; GrossVolume: 0.0117659 m3; NetVolume: 0.0105384 m3

# IfcPlate: Distinct Panel 150 (2)
In: 1.korrus
Classification: 1.15 IfcPlateType (plaat) (IPI ÜBN); Material: Aluminium
BaseQuantities - Width: 1075 mm; Perimeter: 3058.41 mm; GrossArea: 0.391458 m2; NetArea: 0.328469 m2; GrossVolume: 0.0587187 m3; NetVolume: 0.0492703 m3
AC_Pset_RenovationAndPhasing - Renovation Status: Undefined

# IfcPlate: Distinct Panel 182 x 252 x 150
In: 1.korrus
Classification: 1.15 IfcPlateType (plaat) (IPI ÜBN); Material: Aluminium
BaseQuantities - Width: 1075 mm; Perimeter: 2951.15 mm; GrossArea: 0.382418 m2; NetArea: 0.321745 m2; GrossVolume: 0.0573627 m3; NetVolume: 0.0482617 m3
AC_Pset_RenovationAndPhasing - Renovation Status: Undefined

# IfcPlate: Distinct Panel 34 x 5 x 150
In: 1.korrus
Classification: 1.15 IfcPlateType (plaat) (IPI ÜBN); Material: Aluminium
BaseQuantities - Width: 540.847 mm; Perimeter: 1809.39 mm; GrossArea: 0.205711 m2; NetArea: 0.17017 m2; GrossVolume: 0.0308567 m3; NetVolume: 0.0255254 m3
AC_Pset_RenovationAndPhasing - Renovation Status: Undefined

# IfcPlate: Main Panel 1 x 3250 x 40, AKU10+4,EI30
In: 2.korrus
Classification: 1.15 IfcPlateType (plaat) (IPI ÜBN); Material: Klaas
AR_ÜLD - 001_Nimetus: AKU10+4,EI30
BaseQuantities - Width: 745.897 mm; Perimeter: 7911.79 mm; GrossArea: 2.54532 m2; NetArea: 2.38548 m2; GrossVolume: 0.101813 m3; NetVolume: 0.0954192 m3
AC_Pset_RenovationAndPhasing - Renovation Status: Undefined

# IfcPlate: Main Panel 1038 x 275 x 30
In: 2.korrus
Classification: 1.15 IfcPlateType (plaat) (IPI ÜBN); Material: Klaas
BaseQuantities - Width: 1716.3 mm; Perimeter: 8072.6 mm; GrossArea: 4.10381 m2; NetArea: 3.98182 m2; GrossVolume: 0.123114 m3; NetVolume: 0.119455 m3
AC_Pset_RenovationAndPhasing - Renovation Status: Undefined

# IfcPlate: Main Panel 106 x 175 x 30
In: 2.korrus
Classification: 1.15 IfcPlateType (plaat) (IPI ÜBN); Material: Klaas
BaseQuantities - Width: 441.047 mm; Perimeter: 5922.09 mm; GrossArea: 1.20117 m2; NetArea: 1.11144 m2; GrossVolume: 0.0360351 m3; NetVolume: 0.0333431 m3
AC_Pset_RenovationAndPhasing - Renovation Status: Undefined

# IfcPlate: Main Panel 1069 x 25 x 40
In: 1.korrus
Classification: 1.15 IfcPlateType (plaat) (IPI ÜBN); Material: Klaas
AC_Pset_RenovationAndPhasing - Renovation Status: Undefined
BaseQuantities - Width: 1049.3 mm; Perimeter: 3068.61 mm; GrossArea: 0.558884 m2; NetArea: 0.496912 m2; GrossVolume: 0.0223554 m3; NetVolume: 0.0198765 m3

# IfcPlate: Main Panel 1081 x 1750 x 20
In: 1.korrus
Classification: 1.15 IfcPlateType (plaat) (IPI ÜBN); Material: Klaas
AC_Pset_RenovationAndPhasing - Renovation Status: Undefined
BaseQuantities - Width: 1193.3 mm; Perimeter: 5985.42 mm; GrossArea: 2.23253 m2; NetArea: 2.14185 m2; GrossVolume: 0.0446506 m3; NetVolume: 0.0428369 m3

# IfcPlate: Main Panel 1081 x 2055 x 20
In: 1.korrus
Classification: 1.15 IfcPlateType (plaat) (IPI ÜBN); Material: Klaas
AC_Pset_RenovationAndPhasing - Renovation Status: Undefined
BaseQuantities - Width: 1193.3 mm; Perimeter: 6436.6 mm; GrossArea: 2.51388 m2; NetArea: 2.41643 m2; GrossVolume: 0.0502775 m3; NetVolume: 0.0483286 m3

# IfcPlate: Main Panel 1115 x 1016 x 20
In: 1.korrus
Classification: 1.15 IfcPlateType (plaat) (IPI ÜBN); Material: Klaas
BaseQuantities - Width: 1075 mm; Perimeter: 4850.7 mm; GrossArea: 1.47047 m2; NetArea: 1.37175 m2; GrossVolume: 0.0294095 m3; NetVolume: 0.027435 m3
AC_Pset_RenovationAndPhasing - Renovation Status: Undefined

# IfcPlate: Main Panel 1115 x 1340 x 20
In: 1.korrus
Classification: 1.15 IfcPlateType (plaat) (IPI ÜBN); Material: Klaas
AC_Pset_RenovationAndPhasing - Renovation Status: Undefined
BaseQuantities - Width: 1075 mm; Perimeter: 4790 mm; GrossArea: 1.5165 m2; NetArea: 1.419 m2; GrossVolume: 0.03033 m3; NetVolume: 0.02838 m3

# IfcPlate: Main Panel 1115 x 1341 x 40
In: 1.korrus
Classification: 1.15 IfcPlateType (plaat) (IPI ÜBN); Material: Klaas
BaseQuantities - Width: 1075 mm; Perimeter: 4792.9 mm; GrossArea: 1.49572 m2; NetArea: 1.42056 m2; GrossVolume: 0.0598286 m3; NetVolume: 0.0568223 m3
AC_Pset_RenovationAndPhasing - Renovation Status: Undefined

# IfcPlate: Main Panel 1115 x 1346 x 20
In: 1.korrus
Classification: 1.15 IfcPlateType (plaat) (IPI ÜBN); Material: Klaas
AC_Pset_RenovationAndPhasing - Renovation Status: Undefined
BaseQuantities - Width: 1075 mm; Perimeter: 4762.9 mm; GrossArea: 1.50129 m2; NetArea: 1.40444 m2; GrossVolume: 0.0300259 m3; NetVolume: 0.0280887 m3

# IfcPlate: Main Panel 1115 x 1351 x 20
In: 1.korrus
Classification: 1.15 IfcPlateType (plaat) (IPI ÜBN); Material: Klaas
BaseQuantities - Width: 1075 mm; Perimeter: 4312.46 mm; GrossArea: 1.17042 m2; NetArea: 1.08246 m2; GrossVolume: 0.0234085 m3; NetVolume: 0.0216493 m3
AC_Pset_RenovationAndPhasing - Renovation Status: Undefined

# IfcPlate: Main Panel 1115 x 1360 x 20
In: 1.korrus
Classification: 1.15 IfcPlateType (plaat) (IPI ÜBN); Material: Klaas
AC_Pset_RenovationAndPhasing - Renovation Status: Undefined
BaseQuantities - Width: 1075 mm; Perimeter: 4790 mm; GrossArea: 1.5164 m2; NetArea: 1.419 m2; GrossVolume: 0.030328 m3; NetVolume: 0.02838 m3

# IfcPlate: Main Panel 1115 x 1365 x 20
In: 1.korrus
Classification: 1.15 IfcPlateType (plaat) (IPI ÜBN); Material: Klaas
BaseQuantities - Width: 1075 mm; Perimeter: 8803.6 mm; GrossArea: 3.79665 m2; NetArea: 3.61904 m2; GrossVolume: 0.0759331 m3; NetVolume: 0.0723808 m3
AC_Pset_RenovationAndPhasing - Renovation Status: Undefined

# IfcPlate: Main Panel 1115 x 1495 x 20
In: 1.korrus
Classification: 1.15 IfcPlateType (plaat) (IPI ÜBN); Material: Klaas
BaseQuantities - Width: 1075 mm; Perimeter: 8590 mm; GrossArea: 3.6349 m2; NetArea: 3.4615 m2; GrossVolume: 0.072698 m3; NetVolume: 0.06923 m3
AC_Pset_RenovationAndPhasing - Renovation Status: Undefined

# IfcPlate: Main Panel 1115 x 1625 x 20
In: 1.korrus
Classification: 1.15 IfcPlateType (plaat) (IPI ÜBN); Material: Klaas
AC_Pset_RenovationAndPhasing - Renovation Status: Undefined
BaseQuantities - Width: 1075 mm; Perimeter: 5320.66 mm; GrossArea: 1.81224 m2; NetArea: 1.70423 m2; GrossVolume: 0.0362448 m3; NetVolume: 0.0340846 m3

# IfcPlate: Main Panel 1115 x 1627 x 20
In: 1.korrus
Classification: 1.15 IfcPlateType (plaat) (IPI ÜBN); Material: Klaas
BaseQuantities - Width: 1075 mm; Perimeter: 6073.87 mm; GrossArea: 2.15241 m2; NetArea: 2.02923 m2; GrossVolume: 0.0430483 m3; NetVolume: 0.0405845 m3
AC_Pset_RenovationAndPhasing - Renovation Status: Undefined

# IfcPlate: Main Panel 1115 x 1755 x 20
In: 1.korrus
Classification: 1.15 IfcPlateType (plaat) (IPI ÜBN); Material: Klaas
BaseQuantities - Width: 1075 mm; Perimeter: 5580 mm; GrossArea: 1.95683 m2; NetArea: 1.84362 m2; GrossVolume: 0.0391365 m3; NetVolume: 0.0368725 m3
AC_Pset_RenovationAndPhasing - Renovation Status: Undefined

# IfcPlate: Main Panel 1115 x 1760 x 20
In: 1.korrus
Classification: 1.15 IfcPlateType (plaat) (IPI ÜBN); Material: Klaas
BaseQuantities - Width: 1075 mm; Perimeter: 5590 mm; GrossArea: 1.9624 m2; NetArea: 1.849 m2; GrossVolume: 0.039248 m3; NetVolume: 0.03698 m3
AC_Pset_RenovationAndPhasing - Renovation Status: Undefined

# IfcPlate: Main Panel 1115 x 1973 x 20
In: 1.korrus
Classification: 1.15 IfcPlateType (plaat) (IPI ÜBN); Material: Klaas
BaseQuantities - Width: 1075 mm; Perimeter: 5553.25 mm; GrossArea: 1.86214 m2; NetArea: 1.74937 m2; GrossVolume: 0.0372429 m3; NetVolume: 0.0349874 m3
AC_Pset_RenovationAndPhasing - Renovation Status: Undefined

# IfcPlate: Main Panel 1115 x 2239 x 20
In: 1.korrus
Classification: 1.15 IfcPlateType (plaat) (IPI ÜBN); Material: Klaas
AC_Pset_RenovationAndPhasing - Renovation Status: Undefined
BaseQuantities - Width: 1075 mm; Perimeter: 7296.99 mm; GrossArea: 2.8343 m2; NetArea: 2.68665 m2; GrossVolume: 0.056686 m3; NetVolume: 0.053733 m3

# IfcPlate: Main Panel 1115 x 245 x 40
In: 1.korrus
Classification: 1.15 IfcPlateType (plaat) (IPI ÜBN); Material: Klaas
BaseQuantities - Width: 1075 mm; Perimeter: 8970 mm; GrossArea: 3.84675 m2; NetArea: 3.66575 m2; GrossVolume: 0.15387 m3; NetVolume: 0.14663 m3
AC_Pset_RenovationAndPhasing - Renovation Status: Undefined

# IfcPlate: Main Panel 1115 x 2575 x 40
In: 1.korrus
Classification: 1.15 IfcPlateType (plaat) (IPI ÜBN); Material: Klaas
BaseQuantities - Width: 1075 mm; Perimeter: 6756.72 mm; GrossArea: 2.53306 m2; NetArea: 2.39621 m2; GrossVolume: 0.101322 m3; NetVolume: 0.0958485 m3
AC_Pset_RenovationAndPhasing - Renovation Status: Undefined

# IfcPlate: Main Panel 1115 x 2585 x 20
In: 1.korrus
Classification: 1.15 IfcPlateType (plaat) (IPI ÜBN); Material: Klaas
BaseQuantities - Width: 1075 mm; Perimeter: 6776.56 mm; GrossArea: 2.54414 m2; NetArea: 2.40689 m2; GrossVolume: 0.0508827 m3; NetVolume: 0.0481379 m3
AC_Pset_RenovationAndPhasing - Renovation Status: Undefined

# IfcPlate: Main Panel 1115 x 3187 x 40
In: 1.korrus
Classification: 1.15 IfcPlateType (plaat) (IPI ÜBN); Material: Klaas
BaseQuantities - Width: 1075 mm; Perimeter: 7980.19 mm; GrossArea: 3.21514 m2; NetArea: 3.05383 m2; GrossVolume: 0.128606 m3; NetVolume: 0.122153 m3
AC_Pset_RenovationAndPhasing - Renovation Status: Undefined

# IfcPlate: Main Panel 1115 x 3196 x 20
In: 1.korrus
Classification: 1.15 IfcPlateType (plaat) (IPI ÜBN); Material: Klaas
AC_Pset_RenovationAndPhasing - Renovation Status: Undefined
BaseQuantities - Width: 1075 mm; Perimeter: 7999.86 mm; GrossArea: 3.22613 m2; NetArea: 3.06442 m2; GrossVolume: 0.0645226 m3; NetVolume: 0.0612884 m3

# IfcPlate: Main Panel 1115 x 3250 x 40 (2)
In: 2.korrus
Classification: 1.15 IfcPlateType (plaat) (IPI ÜBN); Material: Klaas
BaseQuantities - Width: 1075 mm; Perimeter: 8570 mm; GrossArea: 3.62375 m2; NetArea: 3.45075 m2; GrossVolume: 0.14495 m3; NetVolume: 0.13803 m3
AC_Pset_RenovationAndPhasing - Renovation Status: Undefined

# IfcPlate: Main Panel 1115 x 3260 x 20 (10)
In: 1.korrus
Classification: 1.15 IfcPlateType (plaat) (IPI ÜBN); Material: Klaas
BaseQuantities - Width: 1075 mm; Perimeter: 8590 mm; GrossArea: 3.6349 m2; NetArea: 3.4615 m2; GrossVolume: 0.072698 m3; NetVolume: 0.06923 m3
AC_Pset_RenovationAndPhasing - Renovation Status: Undefined

# IfcPlate: Main Panel 1115 x 3460 x 20
In: 1.korrus
Classification: 1.15 IfcPlateType (plaat) (IPI ÜBN); Material: Klaas
BaseQuantities - Width: 1075 mm; Perimeter: 8990 mm; GrossArea: 3.8579 m2; NetArea: 3.6765 m2; GrossVolume: 0.077158 m3; NetVolume: 0.07353 m3
AC_Pset_RenovationAndPhasing - Renovation Status: Undefined

# IfcPlate: Main Panel 1115 x 383 x 20
In: 1.korrus
Classification: 1.15 IfcPlateType (plaat) (IPI ÜBN); Material: Klaas
BaseQuantities - Width: 1075 mm; Perimeter: 3627.4 mm; GrossArea: 0.788481 m2; NetArea: 0.714223 m2; GrossVolume: 0.0157696 m3; NetVolume: 0.0142845 m3
AC_Pset_RenovationAndPhasing - Renovation Status: Undefined

# IfcPlate: Main Panel 1115 x 622 x 40
In: 1.korrus
Classification: 1.15 IfcPlateType (plaat) (IPI ÜBN); Material: Klaas
BaseQuantities - Width: 1075 mm; Perimeter: 2890.35 mm; GrossArea: 0.355254 m2; NetArea: 0.318036 m2; GrossVolume: 0.0142101 m3; NetVolume: 0.0127214 m3
AC_Pset_RenovationAndPhasing - Renovation Status: Undefined

# IfcPlate: Main Panel 1115 x 741 x 20
In: 1.korrus
Classification: 1.15 IfcPlateType (plaat) (IPI ÜBN); Material: Klaas
BaseQuantities - Width: 1075 mm; Perimeter: 3089.34 mm; GrossArea: 0.488537 m2; NetArea: 0.42504 m2; GrossVolume: 0.00977075 m3; NetVolume: 0.0085008 m3
AC_Pset_RenovationAndPhasing - Renovation Status: Undefined

# IfcPlate: Main Panel 1115 x 950 x 40
In: 2.korrus
Classification: 1.15 IfcPlateType (plaat) (IPI ÜBN); Material: Klaas
AC_Pset_RenovationAndPhasing - Renovation Status: Undefined
BaseQuantities - Width: 1075 mm; Perimeter: 8560 mm; GrossArea: 3.61817 m2; NetArea: 3.44537 m2; GrossVolume: 0.144727 m3; NetVolume: 0.137815 m3

# IfcPlate: Main Panel 1120 x 750 x 20
In: 1.korrus
Classification: 1.15 IfcPlateType (plaat) (IPI ÜBN); Material: Klaas
AC_Pset_RenovationAndPhasing - Renovation Status: Undefined
BaseQuantities - Width: 1075 mm; Perimeter: 4320.1 mm; GrossArea: 1.17479 m2; NetArea: 1.08657 m2; GrossVolume: 0.0234957 m3; NetVolume: 0.0217315 m3

# IfcPlate: Main Panel 1121 x 175 x 30, PKU10,dB
In: 2.korrus
Classification: 1.15 IfcPlateType (plaat) (IPI ÜBN); Material: Klaas
AR_ÜLD - 001_Nimetus: PKU10,dB
AC_Pset_RenovationAndPhasing - Renovation Status: Undefined
BaseQuantities - Width: 1086.12 mm; Perimeter: 7212.24 mm; GrossArea: 2.84618 m2; NetArea: 2.73702 m2; GrossVolume: 0.0853853 m3; NetVolume: 0.0821105 m3

# IfcPlate: Main Panel 1127 x 175 x 30, PKU10,dB
In: 2.korrus
Classification: 1.15 IfcPlateType (plaat) (IPI ÜBN); Material: Klaas
AR_ÜLD - 001_Nimetus: PKU10,dB
AC_Pset_RenovationAndPhasing - Renovation Status: Undefined
BaseQuantities - Width: 1096.52 mm; Perimeter: 7233.05 mm; GrossArea: 2.87264 m2; NetArea: 2.76324 m2; GrossVolume: 0.0861791 m3; NetVolume: 0.0828972 m3

# IfcPlate: Main Panel 1205 x 275 x 30
In: 2.korrus
Classification: 1.15 IfcPlateType (plaat) (IPI ÜBN); Material: Klaas
AC_Pset_RenovationAndPhasing - Renovation Status: Undefined
BaseQuantities - Width: 1174.56 mm; Perimeter: 6989.12 mm; GrossArea: 2.83072 m2; NetArea: 2.72498 m2; GrossVolume: 0.0849215 m3; NetVolume: 0.0817494 m3

# IfcPlate: Main Panel 1220 x 2055 x 20
In: 1.korrus
Classification: 1.15 IfcPlateType (plaat) (IPI ÜBN); Material: Klaas
AC_Pset_RenovationAndPhasing - Renovation Status: Undefined
BaseQuantities - Width: 1190.07 mm; Perimeter: 6430.15 mm; GrossArea: 2.50725 m2; NetArea: 2.4099 m2; GrossVolume: 0.0501451 m3; NetVolume: 0.048198 m3

# IfcPlate: Main Panel 1220 x 981 x 20
In: 1.korrus
Classification: 1.15 IfcPlateType (plaat) (IPI ÜBN); Material: Klaas
AC_Pset_RenovationAndPhasing - Renovation Status: Undefined
BaseQuantities - Width: 1190.07 mm; Perimeter: 4440.69 mm; GrossArea: 1.28825 m2; NetArea: 1.22074 m2; GrossVolume: 0.025765 m3; NetVolume: 0.0244147 m3

# IfcPlate: Main Panel 1265 x 1875 x 20 (2)
In: 1.korrus
Classification: 1.15 IfcPlateType (plaat) (IPI ÜBN); Material: Klaas
AC_Pset_RenovationAndPhasing - Renovation Status: Undefined
Name | Width (mm) | Perimeter (mm) | GrossArea (m2) | NetArea (m2) | GrossVolume (m3) | NetVolume (m3)
 | 1235 | 6160 | 2.37187 | 2.27858 | 0.0474375 | 0.0455715
 | 1234.95 | 6159.9 | 2.37178 | 2.27848 | 0.0474356 | 0.0455697

# IfcPlate: Main Panel 1265 x 95 x 20 (2)
In: 1.korrus
Classification: 1.15 IfcPlateType (plaat) (IPI ÜBN); Material: Klaas
AC_Pset_RenovationAndPhasing - Renovation Status: Undefined
Name | Width (mm) | Perimeter (mm) | GrossArea (m2) | NetArea (m2) | GrossVolume (m3) | NetVolume (m3)
 | 1235 | 6580 | 2.63753 | 2.53793 | 0.0527505 | 0.0507585
 | 1234.95 | 6579.9 | 2.63742 | 2.53782 | 0.0527484 | 0.0507565

# IfcPlate: Main Panel 133 x 270 x 30 (2)
In: 2.korrus
Classification: 1.15 IfcPlateType (plaat) (IPI ÜBN); Material: Klaas
AC_Pset_RenovationAndPhasing - Renovation Status: Undefined
BaseQuantities - Width: 960 mm; Perimeter: 2400 mm; GrossArea: 0.2673 m2; NetArea: 0.2304 m2; GrossVolume: 0.008019 m3; NetVolume: 0.006912 m3

# IfcPlate: Main Panel 1360 x 2600 x 40, AVU10
In: 1.korrus
Classification: 1.15 IfcPlateType (plaat) (IPI ÜBN); Material: Klaas
BaseQuantities - Width: 1905.09 mm; Perimeter: 8930.18 mm; GrossArea: 4.99236 m2; NetArea: 4.81316 m2; GrossVolume: 0.199694 m3; NetVolume: 0.192526 m3
AC_Pset_RenovationAndPhasing - Renovation Status: Undefined
AR_ÜLD - 001_Nimetus: AVU10

# IfcPlate: Main Panel 14 x 7 x 40
In: 1.korrus
Classification: 1.15 IfcPlateType (plaat) (IPI ÜBN); Material: Klaas
BaseQuantities - Width: 0 mm; Perimeter: 0 mm; GrossArea: 0.0000496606 m2; NetArea: 0 m2; GrossVolume: 0.00000198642 m3; NetVolume: 0 m3
AC_Pset_RenovationAndPhasing - Renovation Status: Undefined

# IfcPlate: Main Panel 15 x 2485 x 20 (2)
In: 1.korrus
Classification: 1.15 IfcPlateType (plaat) (IPI ÜBN); Material: Klaas
AC_Pset_RenovationAndPhasing - Renovation Status: Undefined
BaseQuantities - Width: 0 mm; Perimeter: 0 mm; NetArea: 0 m2; NetVolume: 0 m3
Name | GrossArea (m2) | GrossVolume (m3)
 | 0.037153 | 0.00074306
 | 0.0371639 | 0.000743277

# IfcPlate: Main Panel 1517 x 2075 x 30, PKU10,dB
In: 2.korrus
Classification: 1.15 IfcPlateType (plaat) (IPI ÜBN); Material: Klaas
AR_ÜLD - 001_Nimetus: PKU10,dB
AC_Pset_RenovationAndPhasing - Renovation Status: Undefined
BaseQuantities - Width: 1714.61 mm; Perimeter: 7549.21 mm; GrossArea: 3.61998 m2; NetArea: 3.53209 m2; GrossVolume: 0.108599 m3; NetVolume: 0.105963 m3

# IfcPlate: Main Panel 1517 x 275 x 30
In: 2.korrus
Classification: 1.15 IfcPlateType (plaat) (IPI ÜBN); Material: Klaas
AC_Pset_RenovationAndPhasing - Renovation Status: Undefined
BaseQuantities - Width: 1714.61 mm; Perimeter: 3949.21 mm; GrossArea: 0.479692 m2; NetArea: 0.445798 m2; GrossVolume: 0.0143908 m3; NetVolume: 0.0133739 m3

# IfcPlate: Main Panel 1659 x 2600 x 40
In: 1.korrus
Classification: 1.15 IfcPlateType (plaat) (IPI ÜBN); Material: Klaas
BaseQuantities - Width: 1619.12 mm; Perimeter: 8358.24 mm; GrossArea: 4.31371 m2; NetArea: 4.14495 m2; GrossVolume: 0.172548 m3; NetVolume: 0.165798 m3
AC_Pset_RenovationAndPhasing - Renovation Status: Undefined

# IfcPlate: Main Panel 168 x 175 x 30, PKU10,dB
In: 2.korrus
Classification: 1.15 IfcPlateType (plaat) (IPI ÜBN); Material: Klaas
AR_ÜLD - 001_Nimetus: PKU10,dB
AC_Pset_RenovationAndPhasing - Renovation Status: Undefined
BaseQuantities - Width: 566.161 mm; Perimeter: 6172.32 mm; GrossArea: 1.52021 m2; NetArea: 1.42673 m2; GrossVolume: 0.0456063 m3; NetVolume: 0.0428018 m3

# IfcPlate: Main Panel 1980 x 2600 x 40
In: 1.korrus
Classification: 1.15 IfcPlateType (plaat) (IPI ÜBN); Material: Klaas
BaseQuantities - Width: 1940 mm; Perimeter: 9000 mm; GrossArea: 5.148 m2; NetArea: 4.9664 m2; GrossVolume: 0.20592 m3; NetVolume: 0.198656 m3
AC_Pset_RenovationAndPhasing - Renovation Status: Undefined

# IfcPlate: Main Panel 20 x 11 x 40
In: 1.korrus
Classification: 1.15 IfcPlateType (plaat) (IPI ÜBN); Material: Klaas
BaseQuantities - Width: 0 mm; Perimeter: 0 mm; GrossArea: 0.000105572 m2; NetArea: 0 m2; GrossVolume: 0.00000422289 m3; NetVolume: 0 m3
AC_Pset_RenovationAndPhasing - Renovation Status: Undefined

# IfcPlate: Main Panel 224 x 3250 x 40
In: 2.korrus
Classification: 1.15 IfcPlateType (plaat) (IPI ÜBN); Material: Klaas
AC_Pset_RenovationAndPhasing - Renovation Status: Undefined
BaseQuantities - Width: 184.091 mm; Perimeter: 6788.18 mm; GrossArea: 0.728294 m2; NetArea: 0.590931 m2; GrossVolume: 0.0291318 m3; NetVolume: 0.0236372 m3

# IfcPlate: Main Panel 239 x 130 x 20
In: 1.korrus
Classification: 1.15 IfcPlateType (plaat) (IPI ÜBN); Material: Klaas
BaseQuantities - Width: 139.839 mm; Perimeter: 375.021 mm; GrossArea: 0.0154615 m2; NetArea: 0.00531506 m2; GrossVolume: 0.000309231 m3; NetVolume: 0.000106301 m3
AC_Pset_RenovationAndPhasing - Renovation Status: Undefined

# IfcPlate: Main Panel 248 x 2350 x 30
In: 2.korrus
Classification: 1.15 IfcPlateType (plaat) (IPI ÜBN); Material: Klaas
AC_Pset_RenovationAndPhasing - Renovation Status: Undefined
BaseQuantities - Width: 1154.56 mm; Perimeter: 6949.12 mm; GrossArea: 2.78372 m2; NetArea: 2.67858 m2; GrossVolume: 0.0835115 m3; NetVolume: 0.0803574 m3

# IfcPlate: Main Panel 279 x 1338 x 40
In: 1.korrus
Classification: 1.15 IfcPlateType (plaat) (IPI ÜBN); Material: Klaas
BaseQuantities - Width: 239.153 mm; Perimeter: 3073.38 mm; GrossArea: 0.373377 m2; NetArea: 0.31031 m2; GrossVolume: 0.0149351 m3; NetVolume: 0.0124124 m3
AC_Pset_RenovationAndPhasing - Renovation Status: Undefined

# IfcPlate: Main Panel 313 x 2485 x 20
In: 1.korrus
Classification: 1.15 IfcPlateType (plaat) (IPI ÜBN); Material: Klaas
AC_Pset_RenovationAndPhasing - Renovation Status: Undefined
BaseQuantities - Width: 1940 mm; Perimeter: 8790 mm; GrossArea: 4.89545 m2; NetArea: 4.7627 m2; GrossVolume: 0.097909 m3; NetVolume: 0.095254 m3

# IfcPlate: Main Panel 317 x 2485 x 20
In: 1.korrus
Classification: 1.15 IfcPlateType (plaat) (IPI ÜBN); Material: Klaas
AC_Pset_RenovationAndPhasing - Renovation Status: Undefined
BaseQuantities - Width: 1953.09 mm; Perimeter: 8816.17 mm; GrossArea: 4.92797 m2; NetArea: 4.79483 m2; GrossVolume: 0.0985594 m3; NetVolume: 0.0958966 m3

# IfcPlate: Main Panel 322 x 1288 x 20
In: 1.korrus
Classification: 1.15 IfcPlateType (plaat) (IPI ÜBN); Material: Klaas
AC_Pset_RenovationAndPhasing - Renovation Status: Undefined
BaseQuantities - Width: 1193.38 mm; Perimeter: 5063.08 mm; GrossArea: 1.66839 m2; NetArea: 1.59154 m2; GrossVolume: 0.0333678 m3; NetVolume: 0.0318308 m3

# IfcPlate: Main Panel 322 x 2055 x 20
In: 1.korrus
Classification: 1.15 IfcPlateType (plaat) (IPI ÜBN); Material: Klaas
AC_Pset_RenovationAndPhasing - Renovation Status: Undefined
BaseQuantities - Width: 1193.38 mm; Perimeter: 6436.76 mm; GrossArea: 2.51404 m2; NetArea: 2.41659 m2; GrossVolume: 0.0502808 m3; NetVolume: 0.0483318 m3

# IfcPlate: Main Panel 323 x 2485 x 20
In: 1.korrus
Classification: 1.15 IfcPlateType (plaat) (IPI ÜBN); Material: Klaas
BaseQuantities - Width: 1946.14 mm; Perimeter: 8802.29 mm; GrossArea: 4.91072 m2; NetArea: 4.77778 m2; GrossVolume: 0.0982143 m3; NetVolume: 0.0955556 m3
AC_Pset_RenovationAndPhasing - Renovation Status: Undefined

# IfcPlate: Main Panel 327 x 2485 x 20
In: 1.korrus
Classification: 1.15 IfcPlateType (plaat) (IPI ÜBN); Material: Klaas
AC_Pset_RenovationAndPhasing - Renovation Status: Undefined
BaseQuantities - Width: 1939.99 mm; Perimeter: 8789.98 mm; GrossArea: 4.89542 m2; NetArea: 4.76267 m2; GrossVolume: 0.0979085 m3; NetVolume: 0.0952535 m3

# IfcPlate: Main Panel 330 x 1100 x 40, AU10+3,EI30
In: 1.korrus
Classification: 1.15 IfcPlateType (plaat) (IPI ÜBN); Material: Klaas
BaseQuantities - Width: 1410 mm; Perimeter: 4939.24 mm; GrossArea: 1.59445 m2; NetArea: 1.49407 m2; GrossVolume: 0.063778 m3; NetVolume: 0.0597626 m3
AC_Pset_RenovationAndPhasing - Renovation Status: Undefined
AR_ÜLD - 001_Nimetus: AU10+3,EI30

# IfcPlate: Main Panel 336 x 175 x 30, PKU10,dB
In: 2.korrus
Classification: 1.15 IfcPlateType (plaat) (IPI ÜBN); Material: Klaas
AR_ÜLD - 001_Nimetus: PKU10,dB
BaseQuantities - Width: 1076.52 mm; Perimeter: 7193.05 mm; GrossArea: 2.82201 m2; NetArea: 2.71284 m2; GrossVolume: 0.0846603 m3; NetVolume: 0.0813852 m3
AC_Pset_RenovationAndPhasing - Renovation Status: Undefined

# IfcPlate: Main Panel 339 x 950 x 40, AKU10+4,EI30
In: 2.korrus
Classification: 1.15 IfcPlateType (plaat) (IPI ÜBN); Material: Klaas
AR_ÜLD - 001_Nimetus: AKU10+4,EI30
BaseQuantities - Width: 1419.22 mm; Perimeter: 4658.43 mm; GrossArea: 1.38636 m2; NetArea: 1.29149 m2; GrossVolume: 0.0554542 m3; NetVolume: 0.0516595 m3
AC_Pset_RenovationAndPhasing - Renovation Status: Undefined

# IfcPlate: Main Panel 351 x 15 x 30, PKU10,dB
In: 2.korrus
Classification: 1.15 IfcPlateType (plaat) (IPI ÜBN); Material: Klaas
AR_ÜLD - 001_Nimetus: PKU10,dB
AC_Pset_RenovationAndPhasing - Renovation Status: Undefined
BaseQuantities - Width: 1086.12 mm; Perimeter: 7212.24 mm; GrossArea: 2.84625 m2; NetArea: 2.73702 m2; GrossVolume: 0.0853875 m3; NetVolume: 0.0821105 m3

# IfcPlate: Main Panel 352 x 10 x 20
In: 1.korrus
Classification: 1.15 IfcPlateType (plaat) (IPI ÜBN); Material: Klaas
AC_Pset_RenovationAndPhasing - Renovation Status: Undefined
BaseQuantities - Width: 0 mm; Perimeter: 0 mm; GrossArea: 0.0799406 m2; NetArea: 0 m2; GrossVolume: 0.00159881 m3; NetVolume: 0 m3

# IfcPlate: Main Panel 438 x 270 x 30
In: 2.korrus
Classification: 1.15 IfcPlateType (plaat) (IPI ÜBN); Material: Klaas
AC_Pset_RenovationAndPhasing - Renovation Status: Undefined
BaseQuantities - Width: 959.698 mm; Perimeter: 2399.4 mm; GrossArea: 0.267218 m2; NetArea: 0.230327 m2; GrossVolume: 0.00801655 m3; NetVolume: 0.00690982 m3

# IfcPlate: Main Panel 470 x 2350 x 30 (2)
In: 2.korrus
Classification: 1.15 IfcPlateType (plaat) (IPI ÜBN); Material: Klaas
BaseQuantities - Width: 440 mm; Perimeter: 5520 mm; GrossArea: 1.1045 m2; NetArea: 1.0208 m2; GrossVolume: 0.033135 m3; NetVolume: 0.030624 m3
AC_Pset_RenovationAndPhasing - Renovation Status: Undefined

# IfcPlate: Main Panel 496 x 955 x 40
In: 2.korrus
Classification: 1.15 IfcPlateType (plaat) (IPI ÜBN); Material: Klaas
AC_Pset_RenovationAndPhasing - Renovation Status: Undefined
BaseQuantities - Width: 594.173 mm; Perimeter: 7608.35 mm; GrossArea: 2.06106 m2; NetArea: 1.9073 m2; GrossVolume: 0.0824425 m3; NetVolume: 0.0762918 m3

# IfcPlate: Main Panel 556 x 3250 x 40
In: 2.korrus
Classification: 1.15 IfcPlateType (plaat) (IPI ÜBN); Material: Klaas
BaseQuantities - Width: 515.847 mm; Perimeter: 7451.69 mm; GrossArea: 1.8065 m2; NetArea: 1.65587 m2; GrossVolume: 0.0722601 m3; NetVolume: 0.0662347 m3
AC_Pset_RenovationAndPhasing - Renovation Status: Undefined

# IfcPlate: Main Panel 563 x 275 x 30
In: 2.korrus
Classification: 1.15 IfcPlateType (plaat) (IPI ÜBN); Material: Klaas
AC_Pset_RenovationAndPhasing - Renovation Status: Undefined
BaseQuantities - Width: 533 mm; Perimeter: 5706 mm; GrossArea: 1.32305 m2; NetArea: 1.23656 m2; GrossVolume: 0.0396915 m3; NetVolume: 0.0370968 m3

# IfcPlate: Main Panel 567 x 2350 x 30
In: 2.korrus
Classification: 1.15 IfcPlateType (plaat) (IPI ÜBN); Material: Klaas
AC_Pset_RenovationAndPhasing - Renovation Status: Undefined
BaseQuantities - Width: 537 mm; Perimeter: 5714 mm; GrossArea: 1.33245 m2; NetArea: 1.24584 m2; GrossVolume: 0.0399735 m3; NetVolume: 0.0373752 m3

# IfcPlate: Main Panel 579 x 1442 x 20
In: 1.korrus
Classification: 1.15 IfcPlateType (plaat) (IPI ÜBN); Material: Klaas
AC_Pset_RenovationAndPhasing - Renovation Status: Undefined
BaseQuantities - Width: 1200.67 mm; Perimeter: 5385.2 mm; GrossArea: 1.86754 m2; NetArea: 1.78585 m2; GrossVolume: 0.0373507 m3; NetVolume: 0.0357171 m3

# IfcPlate: Main Panel 579 x 2055 x 20
In: 1.korrus
Classification: 1.15 IfcPlateType (plaat) (IPI ÜBN); Material: Klaas
AC_Pset_RenovationAndPhasing - Renovation Status: Undefined
BaseQuantities - Width: 1200.67 mm; Perimeter: 6451.33 mm; GrossArea: 2.52902 m2; NetArea: 2.43135 m2; GrossVolume: 0.0505804 m3; NetVolume: 0.048627 m3

# IfcPlate: Main Panel 581 x 1336 x 40
In: 1.korrus
Classification: 1.15 IfcPlateType (plaat) (IPI ÜBN); Material: Klaas
BaseQuantities - Width: 540.847 mm; Perimeter: 3724.6 mm; GrossArea: 0.776443 m2; NetArea: 0.701529 m2; GrossVolume: 0.0310577 m3; NetVolume: 0.0280611 m3
AC_Pset_RenovationAndPhasing - Renovation Status: Undefined

# IfcPlate: Main Panel 613 x 270 x 30
In: 2.korrus
Classification: 1.15 IfcPlateType (plaat) (IPI ÜBN); Material: Klaas
AC_Pset_RenovationAndPhasing - Renovation Status: Undefined
BaseQuantities - Width: 940 mm; Perimeter: 2360 mm; GrossArea: 0.2619 m2; NetArea: 0.2256 m2; GrossVolume: 0.007857 m3; NetVolume: 0.006768 m3

# IfcPlate: Main Panel 613 x 290 x 30
In: 2.korrus
Classification: 1.15 IfcPlateType (plaat) (IPI ÜBN); Material: Klaas
AC_Pset_RenovationAndPhasing - Renovation Status: Undefined
BaseQuantities - Width: 940 mm; Perimeter: 2400 mm; GrossArea: 0.2813 m2; NetArea: 0.2444 m2; GrossVolume: 0.008439 m3; NetVolume: 0.007332 m3

# IfcPlate: Main Panel 70 x 3200 x 40
In: 1.korrus
Classification: 1.15 IfcPlateType (plaat) (IPI ÜBN); Material: Klaas
BaseQuantities - Width: 815 mm; Perimeter: 7950 mm; GrossArea: 2.736 m2; NetArea: 2.5754 m2; GrossVolume: 0.10944 m3; NetVolume: 0.103016 m3
AC_Pset_RenovationAndPhasing - Renovation Status: Undefined

# IfcPlate: Main Panel 70 x 3250 x 40, AKU10+4,EI30
In: 2.korrus
Classification: 1.15 IfcPlateType (plaat) (IPI ÜBN); Material: Klaas
AR_ÜLD - 001_Nimetus: AKU10+4,EI30
AC_Pset_RenovationAndPhasing - Renovation Status: Undefined
BaseQuantities - Width: 1144.1 mm; Perimeter: 8708.21 mm; GrossArea: 3.84834 m2; NetArea: 3.67257 m2; GrossVolume: 0.153933 m3; NetVolume: 0.146903 m3

# IfcPlate: Main Panel 728 x 270 x 30
In: 2.korrus
Classification: 1.15 IfcPlateType (plaat) (IPI ÜBN); Material: Klaas
AC_Pset_RenovationAndPhasing - Renovation Status: Undefined
BaseQuantities - Width: 940 mm; Perimeter: 2360 mm; GrossArea: 0.2619 m2; NetArea: 0.2256 m2; GrossVolume: 0.007857 m3; NetVolume: 0.006768 m3

# IfcPlate: Main Panel 733 x 275 x 30 (2)
In: 2.korrus
Classification: 1.15 IfcPlateType (plaat) (IPI ÜBN); Material: Klaas
AC_Pset_RenovationAndPhasing - Renovation Status: Undefined
BaseQuantities - Width: 1050 mm; Perimeter: 6740 mm; GrossArea: 2.538 m2; NetArea: 2.436 m2; GrossVolume: 0.07614 m3; NetVolume: 0.07308 m3

# IfcPlate: Main Panel 733 x 383 x 20
In: 1.korrus
Classification: 1.15 IfcPlateType (plaat) (IPI ÜBN); Material: Klaas
AC_Pset_RenovationAndPhasing - Renovation Status: Undefined
BaseQuantities - Width: 634.505 mm; Perimeter: 1701.7 mm; GrossArea: 0.146124 m2; NetArea: 0.109444 m2; GrossVolume: 0.00292248 m3; NetVolume: 0.00218888 m3

# IfcPlate: Main Panel 74 x 2350 x 30
In: 2.korrus
Classification: 1.15 IfcPlateType (plaat) (IPI ÜBN); Material: Klaas
AC_Pset_RenovationAndPhasing - Renovation Status: Undefined
BaseQuantities - Width: 1493.44 mm; Perimeter: 7626.87 mm; GrossArea: 3.58007 m2; NetArea: 3.46477 m2; GrossVolume: 0.107402 m3; NetVolume: 0.103943 m3

# IfcPlate: Main Panel 77 x 1134 x 20
In: 1.korrus
Classification: 1.15 IfcPlateType (plaat) (IPI ÜBN); Material: Klaas
AC_Pset_RenovationAndPhasing - Renovation Status: Undefined
BaseQuantities - Width: 1205.48 mm; Perimeter: 4779.28 mm; GrossArea: 1.49457 m2; NetArea: 1.42198 m2; GrossVolume: 0.0298915 m3; NetVolume: 0.0284396 m3

# IfcPlate: Main Panel 77 x 2055 x 20
In: 1.korrus
Classification: 1.15 IfcPlateType (plaat) (IPI ÜBN); Material: Klaas
BaseQuantities - Width: 1205.48 mm; Perimeter: 6460.95 mm; GrossArea: 2.5389 m2; NetArea: 2.44109 m2; GrossVolume: 0.0507781 m3; NetVolume: 0.0488218 m3
AC_Pset_RenovationAndPhasing - Renovation Status: Undefined

# IfcPlate: Main Panel 776 x 3250 x 40
In: 2.korrus
Classification: 1.15 IfcPlateType (plaat) (IPI ÜBN); Material: Klaas
AC_Pset_RenovationAndPhasing - Renovation Status: Undefined
BaseQuantities - Width: 1019.94 mm; Perimeter: 8459.87 mm; GrossArea: 3.4448 m2; NetArea: 3.274 m2; GrossVolume: 0.137792 m3; NetVolume: 0.13096 m3

# IfcPlate: Main Panel 828 x 1596 x 20
In: 1.korrus
Classification: 1.15 IfcPlateType (plaat) (IPI ÜBN); Material: Klaas
AC_Pset_RenovationAndPhasing - Renovation Status: Undefined
BaseQuantities - Width: 1197.22 mm; Perimeter: 5686.25 mm; GrossArea: 2.05128 m2; NetArea: 1.96509 m2; GrossVolume: 0.0410256 m3; NetVolume: 0.0393017 m3

# IfcPlate: Main Panel 828 x 2055 x 20
In: 1.korrus
Classification: 1.15 IfcPlateType (plaat) (IPI ÜBN); Material: Klaas
AC_Pset_RenovationAndPhasing - Renovation Status: Undefined
BaseQuantities - Width: 1197.22 mm; Perimeter: 6444.45 mm; GrossArea: 2.52194 m2; NetArea: 2.42438 m2; GrossVolume: 0.0504389 m3; NetVolume: 0.0484875 m3

# IfcPlate: Main Panel 831 x 1343 x 40
In: 1.korrus
Classification: 1.15 IfcPlateType (plaat) (IPI ÜBN); Material: Klaas
BaseQuantities - Width: 1075 mm; Perimeter: 4321.34 mm; GrossArea: 1.17533 m2; NetArea: 1.08719 m2; GrossVolume: 0.0470132 m3; NetVolume: 0.0434877 m3
AC_Pset_RenovationAndPhasing - Renovation Status: Undefined

# IfcPlate: Main Panel 831 x 3250 x 40 (2)
In: 2.korrus
Classification: 1.15 IfcPlateType (plaat) (IPI ÜBN); Material: Klaas
AC_Pset_RenovationAndPhasing - Renovation Status: Undefined
Name | Width (mm) | Perimeter (mm) | GrossArea (m2) | NetArea (m2) | GrossVolume (m3) | NetVolume (m3)
 | 1075 | 8570 | 3.62375 | 3.45075 | 0.14495 | 0.13803
 | 1130.06 | 8680.13 | 3.8028 | 3.6275 | 0.152112 | 0.1451

# IfcPlate: Main Panel 831 x 746 x 40
In: 1.korrus
Classification: 1.15 IfcPlateType (plaat) (IPI ÜBN); Material: Klaas
AC_Pset_RenovationAndPhasing - Renovation Status: Undefined
BaseQuantities - Width: 1075 mm; Perimeter: 3097.87 mm; GrossArea: 0.493247 m2; NetArea: 0.429579 m2; GrossVolume: 0.0197299 m3; NetVolume: 0.0171832 m3

# IfcPlate: Main Panel 831 x 950 x 40
In: 2.korrus
Classification: 1.15 IfcPlateType (plaat) (IPI ÜBN); Material: Klaas
AC_Pset_RenovationAndPhasing - Renovation Status: Undefined
BaseQuantities - Width: 1410 mm; Perimeter: 4640 mm; GrossArea: 1.3775 m2; NetArea: 1.2831 m2; GrossVolume: 0.0551 m3; NetVolume: 0.051324 m3

# IfcPlate: Main Panel 886 x 3250 x 40
In: 2.korrus
Classification: 1.15 IfcPlateType (plaat) (IPI ÜBN); Material: Klaas
AC_Pset_RenovationAndPhasing - Renovation Status: Undefined
BaseQuantities - Width: 1130.06 mm; Perimeter: 8680.13 mm; GrossArea: 3.8027 m2; NetArea: 3.6275 m2; GrossVolume: 0.152108 m3; NetVolume: 0.1451 m3

# IfcPlate: Main Panel 94 x 2350 x 30
In: 2.korrus
Classification: 1.15 IfcPlateType (plaat) (IPI ÜBN); Material: Klaas
AC_Pset_RenovationAndPhasing - Renovation Status: Undefined
BaseQuantities - Width: 1493.44 mm; Perimeter: 7626.87 mm; GrossArea: 3.58007 m2; NetArea: 3.46477 m2; GrossVolume: 0.107402 m3; NetVolume: 0.103943 m3

# IfcPlate: Main Panel 956 x 295 x 30
In: 2.korrus
Classification: 1.15 IfcPlateType (plaat) (IPI ÜBN); Material: Klaas
AC_Pset_RenovationAndPhasing - Renovation Status: Undefined
BaseQuantities - Width: 926.225 mm; Perimeter: 6492.45 mm; GrossArea: 2.24713 m2; NetArea: 2.14884 m2; GrossVolume: 0.0674139 m3; NetVolume: 0.0644653 m3

# IfcPlate: Main Panel 964 x 1755 x 20
In: 1.korrus
Classification: 1.15 IfcPlateType (plaat) (IPI ÜBN); Material: Klaas
AC_Pset_RenovationAndPhasing - Renovation Status: Undefined
BaseQuantities - Width: 924.419 mm; Perimeter: 5278.84 mm; GrossArea: 1.69256 m2; NetArea: 1.58538 m2; GrossVolume: 0.0338511 m3; NetVolume: 0.0317076 m3

# IfcPlate: Main Panel 964 x 3260 x 20
In: 1.korrus
Classification: 1.15 IfcPlateType (plaat) (IPI ÜBN); Material: Klaas
AC_Pset_RenovationAndPhasing - Renovation Status: Undefined
BaseQuantities - Width: 924.419 mm; Perimeter: 8288.84 mm; GrossArea: 3.14401 m2; NetArea: 2.97663 m2; GrossVolume: 0.0628801 m3; NetVolume: 0.0595326 m3

# IfcPlate: Main Panel 990 x 175 x 30
In: 2.korrus
Classification: 1.15 IfcPlateType (plaat) (IPI ÜBN); Material: Klaas
AC_Pset_RenovationAndPhasing - Renovation Status: Undefined
BaseQuantities - Width: 960.002 mm; Perimeter: 2800 mm; GrossArea: 0.465301 m2; NetArea: 0.422401 m2; GrossVolume: 0.013959 m3; NetVolume: 0.012672 m3

# IfcPlate: Main Panel 997 x 15 x 30, PKU10,dB
In: 2.korrus
Classification: 1.15 IfcPlateType (plaat) (IPI ÜBN); Material: Klaas
AR_ÜLD - 001_Nimetus: PKU10,dB
AC_Pset_RenovationAndPhasing - Renovation Status: Undefined
BaseQuantities - Width: 961.811 mm; Perimeter: 2803.62 mm; GrossArea: 0.466226 m2; NetArea: 0.423197 m2; GrossVolume: 0.0139868 m3; NetVolume: 0.0126959 m3

# IfcRailing: Railing Type (9)
Classification: 1.16 IfcRailingType (piire) (IPI ÜBN)
AR_Piire - 900_Tootja: ootel; 905_Mudel: ootel
Name | In | GrossVolume (m3) = NetVolume (m3) | Length (mm) = 255_Kogupikkus (mm) | Renovation Status | 001_Nimetus | 250_Kõrgus (mm)
Piire | 1.korrus | 0.0127495 | 9357.58 | New | Trepipiire-01 | 900
Piire | 1.korrus | 0.0127496 | 9357.58 | New | Trepipiire-01 | 900
Piire | 1.korrus | 0.0479794 | 2253.84 | Existing | Trepipiire | 1000
Piire | 1.korrus | 0.0479774 | 2253.14 | Existing | Trepipiire | 1000
Piire | 2.korrus | 0.0358988 | 1850 | New | Trepipiire-01 | 1000
Piire | 2.korrus | 0.13126 | 5770 | Existing | Trepipiire | 1000
Piire | Pööningukorrus | 0.105615 | 5167.6 | Existing | Trepipiire | 1000
Piire | Pööningukorrus | 0.13818 | 6908.76 | New | Trepipiire | 1000
Piire | Pööningukorrus | 0.0545117 | 2254.24 | New | Trepipiire | 1000

# IfcRamp (3)
In: 1.korrus
Classification: 1.17 IfcRamp (ramp) (IPI ÜBN); Material: GENEERILINE - KONSTRUKTRIOON
AC_Pset_RenovationAndPhasing - Renovation Status: Existing
Name | 001_Nimetus | 550_Kalle (deg)
 | Olemasolev pandus sirge | 720.477
 | Olemasolev pandus sirge | 702.496
 | Olemasolev pandus

# IfcRoof (27)
Classification: 1.19 IfcSlabType.ROOF (katus) (IPI ÜBN)
AR_Plaat - 500_Kandev: yes
Name | In | Material | 505_Paksus (mm) | 515_Neto-pindala (m2) = TotalSurfaceArea (m2) | 001_Nimetus | Renovation Status
 | 1.korrus | GENEERILINE - KONSTRUKTRIOON | 169.353 | 521.854 | Olemasolev kaldkatus | Existing
 | 1.korrus | GENEERILINE - KONSTRUKTRIOON | 297.764 | 533.167 | Olemasolev kaldkatus | Existing
 | 1.korrus | GENEERILINE - KONSTRUKTRIOON | 114.562 | 66.9762 | Olemasolev kaldkatus | Existing
 | 2.korrus | GENEERILINE - KONSTRUKTRIOON | 491.31 | 180.959 | Olemasolev kaldkatus | Existing
 | 2.korrus | GENEERILINE - KONSTRUKTRIOON | 350 | 32.7851 | Olemasolev katuslagi | Existing
 | 2.korrus | GENEERILINE - KONSTRUKTRIOON | 597.717 | 683.232 | Olemasolev kaldkatus | Existing
 | Pööningukorrus | GENEERILINE - KONSTRUKTRIOON | 547.907 | 274.937 | Olemasolev kaldkatus | Existing
 | Pööningukorrus | GENEERILINE - KONSTRUKTRIOON | 239.087 | 1052.22 | Olemasolev kaldkatus | Existing
 | Pööningukorrus | GENEERILINE - KONSTRUKTRIOON | 239.087 | 637.4 | Olemasolev kaldkatus | Existing
KL1 | Katuseplaan | Soojustus - Mineraalvill jäik | 248 | 99.1668 | Katuslagi | New
 | Katuseplaan | Raudbetoon | 50 | 18.884 | Katuslagi | New
 | Katuseplaan | Raudbetoon | 50 | 2.99555 | Katuslagi | New
 | Katuseplaan | Raudbetoon | 50 | 2.37279 | Katuslagi | New
 | Katuseplaan | Raudbetoon | 50 | 18.0259 | Katuslagi | New
KL1 | Katuseplaan | Soojustus - Mineraalvill jäik | 248 | 14.0761 | Katuslagi | New
KL1 | Katuseplaan | Soojustus - Mineraalvill jäik | 248 | 14.5369 | Katuslagi | New
KL1 | Katuseplaan | Soojustus - Mineraalvill jäik | 248 | 13.9976 | Katuslagi | New
KL1 | Katuseplaan | Soojustus - Mineraalvill jäik | 248 | 14.6238 | Katuslagi | New
KL1 | Katuseplaan | Soojustus - Mineraalvill jäik | 248 | 100.736 | Katuslagi | New
 | Katuseplaan | Raudbetoon | 50 | 3.51665 | Katuslagi | New
 | Katuseplaan | Raudbetoon | 50 | 2.26144 | Katuslagi | New
KL1 | 2.korrus |  | 298 | 20.616 | Katuslagi | New
KL1 | 2.korrus |  | 298 | 20.5591 | Katuslagi | New
KL1 | Katuseplaan |  | 257 | 486.181 | Katuslagi | New
KL1 | Katuseplaan |  | 420 | 148.71 | Katuslagi | New
KL1 | Katuseplaan |  | 257 | 336.699 | Katuslagi | New
KL1 | Katuseplaan |  | 420 | 334.543 | Katuslagi | New

# IfcSlab: Air Space - Frame 273
In: 1.korrus
Classification: 1.20 IfcSlabType (vahelagi) (IPI ÜBN); Material: Air Space - Frame
BaseQuantities - Width: 273 mm; Perimeter: 14100.4 mm; GrossArea: 10.1004 m2; NetArea: 10.1004 m2; GrossVolume: 2.7574 m3; NetVolume: 2.7574 m3
AC_Pset_RenovationAndPhasing - Renovation Status: New
AR_Plaat - 001_Nimetus: Varikatus; 505_Paksus: 273 mm; 515_Neto-pindala: 10.1004 m2; 500_Kandev: no

# IfcSlab: Concrete - Structural 60
In: 1.korrus
Classification: 1.20 IfcSlabType (vahelagi) (IPI ÜBN); Material: Concrete - Structural
AR_Plaat - 001_Nimetus: Põrand pinnasel; 505_Paksus: 60 mm; 515_Neto-pindala: 2.19319 m2; 500_Kandev: yes
BaseQuantities - Width: 60 mm; Perimeter: 5940 mm; GrossArea: 2.1942 m2; NetArea: 2.19319 m2; GrossVolume: 0.131652 m3; NetVolume: 0.131592 m3
AC_Pset_RenovationAndPhasing - Renovation Status: New

# IfcSlab: GENEERILINE - KONSTRUKTRIOON 150 (4)
Classification: 1.20 IfcSlabType (vahelagi) (IPI ÜBN); Material: GENEERILINE - KONSTRUKTRIOON
AR_Plaat - 505_Paksus: 150 mm
BaseQuantities - Width: 150 mm
Name | In | 001_Nimetus | 515_Neto-pindala (m2) = NetArea (m2) | 500_Kandev | Renovation Status | Perimeter (mm) | GrossArea (m2) | GrossVolume (m3) | NetVolume (m3)
 | 1.korrus | Olemasolev vahelagi | 808.479 | yes | Existing | 150044 | 898.802 | 134.831 | 121.282
 | 2.korrus | Trepiaste | 0.556107 | no | New | 4301.2 | 0.556107 | 0.083416 | 0.083416
 | 2.korrus | Trepiaste | 0.467929 | no | New | 4006.14 | 0.467929 | 0.0701894 | 0.0701894
 | 2.korrus | Olemasolev vahelagi | 121.481 | yes | Existing | 53262.9 | 174.576 | 26.1474 | 18.1831

# IfcSlab: GENEERILINE - KONSTRUKTRIOON 170
In: 1.korrus
Classification: 1.20 IfcSlabType (vahelagi) (IPI ÜBN); Material: GENEERILINE - KONSTRUKTRIOON
AC_Pset_RenovationAndPhasing - Renovation Status: Existing
AR_Plaat - 001_Nimetus: Olemasolev platvorm; 505_Paksus: 170 mm; 515_Neto-pindala: 2.22823 m2; 500_Kandev: yes
BaseQuantities - Width: 170 mm; Perimeter: 5983.47 mm; GrossArea: 2.22823 m2; NetArea: 2.22823 m2; GrossVolume: 0.378798 m3; NetVolume: 0.378798 m3

# IfcSlab: GENEERILINE - KONSTRUKTRIOON 175 (4)
In: 1.korrus
Classification: 1.20 IfcSlabType (vahelagi) (IPI ÜBN); Material: GENEERILINE - KONSTRUKTRIOON
AR_Plaat - 001_Nimetus: Olemasolev vahelagi; 505_Paksus: 175 mm; 500_Kandev: yes
BaseQuantities - Width: 175 mm
AC_Pset_RenovationAndPhasing - Renovation Status: Existing
Name | 515_Neto-pindala (m2) = NetArea (m2) | Perimeter (mm) | GrossArea (m2) | GrossVolume (m3) | NetVolume (m3)
 | 11.4294 | 13523.5 | 11.4294 | 2.00015 | 2.00015
 | 14.3391 | 15180 | 14.3748 | 2.51558 | 2.50935
 | 3.06714 | 7110.61 | 3.06714 | 0.536749 | 0.536749
 | 7.21302 | 11144.4 | 7.38522 | 1.29241 | 1.26228

# IfcSlab: GENEERILINE - KONSTRUKTRIOON 180 (2)
Classification: 1.20 IfcSlabType (vahelagi) (IPI ÜBN); Material: GENEERILINE - KONSTRUKTRIOON
AR_Plaat - 505_Paksus: 180 mm; 500_Kandev: no
BaseQuantities - Width: 180 mm
Name | In | 001_Nimetus | 515_Neto-pindala (m2) = GrossArea (m2) = NetArea (m2) | Renovation Status | Perimeter (mm) | GrossVolume (m3) = NetVolume (m3)
 | 1.korrus | Olemasolev trepp | 1.10102 | Existing | 4531.15 | 0.198184
 | Pööningukorrus | Trepiaste | 0.5635 | New | 3920 | 0.10143

# IfcSlab: GENEERILINE - KONSTRUKTRIOON 195
In: 1.korrus
Classification: 1.20 IfcSlabType (vahelagi) (IPI ÜBN); Material: GENEERILINE - KONSTRUKTRIOON
AR_Plaat - 001_Nimetus: Olemasolev trepp; 505_Paksus: 195 mm; 515_Neto-pindala: 0.37048 m2; 500_Kandev: no
AC_Pset_RenovationAndPhasing - Renovation Status: Existing
BaseQuantities - Width: 195 mm; Perimeter: 2642.93 mm; GrossArea: 0.37048 m2; NetArea: 0.37048 m2; GrossVolume: 0.0722435 m3; NetVolume: 0.0722435 m3

# IfcSlab: GENEERILINE - KONSTRUKTRIOON 200 (36)
Classification: 1.20 IfcSlabType (vahelagi) (IPI ÜBN); Material: GENEERILINE - KONSTRUKTRIOON
BaseQuantities - Width: 200 mm
AR_Plaat - 505_Paksus: 200 mm; 500_Kandev: no
Name | In | Perimeter (mm) | GrossArea (m2) | NetArea (m2) = 515_Neto-pindala (m2) | GrossVolume (m3) | NetVolume (m3) | Renovation Status | 001_Nimetus
3 x Põrandatrapp | 1.korrus | 1700 | 0.105 | 0.105 | 0.021 | 0.021 | New | põrandatrapp
Põrandatrapp | 1.korrus | 1200 | 0.09 | 0.09 | 0.018 | 0.018 | New | põrandatrapp
7 x Põrandatrapp | 1.korrus | 600 | 0.0225 | 0.0225 | 0.0045 | 0.0045 | New | põrandatrapp
 | 1.korrus | 71567.7 | 281.784 | 281.784 | 56.3569 | 56.3569 | Existing | Olemasolev põrand pinnasel
 | 1.korrus | 71452 | 284.653 | 284.653 | 56.9307 | 56.9307 | Existing | Olemasolev põrand pinnasel
 | 1.korrus | 96020.2 | 433.383 | 430.551 | 86.9033 | 86.3367 | Existing | Olemasolev põrand pinnasel
 | 1.korrus | 56377.8 | 180.657 | 180.657 | 36.1314 | 36.1314 | Existing | Olemasolev põrand pinnasel
 | 1.korrus | 53544.6 | 128.746 | 128.631 | 25.7493 | 25.7261 | Existing | Olemasolev põrand pinnasel
 | 1.korrus | 59568 | 211.744 | 211.744 | 42.3488 | 42.3488 | Existing | Olemasolev põrand pinnasel
 | 1.korrus | 83953.1 | 213.059 | 213.059 | 42.6118 | 42.6118 | Existing | Olemasolev põrand pinnasel
 | 1.korrus | 106114 | 278.503 | 278.503 | 55.7006 | 55.7006 | Existing | Olemasolev põrand pinnasel
 | 1.korrus | 77322.7 | 354.648 | 354.648 | 70.9297 | 70.9297 | Existing | Olemasolev põrand pinnasel
 | 1.korrus | 53937.7 | 178.756 | 178.612 | 35.7513 | 35.7223 | Existing | Olemasolev põrand pinnasel
 | 1.korrus | 125550 | 715.482 | 715.482 | 143.096 | 143.096 | Existing | Olemasolev põrand pinnasel
 | 1.korrus | 33939.8 | 60.1347 | 60.1347 | 12.0269 | 12.0269 | Existing | Olemasolev põrand pinnasel
2 x  | 1.korrus | 2809.13 | 0.334556 | 0.334556 | 0.0669112 | 0.0669112 | Existing | Olemasolev trepp
 | 1.korrus | 3017.07 | 0.557604 | 0.557604 | 0.111521 | 0.111521 | Existing | Olemasolev välitasand
Põrandatrapp | 2.korrus | 2700 | 0.18 | 0.18 | 0.036 | 0.036 | New | põrandatrapp
Põrandatrapp | 2.korrus | 4340.23 | 0.303017 | 0.303017 | 0.0606035 | 0.0606035 | New | põrandatrapp
2 x Põrandatrapp | 2.korrus | 600 | 0.0225 | 0.0225 | 0.0045 | 0.0045 | New | põrandatrapp
6 x Põrandatrapp | Pööningukorrus | 600 | 0.0225 | 0.0225 | 0.0045 | 0.0045 | New | põrandatrapp

# IfcSlab: GENEERILINE - KONSTRUKTRIOON 265 (3)
In: 1.korrus
Classification: 1.20 IfcSlabType (vahelagi) (IPI ÜBN); Material: GENEERILINE - KONSTRUKTRIOON
AR_Plaat - 001_Nimetus: Olemasolev põrand pinnasel; 505_Paksus: 265 mm; 500_Kandev: no
AC_Pset_RenovationAndPhasing - Renovation Status: Existing
BaseQuantities - Width: 265 mm
Name | 515_Neto-pindala (m2) = NetArea (m2) | Perimeter (mm) | GrossArea (m2) | GrossVolume (m3) | NetVolume (m3)
 | 17.4026 | 26443.4 | 18.1821 | 4.81826 | 4.61169
 | 6.54122 | 13301 | 6.54123 | 1.73343 | 1.73343
 | 6.43684 | 13455 | 6.43687 | 1.70577 | 1.70576

# IfcSlab: GENEERILINE - KONSTRUKTRIOON 290
In: 2.korrus
Classification: 1.20 IfcSlabType (vahelagi) (IPI ÜBN); Material: GENEERILINE - KONSTRUKTRIOON
AR_Plaat - 001_Nimetus: Vahelagi; 505_Paksus: 289.999 mm; 515_Neto-pindala: 4.18024 m2; 500_Kandev: no
AC_Pset_RenovationAndPhasing - Renovation Status: New
BaseQuantities - Width: 289.999 mm; Perimeter: 8219.18 mm; GrossArea: 4.18024 m2; NetArea: 4.18024 m2; GrossVolume: 1.21227 m3; NetVolume: 1.21227 m3

# IfcSlab: GENEERILINE - KONSTRUKTRIOON 300 (2)
In: 2.korrus
Classification: 1.20 IfcSlabType (vahelagi) (IPI ÜBN); Material: GENEERILINE - KONSTRUKTRIOON
AR_Plaat - 001_Nimetus: Trepiaste; 505_Paksus: 300 mm; 500_Kandev: no
AC_Pset_RenovationAndPhasing - Renovation Status: New
BaseQuantities - Width: 300 mm
Name | 515_Neto-pindala (m2) = GrossArea (m2) = NetArea (m2) | Perimeter (mm) | GrossVolume (m3) = NetVolume (m3)
 | 0.555 | 4300 | 0.1665
 | 0.467929 | 4006.14 | 0.140379

# IfcSlab: GENEERILINE - KONSTRUKTRIOON 330
In: 1.korrus
Classification: 1.20 IfcSlabType (vahelagi) (IPI ÜBN); Material: GENEERILINE - KONSTRUKTRIOON
AR_Plaat - 001_Nimetus: Olemasolev vahelagi; 505_Paksus: 330 mm; 515_Neto-pindala: 129.306 m2; 500_Kandev: yes
AC_Pset_RenovationAndPhasing - Renovation Status: Existing
BaseQuantities - Width: 330 mm; Perimeter: 54260.2 mm; GrossArea: 129.541 m2; NetArea: 129.306 m2; GrossVolume: 42.7484 m3; NetVolume: 42.671 m3

# IfcSlab: GENEERILINE - KONSTRUKTRIOON 450
In: 2.korrus
Classification: 1.20 IfcSlabType (vahelagi) (IPI ÜBN); Material: GENEERILINE - KONSTRUKTRIOON
AC_Pset_RenovationAndPhasing - Renovation Status: New
AR_Plaat - 001_Nimetus: Trepiaste; 505_Paksus: 450 mm; 515_Neto-pindala: 0.939978 m2; 500_Kandev: no
BaseQuantities - Width: 450 mm; Perimeter: 4686.14 mm; GrossArea: 0.939978 m2; NetArea: 0.939978 m2; GrossVolume: 0.42299 m3; NetVolume: 0.42299 m3

# IfcSlab: GENEERILINE - KONSTRUKTRIOON 50 (2)
In: Pööningukorrus
Classification: 1.20 IfcSlabType (vahelagi) (IPI ÜBN); Material: GENEERILINE - KONSTRUKTRIOON
AR_Plaat - 505_Paksus: 50 mm; 500_Kandev: yes
AC_Pset_RenovationAndPhasing - Renovation Status: New
BaseQuantities - Width: 50 mm
Name | 001_Nimetus | 515_Neto-pindala (m2) = GrossArea (m2) = NetArea (m2) | Perimeter (mm) | GrossVolume (m3) = NetVolume (m3)
 | Käigutee | 26.5765 | 29753.3 | 1.32883
 | Kipsplaat ripplagi | 12.8736 | 30278.1 | 0.643678

# IfcSlab: GENEERILINE - KONSTRUKTRIOON 520
In: 1.korrus
Classification: 1.20 IfcSlabType (vahelagi) (IPI ÜBN); Material: GENEERILINE - KONSTRUKTRIOON
AR_Plaat - 001_Nimetus: Põrand pinnasel; 505_Paksus: 520 mm; 515_Neto-pindala: 4.28625 m2; 500_Kandev: no
AC_Pset_RenovationAndPhasing - Renovation Status: Existing
BaseQuantities - Width: 520 mm; Perimeter: 8352.42 mm; GrossArea: 4.28625 m2; NetArea: 4.28625 m2; GrossVolume: 2.22885 m3; NetVolume: 2.22885 m3

# IfcSlab: P-1 600 (2)
In: 1.korrus
Classification: 1.20 IfcSlabType (vahelagi) (IPI ÜBN)
AC_Pset_RenovationAndPhasing - Renovation Status: New
BaseQuantities - Width: 600 mm
AR_Plaat - 505_Paksus: 600 mm; 500_Kandev: yes
Name | Perimeter (mm) | GrossArea (m2) | NetArea (m2) = 515_Neto-pindala (m2) | GrossVolume (m3) | NetVolume (m3) | 001_Nimetus
 | 26101.1 | 41.7869 | 41.7869 | 25.0722 | 25.0722 | Olemasolev põrand pinnasel
 | 135005 | 862.496 | 860.302 | 516.912 | 515.596 | Põrand pinnasel

# IfcSlab: VL1 570 (2)
Classification: 1.20 IfcSlabType (vahelagi) (IPI ÜBN)
AR_Plaat - 505_Paksus: 570 mm; 500_Kandev: yes
AC_Pset_RenovationAndPhasing - Renovation Status: New
BaseQuantities - Width: 570 mm
Name | In | 001_Nimetus | 515_Neto-pindala (m2) = NetArea (m2) | Perimeter (mm) | GrossArea (m2) | GrossVolume (m3) | NetVolume (m3)
VL-1 | 2.korrus | Vahelagi | 788.308 | 135483 | 793.454 | 448.867 | 445.934
 | Pööningukorrus | Puitvahelagi | 156.196 | 60717.9 | 167.822 | 100.086 | 93.4594

# IfcSlab: VL2 730 (2)
In: Pööningukorrus
Classification: 1.20 IfcSlabType (vahelagi) (IPI ÜBN)
AC_Pset_RenovationAndPhasing - Renovation Status: New
AR_Plaat - 505_Paksus: 730 mm
BaseQuantities - Width: 730 mm
Name | 001_Nimetus | 515_Neto-pindala (m2) = NetArea (m2) | 500_Kandev | Perimeter (mm) | GrossArea (m2) | GrossVolume (m3) | NetVolume (m3)
 | Puitvahelagi | 94.0769 | yes | 41439.6 | 104.778 | 80.8099 | 72.9984
 | Vahelagi | 76.4351 | no | 42390.3 | 89.6761 | 70.5165 | 60.8505

# IfcSlab: VL3 90
In: 2.korrus
Classification: 1.20 IfcSlabType (vahelagi) (IPI ÜBN)
AR_Plaat - 001_Nimetus: Põrandaplaadistus; 505_Paksus: 90 mm; 515_Neto-pindala: 175.608 m2; 500_Kandev: yes
AC_Pset_RenovationAndPhasing - Renovation Status: New
BaseQuantities - Width: 90 mm; Perimeter: 55060.9 mm; GrossArea: 175.608 m2; NetArea: 175.608 m2; GrossVolume: 15.8048 m3; NetVolume: 15.8048 m3

# IfcSlab: VL3.1 109 (4)
In: 2.korrus
Classification: 1.20 IfcSlabType (vahelagi) (IPI ÜBN)
AC_Pset_RenovationAndPhasing - Renovation Status: New
AR_Plaat - 001_Nimetus: Põrandaplaadistus; 505_Paksus: 109 mm; 500_Kandev: yes
BaseQuantities - Width: 109 mm
Name | 515_Neto-pindala (m2) = NetArea (m2) | Perimeter (mm) | GrossArea (m2) | GrossVolume (m3) | NetVolume (m3)
 | 40.6691 | 25737.1 | 40.6691 | 4.43293 | 4.43293
 | 41.6107 | 26062.7 | 41.6107 | 4.53556 | 4.53556
 | 40.7319 | 25754.3 | 40.7319 | 4.43978 | 4.43978
 | 39.2403 | 26088.4 | 41.7509 | 4.54651 | 4.27286

# IfcStair (15)
Classification: 1.22 IfcStair (trepp) (IPI ÜBN)
Name | In | 001_Nimetus | 002_Tähis | Renovation Status | NetVolume (m3) | Length (mm) | Height (mm) | GrossVolume (m3)
Trepimade | 1.korrus | Trepimade | Trepimade | New | 0.409136 | Material: GENEERILINE - KONSTRUKTRIOON
Trepimade | 2.korrus | Trepimade | Trepimade | New | 0.852016 | Material: GENEERILINE - KONSTRUKTRIOON
Trepimade | Pööningukorrus | Trepimade | Trepimade | New | 0.148343 | Material: GENEERILINE - KONSTRUKTRIOON
Trepp3 | 1.korrus | Trepp | Trepp3 | Existing | 0.322449 | 4375.04 | 2896 | 0.322449
Trepp1 | 1.korrus | Trepp | Trepp1 | New | 3.99685 | 8360 | 4100 | 3.99685
Trepp3 | 1.korrus | Trepp | Trepp3 | Existing | 0.14103 | 1914.08 | 1360 | 0.14103
 | 1.korrus | Olemasolev sisetrepp |  | Existing | 0.0994245 | 2862.86 | 2800 | 0.0994245
Trepp | 1.korrus | Välistrepp | Trepp | Existing | 0.777747 | 950.636 | 520 | 0.777747
 | 1.korrus | Olemasolev sisetrepp |  | Existing | 0.103344 | 4783.68 | 3431.26 | 0.103344
Trepp | 1.korrus | Välistrepp | Trepp | Existing | 0.252733 | 430.588 | 520 | 0.252733
2 x Trepp | 1.korrus | Välistrepp | Trepp | Existing | 0.341458 | 1100.59 | 425 | 0.341458
 | 1.korrus | Olemasolev sisetrepp |  | Existing | 0.049208 | 1834.5 | 2690 | 0.049208
 | 1.korrus | Olemasolev sisetrepp |  | Existing | 0.0651286 | 3349.69 | 2735.38 | 0.0651286
Trepp1 | 2.korrus | Trepp | Trepp1 | New | 0.330991 | 5739.8 | 4020 | 0.330991

# IfcWall: GENEERILINE - KONSTRUKTRIOON 100 (13)
In: 1.korrus
Classification: 1.24 IfcWallType (sein) (IPI ÜBN); Material: GENEERILINE - KONSTRUKTRIOON
AC_Pset_RenovationAndPhasing - Renovation Status: Existing
AR_Sein - 340_Soojusläbivus: 0; 500_Kandev: no; 505_Paksus: 100 mm; 376_Viimistlus-väljast: Paint - Light Gray
BaseQuantities - Width: 100 mm
Name | 001_Nimetus | 335_Välispiire | 605_Neto-pindala (m2) | 600_Bruto-pindala (m2) | 205_Tähis | Length (mm) | Height (mm) | GrossFootprintArea (m2) = NetFootprintArea (m2) | GrossSideArea (m2) | NetSideArea (m2) | GrossVolume (m3) | NetVolume (m3)
VS-XX | Olemasolev välissein | yes | 63.2218 | 343.168 | VS-XX | 36187.4 | 2329.66 | 3.03174 | 84.155 | 63.3199 | 8.4155 | 6.33199
VS-XX | Olemasolev välissein | yes | 105.271 | 448.429 | VS-XX | 47082.6 | 2821.68 | 4.70826 | 132.442 | 105.399 | 13.2442 | 10.5399
SS-XX | Olemasolev sisesein | no | 1.06419 | 3.05919 | SS-XX | 1274.66 | 2400 | 0.0324664 | 3.05919 | 1.06419 | 0.305919 | 0.106419
SS-XX | Olemasolev sisesein | no | 1.08633 | 3.36504 | SS-XX | 1890.47 | 1780 | 0.0175116 | 3.18805 | 1.08735 | 0.318805 | 0.108735
SS-XX | Olemasolev sisesein | no | 1.68948 | 5.053 | SS-XX | 2838.76 | 1780 | 0.0329331 | 5.05401 | 1.69049 | 0.505401 | 0.169049
SS-XX | Olemasolev sisesein | no | 7.24671 | 7.95396 | SS-XX | 1536.9 | 4715 | 0.15369 | 7.24649 | 7.24649 | 0.724649 | 0.724649
SS-XX | Olemasolev sisesein | no | 5.30494 | 7.34194 | SS-XX | 2516.97 | 2929.67 | 0.159697 | 7.34191 | 5.30491 | 0.734191 | 0.530491
SS-XX | Olemasolev sisesein | no | 1.38188 | 3.23508 | SS-XX | 1377.25 | 2220 | 0.0597245 | 2.87988 | 1.38188 | 0.287988 | 0.138188
SS-XX | Olemasolev sisesein | no | 2.46316 | 6.15276 | SS-XX | 2122 | 2430 | 0.1322 | 5.27796 | 2.46316 | 0.527796 | 0.246316
SS-XX | Olemasolev sisesein | no | 5.25612 | 8.25912 | SS-XX | 3298.88 | 2430 | 0.329888 | 8.01627 | 5.25627 | 0.801627 | 0.525627
SS-XX | Olemasolev sisesein | no | 11.276 | 11.8911 | SS-XX | 3899.57 | 2929.64 | 0.384957 | 11.2656 | 11.2656 | 1.12656 | 1.12656
SS-XX | Olemasolev sisesein | no | 2.30576 | 6.15277 | SS-XX | 2122 | 2430 | 0.1262 | 5.03496 | 2.30576 | 0.503496 | 0.230576
VS-XX | Olemasolev välissein | yes | 14.8098 | 22.7299 | VS-XX | 6016.92 | 2643.59 | 0.596692 | 14.8099 | 14.8099 | 1.48099 | 1.48099

# IfcWall: GENEERILINE - KONSTRUKTRIOON 110 (6)
In: 1.korrus
Classification: 1.24 IfcWallType (sein) (IPI ÜBN); Material: GENEERILINE - KONSTRUKTRIOON
AR_Sein - 340_Soojusläbivus: 0; 500_Kandev: no; 505_Paksus: 110 mm
AC_Pset_RenovationAndPhasing - Renovation Status: Existing
BaseQuantities - Width: 110 mm
Name | 001_Nimetus | 335_Välispiire | 605_Neto-pindala (m2) | 600_Bruto-pindala (m2) | 376_Viimistlus-väljast | Length (mm) | Height (mm) | GrossFootprintArea (m2) = NetFootprintArea (m2) | GrossSideArea (m2) | NetSideArea (m2) | GrossVolume (m3) | NetVolume (m3)
 | Olemasolev sisesein | no | 15.4462 | 58.7464 | Paint - Light Gray | 5906.92 | 2772.69 | 0.660761 | 15.4462 | 15.4462 | 1.69908 | 1.69908
 | Olemasolev sisesein | no | 11.4218 | 63.2222 | Paint - Light Gray | 5906.79 | 3113.97 | 0.334046 | 17.4487 | 11.4217 | 1.91936 | 1.25639
 | Olemasolev sisesein | no | 14.4218 | 67.4893 | Paint - Light Gray | 5906.92 | 3779.54 | 0.660761 | 20.3122 | 14.4217 | 2.23434 | 1.58639
 | Olemasolev sisesein | no | 17.474 | 63.2209 | Paint - Light Gray | 5906.66 | 3118.3 | 0.649732 | 17.4739 | 17.4739 | 1.92213 | 1.92213
 | Olemasolev sisesein | no | 17.4616 | 63.2215 | Paint - Light Gray | 5906.72 | 3116.18 | 0.649739 | 17.4616 | 17.4616 | 1.92077 | 1.92077
VS-XX | Olemasolev välissein | yes | 179.846 | 345.932 | RAL 5012 | 35882.5 | 5100.19 | 3.95147 | 182.31 | 180.378 | 20.0541 | 19.8416 | AR_Sein - 205_Tähis: VS-XX

# IfcWall: GENEERILINE - KONSTRUKTRIOON 120 (10)
In: 1.korrus
Classification: 1.24 IfcWallType (sein) (IPI ÜBN); Material: GENEERILINE - KONSTRUKTRIOON
AR_Sein - 340_Soojusläbivus: 0; 500_Kandev: no; 505_Paksus: 120 mm; 376_Viimistlus-väljast: Paint - Light Gray
AC_Pset_RenovationAndPhasing - Renovation Status: Existing
BaseQuantities - Width: 120 mm
Name | 001_Nimetus | 335_Välispiire | 605_Neto-pindala (m2) | 600_Bruto-pindala (m2) | 205_Tähis | Length (mm) | Height (mm) | GrossFootprintArea (m2) = NetFootprintArea (m2) | GrossSideArea (m2) | NetSideArea (m2) | GrossVolume (m3) | NetVolume (m3)
VS-XX | Olemasolev välissein | yes | 1.8512 | 1.8512 | VS-XX | 3560 | 520 | 0.4272 | 1.8512 | 1.8512 | 0.222144 | 0.222144
VS-XX | Olemasolev välissein | yes | 1.885 | 1.885 | VS-XX | 3625 | 520 | 0.435 | 1.885 | 1.885 | 0.2262 | 0.2262
VS-XX | Olemasolev välissein | yes | 1.8772 | 1.8772 | VS-XX | 3610 | 520 | 0.4332 | 1.8772 | 1.8772 | 0.225264 | 0.225264
SS-XX | Olemasolev sisesein | no | 1.46757 | 1.46757 | SS-XX | 2096.52 | 700 | 0.251583 | 1.46757 | 1.46757 | 0.176108 | 0.176108
SS-XX | Olemasolev sisesein | no | 0.665429 | 0.665429 | SS-XX | 950.613 | 700 | 0.114074 | 0.665429 | 0.665429 | 0.0798515 | 0.0798515
SS-XX | Olemasolev sisesein | no | 5.9171 | 8.51435 | SS-XX | 1595.86 | 4715 | 0.0907027 | 7.80736 | 5.91736 | 0.936883 | 0.710083
SS-XX | Olemasolev sisesein | no | 2.69995 | 5.81584 | SS-XX | 1058.41 | 4715 | 0.10601 | 4.1653 | 2.69966 | 0.499836 | 0.323959
2 x SS-XX | Olemasolev sisesein | no | 0.4979 | 0.4979 | SS-XX | 130 | 3830 | 0.0156 | 0.4979 | 0.4979 | 0.059748 | 0.059748
SS-XX | Olemasolev sisesein | no | 21.7771 | 25.5301 | SS-XX | 8190 | 3118.27 | 0.7668 | 25.5035 | 21.7505 | 3.06041 | 2.61005

# IfcWall: GENEERILINE - KONSTRUKTRIOON 130
In: 1.korrus
Classification: 1.24 IfcWallType (sein) (IPI ÜBN); Material: GENEERILINE - KONSTRUKTRIOON
AC_Pset_RenovationAndPhasing - Renovation Status: Existing
AR_Sein - 001_Nimetus: Olemasolev sisesein; 335_Välispiire: no; 340_Soojusläbivus: 0; 605_Neto-pindala: 3.54618 m2; 600_Bruto-pindala: 3.98534 m2; 500_Kandev: no; 505_Paksus: 130 mm; 376_Viimistlus-väljast: Paint - Light Gray
BaseQuantities - Length: 1341.38 mm; Height: 2900.98 mm; Width: 130 mm; GrossFootprintArea: 0.176661 m2; NetFootprintArea: 0.176661 m2; GrossSideArea: 3.54659 m2; NetSideArea: 3.54659 m2; GrossVolume: 0.461057 m3; NetVolume: 0.461057 m3

# IfcWall: GENEERILINE - KONSTRUKTRIOON 140, SS-XX
In: 1.korrus
Classification: 1.24 IfcWallType (sein) (IPI ÜBN); Material: GENEERILINE - KONSTRUKTRIOON
AR_Sein - 001_Nimetus: Olemasolev sisesein; 335_Välispiire: no; 340_Soojusläbivus: 0; 605_Neto-pindala: 9.44028 m2; 600_Bruto-pindala: 12.1693 m2; 500_Kandev: no; 505_Paksus: 140 mm; 376_Viimistlus-väljast: Paint - Light Gray; 205_Tähis: SS-XX
AC_Pset_RenovationAndPhasing - Renovation Status: Existing
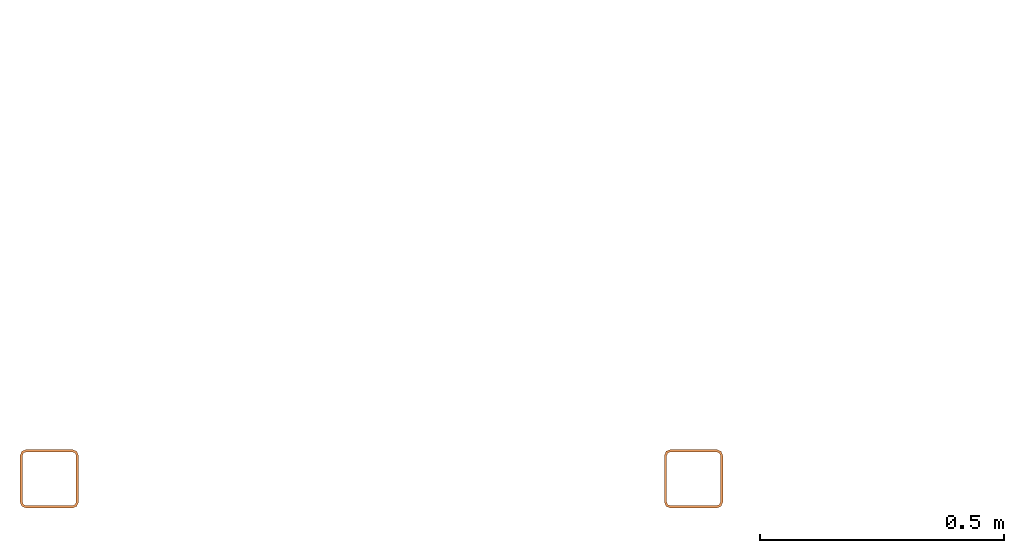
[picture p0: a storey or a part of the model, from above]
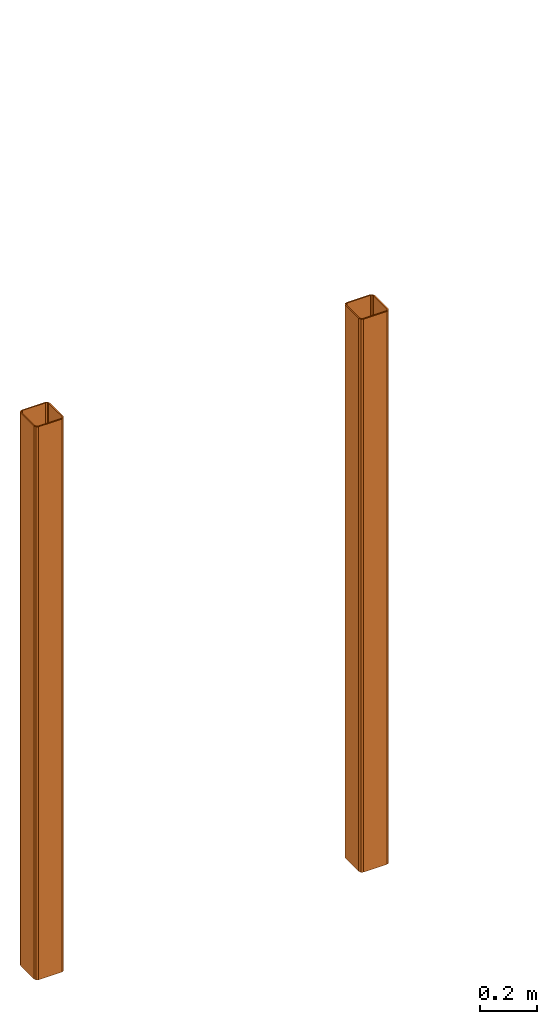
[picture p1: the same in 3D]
Properties of the parts of a building model (IFC2X3), part 6 of 7

# IfcWall: GENEERILINE - KONSTRUKTRIOON 140, SS-XX
BaseQuantities - Length: 2350.97 mm; Height: 4715 mm; Width: 140 mm; GrossFootprintArea: 0.215719 m2; NetFootprintArea: 0.215719 m2; GrossSideArea: 11.0848 m2; NetSideArea: 9.44028 m2; GrossVolume: 1.55187 m3; NetVolume: 1.32164 m3

# IfcWall: GENEERILINE - KONSTRUKTRIOON 150 (10)
In: 1.korrus
Classification: 1.24 IfcWallType (sein) (IPI ÜBN); Material: GENEERILINE - KONSTRUKTRIOON
AC_Pset_RenovationAndPhasing - Renovation Status: Existing
BaseQuantities - Width: 150 mm
AR_Sein - 001_Nimetus: Olemasolev sisesein; 335_Välispiire: no; 340_Soojusläbivus: 0; 500_Kandev: no; 505_Paksus: 150 mm; 376_Viimistlus-väljast: Paint - Light Gray
Name | Length (mm) | Height (mm) | GrossFootprintArea (m2) = NetFootprintArea (m2) | GrossSideArea (m2) | NetSideArea (m2) | GrossVolume (m3) | NetVolume (m3) | 605_Neto-pindala (m2) | 600_Bruto-pindala (m2)
 | 5786.7 | 3110.4 | 0.653505 | 17.0921 | 14.0891 | 2.56382 | 2.11337 | 14.089 | 63.2213
 | 1413.89 | 2990.45 | 0.212083 | 4.174 | 4.174 | 0.6261 | 0.6261 | 4.17402 | 17.0189
 | 2378.05 | 2998.85 | 0.356707 | 7.12103 | 7.12103 | 1.06815 | 1.06815 | 7.13069 | 26.593
 | 5786.68 | 3111.05 | 0.653502 | 17.0958 | 14.0928 | 2.56437 | 2.11392 | 14.0929 | 63.2211
 | 2378.05 | 2914.16 | 0.356707 | 6.91962 | 6.91962 | 1.03794 | 1.03794 | 6.90996 | 26.593
 | 1346.87 | 2289.61 | 0.0767812 | 3.23265 | 1.36965 | 0.484897 | 0.205447 | 1.36927 | 3.23281
 | 8141.59 | 3510.97 | 1.06824 | 24.1679 | 22.2635 | 3.62519 | 3.33953 | 22.2635 | 24.9684
 | 4078.95 | 2901.64 | 0.611842 | 11.7981 | 11.7981 | 1.76971 | 1.76971 | 11.8356 | 11.8356
SS-XX | 3497.71 | 4715 | 0.524657 | 16.4391 | 16.4391 | 2.46134 | 2.46134 | 16.4816 | 18.1915 | AR_Sein - 205_Tähis: SS-XX
 | 2378.05 | 2805.74 | 0.356707 | 6.6618 | 6.6618 | 0.99927 | 0.99927 | 6.65214 | 7.49134

# IfcWall: GENEERILINE - KONSTRUKTRIOON 160 (2)
In: 1.korrus
Classification: 1.24 IfcWallType (sein) (IPI ÜBN); Material: GENEERILINE - KONSTRUKTRIOON
AC_Pset_RenovationAndPhasing - Renovation Status: Existing
AR_Sein - 001_Nimetus: Olemasolev sisesein; 335_Välispiire: no; 340_Soojusläbivus: 0; 500_Kandev: no; 505_Paksus: 160 mm; 376_Viimistlus-väljast: Paint - Light Gray
BaseQuantities - Width: 160 mm
Name | 605_Neto-pindala (m2) = GrossSideArea (m2) = NetSideArea (m2) | 600_Bruto-pindala (m2) | Length (mm) | Height (mm) | GrossFootprintArea (m2) = NetFootprintArea (m2) | GrossVolume (m3) = NetVolume (m3)
 | 22.9752 | 25.5109 | 5669.09 | 4100 | 0.896593 | 3.67603
SS-XX | 3.76997 | 3.76997 | 1648.19 | 2220 | 0.27171 | 0.603195 | AR_Sein - 205_Tähis: SS-XX

# IfcWall: GENEERILINE - KONSTRUKTRIOON 180
In: 1.korrus
Classification: 1.24 IfcWallType (sein) (IPI ÜBN); Material: GENEERILINE - KONSTRUKTRIOON
BaseQuantities - Length: 1749.76 mm; Height: 2901.99 mm; Width: 180 mm; GrossFootprintArea: 0.314956 m2; NetFootprintArea: 0.314956 m2; GrossSideArea: 4.98084 m2; NetSideArea: 4.98084 m2; GrossVolume: 0.886781 m3; NetVolume: 0.886781 m3
AC_Pset_RenovationAndPhasing - Renovation Status: Existing
AR_Sein - 001_Nimetus: Olemasolev sisesein; 335_Välispiire: no; 340_Soojusläbivus: 0; 605_Neto-pindala: 4.92259 m2; 600_Bruto-pindala: 6.61583 m2; 500_Kandev: no; 505_Paksus: 180 mm; 376_Viimistlus-väljast: Paint - Light Gray

# IfcWall: GENEERILINE - KONSTRUKTRIOON 190 (8)
In: 1.korrus
Classification: 1.24 IfcWallType (sein) (IPI ÜBN); Material: GENEERILINE - KONSTRUKTRIOON
AR_Sein - 001_Nimetus: Olemasolev sisesein; 335_Välispiire: no; 340_Soojusläbivus: 0; 505_Paksus: 190 mm
AC_Pset_RenovationAndPhasing - Renovation Status: Existing
BaseQuantities - Width: 190 mm
Name | 605_Neto-pindala (m2) | 600_Bruto-pindala (m2) | 500_Kandev | 376_Viimistlus-väljast | 205_Tähis | Length (mm) | Height (mm) | GrossFootprintArea (m2) = NetFootprintArea (m2) | GrossSideArea (m2) | NetSideArea (m2) | GrossVolume (m3) | NetVolume (m3)
SS-XX | 72.7478 | 123.703 | yes | Paint - Light Gray | SS-XX | 12267.6 | 7035.15 | 2.36698 | 72.7488 | 72.7488 | 13.8223 | 13.8223
SS-XX | 21.8345 | 83.999 | yes | RAL 7043 | SS-XX | 8189.96 | 4167.87 | 0.488292 | 33.8585 | 21.7369 | 6.43312 | 4.13001
SS-XX | 0.826453 | 3.74397 | yes | Paint - Light Gray | SS-XX | 200 | 4144.54 | 0.038 | 0.826453 | 0.826453 | 0.157026 | 0.157026
 | 0.477839 | 0.477839 | no | Paint - Light Gray |  | 202.134 | 2376.38 | 0.0384055 | 0.477839 | 0.477839 | 0.0907894 | 0.0907894
 | 0.608315 | 0.608315 | no | Paint - Light Gray |  | 190 | 3201.66 | 0.0361 | 0.606098 | 0.606098 | 0.115159 | 0.115159
SS-XX | 0.989067 | 3.73482 | yes | RAL 7043 | SS-XX | 294.046 | 4189.97 | 0.0739188 | 1.30493 | 1.30493 | 0.307022 | 0.307022
SS-XX | 0.310535 | 2.53946 | yes | RAL 7043 | SS-XX | 169.529 | 4189.97 | 0.0141605 | 0.311405 | 0.311405 | 0.0591669 | 0.0591669
SS-XX | 32.2782 | 41.3718 | no | Paint - Light Gray | SS-XX | 8395.11 | 4715 | 1.13907 | 38.0171 | 32.2811 | 7.22325 | 6.13341

# IfcWall: GENEERILINE - KONSTRUKTRIOON 200 (8)
In: 1.korrus
Classification: 1.24 IfcWallType (sein) (IPI ÜBN); Material: GENEERILINE - KONSTRUKTRIOON
AR_Sein - 340_Soojusläbivus: 0; 500_Kandev: no; 505_Paksus: 200 mm; 376_Viimistlus-väljast: Paint - Light Gray
BaseQuantities - Width: 200 mm
Name | 001_Nimetus | 335_Välispiire | 605_Neto-pindala (m2) | 600_Bruto-pindala (m2) | 205_Tähis | Renovation Status | Length (mm) | Height (mm) | GrossFootprintArea (m2) = NetFootprintArea (m2) | GrossSideArea (m2) | NetSideArea (m2) | GrossVolume (m3) | NetVolume (m3)
VS-XX | Olemasolev välissein | yes | 6.20921 | 6.20921 | VS-XX | New | 12418.4 | 500 | 2.48368 | 6.20921 | 6.20921 | 1.24184 | 1.24184
VS-XX | Olemasolev välissein | yes | 17.9612 | 17.9612 | VS-XX | New | 35922.4 | 500 | 7.18447 | 17.9612 | 17.9612 | 3.59224 | 3.59224
VS-XX | Olemasolev välissein | yes | 11.6784 | 12.1149 | VS-XX | Existing | 12489.6 | 970 | 2.40792 | 11.5104 | 11.5104 | 2.29536 | 2.29536
VS-XX | Olemasolev välissein | yes | 32.6121 | 34.8447 | VS-XX | Existing | 35922.4 | 970 | 7.18446 | 34.8446 | 32.612 | 6.96892 | 6.5224
SS-XX | Olemasolev sisesein | no | 81.2838 | 91.0765 | SS-XX | Existing | 14968.8 | 5760 | 2.99375 | 83.2263 | 81.2838 | 16.6453 | 16.2568
 | Olemasolev sisesein | no | 6.71665 | 8.06015 |  | Existing | 1824.76 | 3535.53 | 0.379951 | 6.69332 | 6.69332 | 1.29942 | 1.29942
SS-XX | Olemasolev sisesein | no | 1.80468 | 2.04649 | SS-XX | Existing | 2909.81 | 620 | 0.582088 | 1.80447 | 1.80447 | 0.360894 | 0.360894
SS-XX | Olemasolev sisesein | no | 1.11341 | 1.23741 | SS-XX | Existing | 1995.82 | 620 | 0.359289 | 1.1138 | 1.1138 | 0.222759 | 0.222759

# IfcWall: GENEERILINE - KONSTRUKTRIOON 220 (2)
In: 1.korrus
Classification: 1.24 IfcWallType (sein) (IPI ÜBN); Material: GENEERILINE - KONSTRUKTRIOON
AR_Sein - 340_Soojusläbivus: 0; 500_Kandev: no; 505_Paksus: 220 mm; 376_Viimistlus-väljast: Paint - Light Gray
AC_Pset_RenovationAndPhasing - Renovation Status: Existing
BaseQuantities - Width: 220 mm
Name | 001_Nimetus | 335_Välispiire | 605_Neto-pindala (m2) = 600_Bruto-pindala (m2) | 205_Tähis | Length (mm) | Height (mm) | GrossFootprintArea (m2) = NetFootprintArea (m2) | GrossSideArea (m2) = NetSideArea (m2) | GrossVolume (m3) = NetVolume (m3)
VS-XX | Olemasolev välissein | yes | 1.81036 | VS-XX | 760.655 | 2380 | 0.167344 | 1.81036 | 0.398279
SS-XX | Olemasolev sisesein | no | 15.1032 | SS-XX | 2967.22 | 5090 | 0.652218 | 15.0899 | 3.31979

# IfcWall: GENEERILINE - KONSTRUKTRIOON 230 (4)
In: 1.korrus
Classification: 1.24 IfcWallType (sein) (IPI ÜBN); Material: GENEERILINE - KONSTRUKTRIOON
AR_Sein - 340_Soojusläbivus: 0; 500_Kandev: no; 505_Paksus: 230 mm; 376_Viimistlus-väljast: Paint - Light Gray
AC_Pset_RenovationAndPhasing - Renovation Status: Existing
BaseQuantities - Width: 230 mm
Name | 001_Nimetus | 335_Välispiire | 605_Neto-pindala (m2) | 600_Bruto-pindala (m2) | 205_Tähis | Length (mm) | Height (mm) | GrossFootprintArea (m2) = NetFootprintArea (m2) | GrossSideArea (m2) | NetSideArea (m2) | GrossVolume (m3) | NetVolume (m3)
VS-XX | Olemasolev välissein | yes | 40.0656 | 41.0951 | VS-XX | 36252.4 | 1130 | 8.31159 | 40.8352 | 40.0656 | 9.3921 | 9.21509
VS-XX | Olemasolev välissein | yes | 7.00246 | 7.34146 | VS-XX | 6081.87 | 1130 | 1.42528 | 7.00246 | 7.00246 | 1.61057 | 1.61057
VS-XX | Olemasolev välissein | yes | 30.4821 | 30.6037 | VS-XX | 47082.6 | 650 | 10.829 | 30.5429 | 30.5429 | 7.02301 | 7.02301
SS-XX | Olemasolev sisesein | no | 28.509 | 28.6197 | SS-XX | 6009.92 | 4715 | 1.39608 | 28.509 | 28.509 | 6.55708 | 6.55708

# IfcWall: GENEERILINE - KONSTRUKTRIOON 25 (3)
In: 1.korrus
Classification: 1.24 IfcWallType (sein) (IPI ÜBN); Material: GENEERILINE - KONSTRUKTRIOON
BaseQuantities - Height: 2515 mm; Width: 25 mm
AC_Pset_RenovationAndPhasing - Renovation Status: Existing
AR_Sein - 001_Nimetus: Olemasolev sisesein; 335_Välispiire: no; 340_Soojusläbivus: 0; 500_Kandev: no; 505_Paksus: 25 mm; 376_Viimistlus-väljast: Paint - Light Gray; 205_Tähis: SS-XX
Name | Length (mm) | GrossFootprintArea (m2) = NetFootprintArea (m2) | GrossSideArea (m2) | NetSideArea (m2) = 605_Neto-pindala (m2) | GrossVolume (m3) | NetVolume (m3) | 600_Bruto-pindala (m2)
SS-XX | 1041.08 | 0.0263394 | 2.64974 | 2.64974 | 0.0662436 | 0.0662436 | 3.27849
SS-XX | 1303.76 | 0.0325939 | 3.27895 | 3.27895 | 0.0819736 | 0.0819736 | 3.34182
SS-XX | 1041.08 | 0.0103338 | 2.58687 | 1.32566 | 0.0646717 | 0.0331415 | 2.64974

# IfcWall: GENEERILINE - KONSTRUKTRIOON 250 (8)
In: 1.korrus
Classification: 1.24 IfcWallType (sein) (IPI ÜBN); Material: GENEERILINE - KONSTRUKTRIOON
AR_Sein - 340_Soojusläbivus: 0; 505_Paksus: 250 mm; 376_Viimistlus-väljast: Paint - Light Gray
BaseQuantities - Width: 250 mm
Name | 001_Nimetus | 335_Välispiire | 605_Neto-pindala (m2) | 600_Bruto-pindala (m2) | 500_Kandev | 205_Tähis | Renovation Status | Length (mm) | Height (mm) | GrossFootprintArea (m2) = NetFootprintArea (m2) | GrossSideArea (m2) | NetSideArea (m2) | GrossVolume (m3) | NetVolume (m3)
VS-XX | Olemasolev välissein | yes | 17.9611 | 17.9611 | no | VS-XX | New | 35922.3 | 500 | 8.98057 | 17.9611 | 17.9611 | 4.49029 | 4.49029
SS-XX | Olemasolev sisesein | no | 35.5823 | 48.0475 | no | SS-XX | Existing | 7710.28 | 5760 | 1.92757 | 40.9275 | 34.6655 | 9.77476 | 8.44013
SS-XX | Olemasolev sisesein | no | 64.134 | 121.931 | yes | SS-XX | Existing | 11991.2 | 6206.04 | 3.10077 | 64.9065 | 64.9065 | 16.0339 | 16.0339
VS-XX | Olemasolev välissein | yes | 34.8446 | 34.8446 | no | VS-XX | Existing | 35922.3 | 970 | 8.9806 | 34.8447 | 34.8447 | 8.71118 | 8.71118
 | Olemasolev sisesein | no | 72.2715 | 95.3876 | no |  | Existing | 15268.8 | 6080 | 3.11219 | 81.4673 | 72.2715 | 20.3668 | 18.0679
SS-XX | Olemasolev sisesein | no | 7.94331 | 9.60321 | no | SS-XX | Existing | 3283.41 | 2515 | 0.789603 | 7.9434 | 7.9434 | 1.98585 | 1.98585
SS-XX | Olemasolev sisesein | no | 4.62929 | 9.13674 | no | SS-XX | Existing | 3227.9 | 2515 | 0.425724 | 8.43254 | 4.62929 | 2.10813 | 1.15732
SS-XX | Olemasolev sisesein | no | 9.51047 | 10.2147 | no | SS-XX | Existing | 3781.5 | 2515 | 0.945375 | 9.51047 | 9.51047 | 2.37762 | 2.37762

# IfcWall: GENEERILINE - KONSTRUKTRIOON 256 (2)
In: 1.korrus
Classification: 1.24 IfcWallType (sein) (IPI ÜBN); Material: GENEERILINE - KONSTRUKTRIOON
BaseQuantities - Length: 2000 mm; Height: 2680.04 mm; Width: 256 mm; GrossFootprintArea: 0.512 m2; NetFootprintArea: 0.512 m2; GrossSideArea: 5.36009 m2; NetSideArea: 5.36009 m2; GrossVolume: 1.37218 m3; NetVolume: 1.37218 m3
AC_Pset_RenovationAndPhasing - Renovation Status: New
AR_Sein - 001_Nimetus: Sisesein; 325_Helipidavus: 43dB; 335_Välispiire: no; 340_Soojusläbivus: 0; 605_Neto-pindala: 5.36009 m2; 600_Bruto-pindala: 5.36009 m2; 500_Kandev: no; 505_Paksus: 256 mm; 376_Viimistlus-väljast: FAS_varikatus; 205_Tähis: Varikatus

# IfcWall: GENEERILINE - KONSTRUKTRIOON 260
In: 1.korrus
Classification: 1.24 IfcWallType (sein) (IPI ÜBN); Material: GENEERILINE - KONSTRUKTRIOON
AC_Pset_RenovationAndPhasing - Renovation Status: Existing
AR_Sein - 001_Nimetus: Olemasolev sisesein; 335_Välispiire: no; 340_Soojusläbivus: 0; 605_Neto-pindala: 2.27351 m2; 600_Bruto-pindala: 5.37851 m2; 500_Kandev: no; 505_Paksus: 260 mm; 376_Viimistlus-väljast: Paint - Light Gray
BaseQuantities - Length: 2288.73 mm; Height: 2350 mm; Width: 260 mm; GrossFootprintArea: 0.205069 m2; NetFootprintArea: 0.205069 m2; GrossSideArea: 5.37851 m2; NetSideArea: 2.27351 m2; GrossVolume: 1.39841 m3; NetVolume: 0.591113 m3

# IfcWall: GENEERILINE - KONSTRUKTRIOON 270 (2)
In: 1.korrus
Classification: 1.24 IfcWallType (sein) (IPI ÜBN); Material: GENEERILINE - KONSTRUKTRIOON
AC_Pset_RenovationAndPhasing - Renovation Status: Existing
BaseQuantities - Width: 270 mm
AR_Sein - 340_Soojusläbivus: 0; 500_Kandev: no; 505_Paksus: 270 mm; 376_Viimistlus-väljast: Paint - Light Gray
Name | Length (mm) | Height (mm) | GrossFootprintArea (m2) = NetFootprintArea (m2) | GrossSideArea (m2) | NetSideArea (m2) | GrossVolume (m3) | NetVolume (m3) | 001_Nimetus | 335_Välispiire | 605_Neto-pindala (m2) | 600_Bruto-pindala (m2) | 205_Tähis
SS-XX | 7091.88 | 5760 | 1.91481 | 37.9939 | 33.8966 | 10.2609 | 9.15462 | Olemasolev sisesein | no | 33.9497 | 44.393 | SS-XX
VS-XX | 6579.19 | 4092 | 1.70908 | 24.1682 | 24.1682 | 6.68475 | 6.68475 | Olemasolev välissein | yes | 24.759 | 25.0276 | VS-XX

# IfcWall: GENEERILINE - KONSTRUKTRIOON 280, VS-XX
In: 1.korrus
Classification: 1.24 IfcWallType (sein) (IPI ÜBN); Material: GENEERILINE - KONSTRUKTRIOON
AR_Sein - 001_Nimetus: Olemasolev välissein; 335_Välispiire: yes; 340_Soojusläbivus: 0; 605_Neto-pindala: 74.4209 m2; 600_Bruto-pindala: 137.78 m2; 500_Kandev: no; 505_Paksus: 280 mm; 376_Viimistlus-väljast: Paint - Light Gray; 205_Tähis: VS-XX
BaseQuantities - Length: 12084.8 mm; Height: 6270.77 mm; Width: 280 mm; GrossFootprintArea: 3.36414 m2; NetFootprintArea: 3.36414 m2; GrossSideArea: 74.8138 m2; NetSideArea: 74.8138 m2; GrossVolume: 20.9479 m3; NetVolume: 20.9479 m3
AC_Pset_RenovationAndPhasing - Renovation Status: Existing

# IfcWall: GENEERILINE - KONSTRUKTRIOON 290, VS-XX
In: 1.korrus
Classification: 1.24 IfcWallType (sein) (IPI ÜBN); Material: GENEERILINE - KONSTRUKTRIOON
AR_Sein - 001_Nimetus: Olemasolev välissein; 335_Välispiire: yes; 340_Soojusläbivus: 0; 605_Neto-pindala: 127.685 m2; 600_Bruto-pindala: 149.679 m2; 500_Kandev: no; 505_Paksus: 290 mm; 376_Viimistlus-väljast: Paint -Yellow; 205_Tähis: VS-XX
AC_Pset_RenovationAndPhasing - Renovation Status: Existing
BaseQuantities - Length: 24444.7 mm; Height: 6123.19 mm; Width: 290 mm; GrossFootprintArea: 7.08895 m2; NetFootprintArea: 7.08895 m2; GrossSideArea: 135.529 m2; NetSideArea: 124.542 m2; GrossVolume: 40.2451 m3; NetVolume: 37.0202 m3

# IfcWall: GENEERILINE - KONSTRUKTRIOON 300 (6)
Classification: 1.24 IfcWallType (sein) (IPI ÜBN); Material: GENEERILINE - KONSTRUKTRIOON
AC_Pset_RenovationAndPhasing - Renovation Status: Existing
AR_Sein - 340_Soojusläbivus: 0; 500_Kandev: no; 505_Paksus: 300 mm; 376_Viimistlus-väljast: Paint - Light Gray
BaseQuantities - Width: 300 mm
Name | In | 001_Nimetus | 335_Välispiire | 605_Neto-pindala (m2) | 600_Bruto-pindala (m2) | 205_Tähis | Length (mm) | Height (mm) | GrossFootprintArea (m2) = NetFootprintArea (m2) | GrossSideArea (m2) | NetSideArea (m2) | GrossVolume (m3) | NetVolume (m3)
VS-XX | 1.korrus | Olemasolev välissein | yes | 6.28087 | 6.42037 | VS-XX | 14267.5 | 450 | 4.18725 | 6.28087 | 6.28087 | 1.88426 | 1.88426
 | 1.korrus | Olemasolev sisesein | no | 7.71131 | 11.3479 |  | 2777.84 | 3410 | 0.548352 | 9.98063 | 7.71463 | 2.99518 | 2.31538
 | 1.korrus | Olemasolev sisesein | no | 9.32908 | 11.2032 |  | 3050.92 | 3410 | 0.870276 | 9.32908 | 9.32908 | 2.79873 | 2.79873
VS-XX | 1.korrus | Olemasolev välissein | yes | 3.66335 | 5.26335 | VS-XX | 1115.84 | 4000 | 0.274751 | 3.66335 | 3.66335 | 1.09901 | 1.09901
VS-XX | 1.korrus | Olemasolev välissein | yes | 2.63887 | 3.41528 | VS-XX | 1246.1 | 2485.53 | 0.32733 | 2.63887 | 2.63887 | 0.79166 | 0.79166
VS-XX | 2.korrus | Olemasolev välissein | yes | 120.409 | 238.493 | VS-XX | 36135.3 | 3980.1 | 10.8406 | 139.114 | 118.234 | 42.4945 | 36.2305

# IfcWall: GENEERILINE - KONSTRUKTRIOON 310 (5)
In: 1.korrus
Classification: 1.24 IfcWallType (sein) (IPI ÜBN); Material: GENEERILINE - KONSTRUKTRIOON
AR_Sein - 001_Nimetus: Olemasolev välissein; 335_Välispiire: yes; 340_Soojusläbivus: 0; 500_Kandev: no; 505_Paksus: 310 mm; 376_Viimistlus-väljast: Paint - Light Gray; 205_Tähis: VS-XX
AC_Pset_RenovationAndPhasing - Renovation Status: Existing
BaseQuantities - Width: 310 mm
Name | 605_Neto-pindala (m2) | 600_Bruto-pindala (m2) | Length (mm) | Height (mm) | GrossFootprintArea (m2) = NetFootprintArea (m2) | GrossSideArea (m2) | NetSideArea (m2) | GrossVolume (m3) | NetVolume (m3)
VS-XX | 5.17741 | 5.17741 | 11505.4 | 450 | 3.56666 | 5.17741 | 5.17741 | 1.605 | 1.605
VS-XX | 6.73267 | 6.87217 | 15271.5 | 450 | 4.63806 | 6.73267 | 6.73267 | 2.08713 | 2.08713
VS-XX | 1.15088 | 1.43798 | 2867.51 | 450 | 0.792828 | 1.15088 | 1.15088 | 0.356773 | 0.356773
VS-XX | 3.69441 | 3.84201 | 8537.81 | 450 | 2.54504 | 2.89343 | 2.89343 | 0.8878 | 0.8878
VS-XX | 2.3147 | 5.6664 | 1749.76 | 2523.59 | 0.223125 | 4.75805 | 2.35085 | 1.475 | 0.728765

# IfcWall: GENEERILINE - KONSTRUKTRIOON 320, SS-XX
In: 1.korrus
Classification: 1.24 IfcWallType (sein) (IPI ÜBN); Material: GENEERILINE - KONSTRUKTRIOON
AR_Sein - 001_Nimetus: Olemasolev sisesein; 335_Välispiire: no; 340_Soojusläbivus: 0; 605_Neto-pindala: 44.7403 m2; 600_Bruto-pindala: 52.9981 m2; 500_Kandev: yes; 505_Paksus: 320 mm; 376_Viimistlus-väljast: Paint - Light Gray; 205_Tähis: SS-XX
AC_Pset_RenovationAndPhasing - Renovation Status: Existing
BaseQuantities - Length: 12292.3 mm; Height: 4135 mm; Width: 320 mm; GrossFootprintArea: 3.76554 m2; NetFootprintArea: 3.76554 m2; GrossSideArea: 48.6578 m2; NetSideArea: 44.7417 m2; GrossVolume: 15.5705 m3; NetVolume: 14.3174 m3

# IfcWall: GENEERILINE - KONSTRUKTRIOON 328, VS-XX
In: 1.korrus
Classification: 1.24 IfcWallType (sein) (IPI ÜBN); Material: GENEERILINE - KONSTRUKTRIOON
AR_Sein - 001_Nimetus: Olemasolev välissein; 335_Välispiire: yes; 340_Soojusläbivus: 0; 605_Neto-pindala: 1.24832 m2; 600_Bruto-pindala: 1.24832 m2; 500_Kandev: no; 505_Paksus: 328 mm; 376_Viimistlus-väljast: Paint - Light Gray; 205_Tähis: VS-XX
BaseQuantities - Length: 2464.04 mm; Height: 450 mm; Width: 328 mm; GrossFootprintArea: 0.909885 m2; NetFootprintArea: 0.909885 m2; GrossSideArea: 0.985875 m2; NetSideArea: 0.985875 m2; GrossVolume: 0.409369 m3; NetVolume: 0.409369 m3
AC_Pset_RenovationAndPhasing - Renovation Status: Existing

# IfcWall: GENEERILINE - KONSTRUKTRIOON 330, SS-XX
In: 1.korrus
Classification: 1.24 IfcWallType (sein) (IPI ÜBN); Material: GENEERILINE - KONSTRUKTRIOON
AC_Pset_RenovationAndPhasing - Renovation Status: Existing
AR_Sein - 001_Nimetus: Olemasolev sisesein; 335_Välispiire: no; 340_Soojusläbivus: 0; 605_Neto-pindala: 75.9493 m2; 600_Bruto-pindala: 135.421 m2; 500_Kandev: yes; 505_Paksus: 330 mm; 376_Viimistlus-väljast: Paint - Light Gray; 205_Tähis: SS-XX
BaseQuantities - Length: 11795.5 mm; Height: 7206.11 mm; Width: 330 mm; GrossFootprintArea: 3.8925 m2; NetFootprintArea: 3.8925 m2; GrossSideArea: 76.181 m2; NetSideArea: 76.181 m2; GrossVolume: 25.2432 m3; NetVolume: 25.2432 m3

# IfcWall: GENEERILINE - KONSTRUKTRIOON 360 (6)
In: 1.korrus
Classification: 1.24 IfcWallType (sein) (IPI ÜBN); Material: GENEERILINE - KONSTRUKTRIOON
BaseQuantities - Width: 360 mm
AC_Pset_RenovationAndPhasing - Renovation Status: Existing
AR_Sein - 340_Soojusläbivus: 0; 500_Kandev: no; 505_Paksus: 360 mm
Name | Length (mm) | Height (mm) | GrossFootprintArea (m2) = NetFootprintArea (m2) | GrossSideArea (m2) | NetSideArea (m2) | GrossVolume (m3) | NetVolume (m3) | 001_Nimetus | 335_Välispiire | 605_Neto-pindala (m2) | 600_Bruto-pindala (m2) | 376_Viimistlus-väljast | 205_Tähis
VS-XX | 7234.1 | 3217.69 | 2.53948 | 19.5952 | 19.5952 | 7.06251 | 7.06251 | Olemasolev välissein | yes | 19.643 | 27.4322 | RAL 7043 | VS-XX
VS-XX | 11175.3 | 2351.56 | 3.47603 | 25.7995 | 22.9033 | 9.28781 | 8.2452 | Olemasolev välissein | yes | 22.6586 | 43.0507 | RAL 7043 | VS-XX
SS-XX | 48190.6 | 5780.1 | 17.2802 | 268.561 | 230.739 | 99.1365 | 85.5204 | Olemasolev sisesein | no | 235.588 | 515.696 | Paint - Light Gray | SS-XX
VS-XX | 2777.64 | 2580 | 0.389751 | 7.41141 | 3.65241 | 2.66811 | 1.31487 | Olemasolev välissein | yes | 3.65241 | 7.41141 | RAL 7043 | VS-XX
SS-XX | 34839.4 | 4000 | 12.5422 | 139.298 | 131.041 | 50.1687 | 47.1963 | Olemasolev sisesein | no | 131.101 | 141.278 | Paint - Light Gray | SS-XX
SS-XX | 7877.79 | 5910 | 2.836 | 40.6714 | 38.5714 | 14.8929 | 14.1369 | Olemasolev sisesein | no | 38.026 | 46.5547 | Paint - Light Gray | SS-XX

# IfcWall: GENEERILINE - KONSTRUKTRIOON 380 (4)
In: 1.korrus
Classification: 1.24 IfcWallType (sein) (IPI ÜBN); Material: GENEERILINE - KONSTRUKTRIOON
AR_Sein - 340_Soojusläbivus: 0; 500_Kandev: no; 505_Paksus: 380 mm
AC_Pset_RenovationAndPhasing - Renovation Status: Existing
BaseQuantities - Width: 380 mm
Name | 001_Nimetus | 335_Välispiire | 605_Neto-pindala (m2) | 600_Bruto-pindala (m2) | 376_Viimistlus-väljast | Length (mm) | Height (mm) | GrossFootprintArea (m2) = NetFootprintArea (m2) | GrossSideArea (m2) | NetSideArea (m2) | GrossVolume (m3) | NetVolume (m3)
VS-XX | Olemasolev välissein | yes | 21.2856 | 21.7808 | Paint - Pink | 20522.1 | 1061.33 | 7.63881 | 20.9673 | 20.9673 | 8.09811 | 8.09811 | AR_Sein - 205_Tähis: VS-XX
 | Olemasolev sisesein | no | 20.4028 | 26.42 | Paint - Light Gray | 5790.93 | 4410 | 2.12455 | 23.5378 | 20.4028 | 8.94436 | 7.75306
 | Olemasolev välissein | yes | 128.941 | 166.937 | Paint - Light Gray | 15148.8 | 9753.47 | 5.82493 | 133.006 | 127.44 | 50.566 | 48.4509
VS-XX | Olemasolev välissein | yes | 37.9267 | 131.541 | RAL 7043 | 13702.2 | 4167.94 | 4.01742 | 45.5835 | 37.9267 | 17.3217 | 14.4121 | AR_Sein - 205_Tähis: VS-XX

# IfcWall: GENEERILINE - KONSTRUKTRIOON 390, SS-XX
In: 1.korrus
Classification: 1.24 IfcWallType (sein) (IPI ÜBN); Material: GENEERILINE - KONSTRUKTRIOON
AR_Sein - 001_Nimetus: Olemasolev sisesein; 335_Välispiire: no; 340_Soojusläbivus: 0; 605_Neto-pindala: 33.3065 m2; 600_Bruto-pindala: 44.7919 m2; 500_Kandev: no; 505_Paksus: 390 mm; 376_Viimistlus-väljast: Paint - Light Gray; 205_Tähis: SS-XX
AC_Pset_RenovationAndPhasing - Renovation Status: Existing
BaseQuantities - Length: 7298.34 mm; Height: 5910 mm; Width: 390 mm; GrossFootprintArea: 2.84635 m2; NetFootprintArea: 2.84635 m2; GrossSideArea: 38.6123 m2; NetSideArea: 33.5924 m2; GrossVolume: 15.1476 m3; NetVolume: 13.194 m3

# IfcWall: GENEERILINE - KONSTRUKTRIOON 400 (7)
Classification: 1.24 IfcWallType (sein) (IPI ÜBN); Material: GENEERILINE - KONSTRUKTRIOON
AC_Pset_RenovationAndPhasing - Renovation Status: Existing
BaseQuantities - Width: 400 mm
AR_Sein - 340_Soojusläbivus: 0; 500_Kandev: no; 505_Paksus: 400 mm; 376_Viimistlus-väljast: Paint - Light Gray
Name | In | Length (mm) | Height (mm) | GrossFootprintArea (m2) = NetFootprintArea (m2) | GrossSideArea (m2) | NetSideArea (m2) | GrossVolume (m3) | NetVolume (m3) | 001_Nimetus | 335_Välispiire | 605_Neto-pindala (m2) | 600_Bruto-pindala (m2)
 | 1.korrus | 5571.78 | 4410 | 2.22871 | 24.5715 | 21.4276 | 9.82861 | 8.57105 | Olemasolev sisesein | no | 21.4276 | 26.9465
 | 1.korrus | 7489.61 | 4560 | 3.07184 | 33.8043 | 33.8043 | 13.5217 | 13.5217 | Olemasolev sisesein | no | 33.8043 | 36.9342
 | 1.korrus | 1307.75 | 4410 | 0.5231 | 5.36184 | 5.36184 | 2.14474 | 2.14474 | Olemasolev sisesein | no | 5.36177 | 7.77488
VS-XX | 1.korrus | 15328.8 | 4560 | 6.1075 | 69.6255 | 63.5747 | 27.8502 | 25.4299 | Olemasolev välissein | yes | 63.5747 | 71.5407 | AR_Sein - 205_Tähis: VS-XX
 | 1.korrus | 5249.81 | 4560 | 2.09992 | 23.9391 | 21.2133 | 9.57565 | 8.48533 | Olemasolev sisesein | no | 21.2133 | 23.9391
VS-XX | 2.korrus | 15478.8 | 5193.47 | 5.65134 | 65.5929 | 59.8689 | 26.2368 | 23.9472 | Olemasolev välissein | yes | 59.8689 | 81.4791 | AR_Sein - 205_Tähis: VS-XX
 | 2.korrus | 14968.8 | 2520 | 5.4675 | 36.6201 | 26.2954 | 14.648 | 10.7079 | Olemasolev sisesein | no | 26.2954 | 39.5357

# IfcWall: GENEERILINE - KONSTRUKTRIOON 410, VS-XX
In: 1.korrus
Classification: 1.24 IfcWallType (sein) (IPI ÜBN); Material: GENEERILINE - KONSTRUKTRIOON
AR_Sein - 001_Nimetus: Olemasolev välissein; 335_Välispiire: yes; 340_Soojusläbivus: 0; 605_Neto-pindala: 106.131 m2; 600_Bruto-pindala: 174.366 m2; 500_Kandev: no; 505_Paksus: 410 mm; 376_Viimistlus-väljast: Paint - Light Gray; 205_Tähis: VS-XX
AC_Pset_RenovationAndPhasing - Renovation Status: Existing
BaseQuantities - Length: 15358.7 mm; Height: 8053.47 mm; Width: 410 mm; GrossFootprintArea: 6.44056 m2; NetFootprintArea: 6.44056 m2; GrossSideArea: 109.593 m2; NetSideArea: 106.131 m2; GrossVolume: 44.933 m3; NetVolume: 43.5138 m3

# IfcWall: GENEERILINE - KONSTRUKTRIOON 420 (7)
Classification: 1.24 IfcWallType (sein) (IPI ÜBN); Material: GENEERILINE - KONSTRUKTRIOON
AR_Sein - 340_Soojusläbivus: 0; 505_Paksus: 420 mm
AC_Pset_RenovationAndPhasing - Renovation Status: Existing
BaseQuantities - Width: 420 mm
Name | In | 001_Nimetus | 335_Välispiire | 605_Neto-pindala (m2) | 600_Bruto-pindala (m2) | 500_Kandev | 376_Viimistlus-väljast | 205_Tähis | Length (mm) | Height (mm) | GrossFootprintArea (m2) = NetFootprintArea (m2) | GrossSideArea (m2) | NetSideArea (m2) | GrossVolume (m3) | NetVolume (m3)
VS-XX | 1.korrus | Olemasolev välissein | yes | 20.8639 | 33.5239 | no | Paint - Light Gray | VS-XX | 7351.74 | 4560 | 3.08773 | 33.5239 | 20.8639 | 14.08 | 8.76284
VS-XX | 1.korrus | Olemasolev välissein | yes | 91.9132 | 257.5 | no | Paint - Pink | VS-XX | 24292.4 | 5724.1 | 10.2028 | 137.802 | 93.1635 | 57.8768 | 39.1287
VS-XX | 1.korrus | Olemasolev välissein | yes | 68.7882 | 93.9914 | no | Paint - Pink | VS-XX | 20522.1 | 4580 | 8.61929 | 89.7925 | 64.5893 | 39.095 | 28.5096
SS-XX | 1.korrus | Olemasolev sisesein | no | 85.9685 | 89.6678 | yes | Paint - Light Gray | SS-XX | 12485.3 | 7880.56 | 5.36564 | 85.9685 | 85.9685 | 36.1068 | 36.1068
VS-XX | 1.korrus | Olemasolev välissein | yes | 392.678 | 914.923 | no | Paint - Light Gray | VS-XX | 86108.5 | 8009.27 | 36.2517 | 546.694 | 389.51 | 232.323 | 166.314
VS-XX | 1.korrus | Olemasolev välissein | yes | 11.9227 | 15.007 | no | Paint - Light Gray | VS-XX | 3091.01 | 4560 | 1.38222 | 15.007 | 11.9227 | 6.30294 | 5.00754
VS-XX | 2.korrus | Olemasolev välissein | yes | 25.8195 | 36.7097 | no | Paint - Light Gray | VS-XX | 10442.7 | 3449.27 | 4.46995 | 34.8498 | 23.9596 | 15.1828 | 10.6089

# IfcWall: GENEERILINE - KONSTRUKTRIOON 480, VS-XX
In: 1.korrus
Classification: 1.24 IfcWallType (sein) (IPI ÜBN); Material: GENEERILINE - KONSTRUKTRIOON
AR_Sein - 001_Nimetus: Olemasolev välissein; 335_Välispiire: yes; 340_Soojusläbivus: 0; 605_Neto-pindala: 17.6547 m2; 600_Bruto-pindala: 17.6547 m2; 500_Kandev: no; 505_Paksus: 480 mm; 376_Viimistlus-väljast: Paint - Pink; 205_Tähis: VS-XX
AC_Pset_RenovationAndPhasing - Renovation Status: Existing
BaseQuantities - Length: 3871.65 mm; Height: 4560 mm; Width: 480 mm; GrossFootprintArea: 1.85839 m2; NetFootprintArea: 1.85839 m2; GrossSideArea: 17.2878 m2; NetSideArea: 17.2878 m2; GrossVolume: 8.44453 m3; NetVolume: 8.44453 m3

# IfcWall: GENEERILINE - KONSTRUKTRIOON 500, VS-XX
In: 1.korrus
Classification: 1.24 IfcWallType (sein) (IPI ÜBN); Material: GENEERILINE - KONSTRUKTRIOON
AR_Sein - 001_Nimetus: Olemasolev välissein; 335_Välispiire: yes; 340_Soojusläbivus: 0; 605_Neto-pindala: 102.183 m2; 600_Bruto-pindala: 132.874 m2; 500_Kandev: no; 505_Paksus: 500 mm; 376_Viimistlus-väljast: Paint -Yellow; 205_Tähis: VS-XX
BaseQuantities - Length: 18878.7 mm; Height: 6979.18 mm; Width: 500 mm; GrossFootprintArea: 9.51934 m2; NetFootprintArea: 9.51934 m2; GrossSideArea: 131.661 m2; NetSideArea: 103.933 m2; GrossVolume: 65.8303 m3; NetVolume: 51.9716 m3
AC_Pset_RenovationAndPhasing - Renovation Status: Existing

# IfcWall: GENEERILINE - KONSTRUKTRIOON 520, VS-XX
In: 1.korrus
Classification: 1.24 IfcWallType (sein) (IPI ÜBN); Material: GENEERILINE - KONSTRUKTRIOON
BaseQuantities - Length: 11630.2 mm; Height: 5796.62 mm; Width: 520 mm; GrossFootprintArea: 6.04772 m2; NetFootprintArea: 6.04772 m2; GrossSideArea: 66.6797 m2; NetSideArea: 59.9929 m2; GrossVolume: 34.6735 m3; NetVolume: 31.208 m3
AC_Pset_RenovationAndPhasing - Renovation Status: Existing
AR_Sein - 001_Nimetus: Olemasolev välissein; 335_Välispiire: yes; 340_Soojusläbivus: 0; 605_Neto-pindala: 59.1106 m2; 600_Bruto-pindala: 123.28 m2; 500_Kandev: no; 505_Paksus: 520 mm; 376_Viimistlus-väljast: Paint -Yellow; 205_Tähis: VS-XX

# IfcWall: GENEERILINE - KONSTRUKTRIOON 540
In: 1.korrus
Classification: 1.24 IfcWallType (sein) (IPI ÜBN); Material: GENEERILINE - KONSTRUKTRIOON
AR_Sein - 001_Nimetus: Olemasolev sisesein; 335_Välispiire: no; 340_Soojusläbivus: 0; 605_Neto-pindala: 5.3423 m2; 600_Bruto-pindala: 10.9752 m2; 500_Kandev: no; 505_Paksus: 540 mm; 376_Viimistlus-väljast: Paint - Light Gray
AC_Pset_RenovationAndPhasing - Renovation Status: Existing
BaseQuantities - Length: 2039.34 mm; Height: 4560 mm; Width: 540 mm; GrossFootprintArea: 1.10124 m2; NetFootprintArea: 1.10124 m2; GrossSideArea: 8.85035 m2; NetSideArea: 5.63405 m2; GrossVolume: 4.85504 m3; NetVolume: 3.11824 m3

# IfcWall: GENEERILINE - KONSTRUKTRIOON 550, VS-XX
In: 1.korrus
Classification: 1.24 IfcWallType (sein) (IPI ÜBN); Material: GENEERILINE - KONSTRUKTRIOON
AC_Pset_RenovationAndPhasing - Renovation Status: Existing
AR_Sein - 001_Nimetus: Olemasolev välissein; 335_Välispiire: yes; 340_Soojusläbivus: 0; 605_Neto-pindala: 103.8 m2; 600_Bruto-pindala: 132.875 m2; 500_Kandev: no; 505_Paksus: 550 mm; 376_Viimistlus-väljast: Paint -Yellow; 205_Tähis: VS-XX
BaseQuantities - Length: 18878.4 mm; Height: 6979.18 mm; Width: 550 mm; GrossFootprintArea: 10.4715 m2; NetFootprintArea: 10.4715 m2; GrossSideArea: 124.826 m2; NetSideArea: 95.751 m2; GrossVolume: 72.1504 m3; NetVolume: 56.1591 m3

# IfcWall: GENEERILINE - KONSTRUKTRIOON 560 (3)
In: 1.korrus
Classification: 1.24 IfcWallType (sein) (IPI ÜBN); Material: GENEERILINE - KONSTRUKTRIOON
AC_Pset_RenovationAndPhasing - Renovation Status: Existing
BaseQuantities - Width: 560 mm
AR_Sein - 001_Nimetus: Olemasolev välissein; 335_Välispiire: yes; 340_Soojusläbivus: 0; 500_Kandev: no; 505_Paksus: 560 mm; 205_Tähis: VS-XX
Name | Length (mm) | Height (mm) | GrossFootprintArea (m2) = NetFootprintArea (m2) | GrossSideArea (m2) | NetSideArea (m2) | GrossVolume (m3) | NetVolume (m3) | 605_Neto-pindala (m2) | 600_Bruto-pindala (m2) | 376_Viimistlus-väljast
VS-XX | 1271.1 | 2485.53 | 0.812615 | 3.47747 | 3.47747 | 1.94738 | 1.94738 | 3.47747 | 13.9305 | RAL 7043
VS-XX | 6348.33 | 5806.36 | 3.55506 | 36.4182 | 33.0748 | 20.3938 | 18.5288 | 32.5786 | 67.2923 | Paint -Yellow
VS-XX | 6276.96 | 5806.36 | 3.5151 | 34.4876 | 31.1442 | 20.169 | 18.304 | 32.174 | 66.5358 | Paint -Yellow

# IfcWall: GENEERILINE - KONSTRUKTRIOON 60 (3)
In: 1.korrus
Classification: 1.24 IfcWallType (sein) (IPI ÜBN); Material: GENEERILINE - KONSTRUKTRIOON
AR_Sein - 001_Nimetus: Olemasolev välissein; 335_Välispiire: yes; 340_Soojusläbivus: 0; 500_Kandev: no; 505_Paksus: 60 mm; 376_Viimistlus-väljast: Paint - Light Gray; 205_Tähis: VS-XX
AC_Pset_RenovationAndPhasing - Renovation Status: Existing
BaseQuantities - Width: 60 mm
Name | 605_Neto-pindala (m2) | 600_Bruto-pindala (m2) | Length (mm) | Height (mm) | GrossFootprintArea (m2) = NetFootprintArea (m2) | GrossSideArea (m2) | NetSideArea (m2) | GrossVolume (m3) | NetVolume (m3)
VS-XX | 13.8738 | 15.2521 | 5069.49 | 2973.48 | 0.302369 | 13.8686 | 13.8686 | 0.832113 | 0.832113
VS-XX | 30.3014 | 30.453 | 11988.8 | 2532.88 | 0.719325 | 30.2133 | 30.2133 | 1.81151 | 1.81151
VS-XX | 12.6611 | 15.5552 | 5072.81 | 2974.07 | 0.306169 | 14.0314 | 12.6554 | 0.842059 | 0.759499

# IfcWall: GENEERILINE - KONSTRUKTRIOON 660, SS-XX
In: 1.korrus
Classification: 1.24 IfcWallType (sein) (IPI ÜBN); Material: GENEERILINE - KONSTRUKTRIOON
AC_Pset_RenovationAndPhasing - Renovation Status: Existing
AR_Sein - 001_Nimetus: Olemasolev sisesein; 335_Välispiire: no; 340_Soojusläbivus: 0; 605_Neto-pindala: 91.4393 m2; 600_Bruto-pindala: 135.419 m2; 500_Kandev: yes; 505_Paksus: 660 mm; 376_Viimistlus-väljast: Paint - Light Gray; 205_Tähis: SS-XX
BaseQuantities - Length: 12275.3 mm; Height: 8480.5 mm; Width: 660 mm; GrossFootprintArea: 8.10172 m2; NetFootprintArea: 8.10172 m2; GrossSideArea: 93.9593 m2; NetSideArea: 91.4393 m2; GrossVolume: 62.0131 m3; NetVolume: 60.3499 m3

# IfcWall: GENEERILINE - KONSTRUKTRIOON 720, VS-XX
In: 1.korrus
Classification: 1.24 IfcWallType (sein) (IPI ÜBN); Material: GENEERILINE - KONSTRUKTRIOON
AR_Sein - 001_Nimetus: Olemasolev välissein; 335_Välispiire: yes; 340_Soojusläbivus: 0; 605_Neto-pindala: 21.8529 m2; 600_Bruto-pindala: 41.2087 m2; 500_Kandev: no; 505_Paksus: 720 mm; 376_Viimistlus-väljast: Paint - Pink; 205_Tähis: VS-XX
BaseQuantities - Length: 3888.02 mm; Height: 6979.18 mm; Width: 720 mm; GrossFootprintArea: 2.79937 m2; NetFootprintArea: 2.79937 m2; GrossSideArea: 22.1987 m2; NetSideArea: 22.1987 m2; GrossVolume: 15.9831 m3; NetVolume: 15.9831 m3
AC_Pset_RenovationAndPhasing - Renovation Status: Existing

# IfcWall: GENEERILINE - KONSTRUKTRIOON 80 (2)
In: 1.korrus
Classification: 1.24 IfcWallType (sein) (IPI ÜBN); Material: GENEERILINE - KONSTRUKTRIOON
AR_Sein - 001_Nimetus: Olemasolev välissein; 335_Välispiire: yes; 340_Soojusläbivus: 0; 500_Kandev: no; 505_Paksus: 80 mm; 376_Viimistlus-väljast: RAL 5012; 205_Tähis: VS-XX
AC_Pset_RenovationAndPhasing - Renovation Status: Existing
BaseQuantities - Width: 80 mm
Name | 605_Neto-pindala (m2) | 600_Bruto-pindala (m2) | Length (mm) | Height (mm) | GrossFootprintArea (m2) = NetFootprintArea (m2) | GrossSideArea (m2) | NetSideArea (m2) | GrossVolume (m3) | NetVolume (m3)
VS-XX | 147.417 | 345.932 | 35882.3 | 5071.65 | 2.20099 | 181.797 | 147.806 | 14.5437 | 11.8245
VS-XX | 72.276 | 119.589 | 12323.5 | 6735.15 | 0.97828 | 72.2765 | 72.2765 | 5.78212 | 5.78212

# IfcWall: GENEERILINE - KONSTRUKTRIOON 85
In: 1.korrus
Classification: 1.24 IfcWallType (sein) (IPI ÜBN); Material: GENEERILINE - KONSTRUKTRIOON
AC_Pset_RenovationAndPhasing - Renovation Status: Existing
AR_Sein - 001_Nimetus: Olemasolev sisesein; 335_Välispiire: no; 340_Soojusläbivus: 0; 605_Neto-pindala: 17.4891 m2; 600_Bruto-pindala: 63.2201 m2; 500_Kandev: no; 505_Paksus: 85 mm; 376_Viimistlus-väljast: Paint - Light Gray
BaseQuantities - Length: 5906.58 mm; Height: 3120.91 mm; Width: 85 mm; GrossFootprintArea: 0.502059 m2; NetFootprintArea: 0.502059 m2; GrossSideArea: 17.4891 m2; NetSideArea: 17.4891 m2; GrossVolume: 1.48658 m3; NetVolume: 1.48658 m3

# IfcWall: GENEERILINE - KONSTRUKTRIOON 90
In: 1.korrus
Classification: 1.24 IfcWallType (sein) (IPI ÜBN); Material: GENEERILINE - KONSTRUKTRIOON
AR_Sein - 001_Nimetus: Olemasolev sisesein; 335_Välispiire: no; 340_Soojusläbivus: 0; 605_Neto-pindala: 9.52425 m2; 600_Bruto-pindala: 58.7464 m2; 500_Kandev: no; 505_Paksus: 90 mm; 376_Viimistlus-väljast: Paint - Light Gray
BaseQuantities - Length: 5906.92 mm; Height: 2775.89 mm; Width: 90 mm; GrossFootprintArea: 0.282323 m2; NetFootprintArea: 0.282323 m2; GrossSideArea: 15.4651 m2; NetSideArea: 9.52419 m2; GrossVolume: 1.39186 m3; NetVolume: 0.857177 m3
AC_Pset_RenovationAndPhasing - Renovation Status: Existing

# IfcWall: GENEERILINE - VÄLINE VOODER 200, Sisesein
In: 1.korrus
Classification: 1.24 IfcWallType (sein) (IPI ÜBN); Material: GENEERILINE - VÄLINE VOODER
AR_Sein - 001_Nimetus: Sisesein; 325_Helipidavus: 43dB; 335_Välispiire: no; 340_Soojusläbivus: 0; 605_Neto-pindala: 0.532959 m2; 600_Bruto-pindala: 0.532959 m2; 500_Kandev: no; 505_Paksus: 200 mm; 376_Viimistlus-väljast: RAL9017 must; 205_Tähis: Sisesein
AC_Pset_RenovationAndPhasing - Renovation Status: Existing
BaseQuantities - Length: 199.61 mm; Height: 2670 mm; Width: 200 mm; GrossFootprintArea: 0.039922 m2; NetFootprintArea: 0.039922 m2; GrossSideArea: 0.532959 m2; NetSideArea: 0.532959 m2; GrossVolume: 0.106592 m3; NetVolume: 0.106592 m3

# IfcWall: GENEERILINE - VÄLINE VOODER 250, Sisesein
In: 1.korrus
Classification: 1.24 IfcWallType (sein) (IPI ÜBN); Material: GENEERILINE - VÄLINE VOODER
AR_Sein - 001_Nimetus: Sisesein; 325_Helipidavus: 43dB; 335_Välispiire: no; 340_Soojusläbivus: 0; 605_Neto-pindala: 0.701861 m2; 600_Bruto-pindala: 3.64576 m2; 500_Kandev: no; 505_Paksus: 250 mm; 376_Viimistlus-väljast: RAL9017 must; 205_Tähis: Sisesein
AC_Pset_RenovationAndPhasing - Renovation Status: Existing
BaseQuantities - Length: 94.5905 mm; Height: 7420 mm; Width: 250 mm; GrossFootprintArea: 0.0236476 m2; NetFootprintArea: 0.0236476 m2; GrossSideArea: 0.701861 m2; NetSideArea: 0.701861 m2; GrossVolume: 0.175465 m3; NetVolume: 0.175465 m3

# IfcWall: Precast Single Tee 3 356 x 265
In: 2.korrus
Classification: 1.24 IfcWallType (sein) (IPI ÜBN); Material: GENEERILINE - KONSTRUKTRIOON
AR_Sein - 001_Nimetus: Olemasolev sein; 335_Välispiire: no; 340_Soojusläbivus: 0; 500_Kandev: no; 505_Paksus: 355.721 mm
AC_Pset_RenovationAndPhasing - Renovation Status: Existing
BaseQuantities - Length: 7504.17 mm; GrossFootprintArea: 1.6446 m2; NetFootprintArea: 1.6446 m2; GrossVolume: 0.47656 m3; NetVolume: 0.47656 m3

# IfcWall: Precast Single Tee 3 356 x 275 (5)
Classification: 1.24 IfcWallType (sein) (IPI ÜBN); Material: GENEERILINE - KONSTRUKTRIOON
AR_Sein - 001_Nimetus: Olemasolev sein; 335_Välispiire: no; 340_Soojusläbivus: 0; 500_Kandev: no; 505_Paksus: 355.721 mm
AC_Pset_RenovationAndPhasing - Renovation Status: Existing
Name | In | Length (mm) | GrossFootprintArea (m2) = NetFootprintArea (m2) | GrossVolume (m3) = NetVolume (m3)
 | 1.korrus | 14977.1 | 3.28236 | 0.993078
 | 1.korrus | 14968.9 | 3.28055 | 0.992531
 | 1.korrus | 14969.2 | 3.28064 | 0.992556
 | 2.korrus | 7464.64 | 1.63594 | 0.494954
 | 2.korrus | 15019.6 | 3.29167 | 0.995895

# IfcWall: SS-1.1 190 (13)
Classification: 1.24 IfcWallType (sein) (IPI ÜBN); Material: Betoonplokk
AR_Sein - 001_Nimetus: Sisesein; 325_Helipidavus: 43dB; 335_Välispiire: no; 340_Soojusläbivus: 0; 500_Kandev: no; 505_Paksus: 190 mm; 376_Viimistlus-väljast: SA_seinad_F499; 205_Tähis: SS-1.1
AC_Pset_RenovationAndPhasing - Renovation Status: New
BaseQuantities - Width: 190 mm
Name | In | 605_Neto-pindala (m2) | 600_Bruto-pindala (m2) | Length (mm) | Height (mm) | GrossFootprintArea (m2) = NetFootprintArea (m2) | GrossSideArea (m2) | NetSideArea (m2) | GrossVolume (m3) | NetVolume (m3)
Sisesein | 1.korrus | 31.8853 | 34.3843 | 8640.99 | 3690 | 1.64179 | 31.8853 | 31.8853 | 6.0582 | 6.0582
Sisesein | 1.korrus | 75.763 | 82.6488 | 21992.3 | 3690 | 3.67979 | 81.5022 | 75.763 | 15.4854 | 14.395
Sisesein | 1.korrus | 10.369 | 11.1301 | 2740.04 | 3690 | 0.533907 | 10.369 | 10.369 | 1.97012 | 1.97012
Sisesein | 1.korrus | 10.3689 | 11.13 | 2740 | 3690 | 0.5339 | 10.3689 | 10.3689 | 1.97009 | 1.97009
Sisesein | 1.korrus | 30.8275 | 37.4698 | 9909.69 | 3690 | 1.36604 | 36.5667 | 30.8275 | 6.94768 | 5.85723
Sisesein | 1.korrus | 20.7225 | 24.8917 | 7299.61 | 3410 | 1.13213 | 24.7272 | 20.887 | 4.71297 | 3.98333
Sisesein | 1.korrus | 10.3689 | 11.13 | 2835 | 3690 | 0.5339 | 10.3689 | 10.3689 | 1.97009 | 1.97009
Sisesein | 1.korrus | 42.9551 | 44.8092 | 11571 | 3690 | 2.21178 | 42.9551 | 42.9551 | 8.16147 | 8.16147
Sisesein | 1.korrus | 2.63459 | 4.36519 | 1559 | 2800 | 0.14231 | 4.35444 | 2.64534 | 0.829386 | 0.504657
Sisesein | 1.korrus | 3.02205 | 5.99715 | 1628.91 | 3530 | 0.0548925 | 5.99715 | 3.02205 | 1.13946 | 0.574189
2 x Sisesein | 2.korrus | 1.89 | 1.89 | 900 | 2100 | 0.171 | 1.89 | 1.89 | 0.3591 | 0.3591
Sisesein | 2.korrus | 1.191 | 3.102 | 1175 | 2640 | 0.22325 | 3.102 | 1.191 | 0.58938 | 0.22629

# IfcWall: SS-1.2 140 (27)
In: 1.korrus
Classification: 1.24 IfcWallType (sein) (IPI ÜBN); Material: Betoonõõnesplokk
AR_Sein - 001_Nimetus: Sisesein; 325_Helipidavus: 43dB; 335_Välispiire: no; 340_Soojusläbivus: 0; 500_Kandev: no; 505_Paksus: 140 mm; 376_Viimistlus-väljast: SA_seinad_F499; 205_Tähis: SS-1.2
BaseQuantities - Width: 140 mm
Name | 605_Neto-pindala (m2) | 600_Bruto-pindala (m2) | Renovation Status | Length (mm) | Height (mm) | GrossFootprintArea (m2) = NetFootprintArea (m2) | GrossSideArea (m2) | NetSideArea (m2) | GrossVolume (m3) | NetVolume (m3)
2 x Sisesein | 2.9458 | 2.9458 | Existing | 1430 | 2060 | 0.2002 | 2.9458 | 2.9458 | 0.412412 | 0.412412
Sisesein | 23.48 | 29.8713 | New | 7809.69 | 3690 | 0.789556 | 27.513 | 23.4618 | 3.85436 | 3.28719
Sisesein | 9.85239 | 11.1301 | New | 2670.02 | 3690 | 0.373803 | 9.85239 | 9.85239 | 1.37933 | 1.37933
Sisesein | 58.5186 | 67.8303 | New | 17609.7 | 3690 | 2.05656 | 64.2789 | 58.5186 | 8.99904 | 8.1926
Sisesein | 6.23259 | 9.89665 | New | 2477.56 | 3690 | 0.178865 | 8.40239 | 6.27129 | 1.18175 | 0.883397
Sisesein | 5.23608 | 6.30326 | New | 1419 | 3690 | 0.19866 | 5.23611 | 5.23611 | 0.733056 | 0.733056
Sisesein | 5.45329 | 7.67899 | New | 1941.03 | 3690 | 0.158344 | 7.16239 | 5.45329 | 1.00273 | 0.763461
Sisesein | 2.8598 | 8.1249 | New | 1810 | 1580 | 0 | 6.6789 | 2.8598 | 0.935046 | 0.400372
Sisesein | 2.3858 | 6.14749 | New | 1510 | 1580 | 0.0000122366 | 5.53414 | 2.34805 | 0.780064 | 0.334011
Sisesein | 11.0726 | 12.3264 | New | 3157.48 | 3690 | 0.445547 | 11.0726 | 11.0726 | 1.55017 | 1.55017
Sisesein | 10.5019 | 12.8589 | New | 3580.94 | 3410 | 0.387932 | 12.1741 | 10.465 | 1.70952 | 1.47025
Sisesein | 3.069 | 4.0238 | New | 900 | 3410 | 0.126 | 3.069 | 3.069 | 0.42966 | 0.42966
Sisesein | 10.5019 | 12.8589 | New | 3580.94 | 3410 | 0.387932 | 12.211 | 10.5019 | 1.70954 | 1.47027
2 x Sisesein | 4.797 | 5.8618 | New | 1300 | 3690 | 0.182 | 4.797 | 4.797 | 0.67158 | 0.67158
Sisesein | 12.9315 | 14.2078 | New | 3499.6 | 3710 | 0.489944 | 12.9225 | 12.9225 | 1.80791 | 1.80791
Sisesein | 12.9135 | 14.2078 | New | 3499.6 | 3690 | 0.489944 | 12.9135 | 12.9135 | 1.80789 | 1.80789
Sisesein | 7.78622 | 13.8438 | New | 3499.6 | 3690 | 0.149744 | 12.9135 | 7.78622 | 1.80789 | 1.09007
Sisesein | 3.321 | 4.375 | New | 900 | 3690 | 0.126 | 3.321 | 3.321 | 0.46494 | 0.46494
Sisesein | 4.79699 | 5.86179 | New | 1300 | 3690 | 0.182 | 4.79699 | 4.79699 | 0.671579 | 0.671579
Sisesein | 6.4341 | 10.4251 | New | 2670 | 3690 | 0.147 | 9.8523 | 6.4341 | 1.37932 | 0.900774
Sisesein | 9.85235 | 11.1301 | New | 2670.01 | 3690 | 0.373802 | 9.85235 | 9.85235 | 1.37933 | 1.37933
Sisesein | 4.79701 | 5.86181 | New | 1300 | 3690 | 0.182 | 4.79701 | 4.79701 | 0.671582 | 0.671582
Sisesein | 3.62268 | 5.78497 | New | 1489.29 | 3690 | 0.0769891 | 5.7213 | 3.5902 | 0.805524 | 0.50717
Sisesein | 6.4342 | 11.1301 | New | 2670.03 | 3690 | 0.147004 | 9.8524 | 6.4342 | 1.37934 | 0.900788
Sisesein | 2.65707 | 4.896 | New | 1558.57 | 2800 | 0.104944 | 4.364 | 2.65707 | 0.61096 | 0.37199

# IfcWall: SS-2.1 147 (23)
Classification: 1.24 IfcWallType (sein) (IPI ÜBN)
AC_Pset_RenovationAndPhasing - Renovation Status: New
BaseQuantities - Width: 147 mm
AR_Sein - 001_Nimetus: Sisesein; 325_Helipidavus: 43dB; 335_Välispiire: no; 340_Soojusläbivus: 0; 500_Kandev: no; 505_Paksus: 147 mm; 376_Viimistlus-väljast: SA_seinad_F499; 205_Tähis: SS-2.1
Name | In | Length (mm) | Height (mm) | GrossFootprintArea (m2) = NetFootprintArea (m2) | GrossSideArea (m2) | NetSideArea (m2) | GrossVolume (m3) | NetVolume (m3) | 605_Neto-pindala (m2) | 600_Bruto-pindala (m2)
Sisesein | 1.korrus | 3927.43 | 1000 | 0.584653 | 3.30451 | 3.30451 | 0.532292 | 0.532292 | 3.24823 | 4.14764
Sisesein | 1.korrus | 1799.49 | 875 | 0.264525 | 1.51157 | 1.51157 | 0.228886 | 0.228886 | 1.39902 | 1.80051
Sisesein | 1.korrus | 419.453 | 875 | 0.0568092 | 0.34688 | 0.34688 | 0.0491175 | 0.0491175 | 0.403153 | 0.585474
Sisesein | 2.korrus | 12113.3 | 3290.71 | 0.109358 | 37.6005 | 11.4463 | 5.46957 | 1.62395 | 9.47063 | 40.5826
Sisesein | 2.korrus | 2409.88 | 4305.51 | 0.272128 | 11.022 | 9.31292 | 1.63959 | 1.38835 | 10.1895 | 14.526
Sisesein | 2.korrus | 973.5 | 3260 | 0.138254 | 2.95519 | 2.95519 | 0.450708 | 0.450708 | 2.934 | 3.89244
Sisesein | 2.korrus | 6716.85 | 3290.71 | 0.0323319 | 21.5097 | 5.40032 | 3.22958 | 0.850977 | 5.28178 | 24.8265
Sisesein | 2.korrus | 4235.85 | 3260 | 0.22745 | 13.7835 | 7.83332 | 2.09182 | 1.21715 | 7.79749 | 15.7504
Sisesein | 2.korrus | 3726.14 | 3240 | 0.545021 | 11.0889 | 11.0889 | 1.74682 | 1.74682 | 11.2724 | 13.1353
Sisesein | 2.korrus | 2851.24 | 3240 | 0.266008 | 8.22922 | 6.09812 | 1.32274 | 1.00947 | 6.03724 | 9.60213
Sisesein | 2.korrus | 6719.96 | 3260 | 0.839637 | 21.7098 | 17.7037 | 3.22122 | 2.63234 | 17.9084 | 22.3937
Sisesein | 2.korrus | 4833.46 | 4749.24 | 0.71256 | 22.526 | 22.526 | 3.35852 | 3.35852 | 22.4012 | 26.4528
Sisesein | 2.korrus | 5667.22 | 3240 | 0.833082 | 17.5432 | 16.3511 | 2.66924 | 2.49401 | 16.0982 | 18.9091
Sisesein | 2.korrus | 1235.3 | 3260 | 0.189397 | 4.04892 | 4.04892 | 0.617436 | 0.617436 | 4.21404 | 4.69326
Sisesein | 2.korrus | 399.959 | 3260 | 0.0537935 | 1.28202 | 1.28202 | 0.175367 | 0.175367 | 1.44714 | 1.49083
Sisesein | 2.korrus | 1047 | 3260 | 0.157994 | 3.06114 | 3.06114 | 0.51506 | 0.51506 | 3.06114 | 3.89244
Sisesein | 2.korrus | 3973.71 | 4745.76 | 0.005954 | 16.6424 | 6.46867 | 2.42816 | 0.932438 | 6.1519 | 21.7761
Sisesein | 2.korrus | 4674.33 | 3290 | 0.696359 | 14.6288 | 14.6288 | 2.21232 | 2.21232 | 14.6499 | 15.6204
Sisesein | 2.korrus | 2053 | 4382.78 | 0.269671 | 7.33296 | 7.33296 | 1.09517 | 1.09517 | 7.33296 | 8.72189
Sisesein | 2.korrus | 2030.14 | 3240 | 0.301325 | 6.35433 | 6.35433 | 0.965439 | 0.965439 | 6.29667 | 7.50863
Sisesein | 2.korrus | 3203 | 2471.01 | 0.473649 | 6.27488 | 6.27488 | 0.953399 | 0.953399 | 6.27488 | 8.57551
Sisesein | 2.korrus | 4453.83 | 3290 | 0.571036 | 14.7281 | 12.808 | 2.24742 | 1.96517 | 12.6027 | 16.268
Sisesein | 2.korrus | 1779.79 | 3290 | 0.264437 | 5.69277 | 5.69277 | 0.862145 | 0.862145 | 5.80337 | 7.5787

# IfcWall: SS-2.1.1 197 (2)
Classification: 1.24 IfcWallType (sein) (IPI ÜBN)
AR_Sein - 001_Nimetus: Sisesein; 325_Helipidavus: 43dB; 335_Välispiire: no; 340_Soojusläbivus: 0; 500_Kandev: no; 505_Paksus: 197 mm; 376_Viimistlus-väljast: SA_seinad_F499; 205_Tähis: SS-2.1.1
BaseQuantities - Width: 197 mm
Name | In | 605_Neto-pindala (m2) | 600_Bruto-pindala (m2) | Renovation Status | Length (mm) | Height (mm) | GrossFootprintArea (m2) = NetFootprintArea (m2) | GrossSideArea (m2) = NetSideArea (m2) | GrossVolume (m3) = NetVolume (m3)
Sisesein | 1.korrus | 0.984728 | 1.16113 | Existing | 2344.59 | 420 | 0.461884 | 0.984728 | 0.193991
Sisesein | 2.korrus | 13.5709 | 15.4846 | New | 14761.2 | 952.598 | 2.90233 | 13.2034 | 2.62148

# IfcWall: SS-2.2 147 (25)
In: 2.korrus
Classification: 1.24 IfcWallType (sein) (IPI ÜBN)
AR_Sein - 001_Nimetus: Sisesein; 325_Helipidavus: 43dB; 335_Välispiire: no; 340_Soojusläbivus: 0; 500_Kandev: no; 505_Paksus: 147 mm; 376_Viimistlus-väljast: SA_seinad_F499; 205_Tähis: SS-2.2
AC_Pset_RenovationAndPhasing - Renovation Status: New
BaseQuantities - Width: 147 mm
Name | 605_Neto-pindala (m2) | 600_Bruto-pindala (m2) | Length (mm) | Height (mm) | GrossFootprintArea (m2) = NetFootprintArea (m2) | GrossSideArea (m2) | NetSideArea (m2) | GrossVolume (m3) | NetVolume (m3)
Sisesein | 5.97726 | 13.2554 | 3971.88 | 3240 | 0.213145 | 11.8371 | 6.70975 | 1.82769 | 1.07398
Sisesein | 3.57411 | 4.01284 | 1079.39 | 3260 | 0.155862 | 3.32128 | 3.32128 | 0.508103 | 0.508103
Sisesein | 19.5086 | 23.1888 | 4119.45 | 4832.72 | 0.608367 | 19.4275 | 19.4275 | 2.90178 | 2.90178
Sisesein | 4.48485 | 4.52854 | 1331.77 | 3260 | 0.19077 | 4.31973 | 4.31973 | 0.62191 | 0.62191
Sisesein | 1.46835 | 3.39988 | 588.5 | 5135.77 | 0.0843006 | 2.11469 | 2.11469 | 0.331799 | 0.331799
Sisesein | 2.0022 | 5.93137 | 1667.7 | 3290 | 0.0636546 | 5.07576 | 2.10066 | 0.74848 | 0.31114
2 x Sisesein | 3.60679 | 4.94542 | 1223 | 3240 | 0.185397 | 3.60679 | 3.60679 | 0.582601 | 0.582601
Sisesein | 19.7045 | 27.297 | 7340.76 | 3260 | 0.790893 | 23.6549 | 19.8358 | 3.4457 | 2.88429
Sisesein | 18.5194 | 24.9314 | 4536 | 5316.65 | 0.688401 | 19.6245 | 19.6245 | 2.73492 | 2.73492
2 x Sisesein | 33.613 | 45.9865 | 7250.21 | 5607.49 | 1.06578 | 33.613 | 33.613 | 4.94111 | 4.94111
2 x Sisesein | 20.7297 | 24.9314 | 4536 | 5316.65 | 0.688401 | 20.7297 | 20.7297 | 3.05736 | 3.05736
Sisesein | 10.1462 | 15.0879 | 4159.96 | 3290 | 0.39116 | 13.2566 | 9.83839 | 2.00188 | 1.49941
Sisesein | 5.49897 | 8.10939 | 2340 | 3260.71 | 0.19551 | 7.43279 | 5.30169 | 1.12162 | 0.808348
Sisesein | 21.1765 | 24.6608 | 7269.02 | 3260.71 | 0.922884 | 23.5049 | 21.3738 | 3.49338 | 3.18011
Sisesein | 21.3401 | 36.1082 | 7145.22 | 5703.59 | 0.346526 | 33.0338 | 21.0523 | 4.94395 | 3.18267
Sisesein | 15.4198 | 15.6494 | 4800.43 | 3260 | 0.705663 | 15.5346 | 15.5346 | 2.28912 | 2.28912
Sisesein | 5.70881 | 6.88845 | 1819.02 | 3260 | 0.273012 | 5.81941 | 5.81941 | 0.884269 | 0.884269
Sisesein | 33.613 | 46.2405 | 7250.21 | 5607.49 | 1.06578 | 33.613 | 33.613 | 4.94111 | 4.94111
Sisesein | 3.04149 | 11.1138 | 3319.97 | 3240 | 0.0255936 | 10.0529 | 2.62329 | 1.53053 | 0.441157
Sisesein | 10.5763 | 11.1588 | 2186.5 | 5135.77 | 0.321416 | 10.5763 | 10.5763 | 1.55471 | 1.55471
Sisesein | 3.87307 | 7.2527 | 1853.29 | 3290 | 0.148513 | 5.91119 | 4.20209 | 0.872401 | 0.621163
Sisesein | 18.8302 | 22.6489 | 4270 | 5203.8 | 0.615181 | 19.2048 | 19.2048 | 2.81953 | 2.81953

# IfcWall: SS-2.4 92 (43)
Classification: 1.24 IfcWallType (sein) (IPI ÜBN)
AR_Sein - 001_Nimetus: Sisesein; 335_Välispiire: no; 340_Soojusläbivus: 0; 500_Kandev: no; 505_Paksus: 92 mm; 376_Viimistlus-väljast: SA_seinad_F499; 205_Tähis: SS-2.4
AC_Pset_RenovationAndPhasing - Renovation Status: New
BaseQuantities - Width: 92 mm
Name | In | 325_Helipidavus | 605_Neto-pindala (m2) | 600_Bruto-pindala (m2) | Length (mm) | Height (mm) | GrossFootprintArea (m2) = NetFootprintArea (m2) | GrossSideArea (m2) | NetSideArea (m2) | GrossVolume (m3) | NetVolume (m3)
Sisesein | 1.korrus | 6dB | 0.534616 | 1.16102 | 244.006 | 2700 | 0.0190746 | 0.534617 | 0.534617 | 0.0515013 | 0.0515013
Sisesein | 1.korrus | 6dB | 0.918003 | 0.918003 | 289.001 | 2700 | 0.0293951 | 0.882903 | 0.882903 | 0.0793668 | 0.0793668
Sisesein | 1.korrus | 6dB | 0.622752 | 1.0476 | 202.001 | 2700 | 0.0162371 | 0.521977 | 0.521977 | 0.0438384 | 0.0438384
Sisesein | 1.korrus | 6dB | 0.37161 | 0.627021 | 140.282 | 2700 | 0.012906 | 0.375256 | 0.375256 | 0.0348455 | 0.0348455
2 x Sisesein | 1.korrus | 43dB | 1.0812 | 1.35 | 408 | 2700 | 0.038394 | 1.0812 | 1.0812 | 0.101744 | 0.101744
2 x Sisesein | 1.korrus | 43dB | 1.0812 | 1.35 | 408 | 2700 | 0.0383941 | 1.0812 | 1.0812 | 0.101744 | 0.101744
Sisesein | 1.korrus | 43dB | 1.2471 | 1.35 | 454 | 2700 | 0.0394212 | 1.16415 | 1.16415 | 0.103901 | 0.103901
Sisesein | 1.korrus | 6dB | 0.8176 | 1.2096 | 246 | 2800 | 0.024979 | 0.7812 | 0.7812 | 0.0699412 | 0.0699412
Sisesein | 1.korrus | 6dB | 2.448 | 2.8288 | 900.001 | 2720 | 0.0828001 | 2.448 | 2.448 | 0.225216 | 0.225216
Sisesein | 1.korrus | 6dB | 2.052 | 2.6784 | 759.998 | 2700 | 0.0709468 | 2.06955 | 2.06955 | 0.191556 | 0.191556
Sisesein | 1.korrus | 6dB | 2.96892 | 3.618 | 1100 | 2700 | 0.101163 | 2.96892 | 2.96892 | 0.27314 | 0.27314
Sisesein | 1.korrus | 6dB | 2.862 | 3.888 | 1060 | 2700 | 0.09752 | 2.862 | 2.862 | 0.263304 | 0.263304
Sisesein | 1.korrus | 6dB | 1.77594 | 2.40264 | 698 | 2720 | 0.066563 | 1.89889 | 1.89889 | 0.180903 | 0.180903
Sisesein | 1.korrus | 6dB | 2.862 | 3.753 | 1060 | 2700 | 0.09752 | 2.862 | 2.862 | 0.263304 | 0.263304
Sisesein | 1.korrus | 6dB | 2.43 | 3.186 | 900 | 2700 | 0.0828 | 2.43 | 2.43 | 0.22356 | 0.22356
Sisesein | 1.korrus | 6dB | 2.052 | 2.6784 | 759.999 | 2700 | 0.0709469 | 2.06955 | 2.06955 | 0.191557 | 0.191557
Sisesein | 1.korrus | 6dB | 0.7812 | 1.3496 | 246 | 2800 | 0.020285 | 0.6706 | 0.6706 | 0.056798 | 0.056798
Sisesein | 1.korrus | 6dB | 1.78291 | 1.99621 | 693.338 | 2700 | 0.0661341 | 1.88956 | 1.88956 | 0.178562 | 0.178562
Sisesein | 1.korrus | 6dB | 1.03076 | 2.61347 | 246 | 3585 | 0.024979 | 0.98886 | 0.98886 | 0.088902 | 0.088902
Sisesein | 1.korrus | 6dB | 0.534589 | 1.16099 | 243.996 | 2700 | 0.0190736 | 0.534588 | 0.534588 | 0.0514987 | 0.0514987
Sisesein | 1.korrus | 6dB | 0.918005 | 0.918005 | 289.002 | 2700 | 0.0293952 | 0.882905 | 0.882905 | 0.0793669 | 0.0793669
Sisesein | 1.korrus | 6dB | 0.98487 | 2.61347 | 246 | 3585 | 0.020285 | 0.848435 | 0.848435 | 0.0721922 | 0.0721922
Sisesein | 1.korrus | 6dB | 2.29005 | 3.05145 | 894.174 | 2700 | 0.079917 | 2.32517 | 2.32517 | 0.215776 | 0.215776
Sisesein | 1.korrus | 6dB | 4.19869 | 4.66039 | 1634.07 | 2700 | 0.150334 | 4.34044 | 4.34044 | 0.405903 | 0.405903
Sisesein | 1.korrus | 43dB | 10.3399 | 45.0893 | 16607.7 | 2700 | 1.52921 | 14.6325 | 10.2021 | 1.33981 | 0.932195
Sisesein | 1.korrus | 43dB | 1.29055 | 1.35 | 454 | 2700 | 0.039421 | 0.757475 | 0.757475 | 0.102752 | 0.102752
Sisesein | 1.korrus | 6dB | 6.17641 | 7.20241 | 2287.56 | 2700 | 0.210455 | 6.17641 | 6.17641 | 0.56823 | 0.56823
Sisesein | 1.korrus | 43dB | 0.605043 | 0.71525 | 1054.07 | 550 | 0.100349 | 0.601467 | 0.601467 | 0.055192 | 0.055192
Sisesein | 1.korrus | 43dB | 0.267851 | 0.300001 | 453.456 | 550 | 0.0393707 | 0.245825 | 0.245825 | 0.0216539 | 0.0216539
Sisesein | 2.korrus | 6dB | 0.8176 | 1.0304 | 246 | 2800 | 0.027033 | 0.8176 | 0.8176 | 0.0756924 | 0.0756924
Sisesein | 2.korrus | 6dB | 0.7812 | 0.8176 | 246 | 2800 | 0.020285 | 0.6706 | 0.6706 | 0.056798 | 0.056798
Sisesein | 2.korrus | 6dB | 2.7188 | 3.4104 | 971 | 2800 | 0.091386 | 2.7552 | 2.7552 | 0.255881 | 0.255881
Sisesein | 2.korrus | 6dB | 3.08 | 4.1832 | 1100 | 2800 | 0.105308 | 3.1528 | 3.1528 | 0.294862 | 0.294862
Sisesein | 2.korrus | 6dB | 2.52 | 3.3432 | 900 | 2800 | 0.086908 | 2.5928 | 2.5928 | 0.243342 | 0.243342
Sisesein | 2.korrus | 6dB | 5.09326 | 5.50486 | 1819.02 | 2800 | 0.169404 | 5.12966 | 5.12966 | 0.474331 | 0.474331
Sisesein | 2.korrus | 6dB | 3.36 | 3.7716 | 1200 | 2800 | 0.112454 | 3.3964 | 3.3964 | 0.314871 | 0.314871
Sisesein | 2.korrus | 6dB | 3.83138 | 4.66732 | 1379.88 | 2800 | 0.131121 | 3.93759 | 3.93759 | 0.367138 | 0.367138
Sisesein | 2.korrus | 6dB | 1.6273 | 1.6273 | 451 | 3274.26 | 0.043839 | 1.58474 | 1.58474 | 0.14354 | 0.14354
Sisesein | 2.korrus | 6dB | 1.07724 | 1.88917 | 296.004 | 3274.26 | 0.0248854 | 0.947904 | 0.947904 | 0.0814805 | 0.0814805
2 x Sisesein | 2.korrus | 6dB | 0.8092 | 0.8092 | 289 | 2800 | 0.026588 | 0.8092 | 0.8092 | 0.0744464 | 0.0744464

# IfcWall: SS-2.5 236 (6)
Classification: 1.24 IfcWallType (sein) (IPI ÜBN)
AC_Pset_RenovationAndPhasing - Renovation Status: New
AR_Sein - 001_Nimetus: Sisesein; 325_Helipidavus: 43dB; 335_Välispiire: no; 340_Soojusläbivus: 0; 500_Kandev: no; 505_Paksus: 236 mm; 205_Tähis: SS-2.5
BaseQuantities - Width: 236 mm
Name | In | 605_Neto-pindala (m2) | 600_Bruto-pindala (m2) | 376_Viimistlus-väljast | Length (mm) | Height (mm) | GrossFootprintArea (m2) = NetFootprintArea (m2) | GrossSideArea (m2) | NetSideArea (m2) | GrossVolume (m3) | NetVolume (m3)
Sisesein | 2.korrus | 72.8235 | 99.4715 | SA_seinad_F499 | 30075.7 | 3260 | 4.43441 | 92.885 | 71.6584 | 22.1065 | 17.0969
Sisesein | 2.korrus | 34.0811 | 45.8513 | SA_seinad_F499 | 7450.21 | 5920.51 | 1.74301 | 33.847 | 33.847 | 8.00731 | 8.00731
Välissein | Pööningukorrus | 61.797 | 61.797 | SA_seinad_F499 | 15242.6 | 4054.23 | 3.59125 | 60.3657 | 60.3657 | 14.4721 | 14.4721
Välissein | Pööningukorrus | 88.6125 | 104.414 | SA_seinad_F499 | 21380.6 | 4263.65 | 5.04583 | 88.5557 | 88.0516 | 21.0431 | 20.9241
Välissein | Pööningukorrus | 9.78749 | 10.7295 | SA_seinad_F499 | 3584.43 | 2730.56 | 0.845926 | 9.78749 | 9.78749 | 2.30985 | 2.30985
Välissein | Pööningukorrus | 11.4215 | 14.7707 | FAS_katus_plekk | 3836.21 | 3749.88 | 0.849063 | 12.2227 | 10.5827 | 3.04693 | 2.65989

# IfcWall: SS-2.5* 96 (4)
In: 2.korrus
Classification: 1.24 IfcWallType (sein) (IPI ÜBN)
AR_Sein - 001_Nimetus: Sisesein; 325_Helipidavus: 43dB; 335_Välispiire: no; 340_Soojusläbivus: 0; 500_Kandev: no; 505_Paksus: 96 mm; 376_Viimistlus-väljast: SA_seinad_F499; 205_Tähis: SS-2.5*
BaseQuantities - Width: 96 mm
Name | 605_Neto-pindala (m2) = GrossSideArea (m2) = NetSideArea (m2) | 600_Bruto-pindala (m2) | Renovation Status | Length (mm) | Height (mm) | GrossFootprintArea (m2) = NetFootprintArea (m2) | GrossVolume (m3) = NetVolume (m3)
Sisesein | 42.22 | 51.0915 | New | 11757.3 | 4345.5 | 1.1287 | 4.05312
Sisesein | 4.23186 | 4.23186 | Existing | 7202.84 | 587.527 | 0.691473 | 0.406259
Sisesein | 2.41917 | 2.41917 | Existing | 4117.55 | 587.527 | 0.395285 | 0.23224
Sisesein | 1.93584 | 1.93584 | Existing | 3294.89 | 587.527 | 0.31631 | 0.18584

# IfcWall: SS-2.6 190, Sisesein
In: 1.korrus
Classification: 1.24 IfcWallType (sein) (IPI ÜBN)
AR_Sein - 001_Nimetus: Sisesein; 325_Helipidavus: 43dB; 335_Välispiire: no; 340_Soojusläbivus: 0; 605_Neto-pindala: 49.8674 m2; 600_Bruto-pindala: 53.8342 m2; 500_Kandev: no; 505_Paksus: 190 mm; 376_Viimistlus-väljast: SA_seinad_F499; 205_Tähis: SS-2.6
AC_Pset_RenovationAndPhasing - Renovation Status: New
BaseQuantities - Length: 12817.7 mm; Height: 4200 mm; Width: 190 mm; GrossFootprintArea: 2.43536 m2; NetFootprintArea: 2.43536 m2; GrossSideArea: 53.8342 m2; NetSideArea: 49.8674 m2; GrossVolume: 10.2285 m3; NetVolume: 9.47481 m3

# IfcWall: SS-3 140 (8)
Classification: 1.24 IfcWallType (sein) (IPI ÜBN); Material: Puit - CLT
AC_Pset_RenovationAndPhasing - Renovation Status: New
BaseQuantities - Width: 140 mm
AR_Sein - 001_Nimetus: Sisesein; 325_Helipidavus: 43dB; 335_Välispiire: no; 340_Soojusläbivus: 0; 500_Kandev: no; 505_Paksus: 140 mm; 205_Tähis: SS-3
Name | In | Length (mm) | Height (mm) | GrossFootprintArea (m2) = NetFootprintArea (m2) | GrossSideArea (m2) | NetSideArea (m2) | GrossVolume (m3) | NetVolume (m3) | 605_Neto-pindala (m2) | 600_Bruto-pindala (m2) | 376_Viimistlus-väljast
Sisesein | 1.korrus | 1754.1 | 7510 | 0.245575 | 13.0456 | 13.0456 | 1.81492 | 1.81492 | 12.9634 | 14.9921 | SA_seinad_F499
Sisesein | 1.korrus | 3130.63 | 7390 | 0.43829 | 22.9348 | 22.9348 | 3.21083 | 3.21083 | 22.9348 | 24.5755 | SA_seinad_F499
Sisesein | 1.korrus | 1875.52 | 7510 | 0.0693725 | 13.8681 | 7.77306 | 1.94153 | 1.08823 | 7.77306 | 15.1267 | SA_seinad_F499
Sisesein | 1.korrus | 1588.47 | 7390 | 0.222385 | 11.7388 | 9.20879 | 1.64343 | 1.28923 | 9.20824 | 14.7403 | SA_seinad_F499
Sisesein | 2.korrus | 12817.1 | 1750 | 1.7944 | 22.43 | 22.43 | 3.14019 | 3.14019 | 22.43 | 22.43 | SA_seinad_F499
Välissein | Pööningukorrus | 2015.52 | 1845.77 | 0.282182 | 3.31676 | 3.31676 | 0.464352 | 0.464352 | 3.31676 | 3.72019 | SA_seinad_F499
Välissein | Pööningukorrus | 981.909 | 2300.62 | 0.137467 | 2.25836 | 2.25836 | 0.31617 | 0.31617 | 2.25831 | 2.259 | SA_puit_sise_Teknos T3072
Välissein | Pööningukorrus | 1315.01 | 509.287 | 0.212802 | 0.774124 | 0.774124 | 0.108377 | 0.108377 | 0.774124 | 0.846507 | SA_puit_sise_Teknos T3072

# IfcWall: TUUL_vundament 440 x 1150 (5)
In: 1.korrus
Classification: 1.24 IfcWallType (sein) (IPI ÜBN)
BaseQuantities - Height: 1150 mm; Width: 440 mm
AR_Sein - 001_Nimetus: Sokkel; 325_Helipidavus: 43dB; 335_Välispiire: no; 340_Soojusläbivus: 0; 500_Kandev: no; 505_Paksus: 440 mm; 376_Viimistlus-väljast: FAS_sokkel; 205_Tähis: Sokkel
AC_Pset_RenovationAndPhasing - Renovation Status: New
Name | Length (mm) | GrossFootprintArea (m2) = NetFootprintArea (m2) | GrossSideArea (m2) | NetSideArea (m2) | GrossVolume (m3) | NetVolume (m3) | 605_Neto-pindala (m2) | 600_Bruto-pindala (m2)
Sokkel | 2070.95 | 0.946519 | 2.57847 | 2.57847 | 0.996365 | 0.996365 | 2.79585 | 2.79585
Sokkel | 2898.53 | 1.27215 | 3.38014 | 3.38014 | 1.28586 | 1.28586 | 3.57396 | 4.00231
Sokkel | 16879.2 | 7.39156 | 19.9959 | 19.9959 | 7.73532 | 7.73532 | 20.7886 | 20.8945
Sokkel | 45146.7 | 19.9352 | 53.7927 | 51.2719 | 20.859 | 20.2133 | 52.9161 | 55.7076
Sokkel | 4613.82 | 1.99478 | 5.44788 | 5.44788 | 2.09201 | 2.09201 | 5.79787 | 5.90372

# IfcWall: TUUL_vundament_madal 380 x 850 (3)
In: 1.korrus
Classification: 1.24 IfcWallType (sein) (IPI ÜBN)
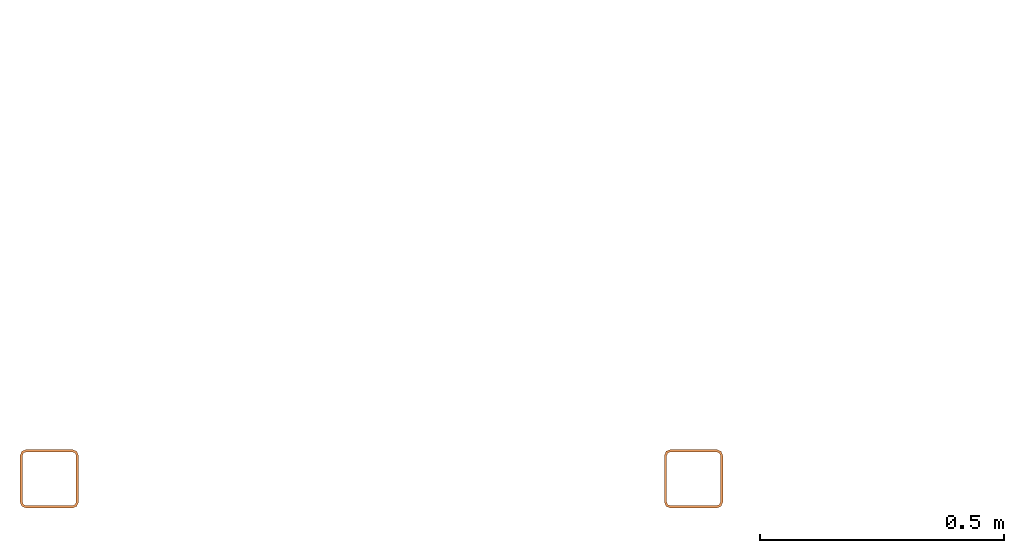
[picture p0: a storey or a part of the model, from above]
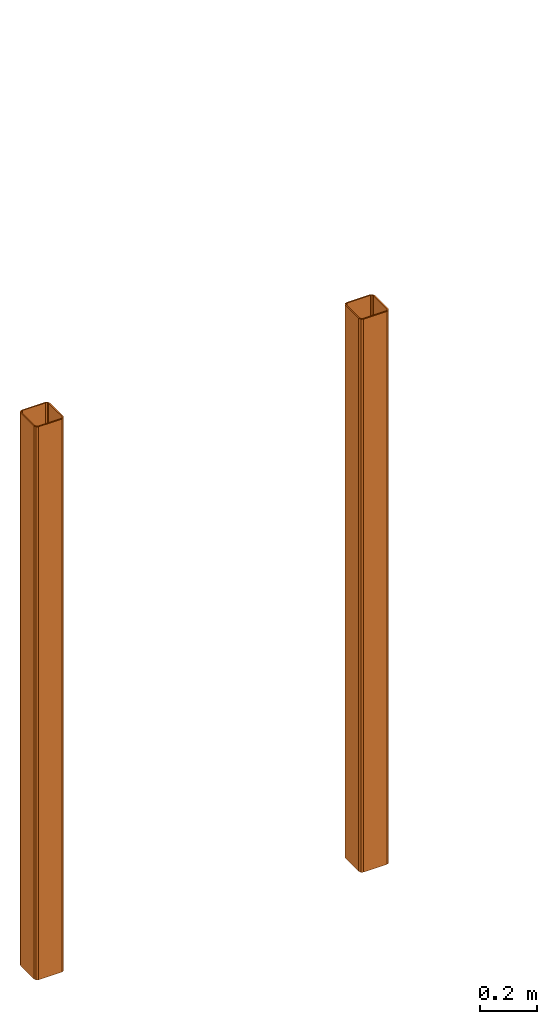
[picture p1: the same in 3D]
Properties of the parts of a building model (IFC2X3), part 7 of 7

# IfcWall: TUUL_vundament_madal 380 x 850 (3)
AR_Sein - 001_Nimetus: Sokkel; 325_Helipidavus: 43dB; 335_Välispiire: no; 340_Soojusläbivus: 0; 500_Kandev: no; 505_Paksus: 380 mm; 205_Tähis: Sokkel
AC_Pset_RenovationAndPhasing - Renovation Status: New
BaseQuantities - Height: 850 mm; Width: 380 mm
Name | 605_Neto-pindala (m2) | 600_Bruto-pindala (m2) | 376_Viimistlus-väljast | Length (mm) | GrossFootprintArea (m2) = NetFootprintArea (m2) | GrossSideArea (m2) = NetSideArea (m2) | GrossVolume (m3) = NetVolume (m3)
Sokkel | 3.00448 | 3.35684 | FAS_sokkel | 3379.08 | 1.2644 | 2.78479 | 1.03478
Sokkel | 13.7943 | 14.0577 |  | 14757 | 5.63237 | 12.5023 | 4.73641
Sokkel | 3.13624 | 3.46541 | FAS_sokkel | 3464.65 | 1.34567 | 2.95021 | 1.0972

# IfcWall: VS-1.1 76 (2)
In: 2.korrus
Classification: 1.24 IfcWallType (sein) (IPI ÜBN)
AR_Sein - 001_Nimetus: Sisesein; 325_Helipidavus: 43dB; 335_Välispiire: no; 340_Soojusläbivus: 0; 500_Kandev: no; 505_Paksus: 76 mm; 376_Viimistlus-väljast: SA_seinad_F499; 205_Tähis: VS-1.1
AC_Pset_RenovationAndPhasing - Renovation Status: New
BaseQuantities - Height: 3000 mm; Width: 76 mm
Name | 605_Neto-pindala (m2) | 600_Bruto-pindala (m2) | Length (mm) | GrossFootprintArea (m2) = NetFootprintArea (m2) | GrossSideArea (m2) = NetSideArea (m2) | GrossVolume (m3) = NetVolume (m3)
Sisesein | 7.67063 | 7.67063 | 2371.88 | 0.189539 | 7.26453 | 0.562865
Sisesein | 5.871 | 6.021 | 1822 | 0.144572 | 5.6115 | 0.433716

# IfcWall: VS-3 163 (3)
In: Pööningukorrus
Classification: 1.24 IfcWallType (sein) (IPI ÜBN)
AC_Pset_RenovationAndPhasing - Renovation Status: New
AR_Sein - 001_Nimetus: Sisesein; 325_Helipidavus: 43dB; 335_Välispiire: no; 340_Soojusläbivus: 0; 500_Kandev: no; 505_Paksus: 163 mm; 376_Viimistlus-väljast: SA_seinad_F499; 205_Tähis: VS-3
BaseQuantities - Width: 163 mm
Name | 605_Neto-pindala (m2) | 600_Bruto-pindala (m2) | Length (mm) | Height (mm) | GrossFootprintArea (m2) = NetFootprintArea (m2) | GrossSideArea (m2) | NetSideArea (m2) | GrossVolume (m3) | NetVolume (m3)
Sisesein | 2.16201 | 2.16201 | 981.5 | 2033.87 | 0.171319 | 2.00947 | 2.00947 | 0.348441 | 0.348441
Sisesein | 4.54443 | 5.32907 | 1963 | 2527.07 | 0.319969 | 4.34168 | 4.34168 | 0.73547 | 0.73547
Sisesein | 1.80311 | 2.68627 | 981.5 | 2527.07 | 0.14865 | 2.29079 | 1.78669 | 0.375648 | 0.29348

# IfcWall: VS1 437 (14)
Classification: 1.24 IfcWallType (sein) (IPI ÜBN)
AR_Sein - 325_Helipidavus: 43dB; 340_Soojusläbivus: 0; 500_Kandev: no; 505_Paksus: 437 mm; 376_Viimistlus-väljast: FAS_välissein_1_hall puitlaudis; 205_Tähis: VS1
AC_Pset_RenovationAndPhasing - Renovation Status: New
BaseQuantities - Width: 437 mm
Name | In | 001_Nimetus | 335_Välispiire | 605_Neto-pindala (m2) | 600_Bruto-pindala (m2) | Length (mm) | Height (mm) | GrossFootprintArea (m2) = NetFootprintArea (m2) | GrossSideArea (m2) | NetSideArea (m2) | GrossVolume (m3) | NetVolume (m3)
Välissein | 1.korrus | Sisesein | yes | 6.88156 | 6.88156 | 2127.24 | 2933.64 | 0.961976 | 6.44591 | 6.44591 | 2.82209 | 2.82209
Sisesein | 1.korrus | Sisesein | yes | 140.292 | 186.881 | 45143.7 | 4100 | 16.4503 | 185.335 | 138.828 | 80.884 | 60.5603
Sisesein | 1.korrus | Sisesein | yes | 53.746 | 70.0945 | 16877.7 | 4100 | 2.56629 | 67.0987 | 55.5241 | 28.9344 | 23.8763
Sisesein | 1.korrus | Sisesein | yes | 19.7244 | 19.8064 | 4612.32 | 4100 | 1.98321 | 18.8695 | 18.8695 | 8.13117 | 8.13117
Välissein | 1.korrus | Sisesein | yes | 9.08755 | 9.9326 | 3167.26 | 2700 | 1.35172 | 8.5246 | 8.5246 | 3.64964 | 3.64964
Sisesein | 2.korrus | Sisesein | yes | 69.3136 | 83.1532 | 14888.7 | 5477.57 | 6.51337 | 81.6583 | 67.9207 | 35.5446 | 29.5413
Sisesein | 2.korrus | Välissein | yes | 50.5941 | 63.2561 | 16877.7 | 3700 | 6.47276 | 62.6978 | 50.038 | 27.4091 | 21.8768
Sisesein | 2.korrus | Sisesein | yes | 135.347 | 181.722 | 45143.7 | 3986.81 | 19.7926 | 180.24 | 133.942 | 78.6691 | 58.4367
Sisesein | 2.korrus | Sisesein | yes | 17.8 | 17.874 | 4612.32 | 3700 | 1.98321 | 17.0286 | 17.0286 | 7.33788 | 7.33788
Välissein | 2.korrus | Sisesein | yes | 11.6213 | 11.6213 | 2169.58 | 4866.36 | 0.980479 | 10.8986 | 10.8986 | 4.77136 | 4.77136
Sisesein | 2.korrus | Sisesein | yes | 14.5554 | 24.9119 | 12775.3 | 1950 | 1.8099 | 19.7336 | 19.7336 | 7.80817 | 7.80817
Välissein | Pööningukorrus | Sisesein | no | 28.9253 | 85.7503 | 19460.2 | 2877.03 | 8.56723 | 30.3032 | 28.7807 | 13.2213 | 12.556
Sisesein | Pööningukorrus | Sisesein | yes | 25.0673 | 64.4227 | 16477.1 | 2877.01 | 7.35907 | 28.3211 | 24.7905 | 12.442 | 10.8992
Sisesein | Pööningukorrus | Sisesein | no | 16.9358 | 17.1112 | 15105.9 | 1109.59 | 6.56892 | 16.7234 | 16.7234 | 7.27869 | 7.27869

# IfcWall: VS2 200 (13)
Classification: 1.24 IfcWallType (sein) (IPI ÜBN); Material: Soojustus - Mineraalvill pehme
AR_Sein - 001_Nimetus: Sisesein; 325_Helipidavus: 43dB; 335_Välispiire: no; 340_Soojusläbivus: 0; 500_Kandev: no; 505_Paksus: 200 mm; 205_Tähis: VS2
BaseQuantities - Width: 200 mm
Name | In | 605_Neto-pindala (m2) | 600_Bruto-pindala (m2) | 376_Viimistlus-väljast | Renovation Status | Length (mm) | Height (mm) | GrossFootprintArea (m2) = NetFootprintArea (m2) | GrossSideArea (m2) | NetSideArea (m2) | GrossVolume (m3) | NetVolume (m3)
Välissein | Pööningukorrus | 33.6004 | 33.9725 | SA_seinad_F499 | New | 18947.9 | 1792.95 | 3.78958 | 33.9725 | 33.6004 | 6.79451 | 6.72009
Välissein | Pööningukorrus | 11.1232 | 13.5175 | SA_seinad_F499 | New | 3081.22 | 4219.15 | 0.619066 | 12.0499 | 10.3408 | 2.49883 | 2.15701
Välissein | Pööningukorrus | 8.84669 | 10.027 | SA_seinad_F499 | New | 2259.78 | 4219.15 | 0.431955 | 8.84669 | 8.84669 | 1.76934 | 1.76934
Sisesein | Pööningukorrus | 4.69273 | 4.69273 | SA_seinad_F499 | New | 1690.14 | 2621.43 | 0.358028 | 4.5411 | 4.5411 | 0.937768 | 0.937768
Sisesein | Pööningukorrus | 5.66086 | 6.63372 | SA_seinad_F499 | New | 2000 | 2986.31 | 0.4 | 5.66086 | 5.66086 | 1.13217 | 1.13217
Sisesein | Pööningukorrus | 3.52124 | 4.53075 | SA_seinad_F499 | New | 1692.89 | 2527.07 | 0.318578 | 4.02534 | 3.52124 | 0.805067 | 0.704247
Välissein | Pööningukorrus | 2.80916 | 3.13199 | FAS_välissein_1_hall puitlaudis | New | 1200 | 2197.81 | 0.28 | 2.80916 | 2.80916 | 0.561833 | 0.561833
Välissein | Pööningukorrus | 2.33268 | 2.72146 | FAS_välissein_1_hall puitlaudis | New | 1200 | 1943.9 | 0.24 | 2.33268 | 2.33268 | 0.466536 | 0.466536
Välissein | Pööningukorrus | 2.58659 | 3.14717 | FAS_välissein_1_hall puitlaudis | New | 1200 | 2197.81 | 0.24 | 2.55926 | 2.55926 | 0.511853 | 0.511853
Välissein | Pööningukorrus | 1.81528 | 2.88682 | FAS_välissein_1_hall puitlaudis | New | 1200 | 1869.93 | 0.2 | 1.84261 | 1.84261 | 0.368521 | 0.368521
Välissein | Pööningukorrus | 3.37727 | 3.93065 | SA_seinad_F499 | New | 2601 | 1643.92 | 0.5202 | 3.37727 | 3.37727 | 0.675453 | 0.675453
Välissein | Pööningukorrus | 1.2256 | 1.43006 | SA_seinad_F499 | Existing | 869.904 | 1408.89 | 0.173981 | 1.2256 | 1.2256 | 0.245119 | 0.245119
Välissein | Katuseplaan | 7.79077 | 27.4635 | FAS_välissein_1_hall puitlaudis | New | 5802.13 | 1674.86 | 1.16043 | 7.64683 | 7.64683 | 1.52937 | 1.52937

# IfcWall: VS2.1 345 (8)
In: Pööningukorrus
Classification: 1.24 IfcWallType (sein) (IPI ÜBN)
AR_Sein - 001_Nimetus: Sisesein; 325_Helipidavus: 43dB; 335_Välispiire: no; 340_Soojusläbivus: 0; 500_Kandev: no; 505_Paksus: 345 mm; 205_Tähis: VS2.1
BaseQuantities - Width: 345 mm
AC_Pset_RenovationAndPhasing - Renovation Status: New
Name | 605_Neto-pindala (m2) | 600_Bruto-pindala (m2) | 376_Viimistlus-väljast | Length (mm) | Height (mm) | GrossFootprintArea (m2) = NetFootprintArea (m2) | GrossSideArea (m2) | NetSideArea (m2) | GrossVolume (m3) | NetVolume (m3)
Välissein | 15.1677 | 16.6414 | FAS_katus_plekk | 4587.96 | 3500 | 1.69998 | 16.9953 | 16.0152 | 5.85973 | 5.5216
Välissein | 28.1868 | 32.5159 | SA_seinad_F499 | 7360.2 | 4330.86 | 2.62069 | 31.2811 | 28.206 | 10.8319 | 9.77099
Välissein | 23.1107 | 23.7364 | FAS_katus_plekk | 14714.8 | 1613.09 | 5.01512 | 23.4159 | 23.4159 | 8.06556 | 8.06556
Välissein | 11.6631 | 12.4583 | SA_seinad_F499 | 2948.31 | 3910 | 1.08064 | 11.3289 | 11.3289 | 3.90752 | 3.90752
Välissein | 26.4787 | 28.2404 | FAS_katus_plekk | 11688.7 | 2296.3 | 4.09213 | 26.6012 | 26.6012 | 9.17257 | 9.17257
Välissein | 0.597956 | 0.597956 | SA_seinad_F499 | 485.021 | 1232.85 | 0.167332 | 0.597956 | 0.597956 | 0.206295 | 0.206295
Välissein | 19.3961 | 19.7389 | SA_seinad_F499 | 8301.09 | 2335.68 | 2.94828 | 19.552 | 19.552 | 6.79506 | 6.79506
Välissein | 1.86849 | 1.96805 | SA_seinad_F499 | 1596.35 | 1232.85 | 0.55074 | 1.91827 | 1.91827 | 0.658568 | 0.658568

# IfcWall: VS_klaasfassaadi peal 246, Välissein
In: 2.korrus
Classification: 1.24 IfcWallType (sein) (IPI ÜBN)
AR_Sein - 001_Nimetus: Välissein; 325_Helipidavus: -; 335_Välispiire: yes; 340_Soojusläbivus: 0; 605_Neto-pindala: 11.3087 m2; 600_Bruto-pindala: 11.3087 m2; 500_Kandev: no; 505_Paksus: 246 mm; 376_Viimistlus-väljast: RAL9017 must; 205_Tähis: VS_klaasfassaadi peal
AC_Pset_RenovationAndPhasing - Renovation Status: New
BaseQuantities - Length: 14633.8 mm; Height: 762.36 mm; Width: 246 mm; GrossFootprintArea: 3.61451 m2; NetFootprintArea: 3.61451 m2; GrossSideArea: 11.0254 m2; NetSideArea: 11.0254 m2; GrossVolume: 2.74379 m3; NetVolume: 2.74379 m3

# IfcWall: VSy 249 (4)
In: Pööningukorrus
Classification: 1.24 IfcWallType (sein) (IPI ÜBN)
BaseQuantities - Width: 249 mm
AC_Pset_RenovationAndPhasing - Renovation Status: New
AR_Sein - 001_Nimetus: Sisesein; 325_Helipidavus: 43dB; 335_Välispiire: no; 340_Soojusläbivus: 0; 500_Kandev: no; 505_Paksus: 249 mm; 376_Viimistlus-väljast: FAS_katus_plekk; 205_Tähis: VSy
Name | Length (mm) | Height (mm) | GrossFootprintArea (m2) = NetFootprintArea (m2) | GrossSideArea (m2) | NetSideArea (m2) | GrossVolume (m3) | NetVolume (m3) | 605_Neto-pindala (m2) | 600_Bruto-pindala (m2)
Välissein | 3672.55 | 1080.35 | 0 | 1.56875 | 1.56875 | 0.390606 | 0.390606 | 1.54827 | 8.85218
Välissein | 15072.3 | 2267.17 | 3.78337 | 34.4998 | 34.4998 | 8.57756 | 8.57756 | 34.2885 | 34.2885
Välissein | 4336.63 | 2267.17 | 1.13661 | 10.0792 | 10.0792 | 2.50972 | 2.50972 | 9.80935 | 9.80935
Välissein | 3459.36 | 2267.32 | 0.88301 | 7.29061 | 5.65061 | 1.74273 | 1.33437 | 5.61729 | 8.21567

# IfcWall: VSz 149 (5)
In: Katuseplaan
Classification: 1.24 IfcWallType (sein) (IPI ÜBN)
BaseQuantities - Width: 149 mm
AC_Pset_RenovationAndPhasing - Renovation Status: New
AR_Sein - 001_Nimetus: Sisesein; 325_Helipidavus: 43dB; 335_Välispiire: no; 340_Soojusläbivus: 0; 500_Kandev: no; 505_Paksus: 149 mm; 376_Viimistlus-väljast: FAS_katus_plekk; 205_Tähis: VSz
Name | Length (mm) | Height (mm) | GrossFootprintArea (m2) = NetFootprintArea (m2) | GrossSideArea (m2) = NetSideArea (m2) | GrossVolume (m3) = NetVolume (m3) | 605_Neto-pindala (m2) | 600_Bruto-pindala (m2)
Välissein | 7197.21 | 2216.31 | 0.900701 | 6.68228 | 0.989826 | 6.57531 | 32.3029
Välissein | 19356.4 | 2201.24 | 2.87544 | 42.3817 | 6.301 | 42.4125 | 42.674
Välissein | 6995 | 2144.21 | 0.947655 | 6.72843 | 1.0024 | 6.54522 | 10.7738
Välissein | 3487.52 | 2177.4 | 0 | 5.50311 | 0.820015 | 5.48887 | 17.3877
Välissein | 3597.76 | 1037.92 | 0 | 1.53782 | 0.229133 | 1.52534 | 18.4826

# IfcWindow: 1115 x 1165 x 40
In: 1.korrus
Type - OperationType: SINGLE_PANEL; ParameterTakesPrecedence: no; Sizeable: no
OverallHeight: 1655 mm; OverallWidth: 1075 mm; Classification: 1.25 IfcWindowStyle (aken) (IPI ÜBN)
AR_Aken - 001_Nimetus: SE aken; 900_Tootja: ootel; 905_Mudel: ootel; 910_Tooteinfo: -; 915_Kasutus-ja-hooldusjuhend: -; 395_Veeplekk: ootel; 396_Aknalaud: ootel
Pset_ManufacturerOccurrence - SerialNumber: Off
AC_Pset_RenovationAndPhasing - Renovation Status: Undefined
BaseQuantities - NetVolume: 0.071165 m3

# IfcWindow: 1115 x 1490 x 20
In: 1.korrus
Type - OperationType: SINGLE_PANEL; ParameterTakesPrecedence: no; Sizeable: no
OverallHeight: 1450 mm; OverallWidth: 1075 mm; Classification: 1.25 IfcWindowStyle (aken) (IPI ÜBN)
AR_Aken - 001_Nimetus: Paneel; 900_Tootja: ootel; 905_Mudel: ootel; 910_Tooteinfo: -; 915_Kasutus-ja-hooldusjuhend: -; 395_Veeplekk: ootel; 396_Aknalaud: ootel
AC_Pset_RenovationAndPhasing - Renovation Status: Undefined
Pset_ManufacturerOccurrence - SerialNumber: Off
BaseQuantities - NetVolume: 0.031175 m3

# IfcWindow: 964 x 1695 x 40
In: 1.korrus
Type - OperationType: SINGLE_PANEL; ParameterTakesPrecedence: no; Sizeable: no
OverallHeight: 1655 mm; OverallWidth: 924.419 mm; Classification: 1.25 IfcWindowStyle (aken) (IPI ÜBN)
AR_Aken - 001_Nimetus: SE aken; 900_Tootja: ootel; 905_Mudel: ootel; 910_Tooteinfo: -; 915_Kasutus-ja-hooldusjuhend: -; 395_Veeplekk: ootel; 396_Aknalaud: ootel
Pset_ManufacturerOccurrence - SerialNumber: Off
AC_Pset_RenovationAndPhasing - Renovation Status: Undefined
BaseQuantities - NetVolume: 0.0611965 m3

# IfcWindow: Double Window 27 (30)
Type - OperationType: DOUBLE_PANEL_VERTICAL; ParameterTakesPrecedence: no; Sizeable: no
Classification: 1.25 IfcWindowStyle (aken) (IPI ÜBN)
AR_Aken - 320_Klaas: Glass - Clear Fast; 910_Tooteinfo: -; 915_Kasutus-ja-hooldusjuhend: -; 395_Veeplekk: ootel; 396_Aknalaud: ootel
Name | In | OverallHeight (mm) = 307_Ava-kõrgus (mm) = Height (mm) | OverallWidth (mm) = 306_Ava-laius (mm) = Width (mm) | 001_Nimetus | 375_Viimistlus-seest | 376_Viimistlus-väljast | 900_Tootja | 905_Mudel | GrossArea (m2) = Area (m2) | Perimeter (mm) | Volume (m3) = NetVolume (m3) | Depth (mm) | Renovation Status
2 x VA-XX | 1.korrus | 1150 | 2480 | Olemasolev välisaken | RAL 9010 | RAL 9010 | ootel | ootel | 2.852 | 7260 | 0.031218 | 100 | Existing
VA-XX | 1.korrus | 1150 | 2450 | Olemasolev välisaken | RAL 9010 | RAL 9010 | ootel | ootel | 2.8175 | 7200 | 0.0310117 | 100 | Existing
8 x VA-XX | 1.korrus | 1100.26 | 2985 | Olemasolev välisaken | RAL 9010 | RAL 9010 | ootel | ootel | 3.28427 | 8170.51 | 0.0274282 | 360 | Existing
2 x VA-XX | 1.korrus | 1120 | 2420 | Olemasolev välisaken | RAL 9010 | RAL 9010 | ootel | ootel | 2.7104 | 7080 | 0.03791 | 290 | Existing
VA-XX | 1.korrus | 1100 | 2420 | Olemasolev välisaken | RAL 9010 | RAL 9010 | ootel | ootel | 2.662 | 7040 | 0.0489284 | 290 | Existing
VA-XX | 1.korrus | 1100 | 2420 | Olemasolev välisaken | RAL 9010 | RAL 9010 | ootel | ootel | 2.662 | 7040 | 0.0617884 | 290 | Existing
VA-XX | 1.korrus | 1120 | 2920 | Olemasolev välisaken | RAL 9010 | RAL 9010 | ootel | ootel | 3.2704 | 8080 | 0.04216 | 560 | Existing
VA-XX | 1.korrus | 1120 | 2920 | Olemasolev välisaken | RAL 9010 | RAL 9010 | ootel | ootel | 3.2704 | 8080 | 0.0569842 | 560 | Existing
VA-XX | 1.korrus | 1120 | 2920 | Olemasolev välisaken | RAL 9010 | RAL 9010 | ootel | ootel | 3.2704 | 8080 | 0.04216 | 520 | Existing
VA-XX | 1.korrus | 1120 | 2920 | Olemasolev välisaken | RAL 9010 | RAL 9010 | ootel | ootel | 3.2704 | 8080 | 0.0569842 | 520 | Existing
VA-XX | 1.korrus | 1150 | 2350 | Olemasolev välisaken | RAL 9010 | RAL 9010 | ootel | ootel | 2.7025 | 7000 | 0.0303242 | 100 | Existing
 | 1.korrus | 580 | 1950 | Olemasolev välisaken | RAL 7004 | RAL 7004 | ootel | ootel | 1.131 | 5060 | 0.0246392 | 380 | Existing
SA-XX | 1.korrus | 1300 | 1615.92 | Siseaken | RAL 9010 | RAL 9010 | ootel | ootel | 2.1007 | 5831.84 | 0.0382837 | 100 | Existing
4 x A-2 | 2.korrus | 2160 | 1590 | Välisaken | kollane lasuur Teknos T8024 | RAL 1005 ookerkollane | Viking Window | DK22 | 3.4344 | 7500 | 0.136223 | 437 | New
4 x VA-XX | 2.korrus | 1180 | 2900 | Olemasolev välisaken | RAL 9010 | RAL 9010 | ootel | ootel | 3.422 | 8160 | 0.0253 | 300 | Existing

# IfcWindow: Horizontal Multi-Sash Window 27, VA-XX
In: 1.korrus
Type - OperationType: USERDEFINED; ParameterTakesPrecedence: no; Sizeable: no
OverallHeight: 1150 mm; OverallWidth: 4960 mm; Classification: 1.25 IfcWindowStyle (aken) (IPI ÜBN)
AR_Aken - 001_Nimetus: Olemasolev välisaken; 320_Klaas: Glass - Clear Fast; 375_Viimistlus-seest: RAL 9010; 376_Viimistlus-väljast: RAL 9010; 900_Tootja: ootel; 905_Mudel: ootel; 910_Tooteinfo: -; 915_Kasutus-ja-hooldusjuhend: -; 306_Ava-laius: 4960 mm; 307_Ava-kõrgus: 1150 mm; 395_Veeplekk: ootel; 396_Aknalaud: ootel
BaseQuantities - GrossArea: 5.704 m2; Height: 1150 mm; Width: 4960 mm; Perimeter: 12220 mm; Area: 5.704 m2; Volume: 0.0732203 m3; Depth: 100 mm; NetVolume: 0.0732203 m3
AC_Pset_RenovationAndPhasing - Renovation Status: Existing

# IfcWindow: Orivent 01 (5)
In: Pööningukorrus
Type - ParameterTakesPrecedence: no; Sizeable: no
Classification: 1.25 IfcWindowStyle (aken) (IPI ÜBN)
AC_Pset_RenovationAndPhasing - Renovation Status: New
AR_Aken - 001_Nimetus: Valguskupliga suitsuluuk; 900_Tootja: ootel; 905_Mudel: ootel; 910_Tooteinfo: -; 915_Kasutus-ja-hooldusjuhend: -; 395_Veeplekk: ootel; 396_Aknalaud: ootel

# IfcWindow: Orivent 21 (4)
In: Pööningukorrus
Type - ParameterTakesPrecedence: no; Sizeable: no
Classification: 1.25 IfcWindowStyle (aken) (IPI ÜBN)
AR_Aken - 001_Nimetus: Suitsuluuk; 900_Tootja: ootel; 905_Mudel: ootel; 910_Tooteinfo: -; 915_Kasutus-ja-hooldusjuhend: -; 395_Veeplekk: ootel; 396_Aknalaud: ootel
AC_Pset_RenovationAndPhasing - Renovation Status: New
Name
3 x SL2
SL3

# IfcWindow: Triple Window 27 (4)
Type - OperationType: TRIPLE_PANEL_VERTICAL; ParameterTakesPrecedence: no; Sizeable: no
Classification: 1.25 IfcWindowStyle (aken) (IPI ÜBN)
AR_Aken - 320_Klaas: Glass - Clear Fast; 900_Tootja: ootel; 905_Mudel: ootel; 910_Tooteinfo: -; 915_Kasutus-ja-hooldusjuhend: -
Name | In | OverallHeight (mm) = 307_Ava-kõrgus (mm) = Height (mm) | OverallWidth (mm) = 306_Ava-laius (mm) = Width (mm) | 001_Nimetus | 375_Viimistlus-seest = 376_Viimistlus-väljast | 395_Veeplekk | 396_Aknalaud | GrossArea (m2) = Area (m2) | Perimeter (mm) | Volume (m3) = NetVolume (m3) | Depth (mm) | Renovation Status
VA-XX | 1.korrus | 1150 | 3650 | Olemasolev välisaken | RAL 9010 | ootel | ootel | 4.1975 | 9600 | 0.0370625 | 100 | Existing
SA-XX | 1.korrus | 1340.05 | 2510 | Siseaken | RAL 9010 | ootel | ootel | 3.36352 | 7700.09 | 0.0652064 | 100 | Existing
2 x AL-4 | 2.korrus | 1230 | 2900 | Välisaken | valge | valge plekk | valge plastikaknalaud | 3.567 | 8260 | 0.067755 | 300 | New

# IfcWindow: Triple Window with Side Transoms 27, VA-XX
In: 1.korrus
Type - OperationType: USERDEFINED; ParameterTakesPrecedence: no; Sizeable: no
OverallHeight: 2380 mm; OverallWidth: 3600 mm; Classification: 1.25 IfcWindowStyle (aken) (IPI ÜBN)
AR_Aken - 001_Nimetus: Olemasolev välisaken; 320_Klaas: Glass - Clear Fast; 375_Viimistlus-seest: RAL 7043; 376_Viimistlus-väljast: RAL 3003; 900_Tootja: ootel; 905_Mudel: ootel; 910_Tooteinfo: -; 915_Kasutus-ja-hooldusjuhend: -; 306_Ava-laius: 3600 mm; 307_Ava-kõrgus: 2380 mm; 395_Veeplekk: ootel; 396_Aknalaud: ootel
AC_Pset_RenovationAndPhasing - Renovation Status: Existing
BaseQuantities - GrossArea: 8.568 m2; Height: 2380 mm; Width: 3600 mm; Perimeter: 11960 mm; Area: 8.568 m2; Volume: 0.230701 m3; Depth: 420 mm; NetVolume: 0.230701 m3

# IfcWindow: Vertical Multi-Sash Window 27 (3)
In: 1.korrus
Type - OperationType: DOUBLE_PANEL_HORIZONTAL; ParameterTakesPrecedence: no; Sizeable: no
OverallHeight: 2380 mm; OverallWidth: 1520 mm; Classification: 1.25 IfcWindowStyle (aken) (IPI ÜBN)
AR_Aken - 001_Nimetus: Olemasolev välisaken; 320_Klaas: Glass - Clear Fast; 375_Viimistlus-seest: RAL 7043; 376_Viimistlus-väljast: RAL 3003; 900_Tootja: ootel; 905_Mudel: ootel; 910_Tooteinfo: -; 915_Kasutus-ja-hooldusjuhend: -; 306_Ava-laius: 1520 mm; 307_Ava-kõrgus: 2380 mm; 395_Veeplekk: ootel; 396_Aknalaud: ootel
AC_Pset_RenovationAndPhasing - Renovation Status: Existing
BaseQuantities - GrossArea: 3.65018 m2; Height: 2401.43 mm; Width: 1520 mm; Perimeter: 7842.87 mm; Area: 3.65018 m2; Volume: 0.0739524 m3; Depth: 420 mm; NetVolume: 0.0739524 m3

# IfcWindow: Window 27 (32)
In: 1.korrus
Type - OperationType: DOUBLE_PANEL_HORIZONTAL; ParameterTakesPrecedence: no; Sizeable: no
Classification: 1.25 IfcWindowStyle (aken) (IPI ÜBN)
AR_Aken - 320_Klaas: Glass - Clear Fast; 900_Tootja: ootel; 905_Mudel: ootel; 910_Tooteinfo: -; 915_Kasutus-ja-hooldusjuhend: -; 395_Veeplekk: ootel; 396_Aknalaud: ootel
Pset_ManufacturerOccurrence - SerialNumber: Off
BaseQuantities - Depth: 420 mm
Name | OverallHeight (mm) = 307_Ava-kõrgus (mm) = Height (mm) | OverallWidth (mm) = 306_Ava-laius (mm) = Width (mm) | 001_Nimetus | 375_Viimistlus-seest = 376_Viimistlus-väljast | Renovation Status | GrossArea (m2) = Area (m2) | Perimeter (mm) | Volume (m3) = NetVolume (m3)
AL-3,EI120 | 2380 | 1500 | Tulekindel aken | valge | New | 3.57 | 7760 | 0.045656
VA-XX | 2380 | 1500 | Olemasolev välisaken | valge | Existing | 3.57 | 7760 | 0.045656
6 x VA-XX | 2260 | 1480 | Olemasolev välisaken | RAL 9010 | Existing | 3.3448 | 7480 | 0.037076
VA-XX | 2380 | 1530 | Olemasolev välisaken | RAL 9010 | Existing | 3.6414 | 7820 | 0.0552115
VA-XX | 2380 | 1530 | Olemasolev välisaken | RAL 9010 | Existing | 3.6414 | 7820 | 0.046124
5 x VA-XX | 2380 | 1530 | Olemasolev välisaken | RAL 9010 | Existing | 3.6414 | 7820 | 0.0322465
4 x VA-XX | 2380 | 1500 | Olemasolev välisaken | RAL 9010 | Existing | 3.57 | 7760 | 0.0483437
VA-XX | 2380 | 1500 | Olemasolev välisaken | RAL 9010 | Existing | 3.57 | 7760 | 0.0566219
11 x VA-XX | 2350 | 1500 | Olemasolev välisaken | RAL 9010 | Existing | 3.525 | 7700 | 0.0480122
VA-XX | 2350 | 1500 | Olemasolev välisaken | RAL 9010 | Existing | 3.525 | 7700 | 0.083325

# IfcWindow: Window 27 (104)
Type - OperationType: SINGLE_PANEL; ParameterTakesPrecedence: no; Sizeable: no
AR_Aken - 320_Klaas: Glass - Clear Fast; 910_Tooteinfo: -; 915_Kasutus-ja-hooldusjuhend: -
Name | In | OverallHeight (mm) = 307_Ava-kõrgus (mm) = Height (mm) | OverallWidth (mm) = 306_Ava-laius (mm) = Width (mm) | Classification | SerialNumber | 001_Nimetus | 375_Viimistlus-seest | 376_Viimistlus-väljast | 900_Tootja | 905_Mudel | 395_Veeplekk | 396_Aknalaud | GrossArea (m2) = Area (m2) | Perimeter (mm) | Volume (m3) = NetVolume (m3) | Depth (mm) | Renovation Status
9 x A-1g,SE | 1.korrus | 1910 | 1010 | 1.25 IfcWindowStyle (aken) (IPI ÜBN) | Off | Välisaken | kollane lasuur Teknos T8024 | RAL 1005 ookerkollane | Viking Window | DK22 | ootel | ootel | 1.9291 | 5840 | 0.053156 | 437 | New
4 x AL-1,EI30 | 1.korrus | 1910 | 1010 | 1.25 IfcWindowStyle (aken) (IPI ÜBN) | Off | Välisaken | RAL 1005 ookerkollane | RAL 1005 ookerkollane | Viking Window | DK22 | ootel | ootel | 1.9291 | 5840 | 0.053156 | 437 | New
7 x A-1g | 1.korrus | 1910 | 1010 | 1.25 IfcWindowStyle (aken) (IPI ÜBN) | Off | Välisaken | kollane lasuur Teknos T8024 | RAL 1005 ookerkollane | Viking Window | DK22 | ootel | ootel | 1.9291 | 5840 | 0.053156 | 437 | New
SA-XX | 1.korrus | 1140 | 1670 | 1.25 IfcWindowStyle (aken) (IPI ÜBN) | Off | Siseaken | RAL 9010 | RAL 9010 | ootel | ootel | ootel | ootel | 1.9038 | 5620 | 0.022596 | 360 | Existing
2 x VA-XX | 1.korrus | 1150 | 1200 | 1.25 IfcWindowStyle (aken) (IPI ÜBN) |  | Olemasolev välisaken | RAL 9010 | RAL 9010 | ootel | ootel | ootel | ootel | 1.38 | 4700 | 0.0241312 | 100 | Existing
2 x SA-XX | 1.korrus | 1155 | 1180 | 1.25 IfcWindowStyle (aken) (IPI ÜBN) | Off | Siseaken | RAL 9010 | RAL 9010 | ootel | ootel | ootel | ootel | 1.3629 | 4670 | 0.0213037 | 400 | Existing
2 x SA-XX | 1.korrus | 1250 | 900 | 1.25 IfcWindowStyle (aken) (IPI ÜBN) | Off | Siseaken | RAL 9010 | RAL 9010 | ootel | ootel | ootel | ootel | 1.125 | 4300 | 0.016686 | 270 | Existing
2 x SA-XX | 1.korrus | 1150 | 865.915 | 1.25 IfcWindowStyle (aken) (IPI ÜBN) | Off | Siseaken | RAL 9010 | RAL 9010 | ootel | ootel | ootel | ootel | 0.995803 | 4031.83 | 0.0181927 | 100 | Existing
2 x SA-XX | 1.korrus | 1150 | 1200 | 1.25 IfcWindowStyle (aken) (IPI ÜBN) | Off | Siseaken | RAL 9010 | RAL 9010 | ootel | ootel | ootel | ootel | 1.38 | 4700 | 0.02145 | 100 | Existing
2 x VA-XX | 1.korrus | 920 | 1050 | 1.25 IfcWindowStyle (aken) (IPI ÜBN) | Off | Olemasolev välisaken | RAL 9010 | RAL 9010 | ootel | ootel | ootel | ootel | 0.966 | 3940 | 0.0153832 | 110 | Existing
4 x VA-XX | 1.korrus | 1160 | 1300 | 1.25 IfcWindowStyle (aken) (IPI ÜBN) | Off | Olemasolev välisaken | RAL 9010 | RAL 8004 | ootel | ootel | ootel | ootel | 1.508 | 4920 | 0.022848 | 550 | Existing
11 x VA-XX | 1.korrus | 1160 | 1320 | 1.25 IfcWindowStyle (aken) (IPI ÜBN) | Off | Olemasolev välisaken | RAL 9010 | RAL 8004 | ootel | ootel | ootel | ootel | 1.5312 | 4960 | 0.02304 | 550 | Existing
7 x VA-XX | 1.korrus | 1150 | 1260 | 1.25 IfcWindowStyle (aken) (IPI ÜBN) | Off | Olemasolev välisaken | RAL 9010 | RAL 9010 | ootel | ootel | ootel | ootel | 1.449 | 4820 | 0.012116 | 500 | Existing
VA-XX | 1.korrus | 1150 | 1260 | 1.25 IfcWindowStyle (aken) (IPI ÜBN) | Off | Olemasolev välisaken | RAL 9010 | RAL 9010 | ootel | ootel | ootel | ootel | 1.449 | 4820 | 0.009907 | 500 | Existing
7 x VA-XX | 1.korrus | 1090 | 1260 | 1.25 IfcWindowStyle (aken) (IPI ÜBN) | Off | Olemasolev välisaken | RAL 9010 | RAL 9010 | ootel | ootel | ootel | ootel | 1.3734 | 4700 | 0.011804 | 500 | Existing
2 x VA-XX | 1.korrus | 1090 | 1260 | 1.25 IfcWindowStyle (aken) (IPI ÜBN) | Off | Olemasolev välisaken | RAL 9010 | RAL 9010 | ootel | ootel | ootel | ootel | 1.3734 | 4700 | 0.009652 | 500 | Existing
27 x A-1g | 2.korrus | 1910 | 1010 | 1.25 IfcWindowStyle (aken) (IPI ÜBN) | Off | Välisaken | kollane lasuur Teknos T8024 | RAL 1005 ookerkollane | Viking Window | DK22 | ootel | ootel | 1.9291 | 5840 | 0.053156 | 437 | New
AL-1g,EI30 | 2.korrus | 1910 | 1010 | 1.25 IfcWindowStyle (aken) (IPI ÜBN) | Off | Välisaken | RAL 1005 ookerkollane | RAL 1005 ookerkollane | Viking Window | DK22 | ootel | ootel | 1.9291 | 5840 | 0.053156 | 437 | New
SA-06,EI30 | 2.korrus | 1250 | 1500 | 1.25 IfcWindowStyle (aken) (IPI ÜBN) | Off | Siseaken | RAL 9010 | RAL 9010 | ootel | ootel | ootel | ootel | 1.875 | 5500 | 0.02145 | 147 | New | Pset_FireRatingProperties - FireResistanceRating: EI30
3 x SA-05,EI60 | 2.korrus | 1170 | 1200 | Door (ARCHICAD Classification+TK); 1.25 IfcWindowStyle (aken) (IPI ÜBN) | Off | Siseaken | RAL 9010 | RAL 9010 | ootel | ootel | ootel | ootel | 1.404 | 4740 | 0.018315 | 400 | New | Pset_FireRatingProperties - FireResistanceRating: EI60
SA-05,EI60 | 2.korrus | 1170 | 1200 | Door (ARCHICAD Classification+TK); 1.25 IfcWindowStyle (aken) (IPI ÜBN) | Off | Siseaken | RAL 9010 | RAL 9010 | ootel | ootel | ootel | ootel | 1.4002 | 4740 | 0.018315 | 400 | New | Pset_FireRatingProperties - FireResistanceRating: EI60
AL-2,EI60 | 2.korrus | 1710 | 1510 | 1.25 IfcWindowStyle (aken) (IPI ÜBN) | Off | Tulekindel aken | valge | valge | ootel | ootel | valge plekk | valge plastikaknalaud | 2.5821 | 6440 | 0.0462305 | 420 | New | Pset_FireRatingProperties - FireResistanceRating: EI60
AL-2 | 2.korrus | 1710 | 1510 | 1.25 IfcWindowStyle (aken) (IPI ÜBN) | Off | Välisaken | valge | valge | ootel | ootel | valge plekk | valge plastikaknalaud | 2.5821 | 6440 | 0.0462305 | 420 | New
AL-2 | 2.korrus | 1710 | 1510 | 1.25 IfcWindowStyle (aken) (IPI ÜBN) | Off | Tulekindel aken | valge | valge | ootel | ootel | valge plekk | valge plastikaknalaud | 2.5821 | 6440 | 0.0462305 | 420 | New
VR1 | Pööningukorrus | 1050 | 1450 | 1.25 IfcWindowStyle (aken) (IPI ÜBN) |  | Vnetilatsioonirest | RAL 7005 hall | RAL 7005 hall | ootel | ootel | - | - | 1.5225 | 5000 | 0.0228585 | 437 | New
VR2 | Pööningukorrus | 450 | 1370 | 1.25 IfcWindowStyle (aken) (IPI ÜBN) |  | Vnetilatsioonirest | RAL 7005 hall | RAL 7005 hall | ootel | ootel | - | - | 0.6165 | 3640 | 0.0130125 | 437 | New
VR3 | Pööningukorrus | 800 | 2050 | 1.25 IfcWindowStyle (aken) (IPI ÜBN) |  | Vnetilatsioonirest | RAL 7024 tumehall | RAL 7024 tumehall | ootel | ootel | - | - | 1.64 | 5700 | 0.025451 | 249 | New
